VERSION 5.8 ;
BUSBITCHARS "[]" ;
DIVIDERCHAR "/" ;
UNITS
    DATABASE MICRONS 1000 ;
END UNITS

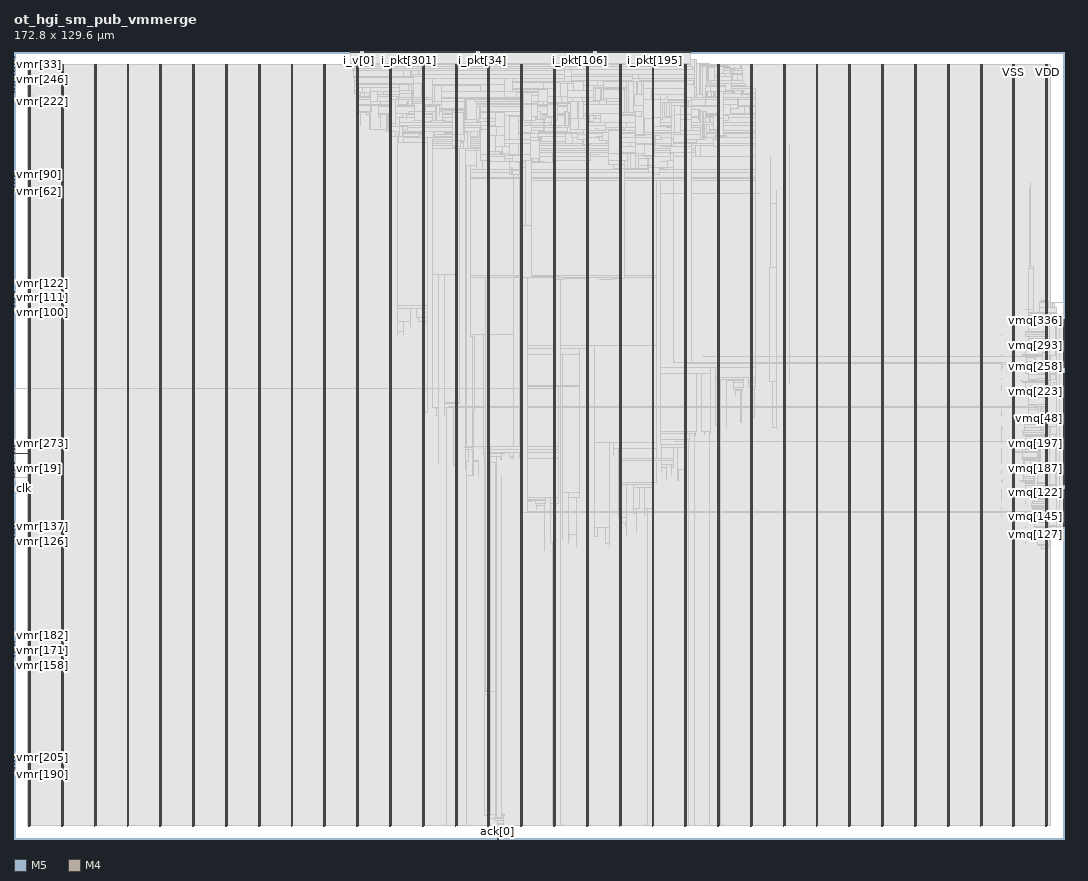
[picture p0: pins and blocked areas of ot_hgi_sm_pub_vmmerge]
MACRO ot_hgi_sm_pub_vmmerge
  FOREIGN ot_hgi_sm_pub_vmmerge 0 0 ;
  CLASS BLOCK ;
  SIZE 172.8 BY 129.6 ;
  PIN ack[0]
    DIRECTION OUTPUT ;
    USE SIGNAL ;
    PORT
      LAYER M5 ;
        RECT  79.632 0 79.656 0.084 ;
    END
  END ack[0]
  PIN ack[1]
    DIRECTION OUTPUT ;
    USE SIGNAL ;
    PORT
      LAYER M5 ;
        RECT  79.728 0 79.752 0.084 ;
    END
  END ack[1]
  PIN active
    DIRECTION OUTPUT ;
    USE SIGNAL ;
    PORT
      LAYER M4 ;
        RECT  172.716 70.608 172.8 70.632 ;
    END
  END active
  PIN clk
    DIRECTION INPUT ;
    USE SIGNAL ;
    PORT
      LAYER M4 ;
        RECT  0 58.992 0.084 59.016 ;
    END
  END clk
  PIN i_pkt[0]
    DIRECTION INPUT ;
    USE SIGNAL ;
    PORT
      LAYER M5 ;
        RECT  60.72 129.516 60.744 129.6 ;
    END
  END i_pkt[0]
  PIN i_pkt[100]
    DIRECTION INPUT ;
    USE SIGNAL ;
    PORT
      LAYER M5 ;
        RECT  92.592 129.516 92.616 129.6 ;
    END
  END i_pkt[100]
  PIN i_pkt[101]
    DIRECTION INPUT ;
    USE SIGNAL ;
    PORT
      LAYER M5 ;
        RECT  92.688 129.516 92.712 129.6 ;
    END
  END i_pkt[101]
  PIN i_pkt[102]
    DIRECTION INPUT ;
    USE SIGNAL ;
    PORT
      LAYER M5 ;
        RECT  92.784 129.516 92.808 129.6 ;
    END
  END i_pkt[102]
  PIN i_pkt[103]
    DIRECTION INPUT ;
    USE SIGNAL ;
    PORT
      LAYER M5 ;
        RECT  92.88 129.516 92.904 129.6 ;
    END
  END i_pkt[103]
  PIN i_pkt[104]
    DIRECTION INPUT ;
    USE SIGNAL ;
    PORT
      LAYER M5 ;
        RECT  92.976 129.516 93 129.6 ;
    END
  END i_pkt[104]
  PIN i_pkt[105]
    DIRECTION INPUT ;
    USE SIGNAL ;
    PORT
      LAYER M5 ;
        RECT  93.072 129.516 93.096 129.6 ;
    END
  END i_pkt[105]
  PIN i_pkt[106]
    DIRECTION INPUT ;
    USE SIGNAL ;
    PORT
      LAYER M5 ;
        RECT  93.168 129.516 93.192 129.6 ;
    END
  END i_pkt[106]
  PIN i_pkt[107]
    DIRECTION INPUT ;
    USE SIGNAL ;
    PORT
      LAYER M5 ;
        RECT  93.264 129.516 93.288 129.6 ;
    END
  END i_pkt[107]
  PIN i_pkt[108]
    DIRECTION INPUT ;
    USE SIGNAL ;
    PORT
      LAYER M5 ;
        RECT  93.36 129.516 93.384 129.6 ;
    END
  END i_pkt[108]
  PIN i_pkt[109]
    DIRECTION INPUT ;
    USE SIGNAL ;
    PORT
      LAYER M5 ;
        RECT  93.456 129.516 93.48 129.6 ;
    END
  END i_pkt[109]
  PIN i_pkt[10]
    DIRECTION INPUT ;
    USE SIGNAL ;
    PORT
      LAYER M5 ;
        RECT  61.68 129.516 61.704 129.6 ;
    END
  END i_pkt[10]
  PIN i_pkt[110]
    DIRECTION INPUT ;
    USE SIGNAL ;
    PORT
      LAYER M5 ;
        RECT  93.552 129.516 93.576 129.6 ;
    END
  END i_pkt[110]
  PIN i_pkt[111]
    DIRECTION INPUT ;
    USE SIGNAL ;
    PORT
      LAYER M5 ;
        RECT  93.648 129.516 93.672 129.6 ;
    END
  END i_pkt[111]
  PIN i_pkt[112]
    DIRECTION INPUT ;
    USE SIGNAL ;
    PORT
      LAYER M5 ;
        RECT  93.744 129.516 93.768 129.6 ;
    END
  END i_pkt[112]
  PIN i_pkt[113]
    DIRECTION INPUT ;
    USE SIGNAL ;
    PORT
      LAYER M5 ;
        RECT  93.84 129.516 93.864 129.6 ;
    END
  END i_pkt[113]
  PIN i_pkt[114]
    DIRECTION INPUT ;
    USE SIGNAL ;
    PORT
      LAYER M5 ;
        RECT  93.936 129.516 93.96 129.6 ;
    END
  END i_pkt[114]
  PIN i_pkt[115]
    DIRECTION INPUT ;
    USE SIGNAL ;
    PORT
      LAYER M5 ;
        RECT  94.032 129.516 94.056 129.6 ;
    END
  END i_pkt[115]
  PIN i_pkt[116]
    DIRECTION INPUT ;
    USE SIGNAL ;
    PORT
      LAYER M5 ;
        RECT  94.128 129.516 94.152 129.6 ;
    END
  END i_pkt[116]
  PIN i_pkt[117]
    DIRECTION INPUT ;
    USE SIGNAL ;
    PORT
      LAYER M5 ;
        RECT  94.224 129.516 94.248 129.6 ;
    END
  END i_pkt[117]
  PIN i_pkt[118]
    DIRECTION INPUT ;
    USE SIGNAL ;
    PORT
      LAYER M5 ;
        RECT  94.32 129.516 94.344 129.6 ;
    END
  END i_pkt[118]
  PIN i_pkt[119]
    DIRECTION INPUT ;
    USE SIGNAL ;
    PORT
      LAYER M5 ;
        RECT  94.416 129.516 94.44 129.6 ;
    END
  END i_pkt[119]
  PIN i_pkt[11]
    DIRECTION INPUT ;
    USE SIGNAL ;
    PORT
      LAYER M5 ;
        RECT  61.776 129.516 61.8 129.6 ;
    END
  END i_pkt[11]
  PIN i_pkt[120]
    DIRECTION INPUT ;
    USE SIGNAL ;
    PORT
      LAYER M5 ;
        RECT  94.512 129.516 94.536 129.6 ;
    END
  END i_pkt[120]
  PIN i_pkt[121]
    DIRECTION INPUT ;
    USE SIGNAL ;
    PORT
      LAYER M5 ;
        RECT  94.608 129.516 94.632 129.6 ;
    END
  END i_pkt[121]
  PIN i_pkt[122]
    DIRECTION INPUT ;
    USE SIGNAL ;
    PORT
      LAYER M5 ;
        RECT  94.704 129.516 94.728 129.6 ;
    END
  END i_pkt[122]
  PIN i_pkt[123]
    DIRECTION INPUT ;
    USE SIGNAL ;
    PORT
      LAYER M5 ;
        RECT  94.8 129.516 94.824 129.6 ;
    END
  END i_pkt[123]
  PIN i_pkt[124]
    DIRECTION INPUT ;
    USE SIGNAL ;
    PORT
      LAYER M5 ;
        RECT  94.896 129.516 94.92 129.6 ;
    END
  END i_pkt[124]
  PIN i_pkt[125]
    DIRECTION INPUT ;
    USE SIGNAL ;
    PORT
      LAYER M5 ;
        RECT  94.992 129.516 95.016 129.6 ;
    END
  END i_pkt[125]
  PIN i_pkt[126]
    DIRECTION INPUT ;
    USE SIGNAL ;
    PORT
      LAYER M5 ;
        RECT  95.088 129.516 95.112 129.6 ;
    END
  END i_pkt[126]
  PIN i_pkt[127]
    DIRECTION INPUT ;
    USE SIGNAL ;
    PORT
      LAYER M5 ;
        RECT  95.184 129.516 95.208 129.6 ;
    END
  END i_pkt[127]
  PIN i_pkt[128]
    DIRECTION INPUT ;
    USE SIGNAL ;
    PORT
      LAYER M5 ;
        RECT  86.064 129.516 86.088 129.6 ;
    END
  END i_pkt[128]
  PIN i_pkt[129]
    DIRECTION INPUT ;
    USE SIGNAL ;
    PORT
      LAYER M5 ;
        RECT  86.16 129.516 86.184 129.6 ;
    END
  END i_pkt[129]
  PIN i_pkt[12]
    DIRECTION INPUT ;
    USE SIGNAL ;
    PORT
      LAYER M5 ;
        RECT  61.872 129.516 61.896 129.6 ;
    END
  END i_pkt[12]
  PIN i_pkt[130]
    DIRECTION INPUT ;
    USE SIGNAL ;
    PORT
      LAYER M5 ;
        RECT  86.256 129.516 86.28 129.6 ;
    END
  END i_pkt[130]
  PIN i_pkt[131]
    DIRECTION INPUT ;
    USE SIGNAL ;
    PORT
      LAYER M5 ;
        RECT  86.352 129.516 86.376 129.6 ;
    END
  END i_pkt[131]
  PIN i_pkt[132]
    DIRECTION INPUT ;
    USE SIGNAL ;
    PORT
      LAYER M5 ;
        RECT  86.448 129.516 86.472 129.6 ;
    END
  END i_pkt[132]
  PIN i_pkt[133]
    DIRECTION INPUT ;
    USE SIGNAL ;
    PORT
      LAYER M5 ;
        RECT  86.544 129.516 86.568 129.6 ;
    END
  END i_pkt[133]
  PIN i_pkt[134]
    DIRECTION INPUT ;
    USE SIGNAL ;
    PORT
      LAYER M5 ;
        RECT  86.64 129.516 86.664 129.6 ;
    END
  END i_pkt[134]
  PIN i_pkt[135]
    DIRECTION INPUT ;
    USE SIGNAL ;
    PORT
      LAYER M5 ;
        RECT  86.736 129.516 86.76 129.6 ;
    END
  END i_pkt[135]
  PIN i_pkt[136]
    DIRECTION INPUT ;
    USE SIGNAL ;
    PORT
      LAYER M5 ;
        RECT  86.832 129.516 86.856 129.6 ;
    END
  END i_pkt[136]
  PIN i_pkt[137]
    DIRECTION INPUT ;
    USE SIGNAL ;
    PORT
      LAYER M5 ;
        RECT  86.928 129.516 86.952 129.6 ;
    END
  END i_pkt[137]
  PIN i_pkt[138]
    DIRECTION INPUT ;
    USE SIGNAL ;
    PORT
      LAYER M5 ;
        RECT  87.024 129.516 87.048 129.6 ;
    END
  END i_pkt[138]
  PIN i_pkt[139]
    DIRECTION INPUT ;
    USE SIGNAL ;
    PORT
      LAYER M5 ;
        RECT  87.12 129.516 87.144 129.6 ;
    END
  END i_pkt[139]
  PIN i_pkt[13]
    DIRECTION INPUT ;
    USE SIGNAL ;
    PORT
      LAYER M5 ;
        RECT  61.968 129.516 61.992 129.6 ;
    END
  END i_pkt[13]
  PIN i_pkt[140]
    DIRECTION INPUT ;
    USE SIGNAL ;
    PORT
      LAYER M5 ;
        RECT  87.216 129.516 87.24 129.6 ;
    END
  END i_pkt[140]
  PIN i_pkt[141]
    DIRECTION INPUT ;
    USE SIGNAL ;
    PORT
      LAYER M5 ;
        RECT  87.312 129.516 87.336 129.6 ;
    END
  END i_pkt[141]
  PIN i_pkt[142]
    DIRECTION INPUT ;
    USE SIGNAL ;
    PORT
      LAYER M5 ;
        RECT  87.408 129.516 87.432 129.6 ;
    END
  END i_pkt[142]
  PIN i_pkt[143]
    DIRECTION INPUT ;
    USE SIGNAL ;
    PORT
      LAYER M5 ;
        RECT  87.504 129.516 87.528 129.6 ;
    END
  END i_pkt[143]
  PIN i_pkt[144]
    DIRECTION INPUT ;
    USE SIGNAL ;
    PORT
      LAYER M5 ;
        RECT  87.6 129.516 87.624 129.6 ;
    END
  END i_pkt[144]
  PIN i_pkt[145]
    DIRECTION INPUT ;
    USE SIGNAL ;
    PORT
      LAYER M5 ;
        RECT  87.696 129.516 87.72 129.6 ;
    END
  END i_pkt[145]
  PIN i_pkt[146]
    DIRECTION INPUT ;
    USE SIGNAL ;
    PORT
      LAYER M5 ;
        RECT  87.792 129.516 87.816 129.6 ;
    END
  END i_pkt[146]
  PIN i_pkt[147]
    DIRECTION INPUT ;
    USE SIGNAL ;
    PORT
      LAYER M5 ;
        RECT  87.888 129.516 87.912 129.6 ;
    END
  END i_pkt[147]
  PIN i_pkt[148]
    DIRECTION INPUT ;
    USE SIGNAL ;
    PORT
      LAYER M5 ;
        RECT  87.984 129.516 88.008 129.6 ;
    END
  END i_pkt[148]
  PIN i_pkt[149]
    DIRECTION INPUT ;
    USE SIGNAL ;
    PORT
      LAYER M5 ;
        RECT  88.08 129.516 88.104 129.6 ;
    END
  END i_pkt[149]
  PIN i_pkt[14]
    DIRECTION INPUT ;
    USE SIGNAL ;
    PORT
      LAYER M5 ;
        RECT  62.064 129.516 62.088 129.6 ;
    END
  END i_pkt[14]
  PIN i_pkt[150]
    DIRECTION INPUT ;
    USE SIGNAL ;
    PORT
      LAYER M5 ;
        RECT  88.176 129.516 88.2 129.6 ;
    END
  END i_pkt[150]
  PIN i_pkt[151]
    DIRECTION INPUT ;
    USE SIGNAL ;
    PORT
      LAYER M5 ;
        RECT  88.272 129.516 88.296 129.6 ;
    END
  END i_pkt[151]
  PIN i_pkt[152]
    DIRECTION INPUT ;
    USE SIGNAL ;
    PORT
      LAYER M5 ;
        RECT  88.368 129.516 88.392 129.6 ;
    END
  END i_pkt[152]
  PIN i_pkt[153]
    DIRECTION INPUT ;
    USE SIGNAL ;
    PORT
      LAYER M5 ;
        RECT  88.464 129.516 88.488 129.6 ;
    END
  END i_pkt[153]
  PIN i_pkt[154]
    DIRECTION INPUT ;
    USE SIGNAL ;
    PORT
      LAYER M5 ;
        RECT  88.56 129.516 88.584 129.6 ;
    END
  END i_pkt[154]
  PIN i_pkt[155]
    DIRECTION INPUT ;
    USE SIGNAL ;
    PORT
      LAYER M5 ;
        RECT  88.656 129.516 88.68 129.6 ;
    END
  END i_pkt[155]
  PIN i_pkt[156]
    DIRECTION INPUT ;
    USE SIGNAL ;
    PORT
      LAYER M5 ;
        RECT  88.752 129.516 88.776 129.6 ;
    END
  END i_pkt[156]
  PIN i_pkt[157]
    DIRECTION INPUT ;
    USE SIGNAL ;
    PORT
      LAYER M5 ;
        RECT  88.848 129.516 88.872 129.6 ;
    END
  END i_pkt[157]
  PIN i_pkt[158]
    DIRECTION INPUT ;
    USE SIGNAL ;
    PORT
      LAYER M5 ;
        RECT  88.944 129.516 88.968 129.6 ;
    END
  END i_pkt[158]
  PIN i_pkt[159]
    DIRECTION INPUT ;
    USE SIGNAL ;
    PORT
      LAYER M5 ;
        RECT  89.04 129.516 89.064 129.6 ;
    END
  END i_pkt[159]
  PIN i_pkt[15]
    DIRECTION INPUT ;
    USE SIGNAL ;
    PORT
      LAYER M5 ;
        RECT  62.16 129.516 62.184 129.6 ;
    END
  END i_pkt[15]
  PIN i_pkt[160]
    DIRECTION INPUT ;
    USE SIGNAL ;
    PORT
      LAYER M5 ;
        RECT  89.136 129.516 89.16 129.6 ;
    END
  END i_pkt[160]
  PIN i_pkt[161]
    DIRECTION INPUT ;
    USE SIGNAL ;
    PORT
      LAYER M5 ;
        RECT  89.232 129.516 89.256 129.6 ;
    END
  END i_pkt[161]
  PIN i_pkt[162]
    DIRECTION INPUT ;
    USE SIGNAL ;
    PORT
      LAYER M5 ;
        RECT  89.328 129.516 89.352 129.6 ;
    END
  END i_pkt[162]
  PIN i_pkt[163]
    DIRECTION INPUT ;
    USE SIGNAL ;
    PORT
      LAYER M5 ;
        RECT  89.424 129.516 89.448 129.6 ;
    END
  END i_pkt[163]
  PIN i_pkt[164]
    DIRECTION INPUT ;
    USE SIGNAL ;
    PORT
      LAYER M5 ;
        RECT  89.52 129.516 89.544 129.6 ;
    END
  END i_pkt[164]
  PIN i_pkt[165]
    DIRECTION INPUT ;
    USE SIGNAL ;
    PORT
      LAYER M5 ;
        RECT  89.616 129.516 89.64 129.6 ;
    END
  END i_pkt[165]
  PIN i_pkt[166]
    DIRECTION INPUT ;
    USE SIGNAL ;
    PORT
      LAYER M5 ;
        RECT  89.712 129.516 89.736 129.6 ;
    END
  END i_pkt[166]
  PIN i_pkt[167]
    DIRECTION INPUT ;
    USE SIGNAL ;
    PORT
      LAYER M5 ;
        RECT  89.808 129.516 89.832 129.6 ;
    END
  END i_pkt[167]
  PIN i_pkt[168]
    DIRECTION INPUT ;
    USE SIGNAL ;
    PORT
      LAYER M5 ;
        RECT  89.904 129.516 89.928 129.6 ;
    END
  END i_pkt[168]
  PIN i_pkt[169]
    DIRECTION INPUT ;
    USE SIGNAL ;
    PORT
      LAYER M5 ;
        RECT  90 129.516 90.024 129.6 ;
    END
  END i_pkt[169]
  PIN i_pkt[16]
    DIRECTION INPUT ;
    USE SIGNAL ;
    PORT
      LAYER M5 ;
        RECT  62.256 129.516 62.28 129.6 ;
    END
  END i_pkt[16]
  PIN i_pkt[170]
    DIRECTION INPUT ;
    USE SIGNAL ;
    PORT
      LAYER M5 ;
        RECT  90.096 129.516 90.12 129.6 ;
    END
  END i_pkt[170]
  PIN i_pkt[171]
    DIRECTION INPUT ;
    USE SIGNAL ;
    PORT
      LAYER M5 ;
        RECT  90.192 129.516 90.216 129.6 ;
    END
  END i_pkt[171]
  PIN i_pkt[172]
    DIRECTION INPUT ;
    USE SIGNAL ;
    PORT
      LAYER M5 ;
        RECT  90.288 129.516 90.312 129.6 ;
    END
  END i_pkt[172]
  PIN i_pkt[173]
    DIRECTION INPUT ;
    USE SIGNAL ;
    PORT
      LAYER M5 ;
        RECT  90.384 129.516 90.408 129.6 ;
    END
  END i_pkt[173]
  PIN i_pkt[174]
    DIRECTION INPUT ;
    USE SIGNAL ;
    PORT
      LAYER M5 ;
        RECT  90.48 129.516 90.504 129.6 ;
    END
  END i_pkt[174]
  PIN i_pkt[175]
    DIRECTION INPUT ;
    USE SIGNAL ;
    PORT
      LAYER M5 ;
        RECT  90.576 129.516 90.6 129.6 ;
    END
  END i_pkt[175]
  PIN i_pkt[176]
    DIRECTION INPUT ;
    USE SIGNAL ;
    PORT
      LAYER M5 ;
        RECT  90.672 129.516 90.696 129.6 ;
    END
  END i_pkt[176]
  PIN i_pkt[177]
    DIRECTION INPUT ;
    USE SIGNAL ;
    PORT
      LAYER M5 ;
        RECT  90.768 129.516 90.792 129.6 ;
    END
  END i_pkt[177]
  PIN i_pkt[178]
    DIRECTION INPUT ;
    USE SIGNAL ;
    PORT
      LAYER M5 ;
        RECT  90.864 129.516 90.888 129.6 ;
    END
  END i_pkt[178]
  PIN i_pkt[179]
    DIRECTION INPUT ;
    USE SIGNAL ;
    PORT
      LAYER M5 ;
        RECT  90.96 129.516 90.984 129.6 ;
    END
  END i_pkt[179]
  PIN i_pkt[17]
    DIRECTION INPUT ;
    USE SIGNAL ;
    PORT
      LAYER M5 ;
        RECT  62.352 129.516 62.376 129.6 ;
    END
  END i_pkt[17]
  PIN i_pkt[180]
    DIRECTION INPUT ;
    USE SIGNAL ;
    PORT
      LAYER M5 ;
        RECT  91.056 129.516 91.08 129.6 ;
    END
  END i_pkt[180]
  PIN i_pkt[181]
    DIRECTION INPUT ;
    USE SIGNAL ;
    PORT
      LAYER M5 ;
        RECT  91.152 129.516 91.176 129.6 ;
    END
  END i_pkt[181]
  PIN i_pkt[182]
    DIRECTION INPUT ;
    USE SIGNAL ;
    PORT
      LAYER M5 ;
        RECT  91.248 129.516 91.272 129.6 ;
    END
  END i_pkt[182]
  PIN i_pkt[183]
    DIRECTION INPUT ;
    USE SIGNAL ;
    PORT
      LAYER M5 ;
        RECT  91.344 129.516 91.368 129.6 ;
    END
  END i_pkt[183]
  PIN i_pkt[184]
    DIRECTION INPUT ;
    USE SIGNAL ;
    PORT
      LAYER M5 ;
        RECT  91.44 129.516 91.464 129.6 ;
    END
  END i_pkt[184]
  PIN i_pkt[185]
    DIRECTION INPUT ;
    USE SIGNAL ;
    PORT
      LAYER M5 ;
        RECT  91.536 129.516 91.56 129.6 ;
    END
  END i_pkt[185]
  PIN i_pkt[186]
    DIRECTION INPUT ;
    USE SIGNAL ;
    PORT
      LAYER M5 ;
        RECT  91.632 129.516 91.656 129.6 ;
    END
  END i_pkt[186]
  PIN i_pkt[187]
    DIRECTION INPUT ;
    USE SIGNAL ;
    PORT
      LAYER M5 ;
        RECT  91.728 129.516 91.752 129.6 ;
    END
  END i_pkt[187]
  PIN i_pkt[188]
    DIRECTION INPUT ;
    USE SIGNAL ;
    PORT
      LAYER M5 ;
        RECT  91.824 129.516 91.848 129.6 ;
    END
  END i_pkt[188]
  PIN i_pkt[189]
    DIRECTION INPUT ;
    USE SIGNAL ;
    PORT
      LAYER M5 ;
        RECT  91.92 129.516 91.944 129.6 ;
    END
  END i_pkt[189]
  PIN i_pkt[18]
    DIRECTION INPUT ;
    USE SIGNAL ;
    PORT
      LAYER M5 ;
        RECT  62.448 129.516 62.472 129.6 ;
    END
  END i_pkt[18]
  PIN i_pkt[190]
    DIRECTION INPUT ;
    USE SIGNAL ;
    PORT
      LAYER M5 ;
        RECT  92.016 129.516 92.04 129.6 ;
    END
  END i_pkt[190]
  PIN i_pkt[191]
    DIRECTION INPUT ;
    USE SIGNAL ;
    PORT
      LAYER M5 ;
        RECT  92.112 129.516 92.136 129.6 ;
    END
  END i_pkt[191]
  PIN i_pkt[192]
    DIRECTION INPUT ;
    USE SIGNAL ;
    PORT
      LAYER M5 ;
        RECT  105.264 129.516 105.288 129.6 ;
    END
  END i_pkt[192]
  PIN i_pkt[193]
    DIRECTION INPUT ;
    USE SIGNAL ;
    PORT
      LAYER M5 ;
        RECT  105.36 129.516 105.384 129.6 ;
    END
  END i_pkt[193]
  PIN i_pkt[194]
    DIRECTION INPUT ;
    USE SIGNAL ;
    PORT
      LAYER M5 ;
        RECT  105.456 129.516 105.48 129.6 ;
    END
  END i_pkt[194]
  PIN i_pkt[195]
    DIRECTION INPUT ;
    USE SIGNAL ;
    PORT
      LAYER M5 ;
        RECT  105.552 129.516 105.576 129.6 ;
    END
  END i_pkt[195]
  PIN i_pkt[196]
    DIRECTION INPUT ;
    USE SIGNAL ;
    PORT
      LAYER M5 ;
        RECT  105.648 129.516 105.672 129.6 ;
    END
  END i_pkt[196]
  PIN i_pkt[197]
    DIRECTION INPUT ;
    USE SIGNAL ;
    PORT
      LAYER M5 ;
        RECT  105.744 129.516 105.768 129.6 ;
    END
  END i_pkt[197]
  PIN i_pkt[198]
    DIRECTION INPUT ;
    USE SIGNAL ;
    PORT
      LAYER M5 ;
        RECT  105.84 129.516 105.864 129.6 ;
    END
  END i_pkt[198]
  PIN i_pkt[199]
    DIRECTION INPUT ;
    USE SIGNAL ;
    PORT
      LAYER M5 ;
        RECT  105.936 129.516 105.96 129.6 ;
    END
  END i_pkt[199]
  PIN i_pkt[19]
    DIRECTION INPUT ;
    USE SIGNAL ;
    PORT
      LAYER M5 ;
        RECT  62.544 129.516 62.568 129.6 ;
    END
  END i_pkt[19]
  PIN i_pkt[1]
    DIRECTION INPUT ;
    USE SIGNAL ;
    PORT
      LAYER M5 ;
        RECT  60.816 129.516 60.84 129.6 ;
    END
  END i_pkt[1]
  PIN i_pkt[200]
    DIRECTION INPUT ;
    USE SIGNAL ;
    PORT
      LAYER M5 ;
        RECT  106.032 129.516 106.056 129.6 ;
    END
  END i_pkt[200]
  PIN i_pkt[201]
    DIRECTION INPUT ;
    USE SIGNAL ;
    PORT
      LAYER M5 ;
        RECT  106.128 129.516 106.152 129.6 ;
    END
  END i_pkt[201]
  PIN i_pkt[202]
    DIRECTION INPUT ;
    USE SIGNAL ;
    PORT
      LAYER M5 ;
        RECT  106.224 129.516 106.248 129.6 ;
    END
  END i_pkt[202]
  PIN i_pkt[203]
    DIRECTION INPUT ;
    USE SIGNAL ;
    PORT
      LAYER M5 ;
        RECT  106.32 129.516 106.344 129.6 ;
    END
  END i_pkt[203]
  PIN i_pkt[204]
    DIRECTION INPUT ;
    USE SIGNAL ;
    PORT
      LAYER M5 ;
        RECT  106.416 129.516 106.44 129.6 ;
    END
  END i_pkt[204]
  PIN i_pkt[205]
    DIRECTION INPUT ;
    USE SIGNAL ;
    PORT
      LAYER M5 ;
        RECT  106.512 129.516 106.536 129.6 ;
    END
  END i_pkt[205]
  PIN i_pkt[206]
    DIRECTION INPUT ;
    USE SIGNAL ;
    PORT
      LAYER M5 ;
        RECT  106.608 129.516 106.632 129.6 ;
    END
  END i_pkt[206]
  PIN i_pkt[207]
    DIRECTION INPUT ;
    USE SIGNAL ;
    PORT
      LAYER M5 ;
        RECT  106.704 129.516 106.728 129.6 ;
    END
  END i_pkt[207]
  PIN i_pkt[208]
    DIRECTION INPUT ;
    USE SIGNAL ;
    PORT
      LAYER M5 ;
        RECT  106.8 129.516 106.824 129.6 ;
    END
  END i_pkt[208]
  PIN i_pkt[209]
    DIRECTION INPUT ;
    USE SIGNAL ;
    PORT
      LAYER M5 ;
        RECT  106.896 129.516 106.92 129.6 ;
    END
  END i_pkt[209]
  PIN i_pkt[20]
    DIRECTION INPUT ;
    USE SIGNAL ;
    PORT
      LAYER M5 ;
        RECT  62.64 129.516 62.664 129.6 ;
    END
  END i_pkt[20]
  PIN i_pkt[210]
    DIRECTION INPUT ;
    USE SIGNAL ;
    PORT
      LAYER M5 ;
        RECT  106.992 129.516 107.016 129.6 ;
    END
  END i_pkt[210]
  PIN i_pkt[211]
    DIRECTION INPUT ;
    USE SIGNAL ;
    PORT
      LAYER M5 ;
        RECT  107.088 129.516 107.112 129.6 ;
    END
  END i_pkt[211]
  PIN i_pkt[212]
    DIRECTION INPUT ;
    USE SIGNAL ;
    PORT
      LAYER M5 ;
        RECT  107.184 129.516 107.208 129.6 ;
    END
  END i_pkt[212]
  PIN i_pkt[213]
    DIRECTION INPUT ;
    USE SIGNAL ;
    PORT
      LAYER M5 ;
        RECT  107.28 129.516 107.304 129.6 ;
    END
  END i_pkt[213]
  PIN i_pkt[214]
    DIRECTION INPUT ;
    USE SIGNAL ;
    PORT
      LAYER M5 ;
        RECT  107.376 129.516 107.4 129.6 ;
    END
  END i_pkt[214]
  PIN i_pkt[215]
    DIRECTION INPUT ;
    USE SIGNAL ;
    PORT
      LAYER M5 ;
        RECT  107.472 129.516 107.496 129.6 ;
    END
  END i_pkt[215]
  PIN i_pkt[216]
    DIRECTION INPUT ;
    USE SIGNAL ;
    PORT
      LAYER M5 ;
        RECT  107.568 129.516 107.592 129.6 ;
    END
  END i_pkt[216]
  PIN i_pkt[217]
    DIRECTION INPUT ;
    USE SIGNAL ;
    PORT
      LAYER M5 ;
        RECT  107.664 129.516 107.688 129.6 ;
    END
  END i_pkt[217]
  PIN i_pkt[218]
    DIRECTION INPUT ;
    USE SIGNAL ;
    PORT
      LAYER M5 ;
        RECT  107.76 129.516 107.784 129.6 ;
    END
  END i_pkt[218]
  PIN i_pkt[219]
    DIRECTION INPUT ;
    USE SIGNAL ;
    PORT
      LAYER M5 ;
        RECT  107.856 129.516 107.88 129.6 ;
    END
  END i_pkt[219]
  PIN i_pkt[21]
    DIRECTION INPUT ;
    USE SIGNAL ;
    PORT
      LAYER M5 ;
        RECT  62.736 129.516 62.76 129.6 ;
    END
  END i_pkt[21]
  PIN i_pkt[220]
    DIRECTION INPUT ;
    USE SIGNAL ;
    PORT
      LAYER M5 ;
        RECT  107.952 129.516 107.976 129.6 ;
    END
  END i_pkt[220]
  PIN i_pkt[221]
    DIRECTION INPUT ;
    USE SIGNAL ;
    PORT
      LAYER M5 ;
        RECT  108.048 129.516 108.072 129.6 ;
    END
  END i_pkt[221]
  PIN i_pkt[222]
    DIRECTION INPUT ;
    USE SIGNAL ;
    PORT
      LAYER M5 ;
        RECT  108.144 129.516 108.168 129.6 ;
    END
  END i_pkt[222]
  PIN i_pkt[223]
    DIRECTION INPUT ;
    USE SIGNAL ;
    PORT
      LAYER M5 ;
        RECT  108.24 129.516 108.264 129.6 ;
    END
  END i_pkt[223]
  PIN i_pkt[224]
    DIRECTION INPUT ;
    USE SIGNAL ;
    PORT
      LAYER M5 ;
        RECT  82.992 129.516 83.016 129.6 ;
    END
  END i_pkt[224]
  PIN i_pkt[225]
    DIRECTION INPUT ;
    USE SIGNAL ;
    PORT
      LAYER M5 ;
        RECT  83.088 129.516 83.112 129.6 ;
    END
  END i_pkt[225]
  PIN i_pkt[226]
    DIRECTION INPUT ;
    USE SIGNAL ;
    PORT
      LAYER M5 ;
        RECT  83.184 129.516 83.208 129.6 ;
    END
  END i_pkt[226]
  PIN i_pkt[227]
    DIRECTION INPUT ;
    USE SIGNAL ;
    PORT
      LAYER M5 ;
        RECT  83.28 129.516 83.304 129.6 ;
    END
  END i_pkt[227]
  PIN i_pkt[228]
    DIRECTION INPUT ;
    USE SIGNAL ;
    PORT
      LAYER M5 ;
        RECT  83.376 129.516 83.4 129.6 ;
    END
  END i_pkt[228]
  PIN i_pkt[229]
    DIRECTION INPUT ;
    USE SIGNAL ;
    PORT
      LAYER M5 ;
        RECT  83.472 129.516 83.496 129.6 ;
    END
  END i_pkt[229]
  PIN i_pkt[22]
    DIRECTION INPUT ;
    USE SIGNAL ;
    PORT
      LAYER M5 ;
        RECT  62.832 129.516 62.856 129.6 ;
    END
  END i_pkt[22]
  PIN i_pkt[230]
    DIRECTION INPUT ;
    USE SIGNAL ;
    PORT
      LAYER M5 ;
        RECT  83.568 129.516 83.592 129.6 ;
    END
  END i_pkt[230]
  PIN i_pkt[231]
    DIRECTION INPUT ;
    USE SIGNAL ;
    PORT
      LAYER M5 ;
        RECT  83.664 129.516 83.688 129.6 ;
    END
  END i_pkt[231]
  PIN i_pkt[232]
    DIRECTION INPUT ;
    USE SIGNAL ;
    PORT
      LAYER M5 ;
        RECT  83.76 129.516 83.784 129.6 ;
    END
  END i_pkt[232]
  PIN i_pkt[233]
    DIRECTION INPUT ;
    USE SIGNAL ;
    PORT
      LAYER M5 ;
        RECT  83.856 129.516 83.88 129.6 ;
    END
  END i_pkt[233]
  PIN i_pkt[234]
    DIRECTION INPUT ;
    USE SIGNAL ;
    PORT
      LAYER M5 ;
        RECT  83.952 129.516 83.976 129.6 ;
    END
  END i_pkt[234]
  PIN i_pkt[235]
    DIRECTION INPUT ;
    USE SIGNAL ;
    PORT
      LAYER M5 ;
        RECT  84.048 129.516 84.072 129.6 ;
    END
  END i_pkt[235]
  PIN i_pkt[236]
    DIRECTION INPUT ;
    USE SIGNAL ;
    PORT
      LAYER M5 ;
        RECT  84.144 129.516 84.168 129.6 ;
    END
  END i_pkt[236]
  PIN i_pkt[237]
    DIRECTION INPUT ;
    USE SIGNAL ;
    PORT
      LAYER M5 ;
        RECT  84.24 129.516 84.264 129.6 ;
    END
  END i_pkt[237]
  PIN i_pkt[238]
    DIRECTION INPUT ;
    USE SIGNAL ;
    PORT
      LAYER M5 ;
        RECT  84.336 129.516 84.36 129.6 ;
    END
  END i_pkt[238]
  PIN i_pkt[239]
    DIRECTION INPUT ;
    USE SIGNAL ;
    PORT
      LAYER M5 ;
        RECT  84.432 129.516 84.456 129.6 ;
    END
  END i_pkt[239]
  PIN i_pkt[23]
    DIRECTION INPUT ;
    USE SIGNAL ;
    PORT
      LAYER M5 ;
        RECT  62.928 129.516 62.952 129.6 ;
    END
  END i_pkt[23]
  PIN i_pkt[240]
    DIRECTION INPUT ;
    USE SIGNAL ;
    PORT
      LAYER M5 ;
        RECT  84.528 129.516 84.552 129.6 ;
    END
  END i_pkt[240]
  PIN i_pkt[241]
    DIRECTION INPUT ;
    USE SIGNAL ;
    PORT
      LAYER M5 ;
        RECT  84.624 129.516 84.648 129.6 ;
    END
  END i_pkt[241]
  PIN i_pkt[242]
    DIRECTION INPUT ;
    USE SIGNAL ;
    PORT
      LAYER M5 ;
        RECT  84.72 129.516 84.744 129.6 ;
    END
  END i_pkt[242]
  PIN i_pkt[243]
    DIRECTION INPUT ;
    USE SIGNAL ;
    PORT
      LAYER M5 ;
        RECT  84.816 129.516 84.84 129.6 ;
    END
  END i_pkt[243]
  PIN i_pkt[244]
    DIRECTION INPUT ;
    USE SIGNAL ;
    PORT
      LAYER M5 ;
        RECT  84.912 129.516 84.936 129.6 ;
    END
  END i_pkt[244]
  PIN i_pkt[245]
    DIRECTION INPUT ;
    USE SIGNAL ;
    PORT
      LAYER M5 ;
        RECT  85.008 129.516 85.032 129.6 ;
    END
  END i_pkt[245]
  PIN i_pkt[246]
    DIRECTION INPUT ;
    USE SIGNAL ;
    PORT
      LAYER M5 ;
        RECT  85.104 129.516 85.128 129.6 ;
    END
  END i_pkt[246]
  PIN i_pkt[247]
    DIRECTION INPUT ;
    USE SIGNAL ;
    PORT
      LAYER M5 ;
        RECT  85.2 129.516 85.224 129.6 ;
    END
  END i_pkt[247]
  PIN i_pkt[248]
    DIRECTION INPUT ;
    USE SIGNAL ;
    PORT
      LAYER M5 ;
        RECT  85.296 129.516 85.32 129.6 ;
    END
  END i_pkt[248]
  PIN i_pkt[249]
    DIRECTION INPUT ;
    USE SIGNAL ;
    PORT
      LAYER M5 ;
        RECT  85.392 129.516 85.416 129.6 ;
    END
  END i_pkt[249]
  PIN i_pkt[24]
    DIRECTION INPUT ;
    USE SIGNAL ;
    PORT
      LAYER M5 ;
        RECT  63.024 129.516 63.048 129.6 ;
    END
  END i_pkt[24]
  PIN i_pkt[250]
    DIRECTION INPUT ;
    USE SIGNAL ;
    PORT
      LAYER M5 ;
        RECT  85.488 129.516 85.512 129.6 ;
    END
  END i_pkt[250]
  PIN i_pkt[251]
    DIRECTION INPUT ;
    USE SIGNAL ;
    PORT
      LAYER M5 ;
        RECT  85.584 129.516 85.608 129.6 ;
    END
  END i_pkt[251]
  PIN i_pkt[252]
    DIRECTION INPUT ;
    USE SIGNAL ;
    PORT
      LAYER M5 ;
        RECT  85.68 129.516 85.704 129.6 ;
    END
  END i_pkt[252]
  PIN i_pkt[253]
    DIRECTION INPUT ;
    USE SIGNAL ;
    PORT
      LAYER M5 ;
        RECT  85.776 129.516 85.8 129.6 ;
    END
  END i_pkt[253]
  PIN i_pkt[254]
    DIRECTION INPUT ;
    USE SIGNAL ;
    PORT
      LAYER M5 ;
        RECT  85.872 129.516 85.896 129.6 ;
    END
  END i_pkt[254]
  PIN i_pkt[255]
    DIRECTION INPUT ;
    USE SIGNAL ;
    PORT
      LAYER M5 ;
        RECT  85.968 129.516 85.992 129.6 ;
    END
  END i_pkt[255]
  PIN i_pkt[256]
    DIRECTION INPUT ;
    USE SIGNAL ;
    PORT
      LAYER M5 ;
        RECT  57.648 129.516 57.672 129.6 ;
    END
  END i_pkt[256]
  PIN i_pkt[257]
    DIRECTION INPUT ;
    USE SIGNAL ;
    PORT
      LAYER M5 ;
        RECT  57.744 129.516 57.768 129.6 ;
    END
  END i_pkt[257]
  PIN i_pkt[258]
    DIRECTION INPUT ;
    USE SIGNAL ;
    PORT
      LAYER M5 ;
        RECT  57.84 129.516 57.864 129.6 ;
    END
  END i_pkt[258]
  PIN i_pkt[259]
    DIRECTION INPUT ;
    USE SIGNAL ;
    PORT
      LAYER M5 ;
        RECT  57.936 129.516 57.96 129.6 ;
    END
  END i_pkt[259]
  PIN i_pkt[25]
    DIRECTION INPUT ;
    USE SIGNAL ;
    PORT
      LAYER M5 ;
        RECT  63.12 129.516 63.144 129.6 ;
    END
  END i_pkt[25]
  PIN i_pkt[260]
    DIRECTION INPUT ;
    USE SIGNAL ;
    PORT
      LAYER M5 ;
        RECT  58.032 129.516 58.056 129.6 ;
    END
  END i_pkt[260]
  PIN i_pkt[261]
    DIRECTION INPUT ;
    USE SIGNAL ;
    PORT
      LAYER M5 ;
        RECT  58.128 129.516 58.152 129.6 ;
    END
  END i_pkt[261]
  PIN i_pkt[262]
    DIRECTION INPUT ;
    USE SIGNAL ;
    PORT
      LAYER M5 ;
        RECT  58.224 129.516 58.248 129.6 ;
    END
  END i_pkt[262]
  PIN i_pkt[263]
    DIRECTION INPUT ;
    USE SIGNAL ;
    PORT
      LAYER M5 ;
        RECT  58.32 129.516 58.344 129.6 ;
    END
  END i_pkt[263]
  PIN i_pkt[264]
    DIRECTION INPUT ;
    USE SIGNAL ;
    PORT
      LAYER M5 ;
        RECT  58.416 129.516 58.44 129.6 ;
    END
  END i_pkt[264]
  PIN i_pkt[265]
    DIRECTION INPUT ;
    USE SIGNAL ;
    PORT
      LAYER M5 ;
        RECT  58.512 129.516 58.536 129.6 ;
    END
  END i_pkt[265]
  PIN i_pkt[266]
    DIRECTION INPUT ;
    USE SIGNAL ;
    PORT
      LAYER M5 ;
        RECT  58.608 129.516 58.632 129.6 ;
    END
  END i_pkt[266]
  PIN i_pkt[267]
    DIRECTION INPUT ;
    USE SIGNAL ;
    PORT
      LAYER M5 ;
        RECT  58.704 129.516 58.728 129.6 ;
    END
  END i_pkt[267]
  PIN i_pkt[268]
    DIRECTION INPUT ;
    USE SIGNAL ;
    PORT
      LAYER M5 ;
        RECT  58.8 129.516 58.824 129.6 ;
    END
  END i_pkt[268]
  PIN i_pkt[269]
    DIRECTION INPUT ;
    USE SIGNAL ;
    PORT
      LAYER M5 ;
        RECT  58.896 129.516 58.92 129.6 ;
    END
  END i_pkt[269]
  PIN i_pkt[26]
    DIRECTION INPUT ;
    USE SIGNAL ;
    PORT
      LAYER M5 ;
        RECT  63.216 129.516 63.24 129.6 ;
    END
  END i_pkt[26]
  PIN i_pkt[270]
    DIRECTION INPUT ;
    USE SIGNAL ;
    PORT
      LAYER M5 ;
        RECT  58.992 129.516 59.016 129.6 ;
    END
  END i_pkt[270]
  PIN i_pkt[271]
    DIRECTION INPUT ;
    USE SIGNAL ;
    PORT
      LAYER M5 ;
        RECT  59.088 129.516 59.112 129.6 ;
    END
  END i_pkt[271]
  PIN i_pkt[272]
    DIRECTION INPUT ;
    USE SIGNAL ;
    PORT
      LAYER M5 ;
        RECT  59.184 129.516 59.208 129.6 ;
    END
  END i_pkt[272]
  PIN i_pkt[273]
    DIRECTION INPUT ;
    USE SIGNAL ;
    PORT
      LAYER M5 ;
        RECT  59.28 129.516 59.304 129.6 ;
    END
  END i_pkt[273]
  PIN i_pkt[274]
    DIRECTION INPUT ;
    USE SIGNAL ;
    PORT
      LAYER M5 ;
        RECT  59.376 129.516 59.4 129.6 ;
    END
  END i_pkt[274]
  PIN i_pkt[275]
    DIRECTION INPUT ;
    USE SIGNAL ;
    PORT
      LAYER M5 ;
        RECT  59.472 129.516 59.496 129.6 ;
    END
  END i_pkt[275]
  PIN i_pkt[276]
    DIRECTION INPUT ;
    USE SIGNAL ;
    PORT
      LAYER M5 ;
        RECT  59.568 129.516 59.592 129.6 ;
    END
  END i_pkt[276]
  PIN i_pkt[277]
    DIRECTION INPUT ;
    USE SIGNAL ;
    PORT
      LAYER M5 ;
        RECT  59.664 129.516 59.688 129.6 ;
    END
  END i_pkt[277]
  PIN i_pkt[278]
    DIRECTION INPUT ;
    USE SIGNAL ;
    PORT
      LAYER M5 ;
        RECT  59.76 129.516 59.784 129.6 ;
    END
  END i_pkt[278]
  PIN i_pkt[279]
    DIRECTION INPUT ;
    USE SIGNAL ;
    PORT
      LAYER M5 ;
        RECT  59.856 129.516 59.88 129.6 ;
    END
  END i_pkt[279]
  PIN i_pkt[27]
    DIRECTION INPUT ;
    USE SIGNAL ;
    PORT
      LAYER M5 ;
        RECT  63.312 129.516 63.336 129.6 ;
    END
  END i_pkt[27]
  PIN i_pkt[280]
    DIRECTION INPUT ;
    USE SIGNAL ;
    PORT
      LAYER M5 ;
        RECT  59.952 129.516 59.976 129.6 ;
    END
  END i_pkt[280]
  PIN i_pkt[281]
    DIRECTION INPUT ;
    USE SIGNAL ;
    PORT
      LAYER M5 ;
        RECT  60.048 129.516 60.072 129.6 ;
    END
  END i_pkt[281]
  PIN i_pkt[282]
    DIRECTION INPUT ;
    USE SIGNAL ;
    PORT
      LAYER M5 ;
        RECT  60.144 129.516 60.168 129.6 ;
    END
  END i_pkt[282]
  PIN i_pkt[283]
    DIRECTION INPUT ;
    USE SIGNAL ;
    PORT
      LAYER M5 ;
        RECT  60.24 129.516 60.264 129.6 ;
    END
  END i_pkt[283]
  PIN i_pkt[284]
    DIRECTION INPUT ;
    USE SIGNAL ;
    PORT
      LAYER M5 ;
        RECT  60.336 129.516 60.36 129.6 ;
    END
  END i_pkt[284]
  PIN i_pkt[285]
    DIRECTION INPUT ;
    USE SIGNAL ;
    PORT
      LAYER M5 ;
        RECT  60.432 129.516 60.456 129.6 ;
    END
  END i_pkt[285]
  PIN i_pkt[286]
    DIRECTION INPUT ;
    USE SIGNAL ;
    PORT
      LAYER M5 ;
        RECT  60.528 129.516 60.552 129.6 ;
    END
  END i_pkt[286]
  PIN i_pkt[287]
    DIRECTION INPUT ;
    USE SIGNAL ;
    PORT
      LAYER M5 ;
        RECT  60.624 129.516 60.648 129.6 ;
    END
  END i_pkt[287]
  PIN i_pkt[288]
    DIRECTION INPUT ;
    USE SIGNAL ;
    PORT
      LAYER M5 ;
        RECT  63.792 129.516 63.816 129.6 ;
    END
  END i_pkt[288]
  PIN i_pkt[289]
    DIRECTION INPUT ;
    USE SIGNAL ;
    PORT
      LAYER M5 ;
        RECT  63.888 129.516 63.912 129.6 ;
    END
  END i_pkt[289]
  PIN i_pkt[28]
    DIRECTION INPUT ;
    USE SIGNAL ;
    PORT
      LAYER M5 ;
        RECT  63.408 129.516 63.432 129.6 ;
    END
  END i_pkt[28]
  PIN i_pkt[290]
    DIRECTION INPUT ;
    USE SIGNAL ;
    PORT
      LAYER M5 ;
        RECT  63.984 129.516 64.008 129.6 ;
    END
  END i_pkt[290]
  PIN i_pkt[291]
    DIRECTION INPUT ;
    USE SIGNAL ;
    PORT
      LAYER M5 ;
        RECT  64.08 129.516 64.104 129.6 ;
    END
  END i_pkt[291]
  PIN i_pkt[292]
    DIRECTION INPUT ;
    USE SIGNAL ;
    PORT
      LAYER M5 ;
        RECT  64.176 129.516 64.2 129.6 ;
    END
  END i_pkt[292]
  PIN i_pkt[293]
    DIRECTION INPUT ;
    USE SIGNAL ;
    PORT
      LAYER M5 ;
        RECT  64.272 129.516 64.296 129.6 ;
    END
  END i_pkt[293]
  PIN i_pkt[294]
    DIRECTION INPUT ;
    USE SIGNAL ;
    PORT
      LAYER M5 ;
        RECT  64.368 129.516 64.392 129.6 ;
    END
  END i_pkt[294]
  PIN i_pkt[295]
    DIRECTION INPUT ;
    USE SIGNAL ;
    PORT
      LAYER M5 ;
        RECT  64.464 129.516 64.488 129.6 ;
    END
  END i_pkt[295]
  PIN i_pkt[296]
    DIRECTION INPUT ;
    USE SIGNAL ;
    PORT
      LAYER M5 ;
        RECT  64.56 129.516 64.584 129.6 ;
    END
  END i_pkt[296]
  PIN i_pkt[297]
    DIRECTION INPUT ;
    USE SIGNAL ;
    PORT
      LAYER M5 ;
        RECT  64.656 129.516 64.68 129.6 ;
    END
  END i_pkt[297]
  PIN i_pkt[298]
    DIRECTION INPUT ;
    USE SIGNAL ;
    PORT
      LAYER M5 ;
        RECT  64.752 129.516 64.776 129.6 ;
    END
  END i_pkt[298]
  PIN i_pkt[299]
    DIRECTION INPUT ;
    USE SIGNAL ;
    PORT
      LAYER M5 ;
        RECT  64.848 129.516 64.872 129.6 ;
    END
  END i_pkt[299]
  PIN i_pkt[29]
    DIRECTION INPUT ;
    USE SIGNAL ;
    PORT
      LAYER M5 ;
        RECT  63.504 129.516 63.528 129.6 ;
    END
  END i_pkt[29]
  PIN i_pkt[2]
    DIRECTION INPUT ;
    USE SIGNAL ;
    PORT
      LAYER M5 ;
        RECT  60.912 129.516 60.936 129.6 ;
    END
  END i_pkt[2]
  PIN i_pkt[300]
    DIRECTION INPUT ;
    USE SIGNAL ;
    PORT
      LAYER M5 ;
        RECT  64.944 129.516 64.968 129.6 ;
    END
  END i_pkt[300]
  PIN i_pkt[301]
    DIRECTION INPUT ;
    USE SIGNAL ;
    PORT
      LAYER M5 ;
        RECT  65.04 129.516 65.064 129.6 ;
    END
  END i_pkt[301]
  PIN i_pkt[302]
    DIRECTION INPUT ;
    USE SIGNAL ;
    PORT
      LAYER M5 ;
        RECT  65.136 129.516 65.16 129.6 ;
    END
  END i_pkt[302]
  PIN i_pkt[303]
    DIRECTION INPUT ;
    USE SIGNAL ;
    PORT
      LAYER M5 ;
        RECT  65.232 129.516 65.256 129.6 ;
    END
  END i_pkt[303]
  PIN i_pkt[304]
    DIRECTION INPUT ;
    USE SIGNAL ;
    PORT
      LAYER M5 ;
        RECT  65.328 129.516 65.352 129.6 ;
    END
  END i_pkt[304]
  PIN i_pkt[305]
    DIRECTION INPUT ;
    USE SIGNAL ;
    PORT
      LAYER M5 ;
        RECT  65.424 129.516 65.448 129.6 ;
    END
  END i_pkt[305]
  PIN i_pkt[306]
    DIRECTION INPUT ;
    USE SIGNAL ;
    PORT
      LAYER M5 ;
        RECT  65.52 129.516 65.544 129.6 ;
    END
  END i_pkt[306]
  PIN i_pkt[307]
    DIRECTION INPUT ;
    USE SIGNAL ;
    PORT
      LAYER M5 ;
        RECT  65.616 129.516 65.64 129.6 ;
    END
  END i_pkt[307]
  PIN i_pkt[308]
    DIRECTION INPUT ;
    USE SIGNAL ;
    PORT
      LAYER M5 ;
        RECT  65.712 129.516 65.736 129.6 ;
    END
  END i_pkt[308]
  PIN i_pkt[309]
    DIRECTION INPUT ;
    USE SIGNAL ;
    PORT
      LAYER M5 ;
        RECT  65.808 129.516 65.832 129.6 ;
    END
  END i_pkt[309]
  PIN i_pkt[30]
    DIRECTION INPUT ;
    USE SIGNAL ;
    PORT
      LAYER M5 ;
        RECT  63.6 129.516 63.624 129.6 ;
    END
  END i_pkt[30]
  PIN i_pkt[310]
    DIRECTION INPUT ;
    USE SIGNAL ;
    PORT
      LAYER M5 ;
        RECT  65.904 129.516 65.928 129.6 ;
    END
  END i_pkt[310]
  PIN i_pkt[311]
    DIRECTION INPUT ;
    USE SIGNAL ;
    PORT
      LAYER M5 ;
        RECT  66 129.516 66.024 129.6 ;
    END
  END i_pkt[311]
  PIN i_pkt[312]
    DIRECTION INPUT ;
    USE SIGNAL ;
    PORT
      LAYER M5 ;
        RECT  66.096 129.516 66.12 129.6 ;
    END
  END i_pkt[312]
  PIN i_pkt[313]
    DIRECTION INPUT ;
    USE SIGNAL ;
    PORT
      LAYER M5 ;
        RECT  66.192 129.516 66.216 129.6 ;
    END
  END i_pkt[313]
  PIN i_pkt[314]
    DIRECTION INPUT ;
    USE SIGNAL ;
    PORT
      LAYER M5 ;
        RECT  66.288 129.516 66.312 129.6 ;
    END
  END i_pkt[314]
  PIN i_pkt[315]
    DIRECTION INPUT ;
    USE SIGNAL ;
    PORT
      LAYER M5 ;
        RECT  66.384 129.516 66.408 129.6 ;
    END
  END i_pkt[315]
  PIN i_pkt[316]
    DIRECTION INPUT ;
    USE SIGNAL ;
    PORT
      LAYER M5 ;
        RECT  66.48 129.516 66.504 129.6 ;
    END
  END i_pkt[316]
  PIN i_pkt[317]
    DIRECTION INPUT ;
    USE SIGNAL ;
    PORT
      LAYER M5 ;
        RECT  66.576 129.516 66.6 129.6 ;
    END
  END i_pkt[317]
  PIN i_pkt[318]
    DIRECTION INPUT ;
    USE SIGNAL ;
    PORT
      LAYER M5 ;
        RECT  66.672 129.516 66.696 129.6 ;
    END
  END i_pkt[318]
  PIN i_pkt[319]
    DIRECTION INPUT ;
    USE SIGNAL ;
    PORT
      LAYER M5 ;
        RECT  66.768 129.516 66.792 129.6 ;
    END
  END i_pkt[319]
  PIN i_pkt[31]
    DIRECTION INPUT ;
    USE SIGNAL ;
    PORT
      LAYER M5 ;
        RECT  63.696 129.516 63.72 129.6 ;
    END
  END i_pkt[31]
  PIN i_pkt[320]
    DIRECTION INPUT ;
    USE SIGNAL ;
    PORT
      LAYER M5 ;
        RECT  66.864 129.516 66.888 129.6 ;
    END
  END i_pkt[320]
  PIN i_pkt[321]
    DIRECTION INPUT ;
    USE SIGNAL ;
    PORT
      LAYER M5 ;
        RECT  66.96 129.516 66.984 129.6 ;
    END
  END i_pkt[321]
  PIN i_pkt[322]
    DIRECTION INPUT ;
    USE SIGNAL ;
    PORT
      LAYER M5 ;
        RECT  67.056 129.516 67.08 129.6 ;
    END
  END i_pkt[322]
  PIN i_pkt[323]
    DIRECTION INPUT ;
    USE SIGNAL ;
    PORT
      LAYER M5 ;
        RECT  67.152 129.516 67.176 129.6 ;
    END
  END i_pkt[323]
  PIN i_pkt[324]
    DIRECTION INPUT ;
    USE SIGNAL ;
    PORT
      LAYER M5 ;
        RECT  67.248 129.516 67.272 129.6 ;
    END
  END i_pkt[324]
  PIN i_pkt[325]
    DIRECTION INPUT ;
    USE SIGNAL ;
    PORT
      LAYER M5 ;
        RECT  67.344 129.516 67.368 129.6 ;
    END
  END i_pkt[325]
  PIN i_pkt[326]
    DIRECTION INPUT ;
    USE SIGNAL ;
    PORT
      LAYER M5 ;
        RECT  67.44 129.516 67.464 129.6 ;
    END
  END i_pkt[326]
  PIN i_pkt[327]
    DIRECTION INPUT ;
    USE SIGNAL ;
    PORT
      LAYER M5 ;
        RECT  67.536 129.516 67.56 129.6 ;
    END
  END i_pkt[327]
  PIN i_pkt[328]
    DIRECTION INPUT ;
    USE SIGNAL ;
    PORT
      LAYER M5 ;
        RECT  67.632 129.516 67.656 129.6 ;
    END
  END i_pkt[328]
  PIN i_pkt[329]
    DIRECTION INPUT ;
    USE SIGNAL ;
    PORT
      LAYER M5 ;
        RECT  67.728 129.516 67.752 129.6 ;
    END
  END i_pkt[329]
  PIN i_pkt[32]
    DIRECTION INPUT ;
    USE SIGNAL ;
    PORT
      LAYER M5 ;
        RECT  76.848 129.516 76.872 129.6 ;
    END
  END i_pkt[32]
  PIN i_pkt[330]
    DIRECTION INPUT ;
    USE SIGNAL ;
    PORT
      LAYER M5 ;
        RECT  67.824 129.516 67.848 129.6 ;
    END
  END i_pkt[330]
  PIN i_pkt[331]
    DIRECTION INPUT ;
    USE SIGNAL ;
    PORT
      LAYER M5 ;
        RECT  67.92 129.516 67.944 129.6 ;
    END
  END i_pkt[331]
  PIN i_pkt[332]
    DIRECTION INPUT ;
    USE SIGNAL ;
    PORT
      LAYER M5 ;
        RECT  68.016 129.516 68.04 129.6 ;
    END
  END i_pkt[332]
  PIN i_pkt[333]
    DIRECTION INPUT ;
    USE SIGNAL ;
    PORT
      LAYER M5 ;
        RECT  68.112 129.516 68.136 129.6 ;
    END
  END i_pkt[333]
  PIN i_pkt[334]
    DIRECTION INPUT ;
    USE SIGNAL ;
    PORT
      LAYER M5 ;
        RECT  68.208 129.516 68.232 129.6 ;
    END
  END i_pkt[334]
  PIN i_pkt[335]
    DIRECTION INPUT ;
    USE SIGNAL ;
    PORT
      LAYER M5 ;
        RECT  68.304 129.516 68.328 129.6 ;
    END
  END i_pkt[335]
  PIN i_pkt[336]
    DIRECTION INPUT ;
    USE SIGNAL ;
    PORT
      LAYER M5 ;
        RECT  68.4 129.516 68.424 129.6 ;
    END
  END i_pkt[336]
  PIN i_pkt[337]
    DIRECTION INPUT ;
    USE SIGNAL ;
    PORT
      LAYER M5 ;
        RECT  68.496 129.516 68.52 129.6 ;
    END
  END i_pkt[337]
  PIN i_pkt[338]
    DIRECTION INPUT ;
    USE SIGNAL ;
    PORT
      LAYER M5 ;
        RECT  68.592 129.516 68.616 129.6 ;
    END
  END i_pkt[338]
  PIN i_pkt[339]
    DIRECTION INPUT ;
    USE SIGNAL ;
    PORT
      LAYER M5 ;
        RECT  68.688 129.516 68.712 129.6 ;
    END
  END i_pkt[339]
  PIN i_pkt[33]
    DIRECTION INPUT ;
    USE SIGNAL ;
    PORT
      LAYER M5 ;
        RECT  76.944 129.516 76.968 129.6 ;
    END
  END i_pkt[33]
  PIN i_pkt[340]
    DIRECTION INPUT ;
    USE SIGNAL ;
    PORT
      LAYER M5 ;
        RECT  68.784 129.516 68.808 129.6 ;
    END
  END i_pkt[340]
  PIN i_pkt[341]
    DIRECTION INPUT ;
    USE SIGNAL ;
    PORT
      LAYER M5 ;
        RECT  68.88 129.516 68.904 129.6 ;
    END
  END i_pkt[341]
  PIN i_pkt[342]
    DIRECTION INPUT ;
    USE SIGNAL ;
    PORT
      LAYER M5 ;
        RECT  68.976 129.516 69 129.6 ;
    END
  END i_pkt[342]
  PIN i_pkt[343]
    DIRECTION INPUT ;
    USE SIGNAL ;
    PORT
      LAYER M5 ;
        RECT  69.072 129.516 69.096 129.6 ;
    END
  END i_pkt[343]
  PIN i_pkt[344]
    DIRECTION INPUT ;
    USE SIGNAL ;
    PORT
      LAYER M5 ;
        RECT  69.168 129.516 69.192 129.6 ;
    END
  END i_pkt[344]
  PIN i_pkt[345]
    DIRECTION INPUT ;
    USE SIGNAL ;
    PORT
      LAYER M5 ;
        RECT  69.264 129.516 69.288 129.6 ;
    END
  END i_pkt[345]
  PIN i_pkt[346]
    DIRECTION INPUT ;
    USE SIGNAL ;
    PORT
      LAYER M5 ;
        RECT  69.36 129.516 69.384 129.6 ;
    END
  END i_pkt[346]
  PIN i_pkt[347]
    DIRECTION INPUT ;
    USE SIGNAL ;
    PORT
      LAYER M5 ;
        RECT  69.456 129.516 69.48 129.6 ;
    END
  END i_pkt[347]
  PIN i_pkt[348]
    DIRECTION INPUT ;
    USE SIGNAL ;
    PORT
      LAYER M5 ;
        RECT  69.552 129.516 69.576 129.6 ;
    END
  END i_pkt[348]
  PIN i_pkt[349]
    DIRECTION INPUT ;
    USE SIGNAL ;
    PORT
      LAYER M5 ;
        RECT  69.648 129.516 69.672 129.6 ;
    END
  END i_pkt[349]
  PIN i_pkt[34]
    DIRECTION INPUT ;
    USE SIGNAL ;
    PORT
      LAYER M5 ;
        RECT  77.04 129.516 77.064 129.6 ;
    END
  END i_pkt[34]
  PIN i_pkt[350]
    DIRECTION INPUT ;
    USE SIGNAL ;
    PORT
      LAYER M5 ;
        RECT  69.744 129.516 69.768 129.6 ;
    END
  END i_pkt[350]
  PIN i_pkt[351]
    DIRECTION INPUT ;
    USE SIGNAL ;
    PORT
      LAYER M5 ;
        RECT  69.84 129.516 69.864 129.6 ;
    END
  END i_pkt[351]
  PIN i_pkt[352]
    DIRECTION INPUT ;
    USE SIGNAL ;
    PORT
      LAYER M5 ;
        RECT  73.008 129.516 73.032 129.6 ;
    END
  END i_pkt[352]
  PIN i_pkt[353]
    DIRECTION INPUT ;
    USE SIGNAL ;
    PORT
      LAYER M5 ;
        RECT  73.104 129.516 73.128 129.6 ;
    END
  END i_pkt[353]
  PIN i_pkt[354]
    DIRECTION INPUT ;
    USE SIGNAL ;
    PORT
      LAYER M5 ;
        RECT  73.2 129.516 73.224 129.6 ;
    END
  END i_pkt[354]
  PIN i_pkt[355]
    DIRECTION INPUT ;
    USE SIGNAL ;
    PORT
      LAYER M5 ;
        RECT  73.296 129.516 73.32 129.6 ;
    END
  END i_pkt[355]
  PIN i_pkt[356]
    DIRECTION INPUT ;
    USE SIGNAL ;
    PORT
      LAYER M5 ;
        RECT  73.392 129.516 73.416 129.6 ;
    END
  END i_pkt[356]
  PIN i_pkt[357]
    DIRECTION INPUT ;
    USE SIGNAL ;
    PORT
      LAYER M5 ;
        RECT  73.488 129.516 73.512 129.6 ;
    END
  END i_pkt[357]
  PIN i_pkt[358]
    DIRECTION INPUT ;
    USE SIGNAL ;
    PORT
      LAYER M5 ;
        RECT  73.584 129.516 73.608 129.6 ;
    END
  END i_pkt[358]
  PIN i_pkt[359]
    DIRECTION INPUT ;
    USE SIGNAL ;
    PORT
      LAYER M5 ;
        RECT  73.68 129.516 73.704 129.6 ;
    END
  END i_pkt[359]
  PIN i_pkt[35]
    DIRECTION INPUT ;
    USE SIGNAL ;
    PORT
      LAYER M5 ;
        RECT  77.136 129.516 77.16 129.6 ;
    END
  END i_pkt[35]
  PIN i_pkt[360]
    DIRECTION INPUT ;
    USE SIGNAL ;
    PORT
      LAYER M5 ;
        RECT  73.776 129.516 73.8 129.6 ;
    END
  END i_pkt[360]
  PIN i_pkt[361]
    DIRECTION INPUT ;
    USE SIGNAL ;
    PORT
      LAYER M5 ;
        RECT  73.872 129.516 73.896 129.6 ;
    END
  END i_pkt[361]
  PIN i_pkt[362]
    DIRECTION INPUT ;
    USE SIGNAL ;
    PORT
      LAYER M5 ;
        RECT  73.968 129.516 73.992 129.6 ;
    END
  END i_pkt[362]
  PIN i_pkt[363]
    DIRECTION INPUT ;
    USE SIGNAL ;
    PORT
      LAYER M5 ;
        RECT  74.064 129.516 74.088 129.6 ;
    END
  END i_pkt[363]
  PIN i_pkt[364]
    DIRECTION INPUT ;
    USE SIGNAL ;
    PORT
      LAYER M5 ;
        RECT  74.16 129.516 74.184 129.6 ;
    END
  END i_pkt[364]
  PIN i_pkt[365]
    DIRECTION INPUT ;
    USE SIGNAL ;
    PORT
      LAYER M5 ;
        RECT  74.256 129.516 74.28 129.6 ;
    END
  END i_pkt[365]
  PIN i_pkt[366]
    DIRECTION INPUT ;
    USE SIGNAL ;
    PORT
      LAYER M5 ;
        RECT  74.352 129.516 74.376 129.6 ;
    END
  END i_pkt[366]
  PIN i_pkt[367]
    DIRECTION INPUT ;
    USE SIGNAL ;
    PORT
      LAYER M5 ;
        RECT  74.448 129.516 74.472 129.6 ;
    END
  END i_pkt[367]
  PIN i_pkt[368]
    DIRECTION INPUT ;
    USE SIGNAL ;
    PORT
      LAYER M5 ;
        RECT  74.544 129.516 74.568 129.6 ;
    END
  END i_pkt[368]
  PIN i_pkt[369]
    DIRECTION INPUT ;
    USE SIGNAL ;
    PORT
      LAYER M5 ;
        RECT  74.64 129.516 74.664 129.6 ;
    END
  END i_pkt[369]
  PIN i_pkt[36]
    DIRECTION INPUT ;
    USE SIGNAL ;
    PORT
      LAYER M5 ;
        RECT  77.232 129.516 77.256 129.6 ;
    END
  END i_pkt[36]
  PIN i_pkt[370]
    DIRECTION INPUT ;
    USE SIGNAL ;
    PORT
      LAYER M5 ;
        RECT  74.736 129.516 74.76 129.6 ;
    END
  END i_pkt[370]
  PIN i_pkt[371]
    DIRECTION INPUT ;
    USE SIGNAL ;
    PORT
      LAYER M5 ;
        RECT  74.832 129.516 74.856 129.6 ;
    END
  END i_pkt[371]
  PIN i_pkt[372]
    DIRECTION INPUT ;
    USE SIGNAL ;
    PORT
      LAYER M5 ;
        RECT  74.928 129.516 74.952 129.6 ;
    END
  END i_pkt[372]
  PIN i_pkt[373]
    DIRECTION INPUT ;
    USE SIGNAL ;
    PORT
      LAYER M5 ;
        RECT  75.024 129.516 75.048 129.6 ;
    END
  END i_pkt[373]
  PIN i_pkt[374]
    DIRECTION INPUT ;
    USE SIGNAL ;
    PORT
      LAYER M5 ;
        RECT  75.12 129.516 75.144 129.6 ;
    END
  END i_pkt[374]
  PIN i_pkt[375]
    DIRECTION INPUT ;
    USE SIGNAL ;
    PORT
      LAYER M5 ;
        RECT  75.216 129.516 75.24 129.6 ;
    END
  END i_pkt[375]
  PIN i_pkt[376]
    DIRECTION INPUT ;
    USE SIGNAL ;
    PORT
      LAYER M5 ;
        RECT  75.312 129.516 75.336 129.6 ;
    END
  END i_pkt[376]
  PIN i_pkt[377]
    DIRECTION INPUT ;
    USE SIGNAL ;
    PORT
      LAYER M5 ;
        RECT  75.408 129.516 75.432 129.6 ;
    END
  END i_pkt[377]
  PIN i_pkt[378]
    DIRECTION INPUT ;
    USE SIGNAL ;
    PORT
      LAYER M5 ;
        RECT  75.504 129.516 75.528 129.6 ;
    END
  END i_pkt[378]
  PIN i_pkt[379]
    DIRECTION INPUT ;
    USE SIGNAL ;
    PORT
      LAYER M5 ;
        RECT  75.6 129.516 75.624 129.6 ;
    END
  END i_pkt[379]
  PIN i_pkt[37]
    DIRECTION INPUT ;
    USE SIGNAL ;
    PORT
      LAYER M5 ;
        RECT  77.328 129.516 77.352 129.6 ;
    END
  END i_pkt[37]
  PIN i_pkt[380]
    DIRECTION INPUT ;
    USE SIGNAL ;
    PORT
      LAYER M5 ;
        RECT  75.696 129.516 75.72 129.6 ;
    END
  END i_pkt[380]
  PIN i_pkt[381]
    DIRECTION INPUT ;
    USE SIGNAL ;
    PORT
      LAYER M5 ;
        RECT  75.792 129.516 75.816 129.6 ;
    END
  END i_pkt[381]
  PIN i_pkt[382]
    DIRECTION INPUT ;
    USE SIGNAL ;
    PORT
      LAYER M5 ;
        RECT  75.888 129.516 75.912 129.6 ;
    END
  END i_pkt[382]
  PIN i_pkt[383]
    DIRECTION INPUT ;
    USE SIGNAL ;
    PORT
      LAYER M5 ;
        RECT  75.984 129.516 76.008 129.6 ;
    END
  END i_pkt[383]
  PIN i_pkt[384]
    DIRECTION INPUT ;
    USE SIGNAL ;
    PORT
      LAYER M5 ;
        RECT  96.048 129.516 96.072 129.6 ;
    END
  END i_pkt[384]
  PIN i_pkt[385]
    DIRECTION INPUT ;
    USE SIGNAL ;
    PORT
      LAYER M5 ;
        RECT  96.144 129.516 96.168 129.6 ;
    END
  END i_pkt[385]
  PIN i_pkt[386]
    DIRECTION INPUT ;
    USE SIGNAL ;
    PORT
      LAYER M5 ;
        RECT  96.24 129.516 96.264 129.6 ;
    END
  END i_pkt[386]
  PIN i_pkt[387]
    DIRECTION INPUT ;
    USE SIGNAL ;
    PORT
      LAYER M5 ;
        RECT  96.336 129.516 96.36 129.6 ;
    END
  END i_pkt[387]
  PIN i_pkt[388]
    DIRECTION INPUT ;
    USE SIGNAL ;
    PORT
      LAYER M5 ;
        RECT  96.432 129.516 96.456 129.6 ;
    END
  END i_pkt[388]
  PIN i_pkt[389]
    DIRECTION INPUT ;
    USE SIGNAL ;
    PORT
      LAYER M5 ;
        RECT  96.528 129.516 96.552 129.6 ;
    END
  END i_pkt[389]
  PIN i_pkt[38]
    DIRECTION INPUT ;
    USE SIGNAL ;
    PORT
      LAYER M5 ;
        RECT  77.424 129.516 77.448 129.6 ;
    END
  END i_pkt[38]
  PIN i_pkt[390]
    DIRECTION INPUT ;
    USE SIGNAL ;
    PORT
      LAYER M5 ;
        RECT  96.624 129.516 96.648 129.6 ;
    END
  END i_pkt[390]
  PIN i_pkt[391]
    DIRECTION INPUT ;
    USE SIGNAL ;
    PORT
      LAYER M5 ;
        RECT  96.72 129.516 96.744 129.6 ;
    END
  END i_pkt[391]
  PIN i_pkt[392]
    DIRECTION INPUT ;
    USE SIGNAL ;
    PORT
      LAYER M5 ;
        RECT  96.816 129.516 96.84 129.6 ;
    END
  END i_pkt[392]
  PIN i_pkt[393]
    DIRECTION INPUT ;
    USE SIGNAL ;
    PORT
      LAYER M5 ;
        RECT  96.912 129.516 96.936 129.6 ;
    END
  END i_pkt[393]
  PIN i_pkt[394]
    DIRECTION INPUT ;
    USE SIGNAL ;
    PORT
      LAYER M5 ;
        RECT  97.008 129.516 97.032 129.6 ;
    END
  END i_pkt[394]
  PIN i_pkt[395]
    DIRECTION INPUT ;
    USE SIGNAL ;
    PORT
      LAYER M5 ;
        RECT  97.104 129.516 97.128 129.6 ;
    END
  END i_pkt[395]
  PIN i_pkt[396]
    DIRECTION INPUT ;
    USE SIGNAL ;
    PORT
      LAYER M5 ;
        RECT  97.2 129.516 97.224 129.6 ;
    END
  END i_pkt[396]
  PIN i_pkt[397]
    DIRECTION INPUT ;
    USE SIGNAL ;
    PORT
      LAYER M5 ;
        RECT  97.296 129.516 97.32 129.6 ;
    END
  END i_pkt[397]
  PIN i_pkt[398]
    DIRECTION INPUT ;
    USE SIGNAL ;
    PORT
      LAYER M5 ;
        RECT  97.392 129.516 97.416 129.6 ;
    END
  END i_pkt[398]
  PIN i_pkt[399]
    DIRECTION INPUT ;
    USE SIGNAL ;
    PORT
      LAYER M5 ;
        RECT  97.488 129.516 97.512 129.6 ;
    END
  END i_pkt[399]
  PIN i_pkt[39]
    DIRECTION INPUT ;
    USE SIGNAL ;
    PORT
      LAYER M5 ;
        RECT  77.52 129.516 77.544 129.6 ;
    END
  END i_pkt[39]
  PIN i_pkt[3]
    DIRECTION INPUT ;
    USE SIGNAL ;
    PORT
      LAYER M5 ;
        RECT  61.008 129.516 61.032 129.6 ;
    END
  END i_pkt[3]
  PIN i_pkt[400]
    DIRECTION INPUT ;
    USE SIGNAL ;
    PORT
      LAYER M5 ;
        RECT  97.584 129.516 97.608 129.6 ;
    END
  END i_pkt[400]
  PIN i_pkt[401]
    DIRECTION INPUT ;
    USE SIGNAL ;
    PORT
      LAYER M5 ;
        RECT  97.68 129.516 97.704 129.6 ;
    END
  END i_pkt[401]
  PIN i_pkt[402]
    DIRECTION INPUT ;
    USE SIGNAL ;
    PORT
      LAYER M5 ;
        RECT  97.776 129.516 97.8 129.6 ;
    END
  END i_pkt[402]
  PIN i_pkt[403]
    DIRECTION INPUT ;
    USE SIGNAL ;
    PORT
      LAYER M5 ;
        RECT  97.872 129.516 97.896 129.6 ;
    END
  END i_pkt[403]
  PIN i_pkt[404]
    DIRECTION INPUT ;
    USE SIGNAL ;
    PORT
      LAYER M5 ;
        RECT  97.968 129.516 97.992 129.6 ;
    END
  END i_pkt[404]
  PIN i_pkt[405]
    DIRECTION INPUT ;
    USE SIGNAL ;
    PORT
      LAYER M5 ;
        RECT  98.064 129.516 98.088 129.6 ;
    END
  END i_pkt[405]
  PIN i_pkt[406]
    DIRECTION INPUT ;
    USE SIGNAL ;
    PORT
      LAYER M5 ;
        RECT  98.16 129.516 98.184 129.6 ;
    END
  END i_pkt[406]
  PIN i_pkt[407]
    DIRECTION INPUT ;
    USE SIGNAL ;
    PORT
      LAYER M5 ;
        RECT  98.256 129.516 98.28 129.6 ;
    END
  END i_pkt[407]
  PIN i_pkt[408]
    DIRECTION INPUT ;
    USE SIGNAL ;
    PORT
      LAYER M5 ;
        RECT  98.352 129.516 98.376 129.6 ;
    END
  END i_pkt[408]
  PIN i_pkt[409]
    DIRECTION INPUT ;
    USE SIGNAL ;
    PORT
      LAYER M5 ;
        RECT  98.448 129.516 98.472 129.6 ;
    END
  END i_pkt[409]
  PIN i_pkt[40]
    DIRECTION INPUT ;
    USE SIGNAL ;
    PORT
      LAYER M5 ;
        RECT  77.616 129.516 77.64 129.6 ;
    END
  END i_pkt[40]
  PIN i_pkt[410]
    DIRECTION INPUT ;
    USE SIGNAL ;
    PORT
      LAYER M5 ;
        RECT  98.544 129.516 98.568 129.6 ;
    END
  END i_pkt[410]
  PIN i_pkt[411]
    DIRECTION INPUT ;
    USE SIGNAL ;
    PORT
      LAYER M5 ;
        RECT  98.64 129.516 98.664 129.6 ;
    END
  END i_pkt[411]
  PIN i_pkt[412]
    DIRECTION INPUT ;
    USE SIGNAL ;
    PORT
      LAYER M5 ;
        RECT  98.736 129.516 98.76 129.6 ;
    END
  END i_pkt[412]
  PIN i_pkt[413]
    DIRECTION INPUT ;
    USE SIGNAL ;
    PORT
      LAYER M5 ;
        RECT  98.832 129.516 98.856 129.6 ;
    END
  END i_pkt[413]
  PIN i_pkt[414]
    DIRECTION INPUT ;
    USE SIGNAL ;
    PORT
      LAYER M5 ;
        RECT  98.928 129.516 98.952 129.6 ;
    END
  END i_pkt[414]
  PIN i_pkt[415]
    DIRECTION INPUT ;
    USE SIGNAL ;
    PORT
      LAYER M5 ;
        RECT  99.024 129.516 99.048 129.6 ;
    END
  END i_pkt[415]
  PIN i_pkt[416]
    DIRECTION INPUT ;
    USE SIGNAL ;
    PORT
      LAYER M5 ;
        RECT  99.12 129.516 99.144 129.6 ;
    END
  END i_pkt[416]
  PIN i_pkt[417]
    DIRECTION INPUT ;
    USE SIGNAL ;
    PORT
      LAYER M5 ;
        RECT  99.216 129.516 99.24 129.6 ;
    END
  END i_pkt[417]
  PIN i_pkt[418]
    DIRECTION INPUT ;
    USE SIGNAL ;
    PORT
      LAYER M5 ;
        RECT  99.312 129.516 99.336 129.6 ;
    END
  END i_pkt[418]
  PIN i_pkt[419]
    DIRECTION INPUT ;
    USE SIGNAL ;
    PORT
      LAYER M5 ;
        RECT  99.408 129.516 99.432 129.6 ;
    END
  END i_pkt[419]
  PIN i_pkt[41]
    DIRECTION INPUT ;
    USE SIGNAL ;
    PORT
      LAYER M5 ;
        RECT  77.712 129.516 77.736 129.6 ;
    END
  END i_pkt[41]
  PIN i_pkt[420]
    DIRECTION INPUT ;
    USE SIGNAL ;
    PORT
      LAYER M5 ;
        RECT  99.504 129.516 99.528 129.6 ;
    END
  END i_pkt[420]
  PIN i_pkt[421]
    DIRECTION INPUT ;
    USE SIGNAL ;
    PORT
      LAYER M5 ;
        RECT  99.6 129.516 99.624 129.6 ;
    END
  END i_pkt[421]
  PIN i_pkt[422]
    DIRECTION INPUT ;
    USE SIGNAL ;
    PORT
      LAYER M5 ;
        RECT  99.696 129.516 99.72 129.6 ;
    END
  END i_pkt[422]
  PIN i_pkt[423]
    DIRECTION INPUT ;
    USE SIGNAL ;
    PORT
      LAYER M5 ;
        RECT  99.792 129.516 99.816 129.6 ;
    END
  END i_pkt[423]
  PIN i_pkt[424]
    DIRECTION INPUT ;
    USE SIGNAL ;
    PORT
      LAYER M5 ;
        RECT  99.888 129.516 99.912 129.6 ;
    END
  END i_pkt[424]
  PIN i_pkt[425]
    DIRECTION INPUT ;
    USE SIGNAL ;
    PORT
      LAYER M5 ;
        RECT  99.984 129.516 100.008 129.6 ;
    END
  END i_pkt[425]
  PIN i_pkt[426]
    DIRECTION INPUT ;
    USE SIGNAL ;
    PORT
      LAYER M5 ;
        RECT  100.08 129.516 100.104 129.6 ;
    END
  END i_pkt[426]
  PIN i_pkt[427]
    DIRECTION INPUT ;
    USE SIGNAL ;
    PORT
      LAYER M5 ;
        RECT  100.176 129.516 100.2 129.6 ;
    END
  END i_pkt[427]
  PIN i_pkt[428]
    DIRECTION INPUT ;
    USE SIGNAL ;
    PORT
      LAYER M5 ;
        RECT  100.272 129.516 100.296 129.6 ;
    END
  END i_pkt[428]
  PIN i_pkt[429]
    DIRECTION INPUT ;
    USE SIGNAL ;
    PORT
      LAYER M5 ;
        RECT  100.368 129.516 100.392 129.6 ;
    END
  END i_pkt[429]
  PIN i_pkt[42]
    DIRECTION INPUT ;
    USE SIGNAL ;
    PORT
      LAYER M5 ;
        RECT  77.808 129.516 77.832 129.6 ;
    END
  END i_pkt[42]
  PIN i_pkt[430]
    DIRECTION INPUT ;
    USE SIGNAL ;
    PORT
      LAYER M5 ;
        RECT  100.464 129.516 100.488 129.6 ;
    END
  END i_pkt[430]
  PIN i_pkt[431]
    DIRECTION INPUT ;
    USE SIGNAL ;
    PORT
      LAYER M5 ;
        RECT  100.56 129.516 100.584 129.6 ;
    END
  END i_pkt[431]
  PIN i_pkt[432]
    DIRECTION INPUT ;
    USE SIGNAL ;
    PORT
      LAYER M5 ;
        RECT  100.656 129.516 100.68 129.6 ;
    END
  END i_pkt[432]
  PIN i_pkt[433]
    DIRECTION INPUT ;
    USE SIGNAL ;
    PORT
      LAYER M5 ;
        RECT  100.752 129.516 100.776 129.6 ;
    END
  END i_pkt[433]
  PIN i_pkt[434]
    DIRECTION INPUT ;
    USE SIGNAL ;
    PORT
      LAYER M5 ;
        RECT  100.848 129.516 100.872 129.6 ;
    END
  END i_pkt[434]
  PIN i_pkt[435]
    DIRECTION INPUT ;
    USE SIGNAL ;
    PORT
      LAYER M5 ;
        RECT  100.944 129.516 100.968 129.6 ;
    END
  END i_pkt[435]
  PIN i_pkt[436]
    DIRECTION INPUT ;
    USE SIGNAL ;
    PORT
      LAYER M5 ;
        RECT  101.04 129.516 101.064 129.6 ;
    END
  END i_pkt[436]
  PIN i_pkt[437]
    DIRECTION INPUT ;
    USE SIGNAL ;
    PORT
      LAYER M5 ;
        RECT  101.136 129.516 101.16 129.6 ;
    END
  END i_pkt[437]
  PIN i_pkt[438]
    DIRECTION INPUT ;
    USE SIGNAL ;
    PORT
      LAYER M5 ;
        RECT  101.232 129.516 101.256 129.6 ;
    END
  END i_pkt[438]
  PIN i_pkt[439]
    DIRECTION INPUT ;
    USE SIGNAL ;
    PORT
      LAYER M5 ;
        RECT  101.328 129.516 101.352 129.6 ;
    END
  END i_pkt[439]
  PIN i_pkt[43]
    DIRECTION INPUT ;
    USE SIGNAL ;
    PORT
      LAYER M5 ;
        RECT  77.904 129.516 77.928 129.6 ;
    END
  END i_pkt[43]
  PIN i_pkt[440]
    DIRECTION INPUT ;
    USE SIGNAL ;
    PORT
      LAYER M5 ;
        RECT  101.424 129.516 101.448 129.6 ;
    END
  END i_pkt[440]
  PIN i_pkt[441]
    DIRECTION INPUT ;
    USE SIGNAL ;
    PORT
      LAYER M5 ;
        RECT  101.52 129.516 101.544 129.6 ;
    END
  END i_pkt[441]
  PIN i_pkt[442]
    DIRECTION INPUT ;
    USE SIGNAL ;
    PORT
      LAYER M5 ;
        RECT  101.616 129.516 101.64 129.6 ;
    END
  END i_pkt[442]
  PIN i_pkt[443]
    DIRECTION INPUT ;
    USE SIGNAL ;
    PORT
      LAYER M5 ;
        RECT  101.712 129.516 101.736 129.6 ;
    END
  END i_pkt[443]
  PIN i_pkt[444]
    DIRECTION INPUT ;
    USE SIGNAL ;
    PORT
      LAYER M5 ;
        RECT  101.808 129.516 101.832 129.6 ;
    END
  END i_pkt[444]
  PIN i_pkt[445]
    DIRECTION INPUT ;
    USE SIGNAL ;
    PORT
      LAYER M5 ;
        RECT  101.904 129.516 101.928 129.6 ;
    END
  END i_pkt[445]
  PIN i_pkt[446]
    DIRECTION INPUT ;
    USE SIGNAL ;
    PORT
      LAYER M5 ;
        RECT  102 129.516 102.024 129.6 ;
    END
  END i_pkt[446]
  PIN i_pkt[447]
    DIRECTION INPUT ;
    USE SIGNAL ;
    PORT
      LAYER M5 ;
        RECT  102.096 129.516 102.12 129.6 ;
    END
  END i_pkt[447]
  PIN i_pkt[448]
    DIRECTION INPUT ;
    USE SIGNAL ;
    PORT
      LAYER M5 ;
        RECT  108.336 129.516 108.36 129.6 ;
    END
  END i_pkt[448]
  PIN i_pkt[449]
    DIRECTION INPUT ;
    USE SIGNAL ;
    PORT
      LAYER M5 ;
        RECT  108.432 129.516 108.456 129.6 ;
    END
  END i_pkt[449]
  PIN i_pkt[44]
    DIRECTION INPUT ;
    USE SIGNAL ;
    PORT
      LAYER M5 ;
        RECT  78 129.516 78.024 129.6 ;
    END
  END i_pkt[44]
  PIN i_pkt[450]
    DIRECTION INPUT ;
    USE SIGNAL ;
    PORT
      LAYER M5 ;
        RECT  108.528 129.516 108.552 129.6 ;
    END
  END i_pkt[450]
  PIN i_pkt[451]
    DIRECTION INPUT ;
    USE SIGNAL ;
    PORT
      LAYER M5 ;
        RECT  108.624 129.516 108.648 129.6 ;
    END
  END i_pkt[451]
  PIN i_pkt[452]
    DIRECTION INPUT ;
    USE SIGNAL ;
    PORT
      LAYER M5 ;
        RECT  108.72 129.516 108.744 129.6 ;
    END
  END i_pkt[452]
  PIN i_pkt[453]
    DIRECTION INPUT ;
    USE SIGNAL ;
    PORT
      LAYER M5 ;
        RECT  108.816 129.516 108.84 129.6 ;
    END
  END i_pkt[453]
  PIN i_pkt[454]
    DIRECTION INPUT ;
    USE SIGNAL ;
    PORT
      LAYER M5 ;
        RECT  108.912 129.516 108.936 129.6 ;
    END
  END i_pkt[454]
  PIN i_pkt[455]
    DIRECTION INPUT ;
    USE SIGNAL ;
    PORT
      LAYER M5 ;
        RECT  109.008 129.516 109.032 129.6 ;
    END
  END i_pkt[455]
  PIN i_pkt[456]
    DIRECTION INPUT ;
    USE SIGNAL ;
    PORT
      LAYER M5 ;
        RECT  109.104 129.516 109.128 129.6 ;
    END
  END i_pkt[456]
  PIN i_pkt[457]
    DIRECTION INPUT ;
    USE SIGNAL ;
    PORT
      LAYER M5 ;
        RECT  109.2 129.516 109.224 129.6 ;
    END
  END i_pkt[457]
  PIN i_pkt[458]
    DIRECTION INPUT ;
    USE SIGNAL ;
    PORT
      LAYER M5 ;
        RECT  109.296 129.516 109.32 129.6 ;
    END
  END i_pkt[458]
  PIN i_pkt[459]
    DIRECTION INPUT ;
    USE SIGNAL ;
    PORT
      LAYER M5 ;
        RECT  109.392 129.516 109.416 129.6 ;
    END
  END i_pkt[459]
  PIN i_pkt[45]
    DIRECTION INPUT ;
    USE SIGNAL ;
    PORT
      LAYER M5 ;
        RECT  78.096 129.516 78.12 129.6 ;
    END
  END i_pkt[45]
  PIN i_pkt[460]
    DIRECTION INPUT ;
    USE SIGNAL ;
    PORT
      LAYER M5 ;
        RECT  109.488 129.516 109.512 129.6 ;
    END
  END i_pkt[460]
  PIN i_pkt[461]
    DIRECTION INPUT ;
    USE SIGNAL ;
    PORT
      LAYER M5 ;
        RECT  109.584 129.516 109.608 129.6 ;
    END
  END i_pkt[461]
  PIN i_pkt[462]
    DIRECTION INPUT ;
    USE SIGNAL ;
    PORT
      LAYER M5 ;
        RECT  109.68 129.516 109.704 129.6 ;
    END
  END i_pkt[462]
  PIN i_pkt[463]
    DIRECTION INPUT ;
    USE SIGNAL ;
    PORT
      LAYER M5 ;
        RECT  109.776 129.516 109.8 129.6 ;
    END
  END i_pkt[463]
  PIN i_pkt[464]
    DIRECTION INPUT ;
    USE SIGNAL ;
    PORT
      LAYER M5 ;
        RECT  109.872 129.516 109.896 129.6 ;
    END
  END i_pkt[464]
  PIN i_pkt[465]
    DIRECTION INPUT ;
    USE SIGNAL ;
    PORT
      LAYER M5 ;
        RECT  109.968 129.516 109.992 129.6 ;
    END
  END i_pkt[465]
  PIN i_pkt[466]
    DIRECTION INPUT ;
    USE SIGNAL ;
    PORT
      LAYER M5 ;
        RECT  110.064 129.516 110.088 129.6 ;
    END
  END i_pkt[466]
  PIN i_pkt[467]
    DIRECTION INPUT ;
    USE SIGNAL ;
    PORT
      LAYER M5 ;
        RECT  110.16 129.516 110.184 129.6 ;
    END
  END i_pkt[467]
  PIN i_pkt[468]
    DIRECTION INPUT ;
    USE SIGNAL ;
    PORT
      LAYER M5 ;
        RECT  110.256 129.516 110.28 129.6 ;
    END
  END i_pkt[468]
  PIN i_pkt[469]
    DIRECTION INPUT ;
    USE SIGNAL ;
    PORT
      LAYER M5 ;
        RECT  110.352 129.516 110.376 129.6 ;
    END
  END i_pkt[469]
  PIN i_pkt[46]
    DIRECTION INPUT ;
    USE SIGNAL ;
    PORT
      LAYER M5 ;
        RECT  78.192 129.516 78.216 129.6 ;
    END
  END i_pkt[46]
  PIN i_pkt[470]
    DIRECTION INPUT ;
    USE SIGNAL ;
    PORT
      LAYER M5 ;
        RECT  110.448 129.516 110.472 129.6 ;
    END
  END i_pkt[470]
  PIN i_pkt[471]
    DIRECTION INPUT ;
    USE SIGNAL ;
    PORT
      LAYER M5 ;
        RECT  110.544 129.516 110.568 129.6 ;
    END
  END i_pkt[471]
  PIN i_pkt[472]
    DIRECTION INPUT ;
    USE SIGNAL ;
    PORT
      LAYER M5 ;
        RECT  110.64 129.516 110.664 129.6 ;
    END
  END i_pkt[472]
  PIN i_pkt[473]
    DIRECTION INPUT ;
    USE SIGNAL ;
    PORT
      LAYER M5 ;
        RECT  110.736 129.516 110.76 129.6 ;
    END
  END i_pkt[473]
  PIN i_pkt[474]
    DIRECTION INPUT ;
    USE SIGNAL ;
    PORT
      LAYER M5 ;
        RECT  110.832 129.516 110.856 129.6 ;
    END
  END i_pkt[474]
  PIN i_pkt[475]
    DIRECTION INPUT ;
    USE SIGNAL ;
    PORT
      LAYER M5 ;
        RECT  110.928 129.516 110.952 129.6 ;
    END
  END i_pkt[475]
  PIN i_pkt[476]
    DIRECTION INPUT ;
    USE SIGNAL ;
    PORT
      LAYER M5 ;
        RECT  111.024 129.516 111.048 129.6 ;
    END
  END i_pkt[476]
  PIN i_pkt[477]
    DIRECTION INPUT ;
    USE SIGNAL ;
    PORT
      LAYER M5 ;
        RECT  111.12 129.516 111.144 129.6 ;
    END
  END i_pkt[477]
  PIN i_pkt[478]
    DIRECTION INPUT ;
    USE SIGNAL ;
    PORT
      LAYER M5 ;
        RECT  111.216 129.516 111.24 129.6 ;
    END
  END i_pkt[478]
  PIN i_pkt[479]
    DIRECTION INPUT ;
    USE SIGNAL ;
    PORT
      LAYER M5 ;
        RECT  111.312 129.516 111.336 129.6 ;
    END
  END i_pkt[479]
  PIN i_pkt[47]
    DIRECTION INPUT ;
    USE SIGNAL ;
    PORT
      LAYER M5 ;
        RECT  78.288 129.516 78.312 129.6 ;
    END
  END i_pkt[47]
  PIN i_pkt[480]
    DIRECTION INPUT ;
    USE SIGNAL ;
    PORT
      LAYER M5 ;
        RECT  102.192 129.516 102.216 129.6 ;
    END
  END i_pkt[480]
  PIN i_pkt[481]
    DIRECTION INPUT ;
    USE SIGNAL ;
    PORT
      LAYER M5 ;
        RECT  102.288 129.516 102.312 129.6 ;
    END
  END i_pkt[481]
  PIN i_pkt[482]
    DIRECTION INPUT ;
    USE SIGNAL ;
    PORT
      LAYER M5 ;
        RECT  102.384 129.516 102.408 129.6 ;
    END
  END i_pkt[482]
  PIN i_pkt[483]
    DIRECTION INPUT ;
    USE SIGNAL ;
    PORT
      LAYER M5 ;
        RECT  102.48 129.516 102.504 129.6 ;
    END
  END i_pkt[483]
  PIN i_pkt[484]
    DIRECTION INPUT ;
    USE SIGNAL ;
    PORT
      LAYER M5 ;
        RECT  102.576 129.516 102.6 129.6 ;
    END
  END i_pkt[484]
  PIN i_pkt[485]
    DIRECTION INPUT ;
    USE SIGNAL ;
    PORT
      LAYER M5 ;
        RECT  102.672 129.516 102.696 129.6 ;
    END
  END i_pkt[485]
  PIN i_pkt[486]
    DIRECTION INPUT ;
    USE SIGNAL ;
    PORT
      LAYER M5 ;
        RECT  102.768 129.516 102.792 129.6 ;
    END
  END i_pkt[486]
  PIN i_pkt[487]
    DIRECTION INPUT ;
    USE SIGNAL ;
    PORT
      LAYER M5 ;
        RECT  102.864 129.516 102.888 129.6 ;
    END
  END i_pkt[487]
  PIN i_pkt[488]
    DIRECTION INPUT ;
    USE SIGNAL ;
    PORT
      LAYER M5 ;
        RECT  102.96 129.516 102.984 129.6 ;
    END
  END i_pkt[488]
  PIN i_pkt[489]
    DIRECTION INPUT ;
    USE SIGNAL ;
    PORT
      LAYER M5 ;
        RECT  103.056 129.516 103.08 129.6 ;
    END
  END i_pkt[489]
  PIN i_pkt[48]
    DIRECTION INPUT ;
    USE SIGNAL ;
    PORT
      LAYER M5 ;
        RECT  78.384 129.516 78.408 129.6 ;
    END
  END i_pkt[48]
  PIN i_pkt[490]
    DIRECTION INPUT ;
    USE SIGNAL ;
    PORT
      LAYER M5 ;
        RECT  103.152 129.516 103.176 129.6 ;
    END
  END i_pkt[490]
  PIN i_pkt[491]
    DIRECTION INPUT ;
    USE SIGNAL ;
    PORT
      LAYER M5 ;
        RECT  103.248 129.516 103.272 129.6 ;
    END
  END i_pkt[491]
  PIN i_pkt[492]
    DIRECTION INPUT ;
    USE SIGNAL ;
    PORT
      LAYER M5 ;
        RECT  103.344 129.516 103.368 129.6 ;
    END
  END i_pkt[492]
  PIN i_pkt[493]
    DIRECTION INPUT ;
    USE SIGNAL ;
    PORT
      LAYER M5 ;
        RECT  103.44 129.516 103.464 129.6 ;
    END
  END i_pkt[493]
  PIN i_pkt[494]
    DIRECTION INPUT ;
    USE SIGNAL ;
    PORT
      LAYER M5 ;
        RECT  103.536 129.516 103.56 129.6 ;
    END
  END i_pkt[494]
  PIN i_pkt[495]
    DIRECTION INPUT ;
    USE SIGNAL ;
    PORT
      LAYER M5 ;
        RECT  103.632 129.516 103.656 129.6 ;
    END
  END i_pkt[495]
  PIN i_pkt[496]
    DIRECTION INPUT ;
    USE SIGNAL ;
    PORT
      LAYER M5 ;
        RECT  103.728 129.516 103.752 129.6 ;
    END
  END i_pkt[496]
  PIN i_pkt[497]
    DIRECTION INPUT ;
    USE SIGNAL ;
    PORT
      LAYER M5 ;
        RECT  103.824 129.516 103.848 129.6 ;
    END
  END i_pkt[497]
  PIN i_pkt[498]
    DIRECTION INPUT ;
    USE SIGNAL ;
    PORT
      LAYER M5 ;
        RECT  103.92 129.516 103.944 129.6 ;
    END
  END i_pkt[498]
  PIN i_pkt[499]
    DIRECTION INPUT ;
    USE SIGNAL ;
    PORT
      LAYER M5 ;
        RECT  104.016 129.516 104.04 129.6 ;
    END
  END i_pkt[499]
  PIN i_pkt[49]
    DIRECTION INPUT ;
    USE SIGNAL ;
    PORT
      LAYER M5 ;
        RECT  78.48 129.516 78.504 129.6 ;
    END
  END i_pkt[49]
  PIN i_pkt[4]
    DIRECTION INPUT ;
    USE SIGNAL ;
    PORT
      LAYER M5 ;
        RECT  61.104 129.516 61.128 129.6 ;
    END
  END i_pkt[4]
  PIN i_pkt[500]
    DIRECTION INPUT ;
    USE SIGNAL ;
    PORT
      LAYER M5 ;
        RECT  104.112 129.516 104.136 129.6 ;
    END
  END i_pkt[500]
  PIN i_pkt[501]
    DIRECTION INPUT ;
    USE SIGNAL ;
    PORT
      LAYER M5 ;
        RECT  104.208 129.516 104.232 129.6 ;
    END
  END i_pkt[501]
  PIN i_pkt[502]
    DIRECTION INPUT ;
    USE SIGNAL ;
    PORT
      LAYER M5 ;
        RECT  104.304 129.516 104.328 129.6 ;
    END
  END i_pkt[502]
  PIN i_pkt[503]
    DIRECTION INPUT ;
    USE SIGNAL ;
    PORT
      LAYER M5 ;
        RECT  104.4 129.516 104.424 129.6 ;
    END
  END i_pkt[503]
  PIN i_pkt[504]
    DIRECTION INPUT ;
    USE SIGNAL ;
    PORT
      LAYER M5 ;
        RECT  104.496 129.516 104.52 129.6 ;
    END
  END i_pkt[504]
  PIN i_pkt[505]
    DIRECTION INPUT ;
    USE SIGNAL ;
    PORT
      LAYER M5 ;
        RECT  104.592 129.516 104.616 129.6 ;
    END
  END i_pkt[505]
  PIN i_pkt[506]
    DIRECTION INPUT ;
    USE SIGNAL ;
    PORT
      LAYER M5 ;
        RECT  104.688 129.516 104.712 129.6 ;
    END
  END i_pkt[506]
  PIN i_pkt[507]
    DIRECTION INPUT ;
    USE SIGNAL ;
    PORT
      LAYER M5 ;
        RECT  104.784 129.516 104.808 129.6 ;
    END
  END i_pkt[507]
  PIN i_pkt[508]
    DIRECTION INPUT ;
    USE SIGNAL ;
    PORT
      LAYER M5 ;
        RECT  104.88 129.516 104.904 129.6 ;
    END
  END i_pkt[508]
  PIN i_pkt[509]
    DIRECTION INPUT ;
    USE SIGNAL ;
    PORT
      LAYER M5 ;
        RECT  104.976 129.516 105 129.6 ;
    END
  END i_pkt[509]
  PIN i_pkt[50]
    DIRECTION INPUT ;
    USE SIGNAL ;
    PORT
      LAYER M5 ;
        RECT  78.576 129.516 78.6 129.6 ;
    END
  END i_pkt[50]
  PIN i_pkt[510]
    DIRECTION INPUT ;
    USE SIGNAL ;
    PORT
      LAYER M5 ;
        RECT  105.072 129.516 105.096 129.6 ;
    END
  END i_pkt[510]
  PIN i_pkt[511]
    DIRECTION INPUT ;
    USE SIGNAL ;
    PORT
      LAYER M5 ;
        RECT  105.168 129.516 105.192 129.6 ;
    END
  END i_pkt[511]
  PIN i_pkt[512]
    DIRECTION INPUT ;
    USE SIGNAL ;
    PORT
      LAYER M5 ;
        RECT  69.936 129.516 69.96 129.6 ;
    END
  END i_pkt[512]
  PIN i_pkt[513]
    DIRECTION INPUT ;
    USE SIGNAL ;
    PORT
      LAYER M5 ;
        RECT  70.032 129.516 70.056 129.6 ;
    END
  END i_pkt[513]
  PIN i_pkt[514]
    DIRECTION INPUT ;
    USE SIGNAL ;
    PORT
      LAYER M5 ;
        RECT  70.128 129.516 70.152 129.6 ;
    END
  END i_pkt[514]
  PIN i_pkt[515]
    DIRECTION INPUT ;
    USE SIGNAL ;
    PORT
      LAYER M5 ;
        RECT  70.224 129.516 70.248 129.6 ;
    END
  END i_pkt[515]
  PIN i_pkt[516]
    DIRECTION INPUT ;
    USE SIGNAL ;
    PORT
      LAYER M5 ;
        RECT  70.32 129.516 70.344 129.6 ;
    END
  END i_pkt[516]
  PIN i_pkt[517]
    DIRECTION INPUT ;
    USE SIGNAL ;
    PORT
      LAYER M5 ;
        RECT  70.416 129.516 70.44 129.6 ;
    END
  END i_pkt[517]
  PIN i_pkt[518]
    DIRECTION INPUT ;
    USE SIGNAL ;
    PORT
      LAYER M5 ;
        RECT  70.512 129.516 70.536 129.6 ;
    END
  END i_pkt[518]
  PIN i_pkt[519]
    DIRECTION INPUT ;
    USE SIGNAL ;
    PORT
      LAYER M5 ;
        RECT  70.608 129.516 70.632 129.6 ;
    END
  END i_pkt[519]
  PIN i_pkt[51]
    DIRECTION INPUT ;
    USE SIGNAL ;
    PORT
      LAYER M5 ;
        RECT  78.672 129.516 78.696 129.6 ;
    END
  END i_pkt[51]
  PIN i_pkt[520]
    DIRECTION INPUT ;
    USE SIGNAL ;
    PORT
      LAYER M5 ;
        RECT  70.704 129.516 70.728 129.6 ;
    END
  END i_pkt[520]
  PIN i_pkt[521]
    DIRECTION INPUT ;
    USE SIGNAL ;
    PORT
      LAYER M5 ;
        RECT  70.8 129.516 70.824 129.6 ;
    END
  END i_pkt[521]
  PIN i_pkt[522]
    DIRECTION INPUT ;
    USE SIGNAL ;
    PORT
      LAYER M5 ;
        RECT  70.896 129.516 70.92 129.6 ;
    END
  END i_pkt[522]
  PIN i_pkt[523]
    DIRECTION INPUT ;
    USE SIGNAL ;
    PORT
      LAYER M5 ;
        RECT  70.992 129.516 71.016 129.6 ;
    END
  END i_pkt[523]
  PIN i_pkt[524]
    DIRECTION INPUT ;
    USE SIGNAL ;
    PORT
      LAYER M5 ;
        RECT  71.088 129.516 71.112 129.6 ;
    END
  END i_pkt[524]
  PIN i_pkt[525]
    DIRECTION INPUT ;
    USE SIGNAL ;
    PORT
      LAYER M5 ;
        RECT  71.184 129.516 71.208 129.6 ;
    END
  END i_pkt[525]
  PIN i_pkt[526]
    DIRECTION INPUT ;
    USE SIGNAL ;
    PORT
      LAYER M5 ;
        RECT  71.28 129.516 71.304 129.6 ;
    END
  END i_pkt[526]
  PIN i_pkt[527]
    DIRECTION INPUT ;
    USE SIGNAL ;
    PORT
      LAYER M5 ;
        RECT  71.376 129.516 71.4 129.6 ;
    END
  END i_pkt[527]
  PIN i_pkt[528]
    DIRECTION INPUT ;
    USE SIGNAL ;
    PORT
      LAYER M5 ;
        RECT  71.472 129.516 71.496 129.6 ;
    END
  END i_pkt[528]
  PIN i_pkt[529]
    DIRECTION INPUT ;
    USE SIGNAL ;
    PORT
      LAYER M5 ;
        RECT  71.568 129.516 71.592 129.6 ;
    END
  END i_pkt[529]
  PIN i_pkt[52]
    DIRECTION INPUT ;
    USE SIGNAL ;
    PORT
      LAYER M5 ;
        RECT  78.768 129.516 78.792 129.6 ;
    END
  END i_pkt[52]
  PIN i_pkt[530]
    DIRECTION INPUT ;
    USE SIGNAL ;
    PORT
      LAYER M5 ;
        RECT  71.664 129.516 71.688 129.6 ;
    END
  END i_pkt[530]
  PIN i_pkt[531]
    DIRECTION INPUT ;
    USE SIGNAL ;
    PORT
      LAYER M5 ;
        RECT  71.76 129.516 71.784 129.6 ;
    END
  END i_pkt[531]
  PIN i_pkt[532]
    DIRECTION INPUT ;
    USE SIGNAL ;
    PORT
      LAYER M5 ;
        RECT  71.856 129.516 71.88 129.6 ;
    END
  END i_pkt[532]
  PIN i_pkt[533]
    DIRECTION INPUT ;
    USE SIGNAL ;
    PORT
      LAYER M5 ;
        RECT  71.952 129.516 71.976 129.6 ;
    END
  END i_pkt[533]
  PIN i_pkt[534]
    DIRECTION INPUT ;
    USE SIGNAL ;
    PORT
      LAYER M5 ;
        RECT  72.048 129.516 72.072 129.6 ;
    END
  END i_pkt[534]
  PIN i_pkt[535]
    DIRECTION INPUT ;
    USE SIGNAL ;
    PORT
      LAYER M5 ;
        RECT  72.144 129.516 72.168 129.6 ;
    END
  END i_pkt[535]
  PIN i_pkt[536]
    DIRECTION INPUT ;
    USE SIGNAL ;
    PORT
      LAYER M5 ;
        RECT  72.24 129.516 72.264 129.6 ;
    END
  END i_pkt[536]
  PIN i_pkt[537]
    DIRECTION INPUT ;
    USE SIGNAL ;
    PORT
      LAYER M5 ;
        RECT  72.336 129.516 72.36 129.6 ;
    END
  END i_pkt[537]
  PIN i_pkt[538]
    DIRECTION INPUT ;
    USE SIGNAL ;
    PORT
      LAYER M5 ;
        RECT  72.432 129.516 72.456 129.6 ;
    END
  END i_pkt[538]
  PIN i_pkt[539]
    DIRECTION INPUT ;
    USE SIGNAL ;
    PORT
      LAYER M5 ;
        RECT  72.528 129.516 72.552 129.6 ;
    END
  END i_pkt[539]
  PIN i_pkt[53]
    DIRECTION INPUT ;
    USE SIGNAL ;
    PORT
      LAYER M5 ;
        RECT  78.864 129.516 78.888 129.6 ;
    END
  END i_pkt[53]
  PIN i_pkt[540]
    DIRECTION INPUT ;
    USE SIGNAL ;
    PORT
      LAYER M5 ;
        RECT  72.624 129.516 72.648 129.6 ;
    END
  END i_pkt[540]
  PIN i_pkt[541]
    DIRECTION INPUT ;
    USE SIGNAL ;
    PORT
      LAYER M5 ;
        RECT  72.72 129.516 72.744 129.6 ;
    END
  END i_pkt[541]
  PIN i_pkt[542]
    DIRECTION INPUT ;
    USE SIGNAL ;
    PORT
      LAYER M5 ;
        RECT  72.816 129.516 72.84 129.6 ;
    END
  END i_pkt[542]
  PIN i_pkt[543]
    DIRECTION INPUT ;
    USE SIGNAL ;
    PORT
      LAYER M5 ;
        RECT  72.912 129.516 72.936 129.6 ;
    END
  END i_pkt[543]
  PIN i_pkt[544]
    DIRECTION INPUT ;
    USE SIGNAL ;
    PORT
      LAYER M5 ;
        RECT  55.344 129.516 55.368 129.6 ;
    END
  END i_pkt[544]
  PIN i_pkt[545]
    DIRECTION INPUT ;
    USE SIGNAL ;
    PORT
      LAYER M5 ;
        RECT  55.44 129.516 55.464 129.6 ;
    END
  END i_pkt[545]
  PIN i_pkt[546]
    DIRECTION INPUT ;
    USE SIGNAL ;
    PORT
      LAYER M5 ;
        RECT  55.536 129.516 55.56 129.6 ;
    END
  END i_pkt[546]
  PIN i_pkt[547]
    DIRECTION INPUT ;
    USE SIGNAL ;
    PORT
      LAYER M5 ;
        RECT  55.632 129.516 55.656 129.6 ;
    END
  END i_pkt[547]
  PIN i_pkt[548]
    DIRECTION INPUT ;
    USE SIGNAL ;
    PORT
      LAYER M5 ;
        RECT  55.728 129.516 55.752 129.6 ;
    END
  END i_pkt[548]
  PIN i_pkt[549]
    DIRECTION INPUT ;
    USE SIGNAL ;
    PORT
      LAYER M5 ;
        RECT  55.824 129.516 55.848 129.6 ;
    END
  END i_pkt[549]
  PIN i_pkt[54]
    DIRECTION INPUT ;
    USE SIGNAL ;
    PORT
      LAYER M5 ;
        RECT  78.96 129.516 78.984 129.6 ;
    END
  END i_pkt[54]
  PIN i_pkt[550]
    DIRECTION INPUT ;
    USE SIGNAL ;
    PORT
      LAYER M5 ;
        RECT  55.92 129.516 55.944 129.6 ;
    END
  END i_pkt[550]
  PIN i_pkt[551]
    DIRECTION INPUT ;
    USE SIGNAL ;
    PORT
      LAYER M5 ;
        RECT  56.016 129.516 56.04 129.6 ;
    END
  END i_pkt[551]
  PIN i_pkt[552]
    DIRECTION INPUT ;
    USE SIGNAL ;
    PORT
      LAYER M5 ;
        RECT  56.112 129.516 56.136 129.6 ;
    END
  END i_pkt[552]
  PIN i_pkt[553]
    DIRECTION INPUT ;
    USE SIGNAL ;
    PORT
      LAYER M5 ;
        RECT  56.208 129.516 56.232 129.6 ;
    END
  END i_pkt[553]
  PIN i_pkt[554]
    DIRECTION INPUT ;
    USE SIGNAL ;
    PORT
      LAYER M5 ;
        RECT  56.304 129.516 56.328 129.6 ;
    END
  END i_pkt[554]
  PIN i_pkt[555]
    DIRECTION INPUT ;
    USE SIGNAL ;
    PORT
      LAYER M5 ;
        RECT  56.4 129.516 56.424 129.6 ;
    END
  END i_pkt[555]
  PIN i_pkt[556]
    DIRECTION INPUT ;
    USE SIGNAL ;
    PORT
      LAYER M5 ;
        RECT  56.496 129.516 56.52 129.6 ;
    END
  END i_pkt[556]
  PIN i_pkt[557]
    DIRECTION INPUT ;
    USE SIGNAL ;
    PORT
      LAYER M5 ;
        RECT  56.592 129.516 56.616 129.6 ;
    END
  END i_pkt[557]
  PIN i_pkt[55]
    DIRECTION INPUT ;
    USE SIGNAL ;
    PORT
      LAYER M5 ;
        RECT  79.056 129.516 79.08 129.6 ;
    END
  END i_pkt[55]
  PIN i_pkt[56]
    DIRECTION INPUT ;
    USE SIGNAL ;
    PORT
      LAYER M5 ;
        RECT  79.152 129.516 79.176 129.6 ;
    END
  END i_pkt[56]
  PIN i_pkt[57]
    DIRECTION INPUT ;
    USE SIGNAL ;
    PORT
      LAYER M5 ;
        RECT  79.248 129.516 79.272 129.6 ;
    END
  END i_pkt[57]
  PIN i_pkt[58]
    DIRECTION INPUT ;
    USE SIGNAL ;
    PORT
      LAYER M5 ;
        RECT  79.344 129.516 79.368 129.6 ;
    END
  END i_pkt[58]
  PIN i_pkt[59]
    DIRECTION INPUT ;
    USE SIGNAL ;
    PORT
      LAYER M5 ;
        RECT  79.44 129.516 79.464 129.6 ;
    END
  END i_pkt[59]
  PIN i_pkt[5]
    DIRECTION INPUT ;
    USE SIGNAL ;
    PORT
      LAYER M5 ;
        RECT  61.2 129.516 61.224 129.6 ;
    END
  END i_pkt[5]
  PIN i_pkt[60]
    DIRECTION INPUT ;
    USE SIGNAL ;
    PORT
      LAYER M5 ;
        RECT  79.536 129.516 79.56 129.6 ;
    END
  END i_pkt[60]
  PIN i_pkt[61]
    DIRECTION INPUT ;
    USE SIGNAL ;
    PORT
      LAYER M5 ;
        RECT  79.632 129.516 79.656 129.6 ;
    END
  END i_pkt[61]
  PIN i_pkt[62]
    DIRECTION INPUT ;
    USE SIGNAL ;
    PORT
      LAYER M5 ;
        RECT  79.728 129.516 79.752 129.6 ;
    END
  END i_pkt[62]
  PIN i_pkt[63]
    DIRECTION INPUT ;
    USE SIGNAL ;
    PORT
      LAYER M5 ;
        RECT  79.824 129.516 79.848 129.6 ;
    END
  END i_pkt[63]
  PIN i_pkt[64]
    DIRECTION INPUT ;
    USE SIGNAL ;
    PORT
      LAYER M5 ;
        RECT  79.92 129.516 79.944 129.6 ;
    END
  END i_pkt[64]
  PIN i_pkt[65]
    DIRECTION INPUT ;
    USE SIGNAL ;
    PORT
      LAYER M5 ;
        RECT  80.016 129.516 80.04 129.6 ;
    END
  END i_pkt[65]
  PIN i_pkt[66]
    DIRECTION INPUT ;
    USE SIGNAL ;
    PORT
      LAYER M5 ;
        RECT  80.112 129.516 80.136 129.6 ;
    END
  END i_pkt[66]
  PIN i_pkt[67]
    DIRECTION INPUT ;
    USE SIGNAL ;
    PORT
      LAYER M5 ;
        RECT  80.208 129.516 80.232 129.6 ;
    END
  END i_pkt[67]
  PIN i_pkt[68]
    DIRECTION INPUT ;
    USE SIGNAL ;
    PORT
      LAYER M5 ;
        RECT  80.304 129.516 80.328 129.6 ;
    END
  END i_pkt[68]
  PIN i_pkt[69]
    DIRECTION INPUT ;
    USE SIGNAL ;
    PORT
      LAYER M5 ;
        RECT  80.4 129.516 80.424 129.6 ;
    END
  END i_pkt[69]
  PIN i_pkt[6]
    DIRECTION INPUT ;
    USE SIGNAL ;
    PORT
      LAYER M5 ;
        RECT  61.296 129.516 61.32 129.6 ;
    END
  END i_pkt[6]
  PIN i_pkt[70]
    DIRECTION INPUT ;
    USE SIGNAL ;
    PORT
      LAYER M5 ;
        RECT  80.496 129.516 80.52 129.6 ;
    END
  END i_pkt[70]
  PIN i_pkt[71]
    DIRECTION INPUT ;
    USE SIGNAL ;
    PORT
      LAYER M5 ;
        RECT  80.592 129.516 80.616 129.6 ;
    END
  END i_pkt[71]
  PIN i_pkt[72]
    DIRECTION INPUT ;
    USE SIGNAL ;
    PORT
      LAYER M5 ;
        RECT  80.688 129.516 80.712 129.6 ;
    END
  END i_pkt[72]
  PIN i_pkt[73]
    DIRECTION INPUT ;
    USE SIGNAL ;
    PORT
      LAYER M5 ;
        RECT  80.784 129.516 80.808 129.6 ;
    END
  END i_pkt[73]
  PIN i_pkt[74]
    DIRECTION INPUT ;
    USE SIGNAL ;
    PORT
      LAYER M5 ;
        RECT  80.88 129.516 80.904 129.6 ;
    END
  END i_pkt[74]
  PIN i_pkt[75]
    DIRECTION INPUT ;
    USE SIGNAL ;
    PORT
      LAYER M5 ;
        RECT  80.976 129.516 81 129.6 ;
    END
  END i_pkt[75]
  PIN i_pkt[76]
    DIRECTION INPUT ;
    USE SIGNAL ;
    PORT
      LAYER M5 ;
        RECT  81.072 129.516 81.096 129.6 ;
    END
  END i_pkt[76]
  PIN i_pkt[77]
    DIRECTION INPUT ;
    USE SIGNAL ;
    PORT
      LAYER M5 ;
        RECT  81.168 129.516 81.192 129.6 ;
    END
  END i_pkt[77]
  PIN i_pkt[78]
    DIRECTION INPUT ;
    USE SIGNAL ;
    PORT
      LAYER M5 ;
        RECT  81.264 129.516 81.288 129.6 ;
    END
  END i_pkt[78]
  PIN i_pkt[79]
    DIRECTION INPUT ;
    USE SIGNAL ;
    PORT
      LAYER M5 ;
        RECT  81.36 129.516 81.384 129.6 ;
    END
  END i_pkt[79]
  PIN i_pkt[7]
    DIRECTION INPUT ;
    USE SIGNAL ;
    PORT
      LAYER M5 ;
        RECT  61.392 129.516 61.416 129.6 ;
    END
  END i_pkt[7]
  PIN i_pkt[80]
    DIRECTION INPUT ;
    USE SIGNAL ;
    PORT
      LAYER M5 ;
        RECT  81.456 129.516 81.48 129.6 ;
    END
  END i_pkt[80]
  PIN i_pkt[81]
    DIRECTION INPUT ;
    USE SIGNAL ;
    PORT
      LAYER M5 ;
        RECT  81.552 129.516 81.576 129.6 ;
    END
  END i_pkt[81]
  PIN i_pkt[82]
    DIRECTION INPUT ;
    USE SIGNAL ;
    PORT
      LAYER M5 ;
        RECT  81.648 129.516 81.672 129.6 ;
    END
  END i_pkt[82]
  PIN i_pkt[83]
    DIRECTION INPUT ;
    USE SIGNAL ;
    PORT
      LAYER M5 ;
        RECT  81.744 129.516 81.768 129.6 ;
    END
  END i_pkt[83]
  PIN i_pkt[84]
    DIRECTION INPUT ;
    USE SIGNAL ;
    PORT
      LAYER M5 ;
        RECT  81.84 129.516 81.864 129.6 ;
    END
  END i_pkt[84]
  PIN i_pkt[85]
    DIRECTION INPUT ;
    USE SIGNAL ;
    PORT
      LAYER M5 ;
        RECT  81.936 129.516 81.96 129.6 ;
    END
  END i_pkt[85]
  PIN i_pkt[86]
    DIRECTION INPUT ;
    USE SIGNAL ;
    PORT
      LAYER M5 ;
        RECT  82.032 129.516 82.056 129.6 ;
    END
  END i_pkt[86]
  PIN i_pkt[87]
    DIRECTION INPUT ;
    USE SIGNAL ;
    PORT
      LAYER M5 ;
        RECT  82.128 129.516 82.152 129.6 ;
    END
  END i_pkt[87]
  PIN i_pkt[88]
    DIRECTION INPUT ;
    USE SIGNAL ;
    PORT
      LAYER M5 ;
        RECT  82.224 129.516 82.248 129.6 ;
    END
  END i_pkt[88]
  PIN i_pkt[89]
    DIRECTION INPUT ;
    USE SIGNAL ;
    PORT
      LAYER M5 ;
        RECT  82.32 129.516 82.344 129.6 ;
    END
  END i_pkt[89]
  PIN i_pkt[8]
    DIRECTION INPUT ;
    USE SIGNAL ;
    PORT
      LAYER M5 ;
        RECT  61.488 129.516 61.512 129.6 ;
    END
  END i_pkt[8]
  PIN i_pkt[90]
    DIRECTION INPUT ;
    USE SIGNAL ;
    PORT
      LAYER M5 ;
        RECT  82.416 129.516 82.44 129.6 ;
    END
  END i_pkt[90]
  PIN i_pkt[91]
    DIRECTION INPUT ;
    USE SIGNAL ;
    PORT
      LAYER M5 ;
        RECT  82.512 129.516 82.536 129.6 ;
    END
  END i_pkt[91]
  PIN i_pkt[92]
    DIRECTION INPUT ;
    USE SIGNAL ;
    PORT
      LAYER M5 ;
        RECT  82.608 129.516 82.632 129.6 ;
    END
  END i_pkt[92]
  PIN i_pkt[93]
    DIRECTION INPUT ;
    USE SIGNAL ;
    PORT
      LAYER M5 ;
        RECT  82.704 129.516 82.728 129.6 ;
    END
  END i_pkt[93]
  PIN i_pkt[94]
    DIRECTION INPUT ;
    USE SIGNAL ;
    PORT
      LAYER M5 ;
        RECT  82.8 129.516 82.824 129.6 ;
    END
  END i_pkt[94]
  PIN i_pkt[95]
    DIRECTION INPUT ;
    USE SIGNAL ;
    PORT
      LAYER M5 ;
        RECT  82.896 129.516 82.92 129.6 ;
    END
  END i_pkt[95]
  PIN i_pkt[96]
    DIRECTION INPUT ;
    USE SIGNAL ;
    PORT
      LAYER M5 ;
        RECT  92.208 129.516 92.232 129.6 ;
    END
  END i_pkt[96]
  PIN i_pkt[97]
    DIRECTION INPUT ;
    USE SIGNAL ;
    PORT
      LAYER M5 ;
        RECT  92.304 129.516 92.328 129.6 ;
    END
  END i_pkt[97]
  PIN i_pkt[98]
    DIRECTION INPUT ;
    USE SIGNAL ;
    PORT
      LAYER M5 ;
        RECT  92.4 129.516 92.424 129.6 ;
    END
  END i_pkt[98]
  PIN i_pkt[99]
    DIRECTION INPUT ;
    USE SIGNAL ;
    PORT
      LAYER M5 ;
        RECT  92.496 129.516 92.52 129.6 ;
    END
  END i_pkt[99]
  PIN i_pkt[9]
    DIRECTION INPUT ;
    USE SIGNAL ;
    PORT
      LAYER M5 ;
        RECT  61.584 129.516 61.608 129.6 ;
    END
  END i_pkt[9]
  PIN i_v[0]
    DIRECTION INPUT ;
    USE SIGNAL ;
    PORT
      LAYER M5 ;
        RECT  56.688 129.516 56.712 129.6 ;
    END
  END i_v[0]
  PIN i_v[1]
    DIRECTION INPUT ;
    USE SIGNAL ;
    PORT
      LAYER M5 ;
        RECT  56.784 129.516 56.808 129.6 ;
    END
  END i_v[1]
  PIN rn
    DIRECTION INPUT ;
    USE SIGNAL ;
    PORT
      LAYER M4 ;
        RECT  0 59.088 0.084 59.112 ;
    END
  END rn
  PIN vmq[0]
    DIRECTION OUTPUT ;
    USE SIGNAL ;
    PORT
      LAYER M4 ;
        RECT  172.716 70.704 172.8 70.728 ;
    END
  END vmq[0]
  PIN vmq[100]
    DIRECTION OUTPUT ;
    USE SIGNAL ;
    PORT
      LAYER M4 ;
        RECT  172.716 54.96 172.8 54.984 ;
    END
  END vmq[100]
  PIN vmq[101]
    DIRECTION OUTPUT ;
    USE SIGNAL ;
    PORT
      LAYER M4 ;
        RECT  172.716 55.056 172.8 55.08 ;
    END
  END vmq[101]
  PIN vmq[102]
    DIRECTION OUTPUT ;
    USE SIGNAL ;
    PORT
      LAYER M4 ;
        RECT  172.716 55.152 172.8 55.176 ;
    END
  END vmq[102]
  PIN vmq[103]
    DIRECTION OUTPUT ;
    USE SIGNAL ;
    PORT
      LAYER M4 ;
        RECT  172.716 55.248 172.8 55.272 ;
    END
  END vmq[103]
  PIN vmq[104]
    DIRECTION OUTPUT ;
    USE SIGNAL ;
    PORT
      LAYER M4 ;
        RECT  172.716 55.344 172.8 55.368 ;
    END
  END vmq[104]
  PIN vmq[105]
    DIRECTION OUTPUT ;
    USE SIGNAL ;
    PORT
      LAYER M4 ;
        RECT  172.716 55.44 172.8 55.464 ;
    END
  END vmq[105]
  PIN vmq[106]
    DIRECTION OUTPUT ;
    USE SIGNAL ;
    PORT
      LAYER M4 ;
        RECT  172.716 55.536 172.8 55.56 ;
    END
  END vmq[106]
  PIN vmq[107]
    DIRECTION OUTPUT ;
    USE SIGNAL ;
    PORT
      LAYER M4 ;
        RECT  172.716 55.632 172.8 55.656 ;
    END
  END vmq[107]
  PIN vmq[108]
    DIRECTION OUTPUT ;
    USE SIGNAL ;
    PORT
      LAYER M4 ;
        RECT  172.716 55.728 172.8 55.752 ;
    END
  END vmq[108]
  PIN vmq[109]
    DIRECTION OUTPUT ;
    USE SIGNAL ;
    PORT
      LAYER M4 ;
        RECT  172.716 55.824 172.8 55.848 ;
    END
  END vmq[109]
  PIN vmq[10]
    DIRECTION OUTPUT ;
    USE SIGNAL ;
    PORT
      LAYER M4 ;
        RECT  172.716 71.664 172.8 71.688 ;
    END
  END vmq[10]
  PIN vmq[110]
    DIRECTION OUTPUT ;
    USE SIGNAL ;
    PORT
      LAYER M4 ;
        RECT  172.716 55.92 172.8 55.944 ;
    END
  END vmq[110]
  PIN vmq[111]
    DIRECTION OUTPUT ;
    USE SIGNAL ;
    PORT
      LAYER M4 ;
        RECT  172.716 56.016 172.8 56.04 ;
    END
  END vmq[111]
  PIN vmq[112]
    DIRECTION OUTPUT ;
    USE SIGNAL ;
    PORT
      LAYER M4 ;
        RECT  172.716 56.112 172.8 56.136 ;
    END
  END vmq[112]
  PIN vmq[113]
    DIRECTION OUTPUT ;
    USE SIGNAL ;
    PORT
      LAYER M4 ;
        RECT  172.716 56.208 172.8 56.232 ;
    END
  END vmq[113]
  PIN vmq[114]
    DIRECTION OUTPUT ;
    USE SIGNAL ;
    PORT
      LAYER M4 ;
        RECT  172.716 56.304 172.8 56.328 ;
    END
  END vmq[114]
  PIN vmq[115]
    DIRECTION OUTPUT ;
    USE SIGNAL ;
    PORT
      LAYER M4 ;
        RECT  172.716 56.4 172.8 56.424 ;
    END
  END vmq[115]
  PIN vmq[116]
    DIRECTION OUTPUT ;
    USE SIGNAL ;
    PORT
      LAYER M4 ;
        RECT  172.716 56.496 172.8 56.52 ;
    END
  END vmq[116]
  PIN vmq[117]
    DIRECTION OUTPUT ;
    USE SIGNAL ;
    PORT
      LAYER M4 ;
        RECT  172.716 56.592 172.8 56.616 ;
    END
  END vmq[117]
  PIN vmq[118]
    DIRECTION OUTPUT ;
    USE SIGNAL ;
    PORT
      LAYER M4 ;
        RECT  172.716 56.688 172.8 56.712 ;
    END
  END vmq[118]
  PIN vmq[119]
    DIRECTION OUTPUT ;
    USE SIGNAL ;
    PORT
      LAYER M4 ;
        RECT  172.716 56.784 172.8 56.808 ;
    END
  END vmq[119]
  PIN vmq[11]
    DIRECTION OUTPUT ;
    USE SIGNAL ;
    PORT
      LAYER M4 ;
        RECT  172.716 71.76 172.8 71.784 ;
    END
  END vmq[11]
  PIN vmq[120]
    DIRECTION OUTPUT ;
    USE SIGNAL ;
    PORT
      LAYER M4 ;
        RECT  172.716 56.88 172.8 56.904 ;
    END
  END vmq[120]
  PIN vmq[121]
    DIRECTION OUTPUT ;
    USE SIGNAL ;
    PORT
      LAYER M4 ;
        RECT  172.716 56.976 172.8 57 ;
    END
  END vmq[121]
  PIN vmq[122]
    DIRECTION OUTPUT ;
    USE SIGNAL ;
    PORT
      LAYER M4 ;
        RECT  172.716 57.072 172.8 57.096 ;
    END
  END vmq[122]
  PIN vmq[123]
    DIRECTION OUTPUT ;
    USE SIGNAL ;
    PORT
      LAYER M4 ;
        RECT  172.716 57.168 172.8 57.192 ;
    END
  END vmq[123]
  PIN vmq[124]
    DIRECTION OUTPUT ;
    USE SIGNAL ;
    PORT
      LAYER M4 ;
        RECT  172.716 57.264 172.8 57.288 ;
    END
  END vmq[124]
  PIN vmq[125]
    DIRECTION OUTPUT ;
    USE SIGNAL ;
    PORT
      LAYER M4 ;
        RECT  172.716 57.36 172.8 57.384 ;
    END
  END vmq[125]
  PIN vmq[126]
    DIRECTION OUTPUT ;
    USE SIGNAL ;
    PORT
      LAYER M4 ;
        RECT  172.716 57.456 172.8 57.48 ;
    END
  END vmq[126]
  PIN vmq[127]
    DIRECTION OUTPUT ;
    USE SIGNAL ;
    PORT
      LAYER M4 ;
        RECT  172.716 51.408 172.8 51.432 ;
    END
  END vmq[127]
  PIN vmq[128]
    DIRECTION OUTPUT ;
    USE SIGNAL ;
    PORT
      LAYER M4 ;
        RECT  172.716 51.504 172.8 51.528 ;
    END
  END vmq[128]
  PIN vmq[129]
    DIRECTION OUTPUT ;
    USE SIGNAL ;
    PORT
      LAYER M4 ;
        RECT  172.716 51.6 172.8 51.624 ;
    END
  END vmq[129]
  PIN vmq[12]
    DIRECTION OUTPUT ;
    USE SIGNAL ;
    PORT
      LAYER M4 ;
        RECT  172.716 71.856 172.8 71.88 ;
    END
  END vmq[12]
  PIN vmq[130]
    DIRECTION OUTPUT ;
    USE SIGNAL ;
    PORT
      LAYER M4 ;
        RECT  172.716 51.696 172.8 51.72 ;
    END
  END vmq[130]
  PIN vmq[131]
    DIRECTION OUTPUT ;
    USE SIGNAL ;
    PORT
      LAYER M4 ;
        RECT  172.716 51.792 172.8 51.816 ;
    END
  END vmq[131]
  PIN vmq[132]
    DIRECTION OUTPUT ;
    USE SIGNAL ;
    PORT
      LAYER M4 ;
        RECT  172.716 51.888 172.8 51.912 ;
    END
  END vmq[132]
  PIN vmq[133]
    DIRECTION OUTPUT ;
    USE SIGNAL ;
    PORT
      LAYER M4 ;
        RECT  172.716 51.984 172.8 52.008 ;
    END
  END vmq[133]
  PIN vmq[134]
    DIRECTION OUTPUT ;
    USE SIGNAL ;
    PORT
      LAYER M4 ;
        RECT  172.716 52.08 172.8 52.104 ;
    END
  END vmq[134]
  PIN vmq[135]
    DIRECTION OUTPUT ;
    USE SIGNAL ;
    PORT
      LAYER M4 ;
        RECT  172.716 52.176 172.8 52.2 ;
    END
  END vmq[135]
  PIN vmq[136]
    DIRECTION OUTPUT ;
    USE SIGNAL ;
    PORT
      LAYER M4 ;
        RECT  172.716 52.272 172.8 52.296 ;
    END
  END vmq[136]
  PIN vmq[137]
    DIRECTION OUTPUT ;
    USE SIGNAL ;
    PORT
      LAYER M4 ;
        RECT  172.716 52.368 172.8 52.392 ;
    END
  END vmq[137]
  PIN vmq[138]
    DIRECTION OUTPUT ;
    USE SIGNAL ;
    PORT
      LAYER M4 ;
        RECT  172.716 52.464 172.8 52.488 ;
    END
  END vmq[138]
  PIN vmq[139]
    DIRECTION OUTPUT ;
    USE SIGNAL ;
    PORT
      LAYER M4 ;
        RECT  172.716 52.56 172.8 52.584 ;
    END
  END vmq[139]
  PIN vmq[13]
    DIRECTION OUTPUT ;
    USE SIGNAL ;
    PORT
      LAYER M4 ;
        RECT  172.716 71.952 172.8 71.976 ;
    END
  END vmq[13]
  PIN vmq[140]
    DIRECTION OUTPUT ;
    USE SIGNAL ;
    PORT
      LAYER M4 ;
        RECT  172.716 52.656 172.8 52.68 ;
    END
  END vmq[140]
  PIN vmq[141]
    DIRECTION OUTPUT ;
    USE SIGNAL ;
    PORT
      LAYER M4 ;
        RECT  172.716 52.752 172.8 52.776 ;
    END
  END vmq[141]
  PIN vmq[142]
    DIRECTION OUTPUT ;
    USE SIGNAL ;
    PORT
      LAYER M4 ;
        RECT  172.716 52.848 172.8 52.872 ;
    END
  END vmq[142]
  PIN vmq[143]
    DIRECTION OUTPUT ;
    USE SIGNAL ;
    PORT
      LAYER M4 ;
        RECT  172.716 52.944 172.8 52.968 ;
    END
  END vmq[143]
  PIN vmq[144]
    DIRECTION OUTPUT ;
    USE SIGNAL ;
    PORT
      LAYER M4 ;
        RECT  172.716 53.04 172.8 53.064 ;
    END
  END vmq[144]
  PIN vmq[145]
    DIRECTION OUTPUT ;
    USE SIGNAL ;
    PORT
      LAYER M4 ;
        RECT  172.716 53.136 172.8 53.16 ;
    END
  END vmq[145]
  PIN vmq[146]
    DIRECTION OUTPUT ;
    USE SIGNAL ;
    PORT
      LAYER M4 ;
        RECT  172.716 53.232 172.8 53.256 ;
    END
  END vmq[146]
  PIN vmq[147]
    DIRECTION OUTPUT ;
    USE SIGNAL ;
    PORT
      LAYER M4 ;
        RECT  172.716 53.328 172.8 53.352 ;
    END
  END vmq[147]
  PIN vmq[148]
    DIRECTION OUTPUT ;
    USE SIGNAL ;
    PORT
      LAYER M4 ;
        RECT  172.716 53.424 172.8 53.448 ;
    END
  END vmq[148]
  PIN vmq[149]
    DIRECTION OUTPUT ;
    USE SIGNAL ;
    PORT
      LAYER M4 ;
        RECT  172.716 53.52 172.8 53.544 ;
    END
  END vmq[149]
  PIN vmq[14]
    DIRECTION OUTPUT ;
    USE SIGNAL ;
    PORT
      LAYER M4 ;
        RECT  172.716 72.048 172.8 72.072 ;
    END
  END vmq[14]
  PIN vmq[150]
    DIRECTION OUTPUT ;
    USE SIGNAL ;
    PORT
      LAYER M4 ;
        RECT  172.716 53.616 172.8 53.64 ;
    END
  END vmq[150]
  PIN vmq[151]
    DIRECTION OUTPUT ;
    USE SIGNAL ;
    PORT
      LAYER M4 ;
        RECT  172.716 53.712 172.8 53.736 ;
    END
  END vmq[151]
  PIN vmq[152]
    DIRECTION OUTPUT ;
    USE SIGNAL ;
    PORT
      LAYER M4 ;
        RECT  172.716 53.808 172.8 53.832 ;
    END
  END vmq[152]
  PIN vmq[153]
    DIRECTION OUTPUT ;
    USE SIGNAL ;
    PORT
      LAYER M4 ;
        RECT  172.716 53.904 172.8 53.928 ;
    END
  END vmq[153]
  PIN vmq[154]
    DIRECTION OUTPUT ;
    USE SIGNAL ;
    PORT
      LAYER M4 ;
        RECT  172.716 54 172.8 54.024 ;
    END
  END vmq[154]
  PIN vmq[155]
    DIRECTION OUTPUT ;
    USE SIGNAL ;
    PORT
      LAYER M4 ;
        RECT  172.716 54.096 172.8 54.12 ;
    END
  END vmq[155]
  PIN vmq[156]
    DIRECTION OUTPUT ;
    USE SIGNAL ;
    PORT
      LAYER M4 ;
        RECT  172.716 54.192 172.8 54.216 ;
    END
  END vmq[156]
  PIN vmq[157]
    DIRECTION OUTPUT ;
    USE SIGNAL ;
    PORT
      LAYER M4 ;
        RECT  172.716 54.288 172.8 54.312 ;
    END
  END vmq[157]
  PIN vmq[158]
    DIRECTION OUTPUT ;
    USE SIGNAL ;
    PORT
      LAYER M4 ;
        RECT  172.716 54.384 172.8 54.408 ;
    END
  END vmq[158]
  PIN vmq[159]
    DIRECTION OUTPUT ;
    USE SIGNAL ;
    PORT
      LAYER M4 ;
        RECT  172.716 58.32 172.8 58.344 ;
    END
  END vmq[159]
  PIN vmq[15]
    DIRECTION OUTPUT ;
    USE SIGNAL ;
    PORT
      LAYER M4 ;
        RECT  172.716 72.144 172.8 72.168 ;
    END
  END vmq[15]
  PIN vmq[160]
    DIRECTION OUTPUT ;
    USE SIGNAL ;
    PORT
      LAYER M4 ;
        RECT  172.716 58.416 172.8 58.44 ;
    END
  END vmq[160]
  PIN vmq[161]
    DIRECTION OUTPUT ;
    USE SIGNAL ;
    PORT
      LAYER M4 ;
        RECT  172.716 58.512 172.8 58.536 ;
    END
  END vmq[161]
  PIN vmq[162]
    DIRECTION OUTPUT ;
    USE SIGNAL ;
    PORT
      LAYER M4 ;
        RECT  172.716 58.608 172.8 58.632 ;
    END
  END vmq[162]
  PIN vmq[163]
    DIRECTION OUTPUT ;
    USE SIGNAL ;
    PORT
      LAYER M4 ;
        RECT  172.716 58.704 172.8 58.728 ;
    END
  END vmq[163]
  PIN vmq[164]
    DIRECTION OUTPUT ;
    USE SIGNAL ;
    PORT
      LAYER M4 ;
        RECT  172.716 58.8 172.8 58.824 ;
    END
  END vmq[164]
  PIN vmq[165]
    DIRECTION OUTPUT ;
    USE SIGNAL ;
    PORT
      LAYER M4 ;
        RECT  172.716 58.896 172.8 58.92 ;
    END
  END vmq[165]
  PIN vmq[166]
    DIRECTION OUTPUT ;
    USE SIGNAL ;
    PORT
      LAYER M4 ;
        RECT  172.716 58.992 172.8 59.016 ;
    END
  END vmq[166]
  PIN vmq[167]
    DIRECTION OUTPUT ;
    USE SIGNAL ;
    PORT
      LAYER M4 ;
        RECT  172.716 59.088 172.8 59.112 ;
    END
  END vmq[167]
  PIN vmq[168]
    DIRECTION OUTPUT ;
    USE SIGNAL ;
    PORT
      LAYER M4 ;
        RECT  172.716 59.184 172.8 59.208 ;
    END
  END vmq[168]
  PIN vmq[169]
    DIRECTION OUTPUT ;
    USE SIGNAL ;
    PORT
      LAYER M4 ;
        RECT  172.716 59.28 172.8 59.304 ;
    END
  END vmq[169]
  PIN vmq[16]
    DIRECTION OUTPUT ;
    USE SIGNAL ;
    PORT
      LAYER M4 ;
        RECT  172.716 72.24 172.8 72.264 ;
    END
  END vmq[16]
  PIN vmq[170]
    DIRECTION OUTPUT ;
    USE SIGNAL ;
    PORT
      LAYER M4 ;
        RECT  172.716 59.376 172.8 59.4 ;
    END
  END vmq[170]
  PIN vmq[171]
    DIRECTION OUTPUT ;
    USE SIGNAL ;
    PORT
      LAYER M4 ;
        RECT  172.716 59.472 172.8 59.496 ;
    END
  END vmq[171]
  PIN vmq[172]
    DIRECTION OUTPUT ;
    USE SIGNAL ;
    PORT
      LAYER M4 ;
        RECT  172.716 59.568 172.8 59.592 ;
    END
  END vmq[172]
  PIN vmq[173]
    DIRECTION OUTPUT ;
    USE SIGNAL ;
    PORT
      LAYER M4 ;
        RECT  172.716 59.664 172.8 59.688 ;
    END
  END vmq[173]
  PIN vmq[174]
    DIRECTION OUTPUT ;
    USE SIGNAL ;
    PORT
      LAYER M4 ;
        RECT  172.716 59.76 172.8 59.784 ;
    END
  END vmq[174]
  PIN vmq[175]
    DIRECTION OUTPUT ;
    USE SIGNAL ;
    PORT
      LAYER M4 ;
        RECT  172.716 59.856 172.8 59.88 ;
    END
  END vmq[175]
  PIN vmq[176]
    DIRECTION OUTPUT ;
    USE SIGNAL ;
    PORT
      LAYER M4 ;
        RECT  172.716 59.952 172.8 59.976 ;
    END
  END vmq[176]
  PIN vmq[177]
    DIRECTION OUTPUT ;
    USE SIGNAL ;
    PORT
      LAYER M4 ;
        RECT  172.716 60.048 172.8 60.072 ;
    END
  END vmq[177]
  PIN vmq[178]
    DIRECTION OUTPUT ;
    USE SIGNAL ;
    PORT
      LAYER M4 ;
        RECT  172.716 60.144 172.8 60.168 ;
    END
  END vmq[178]
  PIN vmq[179]
    DIRECTION OUTPUT ;
    USE SIGNAL ;
    PORT
      LAYER M4 ;
        RECT  172.716 60.24 172.8 60.264 ;
    END
  END vmq[179]
  PIN vmq[17]
    DIRECTION OUTPUT ;
    USE SIGNAL ;
    PORT
      LAYER M4 ;
        RECT  172.716 72.336 172.8 72.36 ;
    END
  END vmq[17]
  PIN vmq[180]
    DIRECTION OUTPUT ;
    USE SIGNAL ;
    PORT
      LAYER M4 ;
        RECT  172.716 60.336 172.8 60.36 ;
    END
  END vmq[180]
  PIN vmq[181]
    DIRECTION OUTPUT ;
    USE SIGNAL ;
    PORT
      LAYER M4 ;
        RECT  172.716 60.432 172.8 60.456 ;
    END
  END vmq[181]
  PIN vmq[182]
    DIRECTION OUTPUT ;
    USE SIGNAL ;
    PORT
      LAYER M4 ;
        RECT  172.716 60.528 172.8 60.552 ;
    END
  END vmq[182]
  PIN vmq[183]
    DIRECTION OUTPUT ;
    USE SIGNAL ;
    PORT
      LAYER M4 ;
        RECT  172.716 60.624 172.8 60.648 ;
    END
  END vmq[183]
  PIN vmq[184]
    DIRECTION OUTPUT ;
    USE SIGNAL ;
    PORT
      LAYER M4 ;
        RECT  172.716 60.72 172.8 60.744 ;
    END
  END vmq[184]
  PIN vmq[185]
    DIRECTION OUTPUT ;
    USE SIGNAL ;
    PORT
      LAYER M4 ;
        RECT  172.716 60.816 172.8 60.84 ;
    END
  END vmq[185]
  PIN vmq[186]
    DIRECTION OUTPUT ;
    USE SIGNAL ;
    PORT
      LAYER M4 ;
        RECT  172.716 60.912 172.8 60.936 ;
    END
  END vmq[186]
  PIN vmq[187]
    DIRECTION OUTPUT ;
    USE SIGNAL ;
    PORT
      LAYER M4 ;
        RECT  172.716 61.008 172.8 61.032 ;
    END
  END vmq[187]
  PIN vmq[188]
    DIRECTION OUTPUT ;
    USE SIGNAL ;
    PORT
      LAYER M4 ;
        RECT  172.716 61.104 172.8 61.128 ;
    END
  END vmq[188]
  PIN vmq[189]
    DIRECTION OUTPUT ;
    USE SIGNAL ;
    PORT
      LAYER M4 ;
        RECT  172.716 61.2 172.8 61.224 ;
    END
  END vmq[189]
  PIN vmq[18]
    DIRECTION OUTPUT ;
    USE SIGNAL ;
    PORT
      LAYER M4 ;
        RECT  172.716 72.432 172.8 72.456 ;
    END
  END vmq[18]
  PIN vmq[190]
    DIRECTION OUTPUT ;
    USE SIGNAL ;
    PORT
      LAYER M4 ;
        RECT  172.716 61.296 172.8 61.32 ;
    END
  END vmq[190]
  PIN vmq[191]
    DIRECTION OUTPUT ;
    USE SIGNAL ;
    PORT
      LAYER M4 ;
        RECT  172.716 64.464 172.8 64.488 ;
    END
  END vmq[191]
  PIN vmq[192]
    DIRECTION OUTPUT ;
    USE SIGNAL ;
    PORT
      LAYER M4 ;
        RECT  172.716 64.56 172.8 64.584 ;
    END
  END vmq[192]
  PIN vmq[193]
    DIRECTION OUTPUT ;
    USE SIGNAL ;
    PORT
      LAYER M4 ;
        RECT  172.716 64.656 172.8 64.68 ;
    END
  END vmq[193]
  PIN vmq[194]
    DIRECTION OUTPUT ;
    USE SIGNAL ;
    PORT
      LAYER M4 ;
        RECT  172.716 64.752 172.8 64.776 ;
    END
  END vmq[194]
  PIN vmq[195]
    DIRECTION OUTPUT ;
    USE SIGNAL ;
    PORT
      LAYER M4 ;
        RECT  172.716 64.848 172.8 64.872 ;
    END
  END vmq[195]
  PIN vmq[196]
    DIRECTION OUTPUT ;
    USE SIGNAL ;
    PORT
      LAYER M4 ;
        RECT  172.716 64.944 172.8 64.968 ;
    END
  END vmq[196]
  PIN vmq[197]
    DIRECTION OUTPUT ;
    USE SIGNAL ;
    PORT
      LAYER M4 ;
        RECT  172.716 65.04 172.8 65.064 ;
    END
  END vmq[197]
  PIN vmq[198]
    DIRECTION OUTPUT ;
    USE SIGNAL ;
    PORT
      LAYER M4 ;
        RECT  172.716 65.136 172.8 65.16 ;
    END
  END vmq[198]
  PIN vmq[199]
    DIRECTION OUTPUT ;
    USE SIGNAL ;
    PORT
      LAYER M4 ;
        RECT  172.716 65.232 172.8 65.256 ;
    END
  END vmq[199]
  PIN vmq[19]
    DIRECTION OUTPUT ;
    USE SIGNAL ;
    PORT
      LAYER M4 ;
        RECT  172.716 72.528 172.8 72.552 ;
    END
  END vmq[19]
  PIN vmq[1]
    DIRECTION OUTPUT ;
    USE SIGNAL ;
    PORT
      LAYER M4 ;
        RECT  172.716 70.8 172.8 70.824 ;
    END
  END vmq[1]
  PIN vmq[200]
    DIRECTION OUTPUT ;
    USE SIGNAL ;
    PORT
      LAYER M4 ;
        RECT  172.716 65.328 172.8 65.352 ;
    END
  END vmq[200]
  PIN vmq[201]
    DIRECTION OUTPUT ;
    USE SIGNAL ;
    PORT
      LAYER M4 ;
        RECT  172.716 65.424 172.8 65.448 ;
    END
  END vmq[201]
  PIN vmq[202]
    DIRECTION OUTPUT ;
    USE SIGNAL ;
    PORT
      LAYER M4 ;
        RECT  172.716 65.52 172.8 65.544 ;
    END
  END vmq[202]
  PIN vmq[203]
    DIRECTION OUTPUT ;
    USE SIGNAL ;
    PORT
      LAYER M4 ;
        RECT  172.716 65.616 172.8 65.64 ;
    END
  END vmq[203]
  PIN vmq[204]
    DIRECTION OUTPUT ;
    USE SIGNAL ;
    PORT
      LAYER M4 ;
        RECT  172.716 65.712 172.8 65.736 ;
    END
  END vmq[204]
  PIN vmq[205]
    DIRECTION OUTPUT ;
    USE SIGNAL ;
    PORT
      LAYER M4 ;
        RECT  172.716 65.808 172.8 65.832 ;
    END
  END vmq[205]
  PIN vmq[206]
    DIRECTION OUTPUT ;
    USE SIGNAL ;
    PORT
      LAYER M4 ;
        RECT  172.716 65.904 172.8 65.928 ;
    END
  END vmq[206]
  PIN vmq[207]
    DIRECTION OUTPUT ;
    USE SIGNAL ;
    PORT
      LAYER M4 ;
        RECT  172.716 66 172.8 66.024 ;
    END
  END vmq[207]
  PIN vmq[208]
    DIRECTION OUTPUT ;
    USE SIGNAL ;
    PORT
      LAYER M4 ;
        RECT  172.716 66.096 172.8 66.12 ;
    END
  END vmq[208]
  PIN vmq[209]
    DIRECTION OUTPUT ;
    USE SIGNAL ;
    PORT
      LAYER M4 ;
        RECT  172.716 66.192 172.8 66.216 ;
    END
  END vmq[209]
  PIN vmq[20]
    DIRECTION OUTPUT ;
    USE SIGNAL ;
    PORT
      LAYER M4 ;
        RECT  172.716 72.624 172.8 72.648 ;
    END
  END vmq[20]
  PIN vmq[210]
    DIRECTION OUTPUT ;
    USE SIGNAL ;
    PORT
      LAYER M4 ;
        RECT  172.716 66.288 172.8 66.312 ;
    END
  END vmq[210]
  PIN vmq[211]
    DIRECTION OUTPUT ;
    USE SIGNAL ;
    PORT
      LAYER M4 ;
        RECT  172.716 66.384 172.8 66.408 ;
    END
  END vmq[211]
  PIN vmq[212]
    DIRECTION OUTPUT ;
    USE SIGNAL ;
    PORT
      LAYER M4 ;
        RECT  172.716 66.48 172.8 66.504 ;
    END
  END vmq[212]
  PIN vmq[213]
    DIRECTION OUTPUT ;
    USE SIGNAL ;
    PORT
      LAYER M4 ;
        RECT  172.716 66.576 172.8 66.6 ;
    END
  END vmq[213]
  PIN vmq[214]
    DIRECTION OUTPUT ;
    USE SIGNAL ;
    PORT
      LAYER M4 ;
        RECT  172.716 66.672 172.8 66.696 ;
    END
  END vmq[214]
  PIN vmq[215]
    DIRECTION OUTPUT ;
    USE SIGNAL ;
    PORT
      LAYER M4 ;
        RECT  172.716 66.768 172.8 66.792 ;
    END
  END vmq[215]
  PIN vmq[216]
    DIRECTION OUTPUT ;
    USE SIGNAL ;
    PORT
      LAYER M4 ;
        RECT  172.716 66.864 172.8 66.888 ;
    END
  END vmq[216]
  PIN vmq[217]
    DIRECTION OUTPUT ;
    USE SIGNAL ;
    PORT
      LAYER M4 ;
        RECT  172.716 66.96 172.8 66.984 ;
    END
  END vmq[217]
  PIN vmq[218]
    DIRECTION OUTPUT ;
    USE SIGNAL ;
    PORT
      LAYER M4 ;
        RECT  172.716 67.056 172.8 67.08 ;
    END
  END vmq[218]
  PIN vmq[219]
    DIRECTION OUTPUT ;
    USE SIGNAL ;
    PORT
      LAYER M4 ;
        RECT  172.716 67.152 172.8 67.176 ;
    END
  END vmq[219]
  PIN vmq[21]
    DIRECTION OUTPUT ;
    USE SIGNAL ;
    PORT
      LAYER M4 ;
        RECT  172.716 72.72 172.8 72.744 ;
    END
  END vmq[21]
  PIN vmq[220]
    DIRECTION OUTPUT ;
    USE SIGNAL ;
    PORT
      LAYER M4 ;
        RECT  172.716 67.248 172.8 67.272 ;
    END
  END vmq[220]
  PIN vmq[221]
    DIRECTION OUTPUT ;
    USE SIGNAL ;
    PORT
      LAYER M4 ;
        RECT  172.716 67.344 172.8 67.368 ;
    END
  END vmq[221]
  PIN vmq[222]
    DIRECTION OUTPUT ;
    USE SIGNAL ;
    PORT
      LAYER M4 ;
        RECT  172.716 67.44 172.8 67.464 ;
    END
  END vmq[222]
  PIN vmq[223]
    DIRECTION OUTPUT ;
    USE SIGNAL ;
    PORT
      LAYER M4 ;
        RECT  172.716 73.68 172.8 73.704 ;
    END
  END vmq[223]
  PIN vmq[224]
    DIRECTION OUTPUT ;
    USE SIGNAL ;
    PORT
      LAYER M4 ;
        RECT  172.716 73.776 172.8 73.8 ;
    END
  END vmq[224]
  PIN vmq[225]
    DIRECTION OUTPUT ;
    USE SIGNAL ;
    PORT
      LAYER M4 ;
        RECT  172.716 73.872 172.8 73.896 ;
    END
  END vmq[225]
  PIN vmq[226]
    DIRECTION OUTPUT ;
    USE SIGNAL ;
    PORT
      LAYER M4 ;
        RECT  172.716 73.968 172.8 73.992 ;
    END
  END vmq[226]
  PIN vmq[227]
    DIRECTION OUTPUT ;
    USE SIGNAL ;
    PORT
      LAYER M4 ;
        RECT  172.716 74.064 172.8 74.088 ;
    END
  END vmq[227]
  PIN vmq[228]
    DIRECTION OUTPUT ;
    USE SIGNAL ;
    PORT
      LAYER M4 ;
        RECT  172.716 74.16 172.8 74.184 ;
    END
  END vmq[228]
  PIN vmq[229]
    DIRECTION OUTPUT ;
    USE SIGNAL ;
    PORT
      LAYER M4 ;
        RECT  172.716 74.256 172.8 74.28 ;
    END
  END vmq[229]
  PIN vmq[22]
    DIRECTION OUTPUT ;
    USE SIGNAL ;
    PORT
      LAYER M4 ;
        RECT  172.716 72.816 172.8 72.84 ;
    END
  END vmq[22]
  PIN vmq[230]
    DIRECTION OUTPUT ;
    USE SIGNAL ;
    PORT
      LAYER M4 ;
        RECT  172.716 74.352 172.8 74.376 ;
    END
  END vmq[230]
  PIN vmq[231]
    DIRECTION OUTPUT ;
    USE SIGNAL ;
    PORT
      LAYER M4 ;
        RECT  172.716 74.448 172.8 74.472 ;
    END
  END vmq[231]
  PIN vmq[232]
    DIRECTION OUTPUT ;
    USE SIGNAL ;
    PORT
      LAYER M4 ;
        RECT  172.716 74.544 172.8 74.568 ;
    END
  END vmq[232]
  PIN vmq[233]
    DIRECTION OUTPUT ;
    USE SIGNAL ;
    PORT
      LAYER M4 ;
        RECT  172.716 74.64 172.8 74.664 ;
    END
  END vmq[233]
  PIN vmq[234]
    DIRECTION OUTPUT ;
    USE SIGNAL ;
    PORT
      LAYER M4 ;
        RECT  172.716 74.736 172.8 74.76 ;
    END
  END vmq[234]
  PIN vmq[235]
    DIRECTION OUTPUT ;
    USE SIGNAL ;
    PORT
      LAYER M4 ;
        RECT  172.716 74.832 172.8 74.856 ;
    END
  END vmq[235]
  PIN vmq[236]
    DIRECTION OUTPUT ;
    USE SIGNAL ;
    PORT
      LAYER M4 ;
        RECT  172.716 74.928 172.8 74.952 ;
    END
  END vmq[236]
  PIN vmq[237]
    DIRECTION OUTPUT ;
    USE SIGNAL ;
    PORT
      LAYER M4 ;
        RECT  172.716 75.024 172.8 75.048 ;
    END
  END vmq[237]
  PIN vmq[238]
    DIRECTION OUTPUT ;
    USE SIGNAL ;
    PORT
      LAYER M4 ;
        RECT  172.716 75.12 172.8 75.144 ;
    END
  END vmq[238]
  PIN vmq[239]
    DIRECTION OUTPUT ;
    USE SIGNAL ;
    PORT
      LAYER M4 ;
        RECT  172.716 75.216 172.8 75.24 ;
    END
  END vmq[239]
  PIN vmq[23]
    DIRECTION OUTPUT ;
    USE SIGNAL ;
    PORT
      LAYER M4 ;
        RECT  172.716 72.912 172.8 72.936 ;
    END
  END vmq[23]
  PIN vmq[240]
    DIRECTION OUTPUT ;
    USE SIGNAL ;
    PORT
      LAYER M4 ;
        RECT  172.716 75.312 172.8 75.336 ;
    END
  END vmq[240]
  PIN vmq[241]
    DIRECTION OUTPUT ;
    USE SIGNAL ;
    PORT
      LAYER M4 ;
        RECT  172.716 75.408 172.8 75.432 ;
    END
  END vmq[241]
  PIN vmq[242]
    DIRECTION OUTPUT ;
    USE SIGNAL ;
    PORT
      LAYER M4 ;
        RECT  172.716 75.504 172.8 75.528 ;
    END
  END vmq[242]
  PIN vmq[243]
    DIRECTION OUTPUT ;
    USE SIGNAL ;
    PORT
      LAYER M4 ;
        RECT  172.716 75.6 172.8 75.624 ;
    END
  END vmq[243]
  PIN vmq[244]
    DIRECTION OUTPUT ;
    USE SIGNAL ;
    PORT
      LAYER M4 ;
        RECT  172.716 75.696 172.8 75.72 ;
    END
  END vmq[244]
  PIN vmq[245]
    DIRECTION OUTPUT ;
    USE SIGNAL ;
    PORT
      LAYER M4 ;
        RECT  172.716 75.792 172.8 75.816 ;
    END
  END vmq[245]
  PIN vmq[246]
    DIRECTION OUTPUT ;
    USE SIGNAL ;
    PORT
      LAYER M4 ;
        RECT  172.716 75.888 172.8 75.912 ;
    END
  END vmq[246]
  PIN vmq[247]
    DIRECTION OUTPUT ;
    USE SIGNAL ;
    PORT
      LAYER M4 ;
        RECT  172.716 75.984 172.8 76.008 ;
    END
  END vmq[247]
  PIN vmq[248]
    DIRECTION OUTPUT ;
    USE SIGNAL ;
    PORT
      LAYER M4 ;
        RECT  172.716 76.08 172.8 76.104 ;
    END
  END vmq[248]
  PIN vmq[249]
    DIRECTION OUTPUT ;
    USE SIGNAL ;
    PORT
      LAYER M4 ;
        RECT  172.716 76.176 172.8 76.2 ;
    END
  END vmq[249]
  PIN vmq[24]
    DIRECTION OUTPUT ;
    USE SIGNAL ;
    PORT
      LAYER M4 ;
        RECT  172.716 73.008 172.8 73.032 ;
    END
  END vmq[24]
  PIN vmq[250]
    DIRECTION OUTPUT ;
    USE SIGNAL ;
    PORT
      LAYER M4 ;
        RECT  172.716 76.272 172.8 76.296 ;
    END
  END vmq[250]
  PIN vmq[251]
    DIRECTION OUTPUT ;
    USE SIGNAL ;
    PORT
      LAYER M4 ;
        RECT  172.716 76.368 172.8 76.392 ;
    END
  END vmq[251]
  PIN vmq[252]
    DIRECTION OUTPUT ;
    USE SIGNAL ;
    PORT
      LAYER M4 ;
        RECT  172.716 76.464 172.8 76.488 ;
    END
  END vmq[252]
  PIN vmq[253]
    DIRECTION OUTPUT ;
    USE SIGNAL ;
    PORT
      LAYER M4 ;
        RECT  172.716 76.56 172.8 76.584 ;
    END
  END vmq[253]
  PIN vmq[254]
    DIRECTION OUTPUT ;
    USE SIGNAL ;
    PORT
      LAYER M4 ;
        RECT  172.716 76.656 172.8 76.68 ;
    END
  END vmq[254]
  PIN vmq[255]
    DIRECTION OUTPUT ;
    USE SIGNAL ;
    PORT
      LAYER M4 ;
        RECT  172.716 77.52 172.8 77.544 ;
    END
  END vmq[255]
  PIN vmq[256]
    DIRECTION OUTPUT ;
    USE SIGNAL ;
    PORT
      LAYER M4 ;
        RECT  172.716 77.616 172.8 77.64 ;
    END
  END vmq[256]
  PIN vmq[257]
    DIRECTION OUTPUT ;
    USE SIGNAL ;
    PORT
      LAYER M4 ;
        RECT  172.716 77.712 172.8 77.736 ;
    END
  END vmq[257]
  PIN vmq[258]
    DIRECTION OUTPUT ;
    USE SIGNAL ;
    PORT
      LAYER M4 ;
        RECT  172.716 77.808 172.8 77.832 ;
    END
  END vmq[258]
  PIN vmq[259]
    DIRECTION OUTPUT ;
    USE SIGNAL ;
    PORT
      LAYER M4 ;
        RECT  172.716 77.904 172.8 77.928 ;
    END
  END vmq[259]
  PIN vmq[25]
    DIRECTION OUTPUT ;
    USE SIGNAL ;
    PORT
      LAYER M4 ;
        RECT  172.716 73.104 172.8 73.128 ;
    END
  END vmq[25]
  PIN vmq[260]
    DIRECTION OUTPUT ;
    USE SIGNAL ;
    PORT
      LAYER M4 ;
        RECT  172.716 78 172.8 78.024 ;
    END
  END vmq[260]
  PIN vmq[261]
    DIRECTION OUTPUT ;
    USE SIGNAL ;
    PORT
      LAYER M4 ;
        RECT  172.716 78.096 172.8 78.12 ;
    END
  END vmq[261]
  PIN vmq[262]
    DIRECTION OUTPUT ;
    USE SIGNAL ;
    PORT
      LAYER M4 ;
        RECT  172.716 78.192 172.8 78.216 ;
    END
  END vmq[262]
  PIN vmq[263]
    DIRECTION OUTPUT ;
    USE SIGNAL ;
    PORT
      LAYER M4 ;
        RECT  172.716 78.288 172.8 78.312 ;
    END
  END vmq[263]
  PIN vmq[264]
    DIRECTION OUTPUT ;
    USE SIGNAL ;
    PORT
      LAYER M4 ;
        RECT  172.716 78.384 172.8 78.408 ;
    END
  END vmq[264]
  PIN vmq[265]
    DIRECTION OUTPUT ;
    USE SIGNAL ;
    PORT
      LAYER M4 ;
        RECT  172.716 78.48 172.8 78.504 ;
    END
  END vmq[265]
  PIN vmq[266]
    DIRECTION OUTPUT ;
    USE SIGNAL ;
    PORT
      LAYER M4 ;
        RECT  172.716 78.576 172.8 78.6 ;
    END
  END vmq[266]
  PIN vmq[267]
    DIRECTION OUTPUT ;
    USE SIGNAL ;
    PORT
      LAYER M4 ;
        RECT  172.716 78.672 172.8 78.696 ;
    END
  END vmq[267]
  PIN vmq[268]
    DIRECTION OUTPUT ;
    USE SIGNAL ;
    PORT
      LAYER M4 ;
        RECT  172.716 78.768 172.8 78.792 ;
    END
  END vmq[268]
  PIN vmq[269]
    DIRECTION OUTPUT ;
    USE SIGNAL ;
    PORT
      LAYER M4 ;
        RECT  172.716 78.864 172.8 78.888 ;
    END
  END vmq[269]
  PIN vmq[26]
    DIRECTION OUTPUT ;
    USE SIGNAL ;
    PORT
      LAYER M4 ;
        RECT  172.716 73.2 172.8 73.224 ;
    END
  END vmq[26]
  PIN vmq[270]
    DIRECTION OUTPUT ;
    USE SIGNAL ;
    PORT
      LAYER M4 ;
        RECT  172.716 78.96 172.8 78.984 ;
    END
  END vmq[270]
  PIN vmq[271]
    DIRECTION OUTPUT ;
    USE SIGNAL ;
    PORT
      LAYER M4 ;
        RECT  172.716 79.056 172.8 79.08 ;
    END
  END vmq[271]
  PIN vmq[272]
    DIRECTION OUTPUT ;
    USE SIGNAL ;
    PORT
      LAYER M4 ;
        RECT  172.716 79.152 172.8 79.176 ;
    END
  END vmq[272]
  PIN vmq[273]
    DIRECTION OUTPUT ;
    USE SIGNAL ;
    PORT
      LAYER M4 ;
        RECT  172.716 79.248 172.8 79.272 ;
    END
  END vmq[273]
  PIN vmq[274]
    DIRECTION OUTPUT ;
    USE SIGNAL ;
    PORT
      LAYER M4 ;
        RECT  172.716 79.344 172.8 79.368 ;
    END
  END vmq[274]
  PIN vmq[275]
    DIRECTION OUTPUT ;
    USE SIGNAL ;
    PORT
      LAYER M4 ;
        RECT  172.716 79.44 172.8 79.464 ;
    END
  END vmq[275]
  PIN vmq[276]
    DIRECTION OUTPUT ;
    USE SIGNAL ;
    PORT
      LAYER M4 ;
        RECT  172.716 79.536 172.8 79.56 ;
    END
  END vmq[276]
  PIN vmq[277]
    DIRECTION OUTPUT ;
    USE SIGNAL ;
    PORT
      LAYER M4 ;
        RECT  172.716 79.632 172.8 79.656 ;
    END
  END vmq[277]
  PIN vmq[278]
    DIRECTION OUTPUT ;
    USE SIGNAL ;
    PORT
      LAYER M4 ;
        RECT  172.716 79.728 172.8 79.752 ;
    END
  END vmq[278]
  PIN vmq[279]
    DIRECTION OUTPUT ;
    USE SIGNAL ;
    PORT
      LAYER M4 ;
        RECT  172.716 79.824 172.8 79.848 ;
    END
  END vmq[279]
  PIN vmq[27]
    DIRECTION OUTPUT ;
    USE SIGNAL ;
    PORT
      LAYER M4 ;
        RECT  172.716 73.296 172.8 73.32 ;
    END
  END vmq[27]
  PIN vmq[280]
    DIRECTION OUTPUT ;
    USE SIGNAL ;
    PORT
      LAYER M4 ;
        RECT  172.716 79.92 172.8 79.944 ;
    END
  END vmq[280]
  PIN vmq[281]
    DIRECTION OUTPUT ;
    USE SIGNAL ;
    PORT
      LAYER M4 ;
        RECT  172.716 80.016 172.8 80.04 ;
    END
  END vmq[281]
  PIN vmq[282]
    DIRECTION OUTPUT ;
    USE SIGNAL ;
    PORT
      LAYER M4 ;
        RECT  172.716 80.112 172.8 80.136 ;
    END
  END vmq[282]
  PIN vmq[283]
    DIRECTION OUTPUT ;
    USE SIGNAL ;
    PORT
      LAYER M4 ;
        RECT  172.716 80.208 172.8 80.232 ;
    END
  END vmq[283]
  PIN vmq[284]
    DIRECTION OUTPUT ;
    USE SIGNAL ;
    PORT
      LAYER M4 ;
        RECT  172.716 80.304 172.8 80.328 ;
    END
  END vmq[284]
  PIN vmq[285]
    DIRECTION OUTPUT ;
    USE SIGNAL ;
    PORT
      LAYER M4 ;
        RECT  172.716 80.4 172.8 80.424 ;
    END
  END vmq[285]
  PIN vmq[286]
    DIRECTION OUTPUT ;
    USE SIGNAL ;
    PORT
      LAYER M4 ;
        RECT  172.716 80.496 172.8 80.52 ;
    END
  END vmq[286]
  PIN vmq[287]
    DIRECTION OUTPUT ;
    USE SIGNAL ;
    PORT
      LAYER M4 ;
        RECT  172.716 80.592 172.8 80.616 ;
    END
  END vmq[287]
  PIN vmq[288]
    DIRECTION OUTPUT ;
    USE SIGNAL ;
    PORT
      LAYER M4 ;
        RECT  172.716 80.688 172.8 80.712 ;
    END
  END vmq[288]
  PIN vmq[289]
    DIRECTION OUTPUT ;
    USE SIGNAL ;
    PORT
      LAYER M4 ;
        RECT  172.716 80.784 172.8 80.808 ;
    END
  END vmq[289]
  PIN vmq[28]
    DIRECTION OUTPUT ;
    USE SIGNAL ;
    PORT
      LAYER M4 ;
        RECT  172.716 73.392 172.8 73.416 ;
    END
  END vmq[28]
  PIN vmq[290]
    DIRECTION OUTPUT ;
    USE SIGNAL ;
    PORT
      LAYER M4 ;
        RECT  172.716 80.88 172.8 80.904 ;
    END
  END vmq[290]
  PIN vmq[291]
    DIRECTION OUTPUT ;
    USE SIGNAL ;
    PORT
      LAYER M4 ;
        RECT  172.716 80.976 172.8 81 ;
    END
  END vmq[291]
  PIN vmq[292]
    DIRECTION OUTPUT ;
    USE SIGNAL ;
    PORT
      LAYER M4 ;
        RECT  172.716 81.072 172.8 81.096 ;
    END
  END vmq[292]
  PIN vmq[293]
    DIRECTION OUTPUT ;
    USE SIGNAL ;
    PORT
      LAYER M4 ;
        RECT  172.716 81.168 172.8 81.192 ;
    END
  END vmq[293]
  PIN vmq[294]
    DIRECTION OUTPUT ;
    USE SIGNAL ;
    PORT
      LAYER M4 ;
        RECT  172.716 81.264 172.8 81.288 ;
    END
  END vmq[294]
  PIN vmq[295]
    DIRECTION OUTPUT ;
    USE SIGNAL ;
    PORT
      LAYER M4 ;
        RECT  172.716 81.36 172.8 81.384 ;
    END
  END vmq[295]
  PIN vmq[296]
    DIRECTION OUTPUT ;
    USE SIGNAL ;
    PORT
      LAYER M4 ;
        RECT  172.716 81.456 172.8 81.48 ;
    END
  END vmq[296]
  PIN vmq[297]
    DIRECTION OUTPUT ;
    USE SIGNAL ;
    PORT
      LAYER M4 ;
        RECT  172.716 81.552 172.8 81.576 ;
    END
  END vmq[297]
  PIN vmq[298]
    DIRECTION OUTPUT ;
    USE SIGNAL ;
    PORT
      LAYER M4 ;
        RECT  172.716 81.648 172.8 81.672 ;
    END
  END vmq[298]
  PIN vmq[299]
    DIRECTION OUTPUT ;
    USE SIGNAL ;
    PORT
      LAYER M4 ;
        RECT  172.716 81.744 172.8 81.768 ;
    END
  END vmq[299]
  PIN vmq[29]
    DIRECTION OUTPUT ;
    USE SIGNAL ;
    PORT
      LAYER M4 ;
        RECT  172.716 73.488 172.8 73.512 ;
    END
  END vmq[29]
  PIN vmq[2]
    DIRECTION OUTPUT ;
    USE SIGNAL ;
    PORT
      LAYER M4 ;
        RECT  172.716 70.896 172.8 70.92 ;
    END
  END vmq[2]
  PIN vmq[300]
    DIRECTION OUTPUT ;
    USE SIGNAL ;
    PORT
      LAYER M4 ;
        RECT  172.716 81.84 172.8 81.864 ;
    END
  END vmq[300]
  PIN vmq[301]
    DIRECTION OUTPUT ;
    USE SIGNAL ;
    PORT
      LAYER M4 ;
        RECT  172.716 81.936 172.8 81.96 ;
    END
  END vmq[301]
  PIN vmq[302]
    DIRECTION OUTPUT ;
    USE SIGNAL ;
    PORT
      LAYER M4 ;
        RECT  172.716 82.032 172.8 82.056 ;
    END
  END vmq[302]
  PIN vmq[303]
    DIRECTION OUTPUT ;
    USE SIGNAL ;
    PORT
      LAYER M4 ;
        RECT  172.716 82.128 172.8 82.152 ;
    END
  END vmq[303]
  PIN vmq[304]
    DIRECTION OUTPUT ;
    USE SIGNAL ;
    PORT
      LAYER M4 ;
        RECT  172.716 82.224 172.8 82.248 ;
    END
  END vmq[304]
  PIN vmq[305]
    DIRECTION OUTPUT ;
    USE SIGNAL ;
    PORT
      LAYER M4 ;
        RECT  172.716 82.32 172.8 82.344 ;
    END
  END vmq[305]
  PIN vmq[306]
    DIRECTION OUTPUT ;
    USE SIGNAL ;
    PORT
      LAYER M4 ;
        RECT  172.716 82.416 172.8 82.44 ;
    END
  END vmq[306]
  PIN vmq[307]
    DIRECTION OUTPUT ;
    USE SIGNAL ;
    PORT
      LAYER M4 ;
        RECT  172.716 82.512 172.8 82.536 ;
    END
  END vmq[307]
  PIN vmq[308]
    DIRECTION OUTPUT ;
    USE SIGNAL ;
    PORT
      LAYER M4 ;
        RECT  172.716 82.608 172.8 82.632 ;
    END
  END vmq[308]
  PIN vmq[309]
    DIRECTION OUTPUT ;
    USE SIGNAL ;
    PORT
      LAYER M4 ;
        RECT  172.716 82.704 172.8 82.728 ;
    END
  END vmq[309]
  PIN vmq[30]
    DIRECTION OUTPUT ;
    USE SIGNAL ;
    PORT
      LAYER M4 ;
        RECT  172.716 73.584 172.8 73.608 ;
    END
  END vmq[30]
  PIN vmq[310]
    DIRECTION OUTPUT ;
    USE SIGNAL ;
    PORT
      LAYER M4 ;
        RECT  172.716 82.8 172.8 82.824 ;
    END
  END vmq[310]
  PIN vmq[311]
    DIRECTION OUTPUT ;
    USE SIGNAL ;
    PORT
      LAYER M4 ;
        RECT  172.716 82.896 172.8 82.92 ;
    END
  END vmq[311]
  PIN vmq[312]
    DIRECTION OUTPUT ;
    USE SIGNAL ;
    PORT
      LAYER M4 ;
        RECT  172.716 82.992 172.8 83.016 ;
    END
  END vmq[312]
  PIN vmq[313]
    DIRECTION OUTPUT ;
    USE SIGNAL ;
    PORT
      LAYER M4 ;
        RECT  172.716 83.088 172.8 83.112 ;
    END
  END vmq[313]
  PIN vmq[314]
    DIRECTION OUTPUT ;
    USE SIGNAL ;
    PORT
      LAYER M4 ;
        RECT  172.716 83.184 172.8 83.208 ;
    END
  END vmq[314]
  PIN vmq[315]
    DIRECTION OUTPUT ;
    USE SIGNAL ;
    PORT
      LAYER M4 ;
        RECT  172.716 83.28 172.8 83.304 ;
    END
  END vmq[315]
  PIN vmq[316]
    DIRECTION OUTPUT ;
    USE SIGNAL ;
    PORT
      LAYER M4 ;
        RECT  172.716 83.376 172.8 83.4 ;
    END
  END vmq[316]
  PIN vmq[317]
    DIRECTION OUTPUT ;
    USE SIGNAL ;
    PORT
      LAYER M4 ;
        RECT  172.716 83.472 172.8 83.496 ;
    END
  END vmq[317]
  PIN vmq[318]
    DIRECTION OUTPUT ;
    USE SIGNAL ;
    PORT
      LAYER M4 ;
        RECT  172.716 83.568 172.8 83.592 ;
    END
  END vmq[318]
  PIN vmq[319]
    DIRECTION OUTPUT ;
    USE SIGNAL ;
    PORT
      LAYER M4 ;
        RECT  172.716 83.664 172.8 83.688 ;
    END
  END vmq[319]
  PIN vmq[31]
    DIRECTION OUTPUT ;
    USE SIGNAL ;
    PORT
      LAYER M4 ;
        RECT  172.716 67.536 172.8 67.56 ;
    END
  END vmq[31]
  PIN vmq[320]
    DIRECTION OUTPUT ;
    USE SIGNAL ;
    PORT
      LAYER M4 ;
        RECT  172.716 83.76 172.8 83.784 ;
    END
  END vmq[320]
  PIN vmq[321]
    DIRECTION OUTPUT ;
    USE SIGNAL ;
    PORT
      LAYER M4 ;
        RECT  172.716 83.856 172.8 83.88 ;
    END
  END vmq[321]
  PIN vmq[322]
    DIRECTION OUTPUT ;
    USE SIGNAL ;
    PORT
      LAYER M4 ;
        RECT  172.716 83.952 172.8 83.976 ;
    END
  END vmq[322]
  PIN vmq[323]
    DIRECTION OUTPUT ;
    USE SIGNAL ;
    PORT
      LAYER M4 ;
        RECT  172.716 84.048 172.8 84.072 ;
    END
  END vmq[323]
  PIN vmq[324]
    DIRECTION OUTPUT ;
    USE SIGNAL ;
    PORT
      LAYER M4 ;
        RECT  172.716 84.144 172.8 84.168 ;
    END
  END vmq[324]
  PIN vmq[325]
    DIRECTION OUTPUT ;
    USE SIGNAL ;
    PORT
      LAYER M4 ;
        RECT  172.716 84.24 172.8 84.264 ;
    END
  END vmq[325]
  PIN vmq[326]
    DIRECTION OUTPUT ;
    USE SIGNAL ;
    PORT
      LAYER M4 ;
        RECT  172.716 84.336 172.8 84.36 ;
    END
  END vmq[326]
  PIN vmq[327]
    DIRECTION OUTPUT ;
    USE SIGNAL ;
    PORT
      LAYER M4 ;
        RECT  172.716 84.432 172.8 84.456 ;
    END
  END vmq[327]
  PIN vmq[328]
    DIRECTION OUTPUT ;
    USE SIGNAL ;
    PORT
      LAYER M4 ;
        RECT  172.716 84.528 172.8 84.552 ;
    END
  END vmq[328]
  PIN vmq[329]
    DIRECTION OUTPUT ;
    USE SIGNAL ;
    PORT
      LAYER M4 ;
        RECT  172.716 84.624 172.8 84.648 ;
    END
  END vmq[329]
  PIN vmq[32]
    DIRECTION OUTPUT ;
    USE SIGNAL ;
    PORT
      LAYER M4 ;
        RECT  172.716 67.632 172.8 67.656 ;
    END
  END vmq[32]
  PIN vmq[330]
    DIRECTION OUTPUT ;
    USE SIGNAL ;
    PORT
      LAYER M4 ;
        RECT  172.716 84.72 172.8 84.744 ;
    END
  END vmq[330]
  PIN vmq[331]
    DIRECTION OUTPUT ;
    USE SIGNAL ;
    PORT
      LAYER M4 ;
        RECT  172.716 84.816 172.8 84.84 ;
    END
  END vmq[331]
  PIN vmq[332]
    DIRECTION OUTPUT ;
    USE SIGNAL ;
    PORT
      LAYER M4 ;
        RECT  172.716 84.912 172.8 84.936 ;
    END
  END vmq[332]
  PIN vmq[333]
    DIRECTION OUTPUT ;
    USE SIGNAL ;
    PORT
      LAYER M4 ;
        RECT  172.716 85.008 172.8 85.032 ;
    END
  END vmq[333]
  PIN vmq[334]
    DIRECTION OUTPUT ;
    USE SIGNAL ;
    PORT
      LAYER M4 ;
        RECT  172.716 85.104 172.8 85.128 ;
    END
  END vmq[334]
  PIN vmq[335]
    DIRECTION OUTPUT ;
    USE SIGNAL ;
    PORT
      LAYER M4 ;
        RECT  172.716 85.2 172.8 85.224 ;
    END
  END vmq[335]
  PIN vmq[336]
    DIRECTION OUTPUT ;
    USE SIGNAL ;
    PORT
      LAYER M4 ;
        RECT  172.716 85.296 172.8 85.32 ;
    END
  END vmq[336]
  PIN vmq[337]
    DIRECTION OUTPUT ;
    USE SIGNAL ;
    PORT
      LAYER M4 ;
        RECT  172.716 85.392 172.8 85.416 ;
    END
  END vmq[337]
  PIN vmq[33]
    DIRECTION OUTPUT ;
    USE SIGNAL ;
    PORT
      LAYER M4 ;
        RECT  172.716 67.728 172.8 67.752 ;
    END
  END vmq[33]
  PIN vmq[34]
    DIRECTION OUTPUT ;
    USE SIGNAL ;
    PORT
      LAYER M4 ;
        RECT  172.716 67.824 172.8 67.848 ;
    END
  END vmq[34]
  PIN vmq[35]
    DIRECTION OUTPUT ;
    USE SIGNAL ;
    PORT
      LAYER M4 ;
        RECT  172.716 67.92 172.8 67.944 ;
    END
  END vmq[35]
  PIN vmq[36]
    DIRECTION OUTPUT ;
    USE SIGNAL ;
    PORT
      LAYER M4 ;
        RECT  172.716 68.016 172.8 68.04 ;
    END
  END vmq[36]
  PIN vmq[37]
    DIRECTION OUTPUT ;
    USE SIGNAL ;
    PORT
      LAYER M4 ;
        RECT  172.716 68.112 172.8 68.136 ;
    END
  END vmq[37]
  PIN vmq[38]
    DIRECTION OUTPUT ;
    USE SIGNAL ;
    PORT
      LAYER M4 ;
        RECT  172.716 68.208 172.8 68.232 ;
    END
  END vmq[38]
  PIN vmq[39]
    DIRECTION OUTPUT ;
    USE SIGNAL ;
    PORT
      LAYER M4 ;
        RECT  172.716 68.304 172.8 68.328 ;
    END
  END vmq[39]
  PIN vmq[3]
    DIRECTION OUTPUT ;
    USE SIGNAL ;
    PORT
      LAYER M4 ;
        RECT  172.716 70.992 172.8 71.016 ;
    END
  END vmq[3]
  PIN vmq[40]
    DIRECTION OUTPUT ;
    USE SIGNAL ;
    PORT
      LAYER M4 ;
        RECT  172.716 68.4 172.8 68.424 ;
    END
  END vmq[40]
  PIN vmq[41]
    DIRECTION OUTPUT ;
    USE SIGNAL ;
    PORT
      LAYER M4 ;
        RECT  172.716 68.496 172.8 68.52 ;
    END
  END vmq[41]
  PIN vmq[42]
    DIRECTION OUTPUT ;
    USE SIGNAL ;
    PORT
      LAYER M4 ;
        RECT  172.716 68.592 172.8 68.616 ;
    END
  END vmq[42]
  PIN vmq[43]
    DIRECTION OUTPUT ;
    USE SIGNAL ;
    PORT
      LAYER M4 ;
        RECT  172.716 68.688 172.8 68.712 ;
    END
  END vmq[43]
  PIN vmq[44]
    DIRECTION OUTPUT ;
    USE SIGNAL ;
    PORT
      LAYER M4 ;
        RECT  172.716 68.784 172.8 68.808 ;
    END
  END vmq[44]
  PIN vmq[45]
    DIRECTION OUTPUT ;
    USE SIGNAL ;
    PORT
      LAYER M4 ;
        RECT  172.716 68.88 172.8 68.904 ;
    END
  END vmq[45]
  PIN vmq[46]
    DIRECTION OUTPUT ;
    USE SIGNAL ;
    PORT
      LAYER M4 ;
        RECT  172.716 68.976 172.8 69 ;
    END
  END vmq[46]
  PIN vmq[47]
    DIRECTION OUTPUT ;
    USE SIGNAL ;
    PORT
      LAYER M4 ;
        RECT  172.716 69.072 172.8 69.096 ;
    END
  END vmq[47]
  PIN vmq[48]
    DIRECTION OUTPUT ;
    USE SIGNAL ;
    PORT
      LAYER M4 ;
        RECT  172.716 69.168 172.8 69.192 ;
    END
  END vmq[48]
  PIN vmq[49]
    DIRECTION OUTPUT ;
    USE SIGNAL ;
    PORT
      LAYER M4 ;
        RECT  172.716 69.264 172.8 69.288 ;
    END
  END vmq[49]
  PIN vmq[4]
    DIRECTION OUTPUT ;
    USE SIGNAL ;
    PORT
      LAYER M4 ;
        RECT  172.716 71.088 172.8 71.112 ;
    END
  END vmq[4]
  PIN vmq[50]
    DIRECTION OUTPUT ;
    USE SIGNAL ;
    PORT
      LAYER M4 ;
        RECT  172.716 69.36 172.8 69.384 ;
    END
  END vmq[50]
  PIN vmq[51]
    DIRECTION OUTPUT ;
    USE SIGNAL ;
    PORT
      LAYER M4 ;
        RECT  172.716 69.456 172.8 69.48 ;
    END
  END vmq[51]
  PIN vmq[52]
    DIRECTION OUTPUT ;
    USE SIGNAL ;
    PORT
      LAYER M4 ;
        RECT  172.716 69.552 172.8 69.576 ;
    END
  END vmq[52]
  PIN vmq[53]
    DIRECTION OUTPUT ;
    USE SIGNAL ;
    PORT
      LAYER M4 ;
        RECT  172.716 69.648 172.8 69.672 ;
    END
  END vmq[53]
  PIN vmq[54]
    DIRECTION OUTPUT ;
    USE SIGNAL ;
    PORT
      LAYER M4 ;
        RECT  172.716 69.744 172.8 69.768 ;
    END
  END vmq[54]
  PIN vmq[55]
    DIRECTION OUTPUT ;
    USE SIGNAL ;
    PORT
      LAYER M4 ;
        RECT  172.716 69.84 172.8 69.864 ;
    END
  END vmq[55]
  PIN vmq[56]
    DIRECTION OUTPUT ;
    USE SIGNAL ;
    PORT
      LAYER M4 ;
        RECT  172.716 69.936 172.8 69.96 ;
    END
  END vmq[56]
  PIN vmq[57]
    DIRECTION OUTPUT ;
    USE SIGNAL ;
    PORT
      LAYER M4 ;
        RECT  172.716 70.032 172.8 70.056 ;
    END
  END vmq[57]
  PIN vmq[58]
    DIRECTION OUTPUT ;
    USE SIGNAL ;
    PORT
      LAYER M4 ;
        RECT  172.716 70.128 172.8 70.152 ;
    END
  END vmq[58]
  PIN vmq[59]
    DIRECTION OUTPUT ;
    USE SIGNAL ;
    PORT
      LAYER M4 ;
        RECT  172.716 70.224 172.8 70.248 ;
    END
  END vmq[59]
  PIN vmq[5]
    DIRECTION OUTPUT ;
    USE SIGNAL ;
    PORT
      LAYER M4 ;
        RECT  172.716 71.184 172.8 71.208 ;
    END
  END vmq[5]
  PIN vmq[60]
    DIRECTION OUTPUT ;
    USE SIGNAL ;
    PORT
      LAYER M4 ;
        RECT  172.716 70.32 172.8 70.344 ;
    END
  END vmq[60]
  PIN vmq[61]
    DIRECTION OUTPUT ;
    USE SIGNAL ;
    PORT
      LAYER M4 ;
        RECT  172.716 70.416 172.8 70.44 ;
    END
  END vmq[61]
  PIN vmq[62]
    DIRECTION OUTPUT ;
    USE SIGNAL ;
    PORT
      LAYER M4 ;
        RECT  172.716 70.512 172.8 70.536 ;
    END
  END vmq[62]
  PIN vmq[63]
    DIRECTION OUTPUT ;
    USE SIGNAL ;
    PORT
      LAYER M4 ;
        RECT  172.716 61.392 172.8 61.416 ;
    END
  END vmq[63]
  PIN vmq[64]
    DIRECTION OUTPUT ;
    USE SIGNAL ;
    PORT
      LAYER M4 ;
        RECT  172.716 61.488 172.8 61.512 ;
    END
  END vmq[64]
  PIN vmq[65]
    DIRECTION OUTPUT ;
    USE SIGNAL ;
    PORT
      LAYER M4 ;
        RECT  172.716 61.584 172.8 61.608 ;
    END
  END vmq[65]
  PIN vmq[66]
    DIRECTION OUTPUT ;
    USE SIGNAL ;
    PORT
      LAYER M4 ;
        RECT  172.716 61.68 172.8 61.704 ;
    END
  END vmq[66]
  PIN vmq[67]
    DIRECTION OUTPUT ;
    USE SIGNAL ;
    PORT
      LAYER M4 ;
        RECT  172.716 61.776 172.8 61.8 ;
    END
  END vmq[67]
  PIN vmq[68]
    DIRECTION OUTPUT ;
    USE SIGNAL ;
    PORT
      LAYER M4 ;
        RECT  172.716 61.872 172.8 61.896 ;
    END
  END vmq[68]
  PIN vmq[69]
    DIRECTION OUTPUT ;
    USE SIGNAL ;
    PORT
      LAYER M4 ;
        RECT  172.716 61.968 172.8 61.992 ;
    END
  END vmq[69]
  PIN vmq[6]
    DIRECTION OUTPUT ;
    USE SIGNAL ;
    PORT
      LAYER M4 ;
        RECT  172.716 71.28 172.8 71.304 ;
    END
  END vmq[6]
  PIN vmq[70]
    DIRECTION OUTPUT ;
    USE SIGNAL ;
    PORT
      LAYER M4 ;
        RECT  172.716 62.064 172.8 62.088 ;
    END
  END vmq[70]
  PIN vmq[71]
    DIRECTION OUTPUT ;
    USE SIGNAL ;
    PORT
      LAYER M4 ;
        RECT  172.716 62.16 172.8 62.184 ;
    END
  END vmq[71]
  PIN vmq[72]
    DIRECTION OUTPUT ;
    USE SIGNAL ;
    PORT
      LAYER M4 ;
        RECT  172.716 62.256 172.8 62.28 ;
    END
  END vmq[72]
  PIN vmq[73]
    DIRECTION OUTPUT ;
    USE SIGNAL ;
    PORT
      LAYER M4 ;
        RECT  172.716 62.352 172.8 62.376 ;
    END
  END vmq[73]
  PIN vmq[74]
    DIRECTION OUTPUT ;
    USE SIGNAL ;
    PORT
      LAYER M4 ;
        RECT  172.716 62.448 172.8 62.472 ;
    END
  END vmq[74]
  PIN vmq[75]
    DIRECTION OUTPUT ;
    USE SIGNAL ;
    PORT
      LAYER M4 ;
        RECT  172.716 62.544 172.8 62.568 ;
    END
  END vmq[75]
  PIN vmq[76]
    DIRECTION OUTPUT ;
    USE SIGNAL ;
    PORT
      LAYER M4 ;
        RECT  172.716 62.64 172.8 62.664 ;
    END
  END vmq[76]
  PIN vmq[77]
    DIRECTION OUTPUT ;
    USE SIGNAL ;
    PORT
      LAYER M4 ;
        RECT  172.716 62.736 172.8 62.76 ;
    END
  END vmq[77]
  PIN vmq[78]
    DIRECTION OUTPUT ;
    USE SIGNAL ;
    PORT
      LAYER M4 ;
        RECT  172.716 62.832 172.8 62.856 ;
    END
  END vmq[78]
  PIN vmq[79]
    DIRECTION OUTPUT ;
    USE SIGNAL ;
    PORT
      LAYER M4 ;
        RECT  172.716 62.928 172.8 62.952 ;
    END
  END vmq[79]
  PIN vmq[7]
    DIRECTION OUTPUT ;
    USE SIGNAL ;
    PORT
      LAYER M4 ;
        RECT  172.716 71.376 172.8 71.4 ;
    END
  END vmq[7]
  PIN vmq[80]
    DIRECTION OUTPUT ;
    USE SIGNAL ;
    PORT
      LAYER M4 ;
        RECT  172.716 63.024 172.8 63.048 ;
    END
  END vmq[80]
  PIN vmq[81]
    DIRECTION OUTPUT ;
    USE SIGNAL ;
    PORT
      LAYER M4 ;
        RECT  172.716 63.12 172.8 63.144 ;
    END
  END vmq[81]
  PIN vmq[82]
    DIRECTION OUTPUT ;
    USE SIGNAL ;
    PORT
      LAYER M4 ;
        RECT  172.716 63.216 172.8 63.24 ;
    END
  END vmq[82]
  PIN vmq[83]
    DIRECTION OUTPUT ;
    USE SIGNAL ;
    PORT
      LAYER M4 ;
        RECT  172.716 63.312 172.8 63.336 ;
    END
  END vmq[83]
  PIN vmq[84]
    DIRECTION OUTPUT ;
    USE SIGNAL ;
    PORT
      LAYER M4 ;
        RECT  172.716 63.408 172.8 63.432 ;
    END
  END vmq[84]
  PIN vmq[85]
    DIRECTION OUTPUT ;
    USE SIGNAL ;
    PORT
      LAYER M4 ;
        RECT  172.716 63.504 172.8 63.528 ;
    END
  END vmq[85]
  PIN vmq[86]
    DIRECTION OUTPUT ;
    USE SIGNAL ;
    PORT
      LAYER M4 ;
        RECT  172.716 63.6 172.8 63.624 ;
    END
  END vmq[86]
  PIN vmq[87]
    DIRECTION OUTPUT ;
    USE SIGNAL ;
    PORT
      LAYER M4 ;
        RECT  172.716 63.696 172.8 63.72 ;
    END
  END vmq[87]
  PIN vmq[88]
    DIRECTION OUTPUT ;
    USE SIGNAL ;
    PORT
      LAYER M4 ;
        RECT  172.716 63.792 172.8 63.816 ;
    END
  END vmq[88]
  PIN vmq[89]
    DIRECTION OUTPUT ;
    USE SIGNAL ;
    PORT
      LAYER M4 ;
        RECT  172.716 63.888 172.8 63.912 ;
    END
  END vmq[89]
  PIN vmq[8]
    DIRECTION OUTPUT ;
    USE SIGNAL ;
    PORT
      LAYER M4 ;
        RECT  172.716 71.472 172.8 71.496 ;
    END
  END vmq[8]
  PIN vmq[90]
    DIRECTION OUTPUT ;
    USE SIGNAL ;
    PORT
      LAYER M4 ;
        RECT  172.716 63.984 172.8 64.008 ;
    END
  END vmq[90]
  PIN vmq[91]
    DIRECTION OUTPUT ;
    USE SIGNAL ;
    PORT
      LAYER M4 ;
        RECT  172.716 64.08 172.8 64.104 ;
    END
  END vmq[91]
  PIN vmq[92]
    DIRECTION OUTPUT ;
    USE SIGNAL ;
    PORT
      LAYER M4 ;
        RECT  172.716 64.176 172.8 64.2 ;
    END
  END vmq[92]
  PIN vmq[93]
    DIRECTION OUTPUT ;
    USE SIGNAL ;
    PORT
      LAYER M4 ;
        RECT  172.716 64.272 172.8 64.296 ;
    END
  END vmq[93]
  PIN vmq[94]
    DIRECTION OUTPUT ;
    USE SIGNAL ;
    PORT
      LAYER M4 ;
        RECT  172.716 64.368 172.8 64.392 ;
    END
  END vmq[94]
  PIN vmq[95]
    DIRECTION OUTPUT ;
    USE SIGNAL ;
    PORT
      LAYER M4 ;
        RECT  172.716 54.48 172.8 54.504 ;
    END
  END vmq[95]
  PIN vmq[96]
    DIRECTION OUTPUT ;
    USE SIGNAL ;
    PORT
      LAYER M4 ;
        RECT  172.716 54.576 172.8 54.6 ;
    END
  END vmq[96]
  PIN vmq[97]
    DIRECTION OUTPUT ;
    USE SIGNAL ;
    PORT
      LAYER M4 ;
        RECT  172.716 54.672 172.8 54.696 ;
    END
  END vmq[97]
  PIN vmq[98]
    DIRECTION OUTPUT ;
    USE SIGNAL ;
    PORT
      LAYER M4 ;
        RECT  172.716 54.768 172.8 54.792 ;
    END
  END vmq[98]
  PIN vmq[99]
    DIRECTION OUTPUT ;
    USE SIGNAL ;
    PORT
      LAYER M4 ;
        RECT  172.716 54.864 172.8 54.888 ;
    END
  END vmq[99]
  PIN vmq[9]
    DIRECTION OUTPUT ;
    USE SIGNAL ;
    PORT
      LAYER M4 ;
        RECT  172.716 71.568 172.8 71.592 ;
    END
  END vmq[9]
  PIN vmr[0]
    DIRECTION INPUT ;
    USE SIGNAL ;
    PORT
      LAYER M4 ;
        RECT  0 59.184 0.084 59.208 ;
    END
  END vmr[0]
  PIN vmr[100]
    DIRECTION INPUT ;
    USE SIGNAL ;
    PORT
      LAYER M4 ;
        RECT  0 87.984 0.084 88.008 ;
    END
  END vmr[100]
  PIN vmr[101]
    DIRECTION INPUT ;
    USE SIGNAL ;
    PORT
      LAYER M4 ;
        RECT  0 88.08 0.084 88.104 ;
    END
  END vmr[101]
  PIN vmr[102]
    DIRECTION INPUT ;
    USE SIGNAL ;
    PORT
      LAYER M4 ;
        RECT  0 88.176 0.084 88.2 ;
    END
  END vmr[102]
  PIN vmr[103]
    DIRECTION INPUT ;
    USE SIGNAL ;
    PORT
      LAYER M4 ;
        RECT  0 88.272 0.084 88.296 ;
    END
  END vmr[103]
  PIN vmr[104]
    DIRECTION INPUT ;
    USE SIGNAL ;
    PORT
      LAYER M4 ;
        RECT  0 88.368 0.084 88.392 ;
    END
  END vmr[104]
  PIN vmr[105]
    DIRECTION INPUT ;
    USE SIGNAL ;
    PORT
      LAYER M4 ;
        RECT  0 88.464 0.084 88.488 ;
    END
  END vmr[105]
  PIN vmr[106]
    DIRECTION INPUT ;
    USE SIGNAL ;
    PORT
      LAYER M4 ;
        RECT  0 88.56 0.084 88.584 ;
    END
  END vmr[106]
  PIN vmr[107]
    DIRECTION INPUT ;
    USE SIGNAL ;
    PORT
      LAYER M4 ;
        RECT  0 88.656 0.084 88.68 ;
    END
  END vmr[107]
  PIN vmr[108]
    DIRECTION INPUT ;
    USE SIGNAL ;
    PORT
      LAYER M4 ;
        RECT  0 88.752 0.084 88.776 ;
    END
  END vmr[108]
  PIN vmr[109]
    DIRECTION INPUT ;
    USE SIGNAL ;
    PORT
      LAYER M4 ;
        RECT  0 88.848 0.084 88.872 ;
    END
  END vmr[109]
  PIN vmr[10]
    DIRECTION INPUT ;
    USE SIGNAL ;
    PORT
      LAYER M4 ;
        RECT  0 60.144 0.084 60.168 ;
    END
  END vmr[10]
  PIN vmr[110]
    DIRECTION INPUT ;
    USE SIGNAL ;
    PORT
      LAYER M4 ;
        RECT  0 88.944 0.084 88.968 ;
    END
  END vmr[110]
  PIN vmr[111]
    DIRECTION INPUT ;
    USE SIGNAL ;
    PORT
      LAYER M4 ;
        RECT  0 89.04 0.084 89.064 ;
    END
  END vmr[111]
  PIN vmr[112]
    DIRECTION INPUT ;
    USE SIGNAL ;
    PORT
      LAYER M4 ;
        RECT  0 89.136 0.084 89.16 ;
    END
  END vmr[112]
  PIN vmr[113]
    DIRECTION INPUT ;
    USE SIGNAL ;
    PORT
      LAYER M4 ;
        RECT  0 89.232 0.084 89.256 ;
    END
  END vmr[113]
  PIN vmr[114]
    DIRECTION INPUT ;
    USE SIGNAL ;
    PORT
      LAYER M4 ;
        RECT  0 89.328 0.084 89.352 ;
    END
  END vmr[114]
  PIN vmr[115]
    DIRECTION INPUT ;
    USE SIGNAL ;
    PORT
      LAYER M4 ;
        RECT  0 89.424 0.084 89.448 ;
    END
  END vmr[115]
  PIN vmr[116]
    DIRECTION INPUT ;
    USE SIGNAL ;
    PORT
      LAYER M4 ;
        RECT  0 89.52 0.084 89.544 ;
    END
  END vmr[116]
  PIN vmr[117]
    DIRECTION INPUT ;
    USE SIGNAL ;
    PORT
      LAYER M4 ;
        RECT  0 89.616 0.084 89.64 ;
    END
  END vmr[117]
  PIN vmr[118]
    DIRECTION INPUT ;
    USE SIGNAL ;
    PORT
      LAYER M4 ;
        RECT  0 89.712 0.084 89.736 ;
    END
  END vmr[118]
  PIN vmr[119]
    DIRECTION INPUT ;
    USE SIGNAL ;
    PORT
      LAYER M4 ;
        RECT  0 89.808 0.084 89.832 ;
    END
  END vmr[119]
  PIN vmr[11]
    DIRECTION INPUT ;
    USE SIGNAL ;
    PORT
      LAYER M4 ;
        RECT  0 60.24 0.084 60.264 ;
    END
  END vmr[11]
  PIN vmr[120]
    DIRECTION INPUT ;
    USE SIGNAL ;
    PORT
      LAYER M4 ;
        RECT  0 89.904 0.084 89.928 ;
    END
  END vmr[120]
  PIN vmr[121]
    DIRECTION INPUT ;
    USE SIGNAL ;
    PORT
      LAYER M4 ;
        RECT  0 90 0.084 90.024 ;
    END
  END vmr[121]
  PIN vmr[122]
    DIRECTION INPUT ;
    USE SIGNAL ;
    PORT
      LAYER M4 ;
        RECT  0 90.096 0.084 90.12 ;
    END
  END vmr[122]
  PIN vmr[123]
    DIRECTION INPUT ;
    USE SIGNAL ;
    PORT
      LAYER M4 ;
        RECT  0 90.192 0.084 90.216 ;
    END
  END vmr[123]
  PIN vmr[124]
    DIRECTION INPUT ;
    USE SIGNAL ;
    PORT
      LAYER M4 ;
        RECT  0 90.288 0.084 90.312 ;
    END
  END vmr[124]
  PIN vmr[125]
    DIRECTION INPUT ;
    USE SIGNAL ;
    PORT
      LAYER M4 ;
        RECT  0 90.384 0.084 90.408 ;
    END
  END vmr[125]
  PIN vmr[126]
    DIRECTION INPUT ;
    USE SIGNAL ;
    PORT
      LAYER M4 ;
        RECT  0 49.008 0.084 49.032 ;
    END
  END vmr[126]
  PIN vmr[127]
    DIRECTION INPUT ;
    USE SIGNAL ;
    PORT
      LAYER M4 ;
        RECT  0 49.104 0.084 49.128 ;
    END
  END vmr[127]
  PIN vmr[128]
    DIRECTION INPUT ;
    USE SIGNAL ;
    PORT
      LAYER M4 ;
        RECT  0 49.2 0.084 49.224 ;
    END
  END vmr[128]
  PIN vmr[129]
    DIRECTION INPUT ;
    USE SIGNAL ;
    PORT
      LAYER M4 ;
        RECT  0 49.296 0.084 49.32 ;
    END
  END vmr[129]
  PIN vmr[12]
    DIRECTION INPUT ;
    USE SIGNAL ;
    PORT
      LAYER M4 ;
        RECT  0 60.336 0.084 60.36 ;
    END
  END vmr[12]
  PIN vmr[130]
    DIRECTION INPUT ;
    USE SIGNAL ;
    PORT
      LAYER M4 ;
        RECT  0 49.392 0.084 49.416 ;
    END
  END vmr[130]
  PIN vmr[131]
    DIRECTION INPUT ;
    USE SIGNAL ;
    PORT
      LAYER M4 ;
        RECT  0 49.488 0.084 49.512 ;
    END
  END vmr[131]
  PIN vmr[132]
    DIRECTION INPUT ;
    USE SIGNAL ;
    PORT
      LAYER M4 ;
        RECT  0 49.584 0.084 49.608 ;
    END
  END vmr[132]
  PIN vmr[133]
    DIRECTION INPUT ;
    USE SIGNAL ;
    PORT
      LAYER M4 ;
        RECT  0 49.68 0.084 49.704 ;
    END
  END vmr[133]
  PIN vmr[134]
    DIRECTION INPUT ;
    USE SIGNAL ;
    PORT
      LAYER M4 ;
        RECT  0 49.776 0.084 49.8 ;
    END
  END vmr[134]
  PIN vmr[135]
    DIRECTION INPUT ;
    USE SIGNAL ;
    PORT
      LAYER M4 ;
        RECT  0 49.872 0.084 49.896 ;
    END
  END vmr[135]
  PIN vmr[136]
    DIRECTION INPUT ;
    USE SIGNAL ;
    PORT
      LAYER M4 ;
        RECT  0 49.968 0.084 49.992 ;
    END
  END vmr[136]
  PIN vmr[137]
    DIRECTION INPUT ;
    USE SIGNAL ;
    PORT
      LAYER M4 ;
        RECT  0 50.064 0.084 50.088 ;
    END
  END vmr[137]
  PIN vmr[138]
    DIRECTION INPUT ;
    USE SIGNAL ;
    PORT
      LAYER M4 ;
        RECT  0 50.16 0.084 50.184 ;
    END
  END vmr[138]
  PIN vmr[139]
    DIRECTION INPUT ;
    USE SIGNAL ;
    PORT
      LAYER M4 ;
        RECT  0 50.256 0.084 50.28 ;
    END
  END vmr[139]
  PIN vmr[13]
    DIRECTION INPUT ;
    USE SIGNAL ;
    PORT
      LAYER M4 ;
        RECT  0 60.432 0.084 60.456 ;
    END
  END vmr[13]
  PIN vmr[140]
    DIRECTION INPUT ;
    USE SIGNAL ;
    PORT
      LAYER M4 ;
        RECT  0 50.352 0.084 50.376 ;
    END
  END vmr[140]
  PIN vmr[141]
    DIRECTION INPUT ;
    USE SIGNAL ;
    PORT
      LAYER M4 ;
        RECT  0 50.448 0.084 50.472 ;
    END
  END vmr[141]
  PIN vmr[142]
    DIRECTION INPUT ;
    USE SIGNAL ;
    PORT
      LAYER M4 ;
        RECT  0 50.544 0.084 50.568 ;
    END
  END vmr[142]
  PIN vmr[143]
    DIRECTION INPUT ;
    USE SIGNAL ;
    PORT
      LAYER M4 ;
        RECT  0 50.64 0.084 50.664 ;
    END
  END vmr[143]
  PIN vmr[144]
    DIRECTION INPUT ;
    USE SIGNAL ;
    PORT
      LAYER M4 ;
        RECT  0 50.736 0.084 50.76 ;
    END
  END vmr[144]
  PIN vmr[145]
    DIRECTION INPUT ;
    USE SIGNAL ;
    PORT
      LAYER M4 ;
        RECT  0 50.832 0.084 50.856 ;
    END
  END vmr[145]
  PIN vmr[146]
    DIRECTION INPUT ;
    USE SIGNAL ;
    PORT
      LAYER M4 ;
        RECT  0 50.928 0.084 50.952 ;
    END
  END vmr[146]
  PIN vmr[147]
    DIRECTION INPUT ;
    USE SIGNAL ;
    PORT
      LAYER M4 ;
        RECT  0 51.024 0.084 51.048 ;
    END
  END vmr[147]
  PIN vmr[148]
    DIRECTION INPUT ;
    USE SIGNAL ;
    PORT
      LAYER M4 ;
        RECT  0 51.12 0.084 51.144 ;
    END
  END vmr[148]
  PIN vmr[149]
    DIRECTION INPUT ;
    USE SIGNAL ;
    PORT
      LAYER M4 ;
        RECT  0 51.216 0.084 51.24 ;
    END
  END vmr[149]
  PIN vmr[14]
    DIRECTION INPUT ;
    USE SIGNAL ;
    PORT
      LAYER M4 ;
        RECT  0 60.528 0.084 60.552 ;
    END
  END vmr[14]
  PIN vmr[150]
    DIRECTION INPUT ;
    USE SIGNAL ;
    PORT
      LAYER M4 ;
        RECT  0 51.312 0.084 51.336 ;
    END
  END vmr[150]
  PIN vmr[151]
    DIRECTION INPUT ;
    USE SIGNAL ;
    PORT
      LAYER M4 ;
        RECT  0 51.408 0.084 51.432 ;
    END
  END vmr[151]
  PIN vmr[152]
    DIRECTION INPUT ;
    USE SIGNAL ;
    PORT
      LAYER M4 ;
        RECT  0 51.504 0.084 51.528 ;
    END
  END vmr[152]
  PIN vmr[153]
    DIRECTION INPUT ;
    USE SIGNAL ;
    PORT
      LAYER M4 ;
        RECT  0 51.6 0.084 51.624 ;
    END
  END vmr[153]
  PIN vmr[154]
    DIRECTION INPUT ;
    USE SIGNAL ;
    PORT
      LAYER M4 ;
        RECT  0 51.696 0.084 51.72 ;
    END
  END vmr[154]
  PIN vmr[155]
    DIRECTION INPUT ;
    USE SIGNAL ;
    PORT
      LAYER M4 ;
        RECT  0 51.792 0.084 51.816 ;
    END
  END vmr[155]
  PIN vmr[156]
    DIRECTION INPUT ;
    USE SIGNAL ;
    PORT
      LAYER M4 ;
        RECT  0 51.888 0.084 51.912 ;
    END
  END vmr[156]
  PIN vmr[157]
    DIRECTION INPUT ;
    USE SIGNAL ;
    PORT
      LAYER M4 ;
        RECT  0 51.984 0.084 52.008 ;
    END
  END vmr[157]
  PIN vmr[158]
    DIRECTION INPUT ;
    USE SIGNAL ;
    PORT
      LAYER M4 ;
        RECT  0 29.808 0.084 29.832 ;
    END
  END vmr[158]
  PIN vmr[159]
    DIRECTION INPUT ;
    USE SIGNAL ;
    PORT
      LAYER M4 ;
        RECT  0 29.904 0.084 29.928 ;
    END
  END vmr[159]
  PIN vmr[15]
    DIRECTION INPUT ;
    USE SIGNAL ;
    PORT
      LAYER M4 ;
        RECT  0 60.624 0.084 60.648 ;
    END
  END vmr[15]
  PIN vmr[160]
    DIRECTION INPUT ;
    USE SIGNAL ;
    PORT
      LAYER M4 ;
        RECT  0 30 0.084 30.024 ;
    END
  END vmr[160]
  PIN vmr[161]
    DIRECTION INPUT ;
    USE SIGNAL ;
    PORT
      LAYER M4 ;
        RECT  0 30.096 0.084 30.12 ;
    END
  END vmr[161]
  PIN vmr[162]
    DIRECTION INPUT ;
    USE SIGNAL ;
    PORT
      LAYER M4 ;
        RECT  0 30.192 0.084 30.216 ;
    END
  END vmr[162]
  PIN vmr[163]
    DIRECTION INPUT ;
    USE SIGNAL ;
    PORT
      LAYER M4 ;
        RECT  0 30.288 0.084 30.312 ;
    END
  END vmr[163]
  PIN vmr[164]
    DIRECTION INPUT ;
    USE SIGNAL ;
    PORT
      LAYER M4 ;
        RECT  0 30.384 0.084 30.408 ;
    END
  END vmr[164]
  PIN vmr[165]
    DIRECTION INPUT ;
    USE SIGNAL ;
    PORT
      LAYER M4 ;
        RECT  0 30.48 0.084 30.504 ;
    END
  END vmr[165]
  PIN vmr[166]
    DIRECTION INPUT ;
    USE SIGNAL ;
    PORT
      LAYER M4 ;
        RECT  0 30.576 0.084 30.6 ;
    END
  END vmr[166]
  PIN vmr[167]
    DIRECTION INPUT ;
    USE SIGNAL ;
    PORT
      LAYER M4 ;
        RECT  0 30.672 0.084 30.696 ;
    END
  END vmr[167]
  PIN vmr[168]
    DIRECTION INPUT ;
    USE SIGNAL ;
    PORT
      LAYER M4 ;
        RECT  0 30.768 0.084 30.792 ;
    END
  END vmr[168]
  PIN vmr[169]
    DIRECTION INPUT ;
    USE SIGNAL ;
    PORT
      LAYER M4 ;
        RECT  0 30.864 0.084 30.888 ;
    END
  END vmr[169]
  PIN vmr[16]
    DIRECTION INPUT ;
    USE SIGNAL ;
    PORT
      LAYER M4 ;
        RECT  0 60.72 0.084 60.744 ;
    END
  END vmr[16]
  PIN vmr[170]
    DIRECTION INPUT ;
    USE SIGNAL ;
    PORT
      LAYER M4 ;
        RECT  0 30.96 0.084 30.984 ;
    END
  END vmr[170]
  PIN vmr[171]
    DIRECTION INPUT ;
    USE SIGNAL ;
    PORT
      LAYER M4 ;
        RECT  0 31.056 0.084 31.08 ;
    END
  END vmr[171]
  PIN vmr[172]
    DIRECTION INPUT ;
    USE SIGNAL ;
    PORT
      LAYER M4 ;
        RECT  0 31.152 0.084 31.176 ;
    END
  END vmr[172]
  PIN vmr[173]
    DIRECTION INPUT ;
    USE SIGNAL ;
    PORT
      LAYER M4 ;
        RECT  0 31.248 0.084 31.272 ;
    END
  END vmr[173]
  PIN vmr[174]
    DIRECTION INPUT ;
    USE SIGNAL ;
    PORT
      LAYER M4 ;
        RECT  0 31.344 0.084 31.368 ;
    END
  END vmr[174]
  PIN vmr[175]
    DIRECTION INPUT ;
    USE SIGNAL ;
    PORT
      LAYER M4 ;
        RECT  0 31.44 0.084 31.464 ;
    END
  END vmr[175]
  PIN vmr[176]
    DIRECTION INPUT ;
    USE SIGNAL ;
    PORT
      LAYER M4 ;
        RECT  0 31.536 0.084 31.56 ;
    END
  END vmr[176]
  PIN vmr[177]
    DIRECTION INPUT ;
    USE SIGNAL ;
    PORT
      LAYER M4 ;
        RECT  0 31.632 0.084 31.656 ;
    END
  END vmr[177]
  PIN vmr[178]
    DIRECTION INPUT ;
    USE SIGNAL ;
    PORT
      LAYER M4 ;
        RECT  0 31.728 0.084 31.752 ;
    END
  END vmr[178]
  PIN vmr[179]
    DIRECTION INPUT ;
    USE SIGNAL ;
    PORT
      LAYER M4 ;
        RECT  0 31.824 0.084 31.848 ;
    END
  END vmr[179]
  PIN vmr[17]
    DIRECTION INPUT ;
    USE SIGNAL ;
    PORT
      LAYER M4 ;
        RECT  0 60.816 0.084 60.84 ;
    END
  END vmr[17]
  PIN vmr[180]
    DIRECTION INPUT ;
    USE SIGNAL ;
    PORT
      LAYER M4 ;
        RECT  0 31.92 0.084 31.944 ;
    END
  END vmr[180]
  PIN vmr[181]
    DIRECTION INPUT ;
    USE SIGNAL ;
    PORT
      LAYER M4 ;
        RECT  0 32.016 0.084 32.04 ;
    END
  END vmr[181]
  PIN vmr[182]
    DIRECTION INPUT ;
    USE SIGNAL ;
    PORT
      LAYER M4 ;
        RECT  0 32.112 0.084 32.136 ;
    END
  END vmr[182]
  PIN vmr[183]
    DIRECTION INPUT ;
    USE SIGNAL ;
    PORT
      LAYER M4 ;
        RECT  0 32.208 0.084 32.232 ;
    END
  END vmr[183]
  PIN vmr[184]
    DIRECTION INPUT ;
    USE SIGNAL ;
    PORT
      LAYER M4 ;
        RECT  0 32.304 0.084 32.328 ;
    END
  END vmr[184]
  PIN vmr[185]
    DIRECTION INPUT ;
    USE SIGNAL ;
    PORT
      LAYER M4 ;
        RECT  0 32.4 0.084 32.424 ;
    END
  END vmr[185]
  PIN vmr[186]
    DIRECTION INPUT ;
    USE SIGNAL ;
    PORT
      LAYER M4 ;
        RECT  0 32.496 0.084 32.52 ;
    END
  END vmr[186]
  PIN vmr[187]
    DIRECTION INPUT ;
    USE SIGNAL ;
    PORT
      LAYER M4 ;
        RECT  0 32.592 0.084 32.616 ;
    END
  END vmr[187]
  PIN vmr[188]
    DIRECTION INPUT ;
    USE SIGNAL ;
    PORT
      LAYER M4 ;
        RECT  0 32.688 0.084 32.712 ;
    END
  END vmr[188]
  PIN vmr[189]
    DIRECTION INPUT ;
    USE SIGNAL ;
    PORT
      LAYER M4 ;
        RECT  0 32.784 0.084 32.808 ;
    END
  END vmr[189]
  PIN vmr[18]
    DIRECTION INPUT ;
    USE SIGNAL ;
    PORT
      LAYER M4 ;
        RECT  0 60.912 0.084 60.936 ;
    END
  END vmr[18]
  PIN vmr[190]
    DIRECTION INPUT ;
    USE SIGNAL ;
    PORT
      LAYER M4 ;
        RECT  0 10.608 0.084 10.632 ;
    END
  END vmr[190]
  PIN vmr[191]
    DIRECTION INPUT ;
    USE SIGNAL ;
    PORT
      LAYER M4 ;
        RECT  0 10.704 0.084 10.728 ;
    END
  END vmr[191]
  PIN vmr[192]
    DIRECTION INPUT ;
    USE SIGNAL ;
    PORT
      LAYER M4 ;
        RECT  0 10.8 0.084 10.824 ;
    END
  END vmr[192]
  PIN vmr[193]
    DIRECTION INPUT ;
    USE SIGNAL ;
    PORT
      LAYER M4 ;
        RECT  0 10.896 0.084 10.92 ;
    END
  END vmr[193]
  PIN vmr[194]
    DIRECTION INPUT ;
    USE SIGNAL ;
    PORT
      LAYER M4 ;
        RECT  0 10.992 0.084 11.016 ;
    END
  END vmr[194]
  PIN vmr[195]
    DIRECTION INPUT ;
    USE SIGNAL ;
    PORT
      LAYER M4 ;
        RECT  0 11.088 0.084 11.112 ;
    END
  END vmr[195]
  PIN vmr[196]
    DIRECTION INPUT ;
    USE SIGNAL ;
    PORT
      LAYER M4 ;
        RECT  0 11.184 0.084 11.208 ;
    END
  END vmr[196]
  PIN vmr[197]
    DIRECTION INPUT ;
    USE SIGNAL ;
    PORT
      LAYER M4 ;
        RECT  0 11.28 0.084 11.304 ;
    END
  END vmr[197]
  PIN vmr[198]
    DIRECTION INPUT ;
    USE SIGNAL ;
    PORT
      LAYER M4 ;
        RECT  0 11.376 0.084 11.4 ;
    END
  END vmr[198]
  PIN vmr[199]
    DIRECTION INPUT ;
    USE SIGNAL ;
    PORT
      LAYER M4 ;
        RECT  0 11.472 0.084 11.496 ;
    END
  END vmr[199]
  PIN vmr[19]
    DIRECTION INPUT ;
    USE SIGNAL ;
    PORT
      LAYER M4 ;
        RECT  0 61.008 0.084 61.032 ;
    END
  END vmr[19]
  PIN vmr[1]
    DIRECTION INPUT ;
    USE SIGNAL ;
    PORT
      LAYER M4 ;
        RECT  0 59.28 0.084 59.304 ;
    END
  END vmr[1]
  PIN vmr[200]
    DIRECTION INPUT ;
    USE SIGNAL ;
    PORT
      LAYER M4 ;
        RECT  0 11.568 0.084 11.592 ;
    END
  END vmr[200]
  PIN vmr[201]
    DIRECTION INPUT ;
    USE SIGNAL ;
    PORT
      LAYER M4 ;
        RECT  0 11.664 0.084 11.688 ;
    END
  END vmr[201]
  PIN vmr[202]
    DIRECTION INPUT ;
    USE SIGNAL ;
    PORT
      LAYER M4 ;
        RECT  0 11.76 0.084 11.784 ;
    END
  END vmr[202]
  PIN vmr[203]
    DIRECTION INPUT ;
    USE SIGNAL ;
    PORT
      LAYER M4 ;
        RECT  0 11.856 0.084 11.88 ;
    END
  END vmr[203]
  PIN vmr[204]
    DIRECTION INPUT ;
    USE SIGNAL ;
    PORT
      LAYER M4 ;
        RECT  0 11.952 0.084 11.976 ;
    END
  END vmr[204]
  PIN vmr[205]
    DIRECTION INPUT ;
    USE SIGNAL ;
    PORT
      LAYER M4 ;
        RECT  0 12.048 0.084 12.072 ;
    END
  END vmr[205]
  PIN vmr[206]
    DIRECTION INPUT ;
    USE SIGNAL ;
    PORT
      LAYER M4 ;
        RECT  0 12.144 0.084 12.168 ;
    END
  END vmr[206]
  PIN vmr[207]
    DIRECTION INPUT ;
    USE SIGNAL ;
    PORT
      LAYER M4 ;
        RECT  0 12.24 0.084 12.264 ;
    END
  END vmr[207]
  PIN vmr[208]
    DIRECTION INPUT ;
    USE SIGNAL ;
    PORT
      LAYER M4 ;
        RECT  0 12.336 0.084 12.36 ;
    END
  END vmr[208]
  PIN vmr[209]
    DIRECTION INPUT ;
    USE SIGNAL ;
    PORT
      LAYER M4 ;
        RECT  0 12.432 0.084 12.456 ;
    END
  END vmr[209]
  PIN vmr[20]
    DIRECTION INPUT ;
    USE SIGNAL ;
    PORT
      LAYER M4 ;
        RECT  0 61.104 0.084 61.128 ;
    END
  END vmr[20]
  PIN vmr[210]
    DIRECTION INPUT ;
    USE SIGNAL ;
    PORT
      LAYER M4 ;
        RECT  0 12.528 0.084 12.552 ;
    END
  END vmr[210]
  PIN vmr[211]
    DIRECTION INPUT ;
    USE SIGNAL ;
    PORT
      LAYER M4 ;
        RECT  0 12.624 0.084 12.648 ;
    END
  END vmr[211]
  PIN vmr[212]
    DIRECTION INPUT ;
    USE SIGNAL ;
    PORT
      LAYER M4 ;
        RECT  0 12.72 0.084 12.744 ;
    END
  END vmr[212]
  PIN vmr[213]
    DIRECTION INPUT ;
    USE SIGNAL ;
    PORT
      LAYER M4 ;
        RECT  0 12.816 0.084 12.84 ;
    END
  END vmr[213]
  PIN vmr[214]
    DIRECTION INPUT ;
    USE SIGNAL ;
    PORT
      LAYER M4 ;
        RECT  0 12.912 0.084 12.936 ;
    END
  END vmr[214]
  PIN vmr[215]
    DIRECTION INPUT ;
    USE SIGNAL ;
    PORT
      LAYER M4 ;
        RECT  0 13.008 0.084 13.032 ;
    END
  END vmr[215]
  PIN vmr[216]
    DIRECTION INPUT ;
    USE SIGNAL ;
    PORT
      LAYER M4 ;
        RECT  0 13.104 0.084 13.128 ;
    END
  END vmr[216]
  PIN vmr[217]
    DIRECTION INPUT ;
    USE SIGNAL ;
    PORT
      LAYER M4 ;
        RECT  0 13.2 0.084 13.224 ;
    END
  END vmr[217]
  PIN vmr[218]
    DIRECTION INPUT ;
    USE SIGNAL ;
    PORT
      LAYER M4 ;
        RECT  0 13.296 0.084 13.32 ;
    END
  END vmr[218]
  PIN vmr[219]
    DIRECTION INPUT ;
    USE SIGNAL ;
    PORT
      LAYER M4 ;
        RECT  0 13.392 0.084 13.416 ;
    END
  END vmr[219]
  PIN vmr[21]
    DIRECTION INPUT ;
    USE SIGNAL ;
    PORT
      LAYER M4 ;
        RECT  0 61.2 0.084 61.224 ;
    END
  END vmr[21]
  PIN vmr[220]
    DIRECTION INPUT ;
    USE SIGNAL ;
    PORT
      LAYER M4 ;
        RECT  0 13.488 0.084 13.512 ;
    END
  END vmr[220]
  PIN vmr[221]
    DIRECTION INPUT ;
    USE SIGNAL ;
    PORT
      LAYER M4 ;
        RECT  0 13.584 0.084 13.608 ;
    END
  END vmr[221]
  PIN vmr[222]
    DIRECTION INPUT ;
    USE SIGNAL ;
    PORT
      LAYER M4 ;
        RECT  0 122.736 0.084 122.76 ;
    END
  END vmr[222]
  PIN vmr[223]
    DIRECTION INPUT ;
    USE SIGNAL ;
    PORT
      LAYER M4 ;
        RECT  0 122.832 0.084 122.856 ;
    END
  END vmr[223]
  PIN vmr[224]
    DIRECTION INPUT ;
    USE SIGNAL ;
    PORT
      LAYER M4 ;
        RECT  0 122.928 0.084 122.952 ;
    END
  END vmr[224]
  PIN vmr[225]
    DIRECTION INPUT ;
    USE SIGNAL ;
    PORT
      LAYER M4 ;
        RECT  0 123.024 0.084 123.048 ;
    END
  END vmr[225]
  PIN vmr[226]
    DIRECTION INPUT ;
    USE SIGNAL ;
    PORT
      LAYER M4 ;
        RECT  0 123.12 0.084 123.144 ;
    END
  END vmr[226]
  PIN vmr[227]
    DIRECTION INPUT ;
    USE SIGNAL ;
    PORT
      LAYER M4 ;
        RECT  0 123.216 0.084 123.24 ;
    END
  END vmr[227]
  PIN vmr[228]
    DIRECTION INPUT ;
    USE SIGNAL ;
    PORT
      LAYER M4 ;
        RECT  0 123.312 0.084 123.336 ;
    END
  END vmr[228]
  PIN vmr[229]
    DIRECTION INPUT ;
    USE SIGNAL ;
    PORT
      LAYER M4 ;
        RECT  0 123.408 0.084 123.432 ;
    END
  END vmr[229]
  PIN vmr[22]
    DIRECTION INPUT ;
    USE SIGNAL ;
    PORT
      LAYER M4 ;
        RECT  0 61.296 0.084 61.32 ;
    END
  END vmr[22]
  PIN vmr[230]
    DIRECTION INPUT ;
    USE SIGNAL ;
    PORT
      LAYER M4 ;
        RECT  0 123.504 0.084 123.528 ;
    END
  END vmr[230]
  PIN vmr[231]
    DIRECTION INPUT ;
    USE SIGNAL ;
    PORT
      LAYER M4 ;
        RECT  0 123.6 0.084 123.624 ;
    END
  END vmr[231]
  PIN vmr[232]
    DIRECTION INPUT ;
    USE SIGNAL ;
    PORT
      LAYER M4 ;
        RECT  0 123.696 0.084 123.72 ;
    END
  END vmr[232]
  PIN vmr[233]
    DIRECTION INPUT ;
    USE SIGNAL ;
    PORT
      LAYER M4 ;
        RECT  0 123.792 0.084 123.816 ;
    END
  END vmr[233]
  PIN vmr[234]
    DIRECTION INPUT ;
    USE SIGNAL ;
    PORT
      LAYER M4 ;
        RECT  0 123.888 0.084 123.912 ;
    END
  END vmr[234]
  PIN vmr[235]
    DIRECTION INPUT ;
    USE SIGNAL ;
    PORT
      LAYER M4 ;
        RECT  0 123.984 0.084 124.008 ;
    END
  END vmr[235]
  PIN vmr[236]
    DIRECTION INPUT ;
    USE SIGNAL ;
    PORT
      LAYER M4 ;
        RECT  0 124.08 0.084 124.104 ;
    END
  END vmr[236]
  PIN vmr[237]
    DIRECTION INPUT ;
    USE SIGNAL ;
    PORT
      LAYER M4 ;
        RECT  0 124.176 0.084 124.2 ;
    END
  END vmr[237]
  PIN vmr[238]
    DIRECTION INPUT ;
    USE SIGNAL ;
    PORT
      LAYER M4 ;
        RECT  0 124.272 0.084 124.296 ;
    END
  END vmr[238]
  PIN vmr[239]
    DIRECTION INPUT ;
    USE SIGNAL ;
    PORT
      LAYER M4 ;
        RECT  0 124.368 0.084 124.392 ;
    END
  END vmr[239]
  PIN vmr[23]
    DIRECTION INPUT ;
    USE SIGNAL ;
    PORT
      LAYER M4 ;
        RECT  0 61.392 0.084 61.416 ;
    END
  END vmr[23]
  PIN vmr[240]
    DIRECTION INPUT ;
    USE SIGNAL ;
    PORT
      LAYER M4 ;
        RECT  0 124.464 0.084 124.488 ;
    END
  END vmr[240]
  PIN vmr[241]
    DIRECTION INPUT ;
    USE SIGNAL ;
    PORT
      LAYER M4 ;
        RECT  0 124.56 0.084 124.584 ;
    END
  END vmr[241]
  PIN vmr[242]
    DIRECTION INPUT ;
    USE SIGNAL ;
    PORT
      LAYER M4 ;
        RECT  0 124.656 0.084 124.68 ;
    END
  END vmr[242]
  PIN vmr[243]
    DIRECTION INPUT ;
    USE SIGNAL ;
    PORT
      LAYER M4 ;
        RECT  0 124.752 0.084 124.776 ;
    END
  END vmr[243]
  PIN vmr[244]
    DIRECTION INPUT ;
    USE SIGNAL ;
    PORT
      LAYER M4 ;
        RECT  0 124.848 0.084 124.872 ;
    END
  END vmr[244]
  PIN vmr[245]
    DIRECTION INPUT ;
    USE SIGNAL ;
    PORT
      LAYER M4 ;
        RECT  0 124.944 0.084 124.968 ;
    END
  END vmr[245]
  PIN vmr[246]
    DIRECTION INPUT ;
    USE SIGNAL ;
    PORT
      LAYER M4 ;
        RECT  0 125.04 0.084 125.064 ;
    END
  END vmr[246]
  PIN vmr[247]
    DIRECTION INPUT ;
    USE SIGNAL ;
    PORT
      LAYER M4 ;
        RECT  0 125.136 0.084 125.16 ;
    END
  END vmr[247]
  PIN vmr[248]
    DIRECTION INPUT ;
    USE SIGNAL ;
    PORT
      LAYER M4 ;
        RECT  0 125.232 0.084 125.256 ;
    END
  END vmr[248]
  PIN vmr[249]
    DIRECTION INPUT ;
    USE SIGNAL ;
    PORT
      LAYER M4 ;
        RECT  0 125.328 0.084 125.352 ;
    END
  END vmr[249]
  PIN vmr[24]
    DIRECTION INPUT ;
    USE SIGNAL ;
    PORT
      LAYER M4 ;
        RECT  0 61.488 0.084 61.512 ;
    END
  END vmr[24]
  PIN vmr[250]
    DIRECTION INPUT ;
    USE SIGNAL ;
    PORT
      LAYER M4 ;
        RECT  0 125.424 0.084 125.448 ;
    END
  END vmr[250]
  PIN vmr[251]
    DIRECTION INPUT ;
    USE SIGNAL ;
    PORT
      LAYER M4 ;
        RECT  0 125.52 0.084 125.544 ;
    END
  END vmr[251]
  PIN vmr[252]
    DIRECTION INPUT ;
    USE SIGNAL ;
    PORT
      LAYER M4 ;
        RECT  0 125.616 0.084 125.64 ;
    END
  END vmr[252]
  PIN vmr[253]
    DIRECTION INPUT ;
    USE SIGNAL ;
    PORT
      LAYER M4 ;
        RECT  0 125.712 0.084 125.736 ;
    END
  END vmr[253]
  PIN vmr[254]
    DIRECTION INPUT ;
    USE SIGNAL ;
    PORT
      LAYER M4 ;
        RECT  0 63.216 0.084 63.24 ;
    END
  END vmr[254]
  PIN vmr[255]
    DIRECTION INPUT ;
    USE SIGNAL ;
    PORT
      LAYER M4 ;
        RECT  0 63.312 0.084 63.336 ;
    END
  END vmr[255]
  PIN vmr[256]
    DIRECTION INPUT ;
    USE SIGNAL ;
    PORT
      LAYER M4 ;
        RECT  0 63.408 0.084 63.432 ;
    END
    PORT
      LAYER M4 ;
        RECT  0.06 63.408 2.408 63.432 ;
    END
  END vmr[256]
  PIN vmr[257]
    DIRECTION INPUT ;
    USE SIGNAL ;
    PORT
      LAYER M4 ;
        RECT  0 63.504 0.084 63.528 ;
    END
  END vmr[257]
  PIN vmr[258]
    DIRECTION INPUT ;
    USE SIGNAL ;
    PORT
      LAYER M4 ;
        RECT  0 63.6 0.084 63.624 ;
    END
  END vmr[258]
  PIN vmr[259]
    DIRECTION INPUT ;
    USE SIGNAL ;
    PORT
      LAYER M4 ;
        RECT  0 63.696 0.084 63.72 ;
    END
  END vmr[259]
  PIN vmr[25]
    DIRECTION INPUT ;
    USE SIGNAL ;
    PORT
      LAYER M4 ;
        RECT  0 61.584 0.084 61.608 ;
    END
  END vmr[25]
  PIN vmr[260]
    DIRECTION INPUT ;
    USE SIGNAL ;
    PORT
      LAYER M4 ;
        RECT  0 63.792 0.084 63.816 ;
    END
  END vmr[260]
  PIN vmr[261]
    DIRECTION INPUT ;
    USE SIGNAL ;
    PORT
      LAYER M4 ;
        RECT  0 63.888 0.084 63.912 ;
    END
  END vmr[261]
  PIN vmr[262]
    DIRECTION INPUT ;
    USE SIGNAL ;
    PORT
      LAYER M4 ;
        RECT  0 63.984 0.084 64.008 ;
    END
  END vmr[262]
  PIN vmr[263]
    DIRECTION INPUT ;
    USE SIGNAL ;
    PORT
      LAYER M4 ;
        RECT  0 64.08 0.084 64.104 ;
    END
  END vmr[263]
  PIN vmr[264]
    DIRECTION INPUT ;
    USE SIGNAL ;
    PORT
      LAYER M4 ;
        RECT  0 64.176 0.084 64.2 ;
    END
  END vmr[264]
  PIN vmr[265]
    DIRECTION INPUT ;
    USE SIGNAL ;
    PORT
      LAYER M4 ;
        RECT  0 64.272 0.084 64.296 ;
    END
  END vmr[265]
  PIN vmr[266]
    DIRECTION INPUT ;
    USE SIGNAL ;
    PORT
      LAYER M4 ;
        RECT  0 64.368 0.084 64.392 ;
    END
  END vmr[266]
  PIN vmr[267]
    DIRECTION INPUT ;
    USE SIGNAL ;
    PORT
      LAYER M4 ;
        RECT  0 64.464 0.084 64.488 ;
    END
  END vmr[267]
  PIN vmr[268]
    DIRECTION INPUT ;
    USE SIGNAL ;
    PORT
      LAYER M4 ;
        RECT  0 64.56 0.084 64.584 ;
    END
  END vmr[268]
  PIN vmr[269]
    DIRECTION INPUT ;
    USE SIGNAL ;
    PORT
      LAYER M4 ;
        RECT  0 64.656 0.084 64.68 ;
    END
  END vmr[269]
  PIN vmr[26]
    DIRECTION INPUT ;
    USE SIGNAL ;
    PORT
      LAYER M4 ;
        RECT  0 61.68 0.084 61.704 ;
    END
  END vmr[26]
  PIN vmr[270]
    DIRECTION INPUT ;
    USE SIGNAL ;
    PORT
      LAYER M4 ;
        RECT  0 64.752 0.084 64.776 ;
    END
  END vmr[270]
  PIN vmr[271]
    DIRECTION INPUT ;
    USE SIGNAL ;
    PORT
      LAYER M4 ;
        RECT  0 64.848 0.084 64.872 ;
    END
  END vmr[271]
  PIN vmr[272]
    DIRECTION INPUT ;
    USE SIGNAL ;
    PORT
      LAYER M4 ;
        RECT  0 64.944 0.084 64.968 ;
    END
  END vmr[272]
  PIN vmr[273]
    DIRECTION INPUT ;
    USE SIGNAL ;
    PORT
      LAYER M4 ;
        RECT  0 65.04 0.084 65.064 ;
    END
    PORT
      LAYER M4 ;
        RECT  0.06 65.04 0.137 65.064 ;
    END
  END vmr[273]
  PIN vmr[27]
    DIRECTION INPUT ;
    USE SIGNAL ;
    PORT
      LAYER M4 ;
        RECT  0 61.776 0.084 61.8 ;
    END
  END vmr[27]
  PIN vmr[28]
    DIRECTION INPUT ;
    USE SIGNAL ;
    PORT
      LAYER M4 ;
        RECT  0 61.872 0.084 61.896 ;
    END
  END vmr[28]
  PIN vmr[29]
    DIRECTION INPUT ;
    USE SIGNAL ;
    PORT
      LAYER M4 ;
        RECT  0 61.968 0.084 61.992 ;
    END
  END vmr[29]
  PIN vmr[2]
    DIRECTION INPUT ;
    USE SIGNAL ;
    PORT
      LAYER M4 ;
        RECT  0 59.376 0.084 59.4 ;
    END
  END vmr[2]
  PIN vmr[30]
    DIRECTION INPUT ;
    USE SIGNAL ;
    PORT
      LAYER M4 ;
        RECT  0 125.808 0.084 125.832 ;
    END
  END vmr[30]
  PIN vmr[31]
    DIRECTION INPUT ;
    USE SIGNAL ;
    PORT
      LAYER M4 ;
        RECT  0 125.904 0.084 125.928 ;
    END
  END vmr[31]
  PIN vmr[32]
    DIRECTION INPUT ;
    USE SIGNAL ;
    PORT
      LAYER M4 ;
        RECT  0 126 0.084 126.024 ;
    END
  END vmr[32]
  PIN vmr[33]
    DIRECTION INPUT ;
    USE SIGNAL ;
    PORT
      LAYER M4 ;
        RECT  0 126.096 0.084 126.12 ;
    END
  END vmr[33]
  PIN vmr[34]
    DIRECTION INPUT ;
    USE SIGNAL ;
    PORT
      LAYER M4 ;
        RECT  0 126.192 0.084 126.216 ;
    END
  END vmr[34]
  PIN vmr[35]
    DIRECTION INPUT ;
    USE SIGNAL ;
    PORT
      LAYER M4 ;
        RECT  0 126.288 0.084 126.312 ;
    END
  END vmr[35]
  PIN vmr[36]
    DIRECTION INPUT ;
    USE SIGNAL ;
    PORT
      LAYER M4 ;
        RECT  0 126.384 0.084 126.408 ;
    END
  END vmr[36]
  PIN vmr[37]
    DIRECTION INPUT ;
    USE SIGNAL ;
    PORT
      LAYER M4 ;
        RECT  0 126.48 0.084 126.504 ;
    END
  END vmr[37]
  PIN vmr[38]
    DIRECTION INPUT ;
    USE SIGNAL ;
    PORT
      LAYER M4 ;
        RECT  0 126.576 0.084 126.6 ;
    END
  END vmr[38]
  PIN vmr[39]
    DIRECTION INPUT ;
    USE SIGNAL ;
    PORT
      LAYER M4 ;
        RECT  0 126.672 0.084 126.696 ;
    END
  END vmr[39]
  PIN vmr[3]
    DIRECTION INPUT ;
    USE SIGNAL ;
    PORT
      LAYER M4 ;
        RECT  0 59.472 0.084 59.496 ;
    END
  END vmr[3]
  PIN vmr[40]
    DIRECTION INPUT ;
    USE SIGNAL ;
    PORT
      LAYER M4 ;
        RECT  0 126.768 0.084 126.792 ;
    END
  END vmr[40]
  PIN vmr[41]
    DIRECTION INPUT ;
    USE SIGNAL ;
    PORT
      LAYER M4 ;
        RECT  0 126.864 0.084 126.888 ;
    END
  END vmr[41]
  PIN vmr[42]
    DIRECTION INPUT ;
    USE SIGNAL ;
    PORT
      LAYER M4 ;
        RECT  0 126.96 0.084 126.984 ;
    END
  END vmr[42]
  PIN vmr[43]
    DIRECTION INPUT ;
    USE SIGNAL ;
    PORT
      LAYER M4 ;
        RECT  0 127.056 0.084 127.08 ;
    END
  END vmr[43]
  PIN vmr[44]
    DIRECTION INPUT ;
    USE SIGNAL ;
    PORT
      LAYER M4 ;
        RECT  0 127.152 0.084 127.176 ;
    END
  END vmr[44]
  PIN vmr[45]
    DIRECTION INPUT ;
    USE SIGNAL ;
    PORT
      LAYER M4 ;
        RECT  0 127.248 0.084 127.272 ;
    END
  END vmr[45]
  PIN vmr[46]
    DIRECTION INPUT ;
    USE SIGNAL ;
    PORT
      LAYER M4 ;
        RECT  0 127.344 0.084 127.368 ;
    END
  END vmr[46]
  PIN vmr[47]
    DIRECTION INPUT ;
    USE SIGNAL ;
    PORT
      LAYER M4 ;
        RECT  0 127.44 0.084 127.464 ;
    END
  END vmr[47]
  PIN vmr[48]
    DIRECTION INPUT ;
    USE SIGNAL ;
    PORT
      LAYER M4 ;
        RECT  0 127.536 0.084 127.56 ;
    END
  END vmr[48]
  PIN vmr[49]
    DIRECTION INPUT ;
    USE SIGNAL ;
    PORT
      LAYER M4 ;
        RECT  0 127.632 0.084 127.656 ;
    END
  END vmr[49]
  PIN vmr[4]
    DIRECTION INPUT ;
    USE SIGNAL ;
    PORT
      LAYER M4 ;
        RECT  0 59.568 0.084 59.592 ;
    END
  END vmr[4]
  PIN vmr[50]
    DIRECTION INPUT ;
    USE SIGNAL ;
    PORT
      LAYER M4 ;
        RECT  0 127.728 0.084 127.752 ;
    END
  END vmr[50]
  PIN vmr[51]
    DIRECTION INPUT ;
    USE SIGNAL ;
    PORT
      LAYER M4 ;
        RECT  0 127.824 0.084 127.848 ;
    END
  END vmr[51]
  PIN vmr[52]
    DIRECTION INPUT ;
    USE SIGNAL ;
    PORT
      LAYER M4 ;
        RECT  0 127.92 0.084 127.944 ;
    END
  END vmr[52]
  PIN vmr[53]
    DIRECTION INPUT ;
    USE SIGNAL ;
    PORT
      LAYER M4 ;
        RECT  0 128.016 0.084 128.04 ;
    END
  END vmr[53]
  PIN vmr[54]
    DIRECTION INPUT ;
    USE SIGNAL ;
    PORT
      LAYER M4 ;
        RECT  0 128.112 0.084 128.136 ;
    END
  END vmr[54]
  PIN vmr[55]
    DIRECTION INPUT ;
    USE SIGNAL ;
    PORT
      LAYER M4 ;
        RECT  0 128.208 0.084 128.232 ;
    END
  END vmr[55]
  PIN vmr[56]
    DIRECTION INPUT ;
    USE SIGNAL ;
    PORT
      LAYER M4 ;
        RECT  0 128.304 0.084 128.328 ;
    END
  END vmr[56]
  PIN vmr[57]
    DIRECTION INPUT ;
    USE SIGNAL ;
    PORT
      LAYER M4 ;
        RECT  0 128.4 0.084 128.424 ;
    END
  END vmr[57]
  PIN vmr[58]
    DIRECTION INPUT ;
    USE SIGNAL ;
    PORT
      LAYER M4 ;
        RECT  0 128.496 0.084 128.52 ;
    END
  END vmr[58]
  PIN vmr[59]
    DIRECTION INPUT ;
    USE SIGNAL ;
    PORT
      LAYER M4 ;
        RECT  0 128.592 0.084 128.616 ;
    END
  END vmr[59]
  PIN vmr[5]
    DIRECTION INPUT ;
    USE SIGNAL ;
    PORT
      LAYER M4 ;
        RECT  0 59.664 0.084 59.688 ;
    END
  END vmr[5]
  PIN vmr[60]
    DIRECTION INPUT ;
    USE SIGNAL ;
    PORT
      LAYER M4 ;
        RECT  0 128.688 0.084 128.712 ;
    END
  END vmr[60]
  PIN vmr[61]
    DIRECTION INPUT ;
    USE SIGNAL ;
    PORT
      LAYER M4 ;
        RECT  0 128.784 0.084 128.808 ;
    END
  END vmr[61]
  PIN vmr[62]
    DIRECTION INPUT ;
    USE SIGNAL ;
    PORT
      LAYER M4 ;
        RECT  0 106.608 0.084 106.632 ;
    END
  END vmr[62]
  PIN vmr[63]
    DIRECTION INPUT ;
    USE SIGNAL ;
    PORT
      LAYER M4 ;
        RECT  0 106.704 0.084 106.728 ;
    END
  END vmr[63]
  PIN vmr[64]
    DIRECTION INPUT ;
    USE SIGNAL ;
    PORT
      LAYER M4 ;
        RECT  0 106.8 0.084 106.824 ;
    END
  END vmr[64]
  PIN vmr[65]
    DIRECTION INPUT ;
    USE SIGNAL ;
    PORT
      LAYER M4 ;
        RECT  0 106.896 0.084 106.92 ;
    END
  END vmr[65]
  PIN vmr[66]
    DIRECTION INPUT ;
    USE SIGNAL ;
    PORT
      LAYER M4 ;
        RECT  0 106.992 0.084 107.016 ;
    END
  END vmr[66]
  PIN vmr[67]
    DIRECTION INPUT ;
    USE SIGNAL ;
    PORT
      LAYER M4 ;
        RECT  0 107.088 0.084 107.112 ;
    END
  END vmr[67]
  PIN vmr[68]
    DIRECTION INPUT ;
    USE SIGNAL ;
    PORT
      LAYER M4 ;
        RECT  0 107.184 0.084 107.208 ;
    END
  END vmr[68]
  PIN vmr[69]
    DIRECTION INPUT ;
    USE SIGNAL ;
    PORT
      LAYER M4 ;
        RECT  0 107.28 0.084 107.304 ;
    END
  END vmr[69]
  PIN vmr[6]
    DIRECTION INPUT ;
    USE SIGNAL ;
    PORT
      LAYER M4 ;
        RECT  0 59.76 0.084 59.784 ;
    END
  END vmr[6]
  PIN vmr[70]
    DIRECTION INPUT ;
    USE SIGNAL ;
    PORT
      LAYER M4 ;
        RECT  0 107.376 0.084 107.4 ;
    END
  END vmr[70]
  PIN vmr[71]
    DIRECTION INPUT ;
    USE SIGNAL ;
    PORT
      LAYER M4 ;
        RECT  0 107.472 0.084 107.496 ;
    END
  END vmr[71]
  PIN vmr[72]
    DIRECTION INPUT ;
    USE SIGNAL ;
    PORT
      LAYER M4 ;
        RECT  0 107.568 0.084 107.592 ;
    END
  END vmr[72]
  PIN vmr[73]
    DIRECTION INPUT ;
    USE SIGNAL ;
    PORT
      LAYER M4 ;
        RECT  0 107.664 0.084 107.688 ;
    END
  END vmr[73]
  PIN vmr[74]
    DIRECTION INPUT ;
    USE SIGNAL ;
    PORT
      LAYER M4 ;
        RECT  0 107.76 0.084 107.784 ;
    END
  END vmr[74]
  PIN vmr[75]
    DIRECTION INPUT ;
    USE SIGNAL ;
    PORT
      LAYER M4 ;
        RECT  0 107.856 0.084 107.88 ;
    END
  END vmr[75]
  PIN vmr[76]
    DIRECTION INPUT ;
    USE SIGNAL ;
    PORT
      LAYER M4 ;
        RECT  0 107.952 0.084 107.976 ;
    END
  END vmr[76]
  PIN vmr[77]
    DIRECTION INPUT ;
    USE SIGNAL ;
    PORT
      LAYER M4 ;
        RECT  0 108.048 0.084 108.072 ;
    END
  END vmr[77]
  PIN vmr[78]
    DIRECTION INPUT ;
    USE SIGNAL ;
    PORT
      LAYER M4 ;
        RECT  0 108.144 0.084 108.168 ;
    END
  END vmr[78]
  PIN vmr[79]
    DIRECTION INPUT ;
    USE SIGNAL ;
    PORT
      LAYER M4 ;
        RECT  0 108.24 0.084 108.264 ;
    END
  END vmr[79]
  PIN vmr[7]
    DIRECTION INPUT ;
    USE SIGNAL ;
    PORT
      LAYER M4 ;
        RECT  0 59.856 0.084 59.88 ;
    END
  END vmr[7]
  PIN vmr[80]
    DIRECTION INPUT ;
    USE SIGNAL ;
    PORT
      LAYER M4 ;
        RECT  0 108.336 0.084 108.36 ;
    END
  END vmr[80]
  PIN vmr[81]
    DIRECTION INPUT ;
    USE SIGNAL ;
    PORT
      LAYER M4 ;
        RECT  0 108.432 0.084 108.456 ;
    END
  END vmr[81]
  PIN vmr[82]
    DIRECTION INPUT ;
    USE SIGNAL ;
    PORT
      LAYER M4 ;
        RECT  0 108.528 0.084 108.552 ;
    END
  END vmr[82]
  PIN vmr[83]
    DIRECTION INPUT ;
    USE SIGNAL ;
    PORT
      LAYER M4 ;
        RECT  0 108.624 0.084 108.648 ;
    END
  END vmr[83]
  PIN vmr[84]
    DIRECTION INPUT ;
    USE SIGNAL ;
    PORT
      LAYER M4 ;
        RECT  0 108.72 0.084 108.744 ;
    END
  END vmr[84]
  PIN vmr[85]
    DIRECTION INPUT ;
    USE SIGNAL ;
    PORT
      LAYER M4 ;
        RECT  0 108.816 0.084 108.84 ;
    END
  END vmr[85]
  PIN vmr[86]
    DIRECTION INPUT ;
    USE SIGNAL ;
    PORT
      LAYER M4 ;
        RECT  0 108.912 0.084 108.936 ;
    END
  END vmr[86]
  PIN vmr[87]
    DIRECTION INPUT ;
    USE SIGNAL ;
    PORT
      LAYER M4 ;
        RECT  0 109.008 0.084 109.032 ;
    END
  END vmr[87]
  PIN vmr[88]
    DIRECTION INPUT ;
    USE SIGNAL ;
    PORT
      LAYER M4 ;
        RECT  0 109.104 0.084 109.128 ;
    END
  END vmr[88]
  PIN vmr[89]
    DIRECTION INPUT ;
    USE SIGNAL ;
    PORT
      LAYER M4 ;
        RECT  0 109.2 0.084 109.224 ;
    END
  END vmr[89]
  PIN vmr[8]
    DIRECTION INPUT ;
    USE SIGNAL ;
    PORT
      LAYER M4 ;
        RECT  0 59.952 0.084 59.976 ;
    END
  END vmr[8]
  PIN vmr[90]
    DIRECTION INPUT ;
    USE SIGNAL ;
    PORT
      LAYER M4 ;
        RECT  0 109.296 0.084 109.32 ;
    END
  END vmr[90]
  PIN vmr[91]
    DIRECTION INPUT ;
    USE SIGNAL ;
    PORT
      LAYER M4 ;
        RECT  0 109.392 0.084 109.416 ;
    END
  END vmr[91]
  PIN vmr[92]
    DIRECTION INPUT ;
    USE SIGNAL ;
    PORT
      LAYER M4 ;
        RECT  0 109.488 0.084 109.512 ;
    END
  END vmr[92]
  PIN vmr[93]
    DIRECTION INPUT ;
    USE SIGNAL ;
    PORT
      LAYER M4 ;
        RECT  0 109.584 0.084 109.608 ;
    END
  END vmr[93]
  PIN vmr[94]
    DIRECTION INPUT ;
    USE SIGNAL ;
    PORT
      LAYER M4 ;
        RECT  0 87.408 0.084 87.432 ;
    END
  END vmr[94]
  PIN vmr[95]
    DIRECTION INPUT ;
    USE SIGNAL ;
    PORT
      LAYER M4 ;
        RECT  0 87.504 0.084 87.528 ;
    END
  END vmr[95]
  PIN vmr[96]
    DIRECTION INPUT ;
    USE SIGNAL ;
    PORT
      LAYER M4 ;
        RECT  0 87.6 0.084 87.624 ;
    END
  END vmr[96]
  PIN vmr[97]
    DIRECTION INPUT ;
    USE SIGNAL ;
    PORT
      LAYER M4 ;
        RECT  0 87.696 0.084 87.72 ;
    END
  END vmr[97]
  PIN vmr[98]
    DIRECTION INPUT ;
    USE SIGNAL ;
    PORT
      LAYER M4 ;
        RECT  0 87.792 0.084 87.816 ;
    END
  END vmr[98]
  PIN vmr[99]
    DIRECTION INPUT ;
    USE SIGNAL ;
    PORT
      LAYER M4 ;
        RECT  0 87.888 0.084 87.912 ;
    END
  END vmr[99]
  PIN vmr[9]
    DIRECTION INPUT ;
    USE SIGNAL ;
    PORT
      LAYER M4 ;
        RECT  0 60.048 0.084 60.072 ;
    END
  END vmr[9]
  PIN VDD
    DIRECTION INOUT ;
    USE POWER ;
    PORT
      LAYER M5 ;
        RECT  169.992 2.151 170.112 127.449 ;
        RECT  164.592 2.151 164.712 127.449 ;
        RECT  159.192 2.151 159.312 127.449 ;
        RECT  153.792 2.151 153.912 127.449 ;
        RECT  148.392 2.151 148.512 127.449 ;
        RECT  142.992 2.151 143.112 127.449 ;
        RECT  137.592 2.151 137.712 127.449 ;
        RECT  132.192 2.151 132.312 127.449 ;
        RECT  126.792 2.151 126.912 127.449 ;
        RECT  121.392 2.151 121.512 127.449 ;
        RECT  115.992 2.151 116.112 127.449 ;
        RECT  110.592 2.151 110.712 127.449 ;
        RECT  105.192 2.151 105.312 127.449 ;
        RECT  99.792 2.151 99.912 127.449 ;
        RECT  94.392 2.151 94.512 127.449 ;
        RECT  88.992 2.151 89.112 127.449 ;
        RECT  83.592 2.151 83.712 127.449 ;
        RECT  78.192 2.151 78.312 127.449 ;
        RECT  72.792 2.151 72.912 127.449 ;
        RECT  67.392 2.151 67.512 127.449 ;
        RECT  61.992 2.151 62.112 127.449 ;
        RECT  56.592 2.151 56.712 127.449 ;
        RECT  51.192 2.151 51.312 127.449 ;
        RECT  45.792 2.151 45.912 127.449 ;
        RECT  40.392 2.151 40.512 127.449 ;
        RECT  34.992 2.151 35.112 127.449 ;
        RECT  29.592 2.151 29.712 127.449 ;
        RECT  24.192 2.151 24.312 127.449 ;
        RECT  18.792 2.151 18.912 127.449 ;
        RECT  13.392 2.151 13.512 127.449 ;
        RECT  7.992 2.151 8.112 127.449 ;
        RECT  2.592 2.151 2.712 127.449 ;
    END
  END VDD
  PIN VSS
    DIRECTION INOUT ;
    USE GROUND ;
    PORT
      LAYER M5 ;
        RECT  169.8 2.137 169.92 127.463 ;
        RECT  164.4 2.137 164.52 127.463 ;
        RECT  159 2.137 159.12 127.463 ;
        RECT  153.6 2.137 153.72 127.463 ;
        RECT  148.2 2.137 148.32 127.463 ;
        RECT  142.8 2.137 142.92 127.463 ;
        RECT  137.4 2.137 137.52 127.463 ;
        RECT  132 2.137 132.12 127.463 ;
        RECT  126.6 2.137 126.72 127.463 ;
        RECT  121.2 2.137 121.32 127.463 ;
        RECT  115.8 2.137 115.92 127.463 ;
        RECT  110.4 2.137 110.52 127.463 ;
        RECT  105 2.137 105.12 127.463 ;
        RECT  99.6 2.137 99.72 127.463 ;
        RECT  94.2 2.137 94.32 127.463 ;
        RECT  88.8 2.137 88.92 127.463 ;
        RECT  83.4 2.137 83.52 127.463 ;
        RECT  78 2.137 78.12 127.463 ;
        RECT  72.6 2.137 72.72 127.463 ;
        RECT  67.2 2.137 67.32 127.463 ;
        RECT  61.8 2.137 61.92 127.463 ;
        RECT  56.4 2.137 56.52 127.463 ;
        RECT  51 2.137 51.12 127.463 ;
        RECT  45.6 2.137 45.72 127.463 ;
        RECT  40.2 2.137 40.32 127.463 ;
        RECT  34.8 2.137 34.92 127.463 ;
        RECT  29.4 2.137 29.52 127.463 ;
        RECT  24 2.137 24.12 127.463 ;
        RECT  18.6 2.137 18.72 127.463 ;
        RECT  13.2 2.137 13.32 127.463 ;
        RECT  7.8 2.137 7.92 127.463 ;
        RECT  2.4 2.137 2.52 127.463 ;
    END
  END VSS
  # OT_OBS_CLOSED layer=M5 d_um=1.536 added=126
  OBS
    LAYER RVTN ;
     RECT  2.16 2.16 170.64 2.295 ;
     RECT  2.16 2.565 170.64 2.835 ;
     RECT  2.16 3.105 170.64 3.375 ;
     RECT  2.16 3.645 170.64 3.915 ;
     RECT  2.16 4.185 170.64 4.455 ;
     RECT  2.16 4.725 170.64 4.995 ;
     RECT  2.16 5.265 170.64 5.535 ;
     RECT  2.16 5.805 170.64 6.075 ;
     RECT  2.16 6.345 170.64 6.615 ;
     RECT  2.16 6.885 170.64 7.155 ;
     RECT  2.16 7.425 170.64 7.695 ;
     RECT  2.16 7.965 170.64 8.235 ;
     RECT  2.16 8.505 170.64 8.775 ;
     RECT  2.16 9.045 170.64 9.315 ;
     RECT  2.16 9.585 170.64 9.855 ;
     RECT  2.16 10.125 170.64 10.395 ;
     RECT  2.16 10.665 170.64 10.935 ;
     RECT  2.16 11.205 170.64 11.475 ;
     RECT  2.16 11.745 170.64 12.015 ;
     RECT  2.16 12.285 170.64 12.555 ;
     RECT  2.16 12.825 170.64 13.095 ;
     RECT  2.16 13.365 170.64 13.635 ;
     RECT  2.16 13.905 170.64 14.175 ;
     RECT  2.16 14.445 170.64 14.715 ;
     RECT  2.16 14.985 170.64 15.255 ;
     RECT  2.16 15.525 170.64 15.795 ;
     RECT  2.16 16.065 170.64 16.335 ;
     RECT  2.16 16.605 170.64 16.875 ;
     RECT  2.16 17.145 170.64 17.415 ;
     RECT  2.16 17.685 170.64 17.955 ;
     RECT  2.16 18.225 170.64 18.495 ;
     RECT  2.16 18.765 170.64 19.035 ;
     RECT  2.16 19.305 170.64 19.575 ;
     RECT  2.16 19.845 170.64 20.115 ;
     RECT  2.16 20.385 170.64 20.655 ;
     RECT  2.16 20.925 170.64 21.195 ;
     RECT  2.16 21.465 170.64 21.735 ;
     RECT  2.16 22.005 170.64 22.275 ;
     RECT  2.16 22.545 170.64 22.815 ;
     RECT  2.16 23.085 170.64 23.355 ;
     RECT  2.16 23.625 170.64 23.895 ;
     RECT  2.16 24.165 170.64 24.435 ;
     RECT  2.16 24.705 170.64 24.975 ;
     RECT  2.16 25.245 170.64 25.515 ;
     RECT  2.16 25.785 170.64 26.055 ;
     RECT  2.16 26.325 170.64 26.595 ;
     RECT  2.16 26.865 170.64 27.135 ;
     RECT  2.16 27.405 170.64 27.675 ;
     RECT  2.16 27.945 170.64 28.215 ;
     RECT  2.16 28.485 170.64 28.755 ;
     RECT  2.16 29.025 170.64 29.295 ;
     RECT  2.16 29.565 170.64 29.835 ;
     RECT  2.16 30.105 170.64 30.375 ;
     RECT  2.16 30.645 170.64 30.915 ;
     RECT  2.16 31.185 170.64 31.455 ;
     RECT  2.16 31.725 170.64 31.995 ;
     RECT  2.16 32.265 170.64 32.535 ;
     RECT  2.16 32.805 170.64 33.075 ;
     RECT  2.16 33.345 170.64 33.615 ;
     RECT  2.16 33.885 170.64 34.155 ;
     RECT  2.16 34.425 170.64 34.695 ;
     RECT  2.16 34.965 170.64 35.235 ;
     RECT  2.16 35.505 170.64 35.775 ;
     RECT  2.16 36.045 170.64 36.315 ;
     RECT  2.16 36.585 170.64 36.855 ;
     RECT  2.16 37.125 170.64 37.395 ;
     RECT  2.16 37.665 170.64 37.935 ;
     RECT  2.16 38.205 170.64 38.475 ;
     RECT  2.16 38.745 170.64 39.015 ;
     RECT  2.16 39.285 170.64 39.555 ;
     RECT  2.16 39.825 170.64 40.095 ;
     RECT  2.16 40.365 170.64 40.635 ;
     RECT  2.16 40.905 170.64 41.175 ;
     RECT  2.16 41.445 170.64 41.715 ;
     RECT  2.16 41.985 170.64 42.255 ;
     RECT  2.16 42.525 170.64 42.795 ;
     RECT  2.16 43.065 170.64 43.335 ;
     RECT  2.16 43.605 170.64 43.875 ;
     RECT  2.16 44.145 170.64 44.415 ;
     RECT  2.16 44.685 170.64 44.955 ;
     RECT  2.16 45.225 170.64 45.495 ;
     RECT  2.16 45.765 170.64 46.035 ;
     RECT  2.16 46.305 170.64 46.575 ;
     RECT  2.16 46.845 170.64 47.115 ;
     RECT  2.16 47.385 170.64 47.655 ;
     RECT  2.16 47.925 170.64 48.195 ;
     RECT  2.16 48.465 170.64 48.735 ;
     RECT  2.16 49.005 170.64 49.275 ;
     RECT  2.16 49.545 170.64 49.815 ;
     RECT  2.16 50.085 170.64 50.355 ;
     RECT  2.16 50.625 170.64 50.895 ;
     RECT  2.16 51.165 170.64 51.435 ;
     RECT  2.16 51.705 170.64 51.975 ;
     RECT  2.16 52.245 170.64 52.515 ;
     RECT  2.16 52.785 170.64 53.055 ;
     RECT  2.16 53.325 170.64 53.595 ;
     RECT  2.16 53.865 170.64 54.135 ;
     RECT  2.16 54.405 170.64 54.675 ;
     RECT  2.16 54.945 170.64 55.215 ;
     RECT  2.16 55.485 170.64 55.755 ;
     RECT  2.16 56.025 170.64 56.295 ;
     RECT  2.16 56.565 170.64 56.835 ;
     RECT  2.16 57.105 170.64 57.375 ;
     RECT  2.16 57.645 170.64 57.915 ;
     RECT  2.16 58.185 170.64 58.455 ;
     RECT  2.16 58.725 170.64 58.995 ;
     RECT  2.16 59.265 170.64 59.535 ;
     RECT  2.16 59.805 170.64 60.075 ;
     RECT  2.16 60.345 170.64 60.615 ;
     RECT  2.16 60.885 170.64 61.155 ;
     RECT  2.16 61.425 170.64 61.695 ;
     RECT  2.16 61.965 170.64 62.235 ;
     RECT  2.16 62.505 170.64 62.775 ;
     RECT  2.16 63.045 170.64 63.315 ;
     RECT  2.16 63.585 170.64 63.855 ;
     RECT  2.16 64.125 170.64 64.395 ;
     RECT  2.16 64.665 170.64 64.935 ;
     RECT  2.16 65.205 170.64 65.475 ;
     RECT  2.16 65.745 170.64 66.015 ;
     RECT  2.16 66.285 170.64 66.555 ;
     RECT  2.16 66.825 170.64 67.095 ;
     RECT  2.16 67.365 170.64 67.635 ;
     RECT  2.16 67.905 170.64 68.175 ;
     RECT  2.16 68.445 170.64 68.715 ;
     RECT  2.16 68.985 170.64 69.255 ;
     RECT  2.16 69.525 170.64 69.795 ;
     RECT  2.16 70.065 170.64 70.335 ;
     RECT  2.16 70.605 170.64 70.875 ;
     RECT  2.16 71.145 170.64 71.415 ;
     RECT  2.16 71.685 170.64 71.955 ;
     RECT  2.16 72.225 170.64 72.495 ;
     RECT  2.16 72.765 170.64 73.035 ;
     RECT  2.16 73.305 170.64 73.575 ;
     RECT  2.16 73.845 170.64 74.115 ;
     RECT  2.16 74.385 170.64 74.655 ;
     RECT  2.16 74.925 170.64 75.195 ;
     RECT  2.16 75.465 170.64 75.735 ;
     RECT  2.16 76.005 170.64 76.275 ;
     RECT  2.16 76.545 170.64 76.815 ;
     RECT  2.16 77.085 170.64 77.355 ;
     RECT  2.16 77.625 170.64 77.895 ;
     RECT  2.16 78.165 170.64 78.435 ;
     RECT  2.16 78.705 170.64 78.975 ;
     RECT  2.16 79.245 170.64 79.515 ;
     RECT  2.16 79.785 170.64 80.055 ;
     RECT  2.16 80.325 170.64 80.595 ;
     RECT  2.16 80.865 170.64 81.135 ;
     RECT  2.16 81.405 170.64 81.675 ;
     RECT  2.16 81.945 170.64 82.215 ;
     RECT  2.16 82.485 170.64 82.755 ;
     RECT  2.16 83.025 170.64 83.295 ;
     RECT  2.16 83.565 170.64 83.835 ;
     RECT  2.16 84.105 170.64 84.375 ;
     RECT  2.16 84.645 170.64 84.915 ;
     RECT  2.16 85.185 170.64 85.455 ;
     RECT  2.16 85.725 170.64 85.995 ;
     RECT  2.16 86.265 170.64 86.535 ;
     RECT  2.16 86.805 170.64 87.075 ;
     RECT  2.16 87.345 170.64 87.615 ;
     RECT  2.16 87.885 170.64 88.155 ;
     RECT  2.16 88.425 170.64 88.695 ;
     RECT  2.16 88.965 170.64 89.235 ;
     RECT  2.16 89.505 170.64 89.775 ;
     RECT  2.16 90.045 170.64 90.315 ;
     RECT  2.16 90.585 170.64 90.855 ;
     RECT  2.16 91.125 170.64 91.395 ;
     RECT  2.16 91.665 170.64 91.935 ;
     RECT  2.16 92.205 170.64 92.475 ;
     RECT  2.16 92.745 170.64 93.015 ;
     RECT  2.16 93.285 170.64 93.555 ;
     RECT  2.16 93.825 170.64 94.095 ;
     RECT  2.16 94.365 170.64 94.635 ;
     RECT  2.16 94.905 170.64 95.175 ;
     RECT  2.16 95.445 170.64 95.715 ;
     RECT  2.16 95.985 170.64 96.255 ;
     RECT  2.16 96.525 170.64 96.795 ;
     RECT  2.16 97.065 170.64 97.335 ;
     RECT  2.16 97.605 170.64 97.875 ;
     RECT  2.16 98.145 170.64 98.415 ;
     RECT  2.16 98.685 170.64 98.955 ;
     RECT  2.16 99.225 170.64 99.495 ;
     RECT  2.16 99.765 170.64 100.035 ;
     RECT  2.16 100.305 170.64 100.575 ;
     RECT  2.16 100.845 170.64 101.115 ;
     RECT  2.16 101.385 170.64 101.655 ;
     RECT  2.16 101.925 170.64 102.195 ;
     RECT  2.16 102.465 170.64 102.735 ;
     RECT  2.16 103.005 170.64 103.275 ;
     RECT  2.16 103.545 170.64 103.815 ;
     RECT  2.16 104.085 170.64 104.355 ;
     RECT  2.16 104.625 170.64 104.895 ;
     RECT  2.16 105.165 170.64 105.435 ;
     RECT  2.16 105.705 170.64 105.975 ;
     RECT  2.16 106.245 170.64 106.515 ;
     RECT  2.16 106.785 170.64 107.055 ;
     RECT  2.16 107.325 170.64 107.595 ;
     RECT  2.16 107.865 170.64 108.135 ;
     RECT  2.16 108.405 170.64 108.675 ;
     RECT  2.16 108.945 170.64 109.215 ;
     RECT  2.16 109.485 170.64 109.755 ;
     RECT  2.16 110.025 170.64 110.295 ;
     RECT  2.16 110.565 170.64 110.835 ;
     RECT  2.16 111.105 170.64 111.375 ;
     RECT  2.16 111.645 170.64 111.915 ;
     RECT  2.16 112.185 170.64 112.455 ;
     RECT  2.16 112.725 170.64 112.995 ;
     RECT  2.16 113.265 170.64 113.535 ;
     RECT  2.16 113.805 170.64 114.075 ;
     RECT  2.16 114.345 170.64 114.615 ;
     RECT  2.16 114.885 170.64 115.155 ;
     RECT  2.16 115.425 170.64 115.695 ;
     RECT  2.16 115.965 170.64 116.235 ;
     RECT  2.16 116.505 170.64 116.775 ;
     RECT  2.16 117.045 170.64 117.315 ;
     RECT  2.16 117.585 170.64 117.855 ;
     RECT  2.16 118.125 170.64 118.395 ;
     RECT  2.16 118.665 170.64 118.935 ;
     RECT  2.16 119.205 170.64 119.475 ;
     RECT  2.16 119.745 170.64 120.015 ;
     RECT  2.16 120.285 170.64 120.555 ;
     RECT  2.16 120.825 170.64 121.095 ;
     RECT  2.16 121.365 170.64 121.635 ;
     RECT  2.16 121.905 170.64 122.175 ;
     RECT  2.16 122.445 170.64 122.715 ;
     RECT  2.16 122.985 170.64 123.255 ;
     RECT  2.16 123.525 170.64 123.795 ;
     RECT  2.16 124.065 170.64 124.335 ;
     RECT  2.16 124.605 170.64 124.875 ;
     RECT  2.16 125.145 170.64 125.415 ;
     RECT  2.16 125.685 170.64 125.955 ;
     RECT  2.16 126.225 170.64 126.495 ;
     RECT  2.16 126.765 170.64 127.035 ;
     RECT  2.16 127.305 170.64 127.44 ;
    LAYER RVTP ;
     RECT  2.16 2.295 170.64 2.565 ;
     RECT  2.16 2.835 170.64 3.105 ;
     RECT  2.16 3.375 170.64 3.645 ;
     RECT  2.16 3.915 170.64 4.185 ;
     RECT  2.16 4.455 170.64 4.725 ;
     RECT  2.16 4.995 170.64 5.265 ;
     RECT  2.16 5.535 170.64 5.805 ;
     RECT  2.16 6.075 170.64 6.345 ;
     RECT  2.16 6.615 170.64 6.885 ;
     RECT  2.16 7.155 170.64 7.425 ;
     RECT  2.16 7.695 170.64 7.965 ;
     RECT  2.16 8.235 170.64 8.505 ;
     RECT  2.16 8.775 170.64 9.045 ;
     RECT  2.16 9.315 170.64 9.585 ;
     RECT  2.16 9.855 170.64 10.125 ;
     RECT  2.16 10.395 170.64 10.665 ;
     RECT  2.16 10.935 170.64 11.205 ;
     RECT  2.16 11.475 170.64 11.745 ;
     RECT  2.16 12.015 170.64 12.285 ;
     RECT  2.16 12.555 170.64 12.825 ;
     RECT  2.16 13.095 170.64 13.365 ;
     RECT  2.16 13.635 170.64 13.905 ;
     RECT  2.16 14.175 170.64 14.445 ;
     RECT  2.16 14.715 170.64 14.985 ;
     RECT  2.16 15.255 170.64 15.525 ;
     RECT  2.16 15.795 170.64 16.065 ;
     RECT  2.16 16.335 170.64 16.605 ;
     RECT  2.16 16.875 170.64 17.145 ;
     RECT  2.16 17.415 170.64 17.685 ;
     RECT  2.16 17.955 170.64 18.225 ;
     RECT  2.16 18.495 170.64 18.765 ;
     RECT  2.16 19.035 170.64 19.305 ;
     RECT  2.16 19.575 170.64 19.845 ;
     RECT  2.16 20.115 170.64 20.385 ;
     RECT  2.16 20.655 170.64 20.925 ;
     RECT  2.16 21.195 170.64 21.465 ;
     RECT  2.16 21.735 170.64 22.005 ;
     RECT  2.16 22.275 170.64 22.545 ;
     RECT  2.16 22.815 170.64 23.085 ;
     RECT  2.16 23.355 170.64 23.625 ;
     RECT  2.16 23.895 170.64 24.165 ;
     RECT  2.16 24.435 170.64 24.705 ;
     RECT  2.16 24.975 170.64 25.245 ;
     RECT  2.16 25.515 170.64 25.785 ;
     RECT  2.16 26.055 170.64 26.325 ;
     RECT  2.16 26.595 170.64 26.865 ;
     RECT  2.16 27.135 170.64 27.405 ;
     RECT  2.16 27.675 170.64 27.945 ;
     RECT  2.16 28.215 170.64 28.485 ;
     RECT  2.16 28.755 170.64 29.025 ;
     RECT  2.16 29.295 170.64 29.565 ;
     RECT  2.16 29.835 170.64 30.105 ;
     RECT  2.16 30.375 170.64 30.645 ;
     RECT  2.16 30.915 170.64 31.185 ;
     RECT  2.16 31.455 170.64 31.725 ;
     RECT  2.16 31.995 170.64 32.265 ;
     RECT  2.16 32.535 170.64 32.805 ;
     RECT  2.16 33.075 170.64 33.345 ;
     RECT  2.16 33.615 170.64 33.885 ;
     RECT  2.16 34.155 170.64 34.425 ;
     RECT  2.16 34.695 170.64 34.965 ;
     RECT  2.16 35.235 170.64 35.505 ;
     RECT  2.16 35.775 170.64 36.045 ;
     RECT  2.16 36.315 170.64 36.585 ;
     RECT  2.16 36.855 170.64 37.125 ;
     RECT  2.16 37.395 170.64 37.665 ;
     RECT  2.16 37.935 170.64 38.205 ;
     RECT  2.16 38.475 170.64 38.745 ;
     RECT  2.16 39.015 170.64 39.285 ;
     RECT  2.16 39.555 170.64 39.825 ;
     RECT  2.16 40.095 170.64 40.365 ;
     RECT  2.16 40.635 170.64 40.905 ;
     RECT  2.16 41.175 170.64 41.445 ;
     RECT  2.16 41.715 170.64 41.985 ;
     RECT  2.16 42.255 170.64 42.525 ;
     RECT  2.16 42.795 170.64 43.065 ;
     RECT  2.16 43.335 170.64 43.605 ;
     RECT  2.16 43.875 170.64 44.145 ;
     RECT  2.16 44.415 170.64 44.685 ;
     RECT  2.16 44.955 170.64 45.225 ;
     RECT  2.16 45.495 170.64 45.765 ;
     RECT  2.16 46.035 170.64 46.305 ;
     RECT  2.16 46.575 170.64 46.845 ;
     RECT  2.16 47.115 170.64 47.385 ;
     RECT  2.16 47.655 170.64 47.925 ;
     RECT  2.16 48.195 170.64 48.465 ;
     RECT  2.16 48.735 170.64 49.005 ;
     RECT  2.16 49.275 170.64 49.545 ;
     RECT  2.16 49.815 170.64 50.085 ;
     RECT  2.16 50.355 170.64 50.625 ;
     RECT  2.16 50.895 170.64 51.165 ;
     RECT  2.16 51.435 170.64 51.705 ;
     RECT  2.16 51.975 170.64 52.245 ;
     RECT  2.16 52.515 170.64 52.785 ;
     RECT  2.16 53.055 170.64 53.325 ;
     RECT  2.16 53.595 170.64 53.865 ;
     RECT  2.16 54.135 170.64 54.405 ;
     RECT  2.16 54.675 170.64 54.945 ;
     RECT  2.16 55.215 170.64 55.485 ;
     RECT  2.16 55.755 170.64 56.025 ;
     RECT  2.16 56.295 170.64 56.565 ;
     RECT  2.16 56.835 170.64 57.105 ;
     RECT  2.16 57.375 170.64 57.645 ;
     RECT  2.16 57.915 170.64 58.185 ;
     RECT  2.16 58.455 170.64 58.725 ;
     RECT  2.16 58.995 170.64 59.265 ;
     RECT  2.16 59.535 170.64 59.805 ;
     RECT  2.16 60.075 170.64 60.345 ;
     RECT  2.16 60.615 170.64 60.885 ;
     RECT  2.16 61.155 170.64 61.425 ;
     RECT  2.16 61.695 170.64 61.965 ;
     RECT  2.16 62.235 170.64 62.505 ;
     RECT  2.16 62.775 170.64 63.045 ;
     RECT  2.16 63.315 170.64 63.585 ;
     RECT  2.16 63.855 170.64 64.125 ;
     RECT  2.16 64.395 170.64 64.665 ;
     RECT  2.16 64.935 170.64 65.205 ;
     RECT  2.16 65.475 170.64 65.745 ;
     RECT  2.16 66.015 170.64 66.285 ;
     RECT  2.16 66.555 170.64 66.825 ;
     RECT  2.16 67.095 170.64 67.365 ;
     RECT  2.16 67.635 170.64 67.905 ;
     RECT  2.16 68.175 170.64 68.445 ;
     RECT  2.16 68.715 170.64 68.985 ;
     RECT  2.16 69.255 170.64 69.525 ;
     RECT  2.16 69.795 170.64 70.065 ;
     RECT  2.16 70.335 170.64 70.605 ;
     RECT  2.16 70.875 170.64 71.145 ;
     RECT  2.16 71.415 170.64 71.685 ;
     RECT  2.16 71.955 170.64 72.225 ;
     RECT  2.16 72.495 170.64 72.765 ;
     RECT  2.16 73.035 170.64 73.305 ;
     RECT  2.16 73.575 170.64 73.845 ;
     RECT  2.16 74.115 170.64 74.385 ;
     RECT  2.16 74.655 170.64 74.925 ;
     RECT  2.16 75.195 170.64 75.465 ;
     RECT  2.16 75.735 170.64 76.005 ;
     RECT  2.16 76.275 170.64 76.545 ;
     RECT  2.16 76.815 170.64 77.085 ;
     RECT  2.16 77.355 170.64 77.625 ;
     RECT  2.16 77.895 170.64 78.165 ;
     RECT  2.16 78.435 170.64 78.705 ;
     RECT  2.16 78.975 170.64 79.245 ;
     RECT  2.16 79.515 170.64 79.785 ;
     RECT  2.16 80.055 170.64 80.325 ;
     RECT  2.16 80.595 170.64 80.865 ;
     RECT  2.16 81.135 170.64 81.405 ;
     RECT  2.16 81.675 170.64 81.945 ;
     RECT  2.16 82.215 170.64 82.485 ;
     RECT  2.16 82.755 170.64 83.025 ;
     RECT  2.16 83.295 170.64 83.565 ;
     RECT  2.16 83.835 170.64 84.105 ;
     RECT  2.16 84.375 170.64 84.645 ;
     RECT  2.16 84.915 170.64 85.185 ;
     RECT  2.16 85.455 170.64 85.725 ;
     RECT  2.16 85.995 170.64 86.265 ;
     RECT  2.16 86.535 170.64 86.805 ;
     RECT  2.16 87.075 170.64 87.345 ;
     RECT  2.16 87.615 170.64 87.885 ;
     RECT  2.16 88.155 170.64 88.425 ;
     RECT  2.16 88.695 170.64 88.965 ;
     RECT  2.16 89.235 170.64 89.505 ;
     RECT  2.16 89.775 170.64 90.045 ;
     RECT  2.16 90.315 170.64 90.585 ;
     RECT  2.16 90.855 170.64 91.125 ;
     RECT  2.16 91.395 170.64 91.665 ;
     RECT  2.16 91.935 170.64 92.205 ;
     RECT  2.16 92.475 170.64 92.745 ;
     RECT  2.16 93.015 170.64 93.285 ;
     RECT  2.16 93.555 170.64 93.825 ;
     RECT  2.16 94.095 170.64 94.365 ;
     RECT  2.16 94.635 170.64 94.905 ;
     RECT  2.16 95.175 170.64 95.445 ;
     RECT  2.16 95.715 170.64 95.985 ;
     RECT  2.16 96.255 170.64 96.525 ;
     RECT  2.16 96.795 170.64 97.065 ;
     RECT  2.16 97.335 170.64 97.605 ;
     RECT  2.16 97.875 170.64 98.145 ;
     RECT  2.16 98.415 170.64 98.685 ;
     RECT  2.16 98.955 170.64 99.225 ;
     RECT  2.16 99.495 170.64 99.765 ;
     RECT  2.16 100.035 170.64 100.305 ;
     RECT  2.16 100.575 170.64 100.845 ;
     RECT  2.16 101.115 170.64 101.385 ;
     RECT  2.16 101.655 170.64 101.925 ;
     RECT  2.16 102.195 170.64 102.465 ;
     RECT  2.16 102.735 170.64 103.005 ;
     RECT  2.16 103.275 170.64 103.545 ;
     RECT  2.16 103.815 170.64 104.085 ;
     RECT  2.16 104.355 170.64 104.625 ;
     RECT  2.16 104.895 170.64 105.165 ;
     RECT  2.16 105.435 170.64 105.705 ;
     RECT  2.16 105.975 170.64 106.245 ;
     RECT  2.16 106.515 170.64 106.785 ;
     RECT  2.16 107.055 170.64 107.325 ;
     RECT  2.16 107.595 170.64 107.865 ;
     RECT  2.16 108.135 170.64 108.405 ;
     RECT  2.16 108.675 170.64 108.945 ;
     RECT  2.16 109.215 170.64 109.485 ;
     RECT  2.16 109.755 170.64 110.025 ;
     RECT  2.16 110.295 170.64 110.565 ;
     RECT  2.16 110.835 170.64 111.105 ;
     RECT  2.16 111.375 170.64 111.645 ;
     RECT  2.16 111.915 170.64 112.185 ;
     RECT  2.16 112.455 170.64 112.725 ;
     RECT  2.16 112.995 170.64 113.265 ;
     RECT  2.16 113.535 170.64 113.805 ;
     RECT  2.16 114.075 170.64 114.345 ;
     RECT  2.16 114.615 170.64 114.885 ;
     RECT  2.16 115.155 170.64 115.425 ;
     RECT  2.16 115.695 170.64 115.965 ;
     RECT  2.16 116.235 170.64 116.505 ;
     RECT  2.16 116.775 170.64 117.045 ;
     RECT  2.16 117.315 170.64 117.585 ;
     RECT  2.16 117.855 170.64 118.125 ;
     RECT  2.16 118.395 170.64 118.665 ;
     RECT  2.16 118.935 170.64 119.205 ;
     RECT  2.16 119.475 170.64 119.745 ;
     RECT  2.16 120.015 170.64 120.285 ;
     RECT  2.16 120.555 170.64 120.825 ;
     RECT  2.16 121.095 170.64 121.365 ;
     RECT  2.16 121.635 170.64 121.905 ;
     RECT  2.16 122.175 170.64 122.445 ;
     RECT  2.16 122.715 170.64 122.985 ;
     RECT  2.16 123.255 170.64 123.525 ;
     RECT  2.16 123.795 170.64 124.065 ;
     RECT  2.16 124.335 170.64 124.605 ;
     RECT  2.16 124.875 170.64 125.145 ;
     RECT  2.16 125.415 170.64 125.685 ;
     RECT  2.16 125.955 170.64 126.225 ;
     RECT  2.16 126.495 170.64 126.765 ;
     RECT  2.16 127.035 170.64 127.305 ;
    LAYER M1 ;
     RECT  2.16 2.151 170.64 127.449 ;
    LAYER M2 ;
     RECT  0.103 59.436 2.16 59.454 ;
     RECT  0.103 64.71 2.16 64.728 ;
     RECT  2.16 2.151 56.407 127.449 ;
     RECT  56.407 2.151 56.651 127.53 ;
     RECT  56.651 2.151 71.239 127.449 ;
     RECT  71.239 2.151 74.543 127.494 ;
     RECT  74.543 2.151 88.627 127.449 ;
     RECT  88.627 2.151 89.951 127.494 ;
     RECT  89.951 2.151 104.323 127.449 ;
     RECT  104.323 2.151 111.047 127.494 ;
     RECT  111.047 2.151 111.991 127.449 ;
     RECT  111.991 2.151 114.539 127.566 ;
     RECT  114.539 2.151 116.267 127.494 ;
     RECT  116.267 2.151 170.64 127.449 ;
     RECT  170.64 87.426 170.843 88.344 ;
     RECT  170.843 87.516 171.275 88.344 ;
     RECT  170.64 50.058 171.491 86.562 ;
     RECT  171.275 87.516 171.527 87.534 ;
     RECT  171.491 50.058 171.563 86.454 ;
     RECT  171.563 50.058 171.599 77.184 ;
     RECT  171.599 50.058 171.635 57.474 ;
     RECT  171.635 51.246 171.671 53.424 ;
     RECT  171.671 51.336 171.707 53.424 ;
     RECT  171.635 54.306 172.103 57.474 ;
     RECT  171.599 58.428 172.103 74.574 ;
     RECT  171.563 77.976 172.103 86.184 ;
     RECT  171.707 51.606 172.139 53.424 ;
     RECT  172.103 54.306 172.139 57.294 ;
     RECT  172.103 58.428 172.139 58.644 ;
     RECT  172.103 59.508 172.139 65.394 ;
     RECT  172.103 66.456 172.139 74.574 ;
     RECT  172.103 77.976 172.139 80.514 ;
     RECT  172.103 81.486 172.139 82.314 ;
     RECT  172.103 83.196 172.139 85.68 ;
     RECT  171.635 50.058 172.175 50.076 ;
     RECT  172.139 52.218 172.175 52.236 ;
     RECT  172.139 52.992 172.175 53.424 ;
     RECT  172.139 58.428 172.175 58.446 ;
     RECT  172.139 59.508 172.175 60.138 ;
     RECT  172.139 61.596 172.175 62.064 ;
     RECT  172.139 63.936 172.175 65.124 ;
     RECT  172.139 68.49 172.175 71.604 ;
     RECT  172.139 72.468 172.175 74.574 ;
     RECT  172.139 79.056 172.175 80.118 ;
     RECT  172.139 54.486 172.211 54.63 ;
     RECT  172.139 83.376 172.211 84.564 ;
     RECT  172.211 54.486 172.247 54.504 ;
     RECT  172.175 79.29 172.247 80.118 ;
     RECT  172.139 66.906 172.679 67.464 ;
     RECT  172.175 68.652 172.679 71.604 ;
     RECT  172.175 73.746 172.679 74.214 ;
     RECT  171.599 75.438 172.679 77.184 ;
     RECT  172.139 78.066 172.679 78.264 ;
     RECT  172.247 79.866 172.679 80.118 ;
     RECT  172.211 84.546 172.679 84.564 ;
     RECT  172.175 52.992 172.715 53.01 ;
     RECT  172.139 56.646 172.715 57.168 ;
     RECT  172.175 61.596 172.715 61.614 ;
     RECT  172.139 62.82 172.715 62.838 ;
     RECT  172.175 64.404 172.715 64.962 ;
     RECT  172.679 66.906 172.715 67.284 ;
     RECT  172.679 68.652 172.715 69.282 ;
     RECT  172.679 70.038 172.715 71.604 ;
     RECT  172.175 72.468 172.715 72.639 ;
     RECT  172.679 74.196 172.715 74.214 ;
     RECT  172.679 75.438 172.715 75.456 ;
     RECT  172.679 76.626 172.715 76.644 ;
     RECT  172.679 78.246 172.715 78.264 ;
     RECT  172.679 79.866 172.715 80.046 ;
     RECT  172.139 81.486 172.715 81.504 ;
     RECT  172.139 82.296 172.715 82.314 ;
     RECT  172.211 83.376 172.715 83.394 ;
     RECT  172.139 85.662 172.715 85.68 ;
     RECT  172.715 70.344 172.787 70.362 ;
     RECT  172.715 72.621 172.787 72.639 ;
     RECT  171.275 88.326 172.787 88.344 ;
    LAYER M3 ;
     RECT  80.568 1.723 80.586 2.191 ;
     RECT  80.424 2.191 80.586 2.219 ;
     RECT  79.632 0.091 79.65 2.227 ;
     RECT  2.415 2.143 2.505 2.413 ;
     RECT  7.815 2.143 7.905 2.413 ;
     RECT  13.215 2.143 13.305 2.413 ;
     RECT  18.615 2.143 18.705 2.413 ;
     RECT  24.015 2.143 24.105 2.413 ;
     RECT  29.415 2.143 29.505 2.413 ;
     RECT  34.815 2.143 34.905 2.413 ;
     RECT  40.215 2.143 40.305 2.413 ;
     RECT  45.615 2.143 45.705 2.413 ;
     RECT  51.015 2.143 51.105 2.413 ;
     RECT  56.415 2.143 56.505 2.413 ;
     RECT  61.815 2.143 61.905 2.413 ;
     RECT  67.215 2.143 67.305 2.413 ;
     RECT  72.615 2.143 72.705 2.413 ;
     RECT  78.015 2.143 78.105 2.413 ;
     RECT  83.415 2.143 83.505 2.413 ;
     RECT  88.815 2.143 88.905 2.413 ;
     RECT  94.215 2.143 94.305 2.413 ;
     RECT  99.615 2.143 99.705 2.413 ;
     RECT  105.015 2.143 105.105 2.413 ;
     RECT  110.415 2.143 110.505 2.413 ;
     RECT  115.815 2.143 115.905 2.413 ;
     RECT  121.215 2.143 121.305 2.413 ;
     RECT  126.615 2.143 126.705 2.413 ;
     RECT  132.015 2.143 132.105 2.413 ;
     RECT  137.415 2.143 137.505 2.413 ;
     RECT  142.815 2.143 142.905 2.413 ;
     RECT  148.215 2.143 148.305 2.413 ;
     RECT  153.615 2.143 153.705 2.413 ;
     RECT  159.015 2.143 159.105 2.413 ;
     RECT  164.415 2.143 164.505 2.413 ;
     RECT  169.815 2.143 169.905 2.413 ;
     RECT  79.632 2.227 79.686 2.461 ;
     RECT  80.424 2.219 80.55 2.461 ;
     RECT  79.632 2.461 80.55 2.605 ;
     RECT  79.524 2.605 80.55 3.109 ;
     RECT  79.128 3.109 80.55 3.437 ;
     RECT  79.236 3.437 80.55 3.569 ;
     RECT  78.015 2.413 78.297 3.811 ;
     RECT  80.208 3.569 80.55 3.847 ;
     RECT  79.236 3.569 79.326 3.965 ;
     RECT  80.208 3.847 80.658 3.983 ;
     RECT  77.472 3.811 78.297 23.791 ;
     RECT  77.472 23.791 78.39 24.232 ;
     RECT  79.308 3.965 79.326 24.232 ;
     RECT  77.472 24.232 79.326 24.269 ;
     RECT  169.02 47.659 169.038 47.731 ;
     RECT  169.815 2.413 170.097 47.731 ;
     RECT  169.02 47.731 170.298 48.271 ;
     RECT  168.48 48.271 170.298 48.541 ;
     RECT  97.956 48.127 97.974 48.703 ;
     RECT  88.815 2.413 89.097 48.739 ;
     RECT  166.464 48.667 166.482 48.803 ;
     RECT  99.615 2.413 99.897 48.901 ;
     RECT  166.5 49.207 166.518 49.307 ;
     RECT  168.48 48.541 170.334 49.351 ;
     RECT  167.94 49.351 170.478 49.505 ;
     RECT  91.26 48.667 91.278 49.513 ;
     RECT  96.084 49.747 96.102 49.783 ;
     RECT  168.444 49.505 170.478 49.891 ;
     RECT  91.26 49.513 91.458 50.053 ;
     RECT  92.628 48.163 92.646 50.053 ;
     RECT  168.444 49.891 170.514 50.395 ;
     RECT  166.464 49.783 166.482 50.459 ;
     RECT  172.152 50.053 172.17 50.791 ;
     RECT  171.612 50.791 172.17 50.863 ;
     RECT  168.192 50.395 170.514 51.205 ;
     RECT  95.472 49.783 96.102 51.331 ;
     RECT  97.38 48.703 97.974 51.331 ;
     RECT  168.12 51.205 170.514 51.367 ;
     RECT  168.084 51.367 170.514 51.439 ;
     RECT  171.576 50.863 172.17 51.439 ;
     RECT  166.464 51.331 166.482 51.467 ;
     RECT  168.084 51.439 172.17 51.475 ;
     RECT  100.8 50.017 100.818 51.637 ;
     RECT  167.94 51.475 172.17 52.015 ;
     RECT  99.576 48.901 99.897 52.141 ;
     RECT  100.62 51.637 100.818 52.141 ;
     RECT  166.5 52.717 166.518 52.889 ;
     RECT  99.576 52.141 100.818 52.987 ;
     RECT  167.688 52.015 172.17 52.987 ;
     RECT  167.688 52.987 172.71 53.069 ;
     RECT  167.688 53.069 172.17 53.249 ;
     RECT  162.504 53.257 162.522 53.357 ;
     RECT  102.384 50.359 102.402 53.527 ;
     RECT  83.415 2.413 83.697 53.761 ;
     RECT  167.796 53.249 172.17 54.301 ;
     RECT  101.88 53.527 102.402 54.337 ;
     RECT  162.468 54.211 162.486 54.337 ;
     RECT  162.468 54.337 162.522 54.338 ;
     RECT  103.752 53.257 103.77 54.409 ;
     RECT  105.015 2.413 105.297 54.409 ;
     RECT  167.724 54.301 172.17 54.445 ;
     RECT  167.58 54.445 172.17 54.481 ;
     RECT  162.504 54.338 162.522 54.509 ;
     RECT  83.415 53.761 84.33 54.643 ;
     RECT  167.58 54.481 172.242 54.679 ;
     RECT  86.004 54.301 86.022 54.841 ;
     RECT  87.228 47.551 87.246 54.841 ;
     RECT  167.472 54.679 172.242 54.893 ;
     RECT  167.472 54.893 172.17 55.139 ;
     RECT  86.004 54.841 87.246 55.147 ;
     RECT  167.652 55.139 172.17 55.181 ;
     RECT  88.236 48.739 89.097 55.183 ;
     RECT  86.004 55.147 87.462 55.219 ;
     RECT  166.5 55.255 166.518 55.453 ;
     RECT  166.464 55.453 166.518 55.553 ;
     RECT  83.415 54.643 84.474 55.561 ;
     RECT  167.652 55.181 172.134 55.589 ;
     RECT  166.5 55.553 166.518 55.679 ;
     RECT  83.415 55.561 85.122 55.723 ;
     RECT  85.86 55.219 87.462 55.723 ;
     RECT  83.415 55.723 87.462 55.921 ;
     RECT  167.652 55.589 170.19 55.921 ;
     RECT  167.292 55.921 170.19 56.057 ;
     RECT  162.504 55.687 162.522 56.101 ;
     RECT  83.34 55.921 87.462 56.227 ;
     RECT  88.236 55.183 89.55 56.227 ;
     RECT  162.468 56.101 162.522 56.227 ;
     RECT  91.26 50.053 92.646 56.263 ;
     RECT  167.364 56.057 170.19 56.335 ;
     RECT  171 55.589 172.134 56.395 ;
     RECT  167.364 56.335 170.262 56.461 ;
     RECT  171 56.395 172.71 56.461 ;
     RECT  167.364 56.461 172.71 56.621 ;
     RECT  167.364 56.621 170.406 57.001 ;
     RECT  162.468 56.227 162.558 57.037 ;
     RECT  90.288 49.243 90.306 57.073 ;
     RECT  91.26 56.263 93.078 57.073 ;
     RECT  162.468 57.037 162.594 57.173 ;
     RECT  171.576 56.621 172.71 57.173 ;
     RECT  171.576 57.173 172.134 57.299 ;
     RECT  171.576 57.299 172.098 57.355 ;
     RECT  166.752 57.001 170.406 57.415 ;
     RECT  171.54 57.355 172.098 57.479 ;
     RECT  166.284 57.415 170.406 57.541 ;
     RECT  162.468 57.173 162.486 57.569 ;
     RECT  166.284 57.541 170.478 57.569 ;
     RECT  101.88 54.337 102.906 57.919 ;
     RECT  103.752 54.409 105.297 57.919 ;
     RECT  166.464 57.569 170.478 58.225 ;
     RECT  171.54 57.479 172.062 58.225 ;
     RECT  99.504 52.987 100.818 58.351 ;
     RECT  101.88 57.919 105.297 58.351 ;
     RECT  166.464 58.225 172.062 58.423 ;
     RECT  166.464 58.423 172.17 58.445 ;
     RECT  171.54 58.445 172.17 58.559 ;
     RECT  99.504 58.351 105.297 58.657 ;
     RECT  166.464 58.445 170.514 58.657 ;
     RECT  99.504 58.657 105.714 58.693 ;
     RECT  162.54 58.729 162.558 58.765 ;
     RECT  166.176 58.657 170.514 58.765 ;
     RECT  165.888 58.765 170.514 58.801 ;
     RECT  165.636 58.801 170.514 58.919 ;
     RECT  165.816 58.919 170.514 58.928 ;
     RECT  162.468 58.765 162.558 58.963 ;
     RECT  162.468 58.963 162.63 58.991 ;
     RECT  110.415 2.413 110.697 59.071 ;
     RECT  162.612 58.991 162.63 59.189 ;
     RECT  166.104 58.928 170.514 59.371 ;
     RECT  171.576 58.559 172.17 59.371 ;
     RECT  0.108 59.083 0.126 59.459 ;
     RECT  166.104 59.371 172.17 59.603 ;
     RECT  80.208 3.983 80.226 59.729 ;
     RECT  74.808 59.611 74.826 59.809 ;
     RECT  74.808 59.809 75.546 59.837 ;
     RECT  166.212 59.603 172.17 60.269 ;
     RECT  107.316 58.999 107.334 60.277 ;
     RECT  162.468 60.151 162.486 60.277 ;
     RECT  162.468 60.277 162.558 60.377 ;
     RECT  166.464 60.269 172.17 60.461 ;
     RECT  109.26 59.035 109.278 60.583 ;
     RECT  162.468 60.377 162.486 60.719 ;
     RECT  109.26 60.583 109.314 60.817 ;
     RECT  110.376 59.071 110.697 60.817 ;
     RECT  106.488 60.313 106.506 61.087 ;
     RECT  107.316 60.277 107.442 61.087 ;
     RECT  108.216 59.971 108.234 61.159 ;
     RECT  72.615 2.413 72.897 61.429 ;
     RECT  165.672 61.321 165.69 61.493 ;
     RECT  166.464 60.461 172.134 61.529 ;
     RECT  167.256 61.529 172.134 61.579 ;
     RECT  167.256 61.579 172.71 61.619 ;
     RECT  167.256 61.619 172.638 61.661 ;
     RECT  106.488 61.087 107.442 61.699 ;
     RECT  108.216 61.159 108.522 61.699 ;
     RECT  77.472 24.269 78.297 61.897 ;
     RECT  79.308 24.269 79.326 61.897 ;
     RECT  74.268 60.853 74.286 62.131 ;
     RECT  75.528 59.837 75.546 62.203 ;
     RECT  76.428 59.701 76.446 62.203 ;
     RECT  75.528 62.203 76.446 62.267 ;
     RECT  167.256 61.661 172.17 62.275 ;
     RECT  75.528 62.267 75.762 62.303 ;
     RECT  99.504 58.693 105.75 62.311 ;
     RECT  106.488 61.699 108.522 62.311 ;
     RECT  166.212 61.591 166.23 62.311 ;
     RECT  167.184 62.275 172.17 62.311 ;
     RECT  166.212 62.311 172.17 62.401 ;
     RECT  166.032 62.401 172.17 62.539 ;
     RECT  83.34 56.227 89.55 62.545 ;
     RECT  162.468 61.861 162.486 62.581 ;
     RECT  82.152 62.581 82.17 62.671 ;
     RECT  99.504 62.311 108.522 62.699 ;
     RECT  166.032 62.539 172.71 62.843 ;
     RECT  77.472 61.897 79.326 62.941 ;
     RECT  77.256 62.941 79.326 62.977 ;
     RECT  80.136 62.509 80.154 62.977 ;
     RECT  81.756 62.671 82.17 63.013 ;
     RECT  162.468 62.581 162.558 63.113 ;
     RECT  2.415 2.413 2.697 63.403 ;
     RECT  77.256 62.977 80.154 63.481 ;
     RECT  81.504 63.013 82.17 63.553 ;
     RECT  83.196 62.545 89.55 63.553 ;
     RECT  77.256 63.481 80.658 63.625 ;
     RECT  81.504 63.553 89.55 63.625 ;
     RECT  164.415 2.413 164.697 63.625 ;
     RECT  166.032 62.843 172.134 63.625 ;
     RECT  164.415 63.625 172.134 63.629 ;
     RECT  164.415 63.629 170.514 63.779 ;
     RECT  171.504 63.629 172.134 63.787 ;
     RECT  2.34 63.403 2.697 63.815 ;
     RECT  166.032 63.779 170.514 64.049 ;
     RECT  77.256 63.625 89.55 64.093 ;
     RECT  162.504 63.113 162.522 64.129 ;
     RECT  74.268 62.131 74.79 64.165 ;
     RECT  75.528 62.303 75.546 64.165 ;
     RECT  162.504 64.129 162.558 64.193 ;
     RECT  98.712 63.121 98.73 64.201 ;
     RECT  99.504 62.699 105.714 64.201 ;
     RECT  2.376 63.815 2.697 64.319 ;
     RECT  162.54 64.193 162.558 64.319 ;
     RECT  106.488 62.699 108.522 64.363 ;
     RECT  109.26 60.817 110.697 64.363 ;
     RECT  166.464 64.049 170.514 64.391 ;
     RECT  74.268 64.165 75.546 64.435 ;
     RECT  74.232 64.435 75.546 64.463 ;
     RECT  74.232 64.463 74.682 64.493 ;
     RECT  77.22 64.093 89.55 64.589 ;
     RECT  166.5 64.391 170.514 64.589 ;
     RECT  74.268 64.493 74.682 64.637 ;
     RECT  166.536 64.589 170.514 64.741 ;
     RECT  171.504 63.787 172.71 64.741 ;
     RECT  106.488 64.363 110.697 64.867 ;
     RECT  166.536 64.741 172.71 64.967 ;
     RECT  0.108 64.705 0.126 65.069 ;
     RECT  95.472 51.331 97.974 65.281 ;
     RECT  98.712 64.201 105.714 65.281 ;
     RECT  121.215 2.413 121.497 65.371 ;
     RECT  132.015 2.413 132.297 65.371 ;
     RECT  142.815 2.413 143.097 65.371 ;
     RECT  153.615 2.413 153.897 65.371 ;
     RECT  164.415 63.779 164.697 65.371 ;
     RECT  121.104 65.371 121.497 65.408 ;
     RECT  131.904 65.371 132.297 65.408 ;
     RECT  142.704 65.371 143.097 65.408 ;
     RECT  153.504 65.371 153.897 65.408 ;
     RECT  164.304 65.371 164.697 65.408 ;
     RECT  166.536 64.967 172.17 65.443 ;
     RECT  106.452 64.867 110.697 65.749 ;
     RECT  166.428 65.443 172.17 66.181 ;
     RECT  162.468 65.137 162.486 66.217 ;
     RECT  166.392 66.181 172.17 66.283 ;
     RECT  166.392 66.283 172.71 66.451 ;
     RECT  112.104 66.451 112.122 66.487 ;
     RECT  166.14 66.451 172.71 66.551 ;
     RECT  162.468 66.217 162.522 66.623 ;
     RECT  106.452 65.749 111.222 66.721 ;
     RECT  112.104 66.487 112.23 66.721 ;
     RECT  166.14 66.551 170.406 66.901 ;
     RECT  106.452 66.721 112.23 67.027 ;
     RECT  113.616 66.523 113.634 67.063 ;
     RECT  114.66 66.793 114.678 67.063 ;
     RECT  113.616 67.063 114.678 67.099 ;
     RECT  165.996 66.901 170.406 67.289 ;
     RECT  171.504 66.551 172.71 67.397 ;
     RECT  162.504 66.623 162.522 67.567 ;
     RECT  162.504 67.567 162.63 67.639 ;
     RECT  166.284 67.289 170.406 67.639 ;
     RECT  125.496 67.567 125.514 67.711 ;
     RECT  162.468 67.639 162.63 67.739 ;
     RECT  171.576 67.397 172.71 67.757 ;
     RECT  125.424 67.711 125.514 67.801 ;
     RECT  162.468 67.739 162.558 67.829 ;
     RECT  115.815 2.413 116.097 68.071 ;
     RECT  166.284 67.639 170.442 68.251 ;
     RECT  166.284 68.251 171.018 68.611 ;
     RECT  166.176 68.611 171.018 68.711 ;
     RECT  166.284 68.711 171.018 69.067 ;
     RECT  171.828 67.757 172.71 69.067 ;
     RECT  166.284 69.067 172.71 69.215 ;
     RECT  121.215 65.408 121.497 69.421 ;
     RECT  166.32 69.215 172.71 69.629 ;
     RECT  166.32 69.629 171.018 69.677 ;
     RECT  69.84 61.861 69.858 69.691 ;
     RECT  166.32 69.677 170.982 69.719 ;
     RECT  71.136 59.503 71.154 69.727 ;
     RECT  162.468 69.691 162.486 69.727 ;
     RECT  162.468 69.727 162.522 69.899 ;
     RECT  172.116 69.629 172.71 69.989 ;
     RECT  67.215 2.413 67.497 70.231 ;
     RECT  172.152 69.989 172.71 70.339 ;
     RECT  75.42 64.463 75.546 70.501 ;
     RECT  166.896 69.719 170.982 70.609 ;
     RECT  162.504 69.899 162.522 70.637 ;
     RECT  69.516 69.691 69.858 70.771 ;
     RECT  69.3 70.771 69.858 71.041 ;
     RECT  70.812 69.727 71.154 71.083 ;
     RECT  72.252 61.429 72.897 71.083 ;
     RECT  74.268 64.637 74.286 71.131 ;
     RECT  172.152 70.339 172.782 71.176 ;
     RECT  166.896 70.609 171.018 71.563 ;
     RECT  172.116 71.176 172.782 71.563 ;
     RECT  70.812 71.083 72.897 71.617 ;
     RECT  70.812 71.617 73.35 71.789 ;
     RECT  166.896 71.563 172.782 72.644 ;
     RECT  166.896 72.644 172.71 72.653 ;
     RECT  166.896 72.653 172.17 72.769 ;
     RECT  166.428 72.769 172.17 72.959 ;
     RECT  166.5 72.959 172.17 73.387 ;
     RECT  119.628 68.611 119.646 73.741 ;
     RECT  166.5 73.387 172.674 73.771 ;
     RECT  118.764 72.931 118.782 73.777 ;
     RECT  119.628 73.741 119.898 73.777 ;
     RECT  118.764 73.777 119.898 74.011 ;
     RECT  162.468 73.741 162.486 74.011 ;
     RECT  121.215 69.421 121.806 74.047 ;
     RECT  166.5 73.771 172.71 74.309 ;
     RECT  162.468 74.011 162.522 74.317 ;
     RECT  118.44 74.011 119.898 74.353 ;
     RECT  121.14 74.047 121.806 74.389 ;
     RECT  120.816 74.389 121.806 74.425 ;
     RECT  83.196 64.589 89.55 74.461 ;
     RECT  90.288 57.073 93.078 74.461 ;
     RECT  162.468 74.317 162.558 74.489 ;
     RECT  162.468 74.489 162.486 74.651 ;
     RECT  83.196 74.461 93.078 74.669 ;
     RECT  120.816 74.425 121.95 75.091 ;
     RECT  118.44 74.353 120.006 75.127 ;
     RECT  171 74.309 172.71 75.191 ;
     RECT  166.5 74.309 170.226 75.199 ;
     RECT  165.996 75.199 170.226 75.227 ;
     RECT  124.884 67.801 125.514 75.271 ;
     RECT  165.996 75.227 166.014 75.389 ;
     RECT  117.18 67.603 117.198 75.397 ;
     RECT  118.44 75.127 120.078 75.397 ;
     RECT  166.896 75.227 170.226 75.433 ;
     RECT  120.816 75.091 121.986 75.469 ;
     RECT  165.708 75.397 165.726 75.497 ;
     RECT  166.896 75.433 170.442 75.569 ;
     RECT  115.452 68.071 116.097 75.631 ;
     RECT  117.18 75.397 120.078 75.631 ;
     RECT  162.504 75.667 162.522 75.767 ;
     RECT  115.452 75.631 120.078 75.937 ;
     RECT  120.816 75.469 122.022 75.937 ;
     RECT  171.576 75.191 172.71 75.979 ;
     RECT  171.54 75.979 172.71 76.171 ;
     RECT  166.896 75.569 170.406 76.477 ;
     RECT  171.504 76.171 172.71 76.477 ;
     RECT  106.452 67.027 112.302 76.549 ;
     RECT  113.184 67.099 114.678 76.549 ;
     RECT  166.896 76.477 172.71 76.549 ;
     RECT  166.464 76.549 172.71 76.649 ;
     RECT  162.468 77.053 162.486 77.521 ;
     RECT  162.468 77.521 162.558 77.557 ;
     RECT  162.468 77.557 162.63 77.593 ;
     RECT  106.452 76.549 114.678 77.665 ;
     RECT  115.452 75.937 122.022 77.665 ;
     RECT  162.468 77.593 162.702 77.693 ;
     RECT  162.468 77.693 162.63 77.729 ;
     RECT  166.464 76.649 172.674 77.899 ;
     RECT  132.015 65.408 132.297 78.232 ;
     RECT  142.815 65.408 143.097 78.232 ;
     RECT  153.615 65.408 153.897 78.232 ;
     RECT  166.464 77.899 172.71 78.241 ;
     RECT  130.536 78.169 130.554 78.269 ;
     RECT  138.528 78.169 138.546 78.269 ;
     RECT  150.48 78.169 150.498 78.269 ;
     RECT  162.468 77.729 162.522 78.269 ;
     RECT  166.104 78.241 172.71 78.269 ;
     RECT  166.104 78.269 172.134 78.359 ;
     RECT  131.904 78.232 132.297 78.368 ;
     RECT  142.704 78.232 143.097 78.368 ;
     RECT  153.504 78.232 153.897 78.368 ;
     RECT  162.468 78.269 162.486 78.461 ;
     RECT  166.572 78.359 172.134 78.539 ;
     RECT  171.504 78.539 172.134 79.051 ;
     RECT  166.572 78.539 170.442 79.285 ;
     RECT  171.504 79.051 172.17 79.285 ;
     RECT  166.5 79.285 170.442 79.321 ;
     RECT  166.464 79.321 170.442 79.519 ;
     RECT  171.504 79.285 172.242 79.547 ;
     RECT  162.468 79.591 162.486 79.681 ;
     RECT  165.996 79.519 170.442 79.709 ;
     RECT  83.196 74.669 89.55 79.717 ;
     RECT  90.288 74.669 93.078 79.717 ;
     RECT  171.54 79.547 172.242 79.723 ;
     RECT  162.468 79.681 162.558 79.781 ;
     RECT  166.5 79.709 170.442 80.321 ;
     RECT  171.54 79.723 172.71 80.429 ;
     RECT  171.54 80.429 172.134 80.519 ;
     RECT  166.896 80.321 170.442 80.683 ;
     RECT  171.54 80.519 172.098 80.683 ;
     RECT  83.196 79.717 93.078 80.761 ;
     RECT  94.215 2.413 94.497 80.761 ;
     RECT  166.896 80.683 172.098 81.104 ;
     RECT  83.196 80.761 94.497 81.139 ;
     RECT  95.472 65.281 105.714 81.139 ;
     RECT  162.504 81.301 162.522 81.401 ;
     RECT  166.896 81.104 171.666 81.841 ;
     RECT  172.692 81.481 172.71 81.841 ;
     RECT  166.896 81.841 172.71 82.319 ;
     RECT  75.42 70.501 75.798 82.687 ;
     RECT  166.896 82.319 172.134 82.687 ;
     RECT  77.22 64.589 82.278 82.957 ;
     RECT  162.468 82.921 162.486 82.957 ;
     RECT  162.468 82.957 162.558 83.057 ;
     RECT  166.464 82.687 172.134 83.083 ;
     RECT  75.168 82.687 75.798 83.101 ;
     RECT  76.752 82.957 82.278 83.101 ;
     RECT  166.464 83.083 172.71 83.399 ;
     RECT  63.144 82.831 63.162 83.461 ;
     RECT  64.044 83.065 64.062 83.461 ;
     RECT  166.464 83.399 172.674 83.597 ;
     RECT  166.896 83.597 172.674 85.099 ;
     RECT  67.215 70.231 68.022 85.117 ;
     RECT  63.144 83.461 64.062 85.189 ;
     RECT  65.304 84.001 65.322 85.189 ;
     RECT  166.896 85.099 172.71 85.261 ;
     RECT  166.464 85.261 172.71 85.451 ;
     RECT  166.896 85.451 172.71 85.483 ;
     RECT  66.6 85.117 68.022 85.891 ;
     RECT  166.896 85.483 172.782 86.189 ;
     RECT  166.896 86.189 171.558 86.459 ;
     RECT  166.896 86.459 171.522 86.729 ;
     RECT  166.896 86.729 167.706 87.079 ;
     RECT  166.464 87.079 167.706 87.179 ;
     RECT  63.144 85.189 65.322 87.313 ;
     RECT  66.24 85.891 68.022 87.313 ;
     RECT  168.804 86.729 171.522 87.449 ;
     RECT  171.252 87.449 171.522 87.539 ;
     RECT  63.144 87.313 68.022 87.781 ;
     RECT  171.252 87.539 171.27 87.845 ;
     RECT  168.804 87.449 170.19 88.321 ;
     RECT  168.804 88.321 170.298 88.349 ;
     RECT  172.764 86.189 172.782 88.349 ;
     RECT  168.84 88.349 170.298 88.421 ;
     RECT  169.02 88.421 170.097 88.619 ;
     RECT  169.02 88.619 169.038 88.799 ;
     RECT  75.168 83.101 82.278 92.371 ;
     RECT  75.168 92.371 82.35 92.395 ;
     RECT  83.196 81.139 105.714 92.395 ;
     RECT  75.168 92.395 105.714 92.669 ;
     RECT  68.868 71.041 69.858 92.911 ;
     RECT  70.812 71.789 73.314 92.911 ;
     RECT  166.896 87.179 167.706 93.929 ;
     RECT  124.38 75.271 125.514 94.019 ;
     RECT  167.148 93.929 167.706 94.289 ;
     RECT  124.488 94.019 125.514 104.549 ;
     RECT  125.424 104.549 125.514 106.169 ;
     RECT  106.452 77.665 122.022 106.177 ;
     RECT  106.452 106.177 122.634 106.277 ;
     RECT  125.424 106.169 125.442 106.709 ;
     RECT  167.148 94.289 167.274 106.979 ;
     RECT  167.256 106.979 167.274 108.059 ;
     RECT  83.196 92.669 105.714 108.445 ;
     RECT  106.452 106.277 122.022 108.445 ;
     RECT  75.168 92.669 82.278 108.715 ;
     RECT  83.196 108.445 122.022 108.715 ;
     RECT  75.168 108.715 122.022 108.869 ;
     RECT  75.168 108.869 82.278 109.687 ;
     RECT  83.016 108.869 122.022 109.687 ;
     RECT  75.168 109.687 122.022 110.219 ;
     RECT  74.268 71.131 74.358 110.911 ;
     RECT  75.168 110.219 76.05 110.911 ;
     RECT  77.148 110.219 122.022 112.379 ;
     RECT  124.488 104.549 124.506 112.379 ;
     RECT  77.148 112.379 112.194 112.927 ;
     RECT  74.268 110.911 76.05 113.341 ;
     RECT  76.932 112.927 112.194 113.341 ;
     RECT  68.868 92.911 73.314 113.611 ;
     RECT  74.268 113.341 112.194 113.611 ;
     RECT  68.868 113.611 112.194 114.079 ;
     RECT  112.968 112.379 122.022 114.079 ;
     RECT  127.62 74.893 127.638 114.269 ;
     RECT  68.868 114.079 122.022 114.539 ;
     RECT  63.144 87.781 68.058 114.611 ;
     RECT  68.868 114.539 90.81 114.809 ;
     RECT  68.868 114.809 85.086 115.123 ;
     RECT  91.908 114.539 122.022 115.465 ;
     RECT  64.044 114.611 68.058 115.501 ;
     RECT  68.796 115.123 85.086 115.501 ;
     RECT  64.044 115.501 85.086 115.627 ;
     RECT  85.86 114.809 90.81 115.627 ;
     RECT  61.815 2.413 62.097 116.041 ;
     RECT  63.144 114.611 63.306 116.041 ;
     RECT  64.044 115.627 90.81 116.041 ;
     RECT  91.728 115.465 122.022 116.041 ;
     RECT  61.815 116.041 63.306 116.239 ;
     RECT  64.044 116.041 122.022 116.239 ;
     RECT  61.815 116.239 122.022 116.285 ;
     RECT  61.815 116.285 91.062 116.509 ;
     RECT  91.836 116.285 122.022 116.609 ;
     RECT  61.236 116.509 91.062 117.121 ;
     RECT  61.236 117.121 91.242 117.391 ;
     RECT  91.98 116.609 122.022 117.391 ;
     RECT  56.415 2.413 56.697 117.481 ;
     RECT  61.236 117.391 122.022 117.959 ;
     RECT  60.372 117.085 60.39 118.705 ;
     RECT  61.236 117.959 113.814 118.741 ;
     RECT  114.588 117.959 122.022 118.741 ;
     RECT  58.428 116.707 58.446 119.209 ;
     RECT  59.94 118.705 60.39 119.245 ;
     RECT  61.236 118.741 122.022 119.245 ;
     RECT  59.94 119.245 122.022 119.399 ;
     RECT  56.415 117.481 57.042 119.551 ;
     RECT  57.852 119.209 58.734 119.551 ;
     RECT  56.415 119.551 58.734 119.677 ;
     RECT  59.94 119.399 120.15 120.523 ;
     RECT  59.94 120.523 120.294 120.595 ;
     RECT  121.068 119.399 122.022 120.595 ;
     RECT  56.415 119.677 58.878 120.715 ;
     RECT  59.94 120.595 122.022 120.785 ;
     RECT  56.415 120.715 59.13 120.901 ;
     RECT  59.94 120.785 70.326 120.901 ;
     RECT  56.415 120.901 70.326 121.675 ;
     RECT  71.064 120.785 122.022 121.675 ;
     RECT  56.415 121.675 122.022 122.099 ;
     RECT  56.415 122.099 121.986 122.669 ;
     RECT  56.415 122.669 117.126 122.719 ;
     RECT  56.196 122.719 117.126 122.755 ;
     RECT  56.052 122.755 117.126 123.179 ;
     RECT  118.08 122.669 121.986 123.449 ;
     RECT  118.08 123.449 121.497 123.565 ;
     RECT  117.972 123.565 121.497 123.863 ;
     RECT  117.972 123.863 120.438 123.871 ;
     RECT  56.052 123.179 116.946 123.997 ;
     RECT  117.72 123.871 120.438 123.997 ;
     RECT  56.052 123.997 120.438 124.259 ;
     RECT  56.052 124.259 120.294 124.295 ;
     RECT  56.052 124.295 119.862 124.807 ;
     RECT  55.98 124.807 119.862 124.835 ;
     RECT  55.98 124.835 118.206 125.419 ;
     RECT  55.944 125.419 118.206 125.887 ;
     RECT  119.088 124.835 119.862 125.887 ;
     RECT  55.944 125.887 119.862 125.923 ;
     RECT  55.8 125.923 119.862 126.463 ;
     RECT  55.728 126.463 119.862 126.725 ;
     RECT  55.728 126.725 117.846 126.805 ;
     RECT  55.584 126.805 117.846 126.845 ;
     RECT  119.52 126.725 119.862 126.869 ;
     RECT  118.584 126.725 118.602 126.959 ;
     RECT  55.692 126.845 117.846 127.031 ;
     RECT  55.692 127.031 117.774 127.103 ;
     RECT  2.415 64.319 2.697 127.187 ;
     RECT  7.815 2.413 8.097 127.187 ;
     RECT  13.215 2.413 13.497 127.187 ;
     RECT  18.615 2.413 18.897 127.187 ;
     RECT  24.015 2.413 24.297 127.187 ;
     RECT  29.415 2.413 29.697 127.187 ;
     RECT  34.815 2.413 35.097 127.187 ;
     RECT  40.215 2.413 40.497 127.187 ;
     RECT  45.615 2.413 45.897 127.187 ;
     RECT  51.015 2.413 51.297 127.187 ;
     RECT  121.215 123.863 121.497 127.187 ;
     RECT  126.615 2.413 126.897 127.187 ;
     RECT  132.015 78.368 132.297 127.187 ;
     RECT  137.415 2.413 137.697 127.187 ;
     RECT  142.815 78.368 143.097 127.187 ;
     RECT  148.215 2.413 148.497 127.187 ;
     RECT  153.615 78.368 153.897 127.187 ;
     RECT  159.015 2.413 159.297 127.187 ;
     RECT  164.415 65.408 164.697 127.187 ;
     RECT  169.815 88.619 170.097 127.187 ;
     RECT  55.692 127.103 117.342 127.229 ;
     RECT  119.52 126.869 119.718 127.229 ;
     RECT  55.692 127.229 107.01 127.265 ;
     RECT  107.748 127.229 117.27 127.265 ;
     RECT  119.52 127.229 119.538 127.265 ;
     RECT  57.672 127.265 72.99 127.337 ;
     RECT  115.815 127.265 116.658 127.337 ;
     RECT  73.728 127.265 107.01 127.373 ;
     RECT  75.852 127.373 82.494 127.409 ;
     RECT  83.34 127.373 107.01 127.409 ;
     RECT  115.815 127.337 116.622 127.409 ;
     RECT  57.744 127.337 72.99 127.421 ;
     RECT  73.728 127.373 74.538 127.421 ;
     RECT  76.104 127.409 82.494 127.421 ;
     RECT  83.34 127.409 86.058 127.421 ;
     RECT  90.972 127.409 107.01 127.421 ;
     RECT  107.748 127.265 114.534 127.421 ;
     RECT  2.415 127.187 2.505 127.457 ;
     RECT  7.815 127.187 7.905 127.457 ;
     RECT  13.215 127.187 13.305 127.457 ;
     RECT  18.615 127.187 18.705 127.457 ;
     RECT  24.015 127.187 24.105 127.457 ;
     RECT  29.415 127.187 29.505 127.457 ;
     RECT  34.815 127.187 34.905 127.457 ;
     RECT  40.215 127.187 40.305 127.457 ;
     RECT  45.615 127.187 45.705 127.457 ;
     RECT  51.015 127.187 51.105 127.457 ;
     RECT  115.815 127.409 116.262 127.457 ;
     RECT  121.215 127.187 121.305 127.457 ;
     RECT  126.615 127.187 126.705 127.457 ;
     RECT  132.015 127.187 132.105 127.457 ;
     RECT  137.415 127.187 137.505 127.457 ;
     RECT  142.815 127.187 142.905 127.457 ;
     RECT  148.215 127.187 148.305 127.457 ;
     RECT  153.615 127.187 153.705 127.457 ;
     RECT  159.015 127.187 159.105 127.457 ;
     RECT  164.415 127.187 164.505 127.457 ;
     RECT  169.815 127.187 169.905 127.457 ;
     RECT  57.744 127.421 59.454 127.469 ;
     RECT  63.324 127.421 63.522 127.469 ;
     RECT  64.944 127.421 69.714 127.469 ;
     RECT  74.016 127.421 74.538 127.469 ;
     RECT  76.752 127.421 79.218 127.469 ;
     RECT  87.12 127.409 89.946 127.469 ;
     RECT  93.672 127.421 94.662 127.469 ;
     RECT  102.744 127.421 102.762 127.469 ;
     RECT  103.5 127.421 107.01 127.469 ;
     RECT  71.244 127.421 72.99 127.499 ;
     RECT  74.484 127.469 74.538 127.499 ;
     RECT  87.48 127.469 89.946 127.499 ;
     RECT  104.328 127.469 105.858 127.499 ;
     RECT  110.34 127.421 114.534 127.499 ;
     RECT  116.244 127.457 116.262 127.499 ;
     RECT  107.748 127.421 107.874 127.517 ;
     RECT  98.748 127.421 99.99 127.565 ;
     RECT  110.34 127.499 113.742 127.565 ;
     RECT  113.256 127.565 113.742 127.571 ;
     RECT  114.516 127.499 114.534 127.571 ;
     RECT  55.692 127.265 56.898 127.613 ;
     RECT  60.732 127.421 62.298 127.613 ;
     RECT  64.944 127.469 69.426 127.613 ;
     RECT  71.64 127.499 72.99 127.613 ;
     RECT  85.032 127.421 86.058 127.613 ;
     RECT  87.48 127.499 89.478 127.613 ;
     RECT  90.972 127.421 92.898 127.613 ;
     RECT  98.748 127.565 99.558 127.613 ;
     RECT  104.976 127.499 105.678 127.613 ;
     RECT  107.856 127.517 107.874 127.613 ;
     RECT  111.276 127.565 112.302 127.613 ;
     RECT  55.764 127.613 56.898 127.661 ;
     RECT  58.644 127.469 59.454 127.661 ;
     RECT  60.732 127.613 61.506 127.661 ;
     RECT  64.944 127.613 65.754 127.661 ;
     RECT  66.492 127.613 68.562 127.661 ;
     RECT  69.408 127.613 69.426 127.661 ;
     RECT  71.64 127.613 72.774 127.661 ;
     RECT  74.484 127.499 74.502 127.661 ;
     RECT  77.148 127.469 79.218 127.661 ;
     RECT  80.352 127.421 80.622 127.661 ;
     RECT  81.576 127.421 81.918 127.661 ;
     RECT  83.34 127.421 84.114 127.661 ;
     RECT  85.032 127.613 85.842 127.661 ;
     RECT  87.84 127.613 89.334 127.661 ;
     RECT  91.188 127.613 92.898 127.661 ;
     RECT  94.068 127.469 94.662 127.661 ;
     RECT  98.748 127.613 98.766 127.661 ;
     RECT  99.504 127.613 99.558 127.661 ;
     RECT  100.908 127.421 100.926 127.661 ;
     RECT  101.88 127.421 101.898 127.661 ;
     RECT  105.336 127.613 105.354 127.661 ;
     RECT  108.684 127.421 109.494 127.661 ;
     RECT  110.34 127.565 110.358 127.661 ;
     RECT  111.816 127.613 112.302 127.661 ;
     RECT  57.744 127.469 57.762 127.709 ;
     RECT  58.644 127.661 59.274 127.709 ;
     RECT  83.664 127.661 84.114 127.709 ;
     RECT  89.244 127.661 89.262 127.709 ;
     RECT  94.068 127.661 94.59 127.709 ;
     RECT  95.76 127.421 96.75 127.709 ;
     RECT  94.068 127.709 94.086 128.285 ;
     RECT  111.816 127.661 112.266 128.285 ;
     RECT  112.248 128.285 112.266 128.333 ;
     RECT  79.2 127.661 79.218 128.525 ;
     RECT  96.048 127.709 96.75 128.813 ;
     RECT  108.684 127.661 108.702 128.813 ;
     RECT  58.644 127.709 58.662 128.861 ;
     RECT  71.64 127.661 72.234 128.861 ;
     RECT  80.352 127.661 80.37 128.861 ;
     RECT  96.3 128.813 96.75 128.861 ;
     RECT  99.504 127.661 99.522 128.861 ;
     RECT  96.3 128.861 96.318 128.909 ;
     RECT  73.476 129.211 73.494 129.259 ;
     RECT  97.956 127.421 97.974 129.259 ;
     RECT  99.216 129.211 99.414 129.259 ;
     RECT  111.096 129.163 111.114 129.259 ;
     RECT  97.956 129.259 99.414 129.293 ;
     RECT  73.404 129.259 73.494 129.307 ;
     RECT  70.704 129.307 70.722 129.355 ;
     RECT  71.64 128.861 71.91 129.355 ;
     RECT  73.26 129.307 73.494 129.389 ;
     RECT  98.424 129.293 99.414 129.389 ;
     RECT  73.26 129.389 73.422 129.437 ;
     RECT  98.424 129.389 98.514 129.437 ;
     RECT  62.28 129.355 62.298 129.485 ;
     RECT  63.504 127.469 63.522 129.485 ;
     RECT  68.724 129.355 68.742 129.485 ;
     RECT  70.704 129.355 71.91 129.485 ;
     RECT  73.26 129.437 73.278 129.485 ;
     RECT  79.668 129.355 79.686 129.485 ;
     RECT  84.096 127.709 84.114 129.485 ;
     RECT  94.608 129.307 94.626 129.485 ;
     RECT  98.424 129.437 98.442 129.485 ;
     RECT  99.396 129.389 99.414 129.485 ;
     RECT  110.844 129.259 111.114 129.485 ;
    LAYER M4 ;
     RECT  0.06 58.992 0.137 59.112 ;
     RECT  0.137 58.992 0.227 59.016 ;
     RECT  0.181 74.112 2.408 74.136 ;
     RECT  2.408 2.148 2.512 127.452 ;
     RECT  2.512 2.418 2.704 127.182 ;
     RECT  2.704 74.112 7.808 74.136 ;
     RECT  7.808 2.148 7.912 127.452 ;
     RECT  7.912 2.418 8.104 127.182 ;
     RECT  8.104 74.112 13.208 74.136 ;
     RECT  13.208 2.148 13.312 127.452 ;
     RECT  13.312 2.418 13.504 127.182 ;
     RECT  13.504 74.112 18.608 74.136 ;
     RECT  18.608 2.148 18.712 127.452 ;
     RECT  18.712 2.418 18.904 127.182 ;
     RECT  18.904 74.112 24.008 74.136 ;
     RECT  24.008 2.148 24.112 127.452 ;
     RECT  24.112 2.418 24.304 127.182 ;
     RECT  24.304 74.112 29.408 74.136 ;
     RECT  29.408 2.148 29.512 127.452 ;
     RECT  29.512 2.418 29.704 127.182 ;
     RECT  29.704 74.112 34.808 74.136 ;
     RECT  34.808 2.148 34.912 127.452 ;
     RECT  34.912 2.418 35.104 127.182 ;
     RECT  35.104 74.112 40.208 74.136 ;
     RECT  40.208 2.148 40.312 127.452 ;
     RECT  40.312 2.418 40.504 127.182 ;
     RECT  40.504 74.112 45.608 74.136 ;
     RECT  45.608 2.148 45.712 127.452 ;
     RECT  45.712 2.418 45.904 127.182 ;
     RECT  45.904 74.112 51.008 74.136 ;
     RECT  51.008 2.148 51.112 127.452 ;
     RECT  51.112 2.418 51.304 127.182 ;
     RECT  55.333 127.632 55.429 127.656 ;
     RECT  55.429 127.584 55.525 127.656 ;
     RECT  55.525 127.536 55.573 127.656 ;
     RECT  55.573 126.816 55.753 127.656 ;
     RECT  55.813 125.376 55.933 125.4 ;
     RECT  51.304 74.112 56.408 74.136 ;
     RECT  55.933 125.376 56.408 125.448 ;
     RECT  55.753 126.576 56.408 127.656 ;
     RECT  56.408 2.148 56.512 127.656 ;
     RECT  56.485 129.456 56.581 129.48 ;
     RECT  56.512 2.418 56.704 127.656 ;
     RECT  56.581 129.36 56.963 129.48 ;
     RECT  56.963 129.36 57.011 129.384 ;
     RECT  56.704 122.16 57.733 127.656 ;
     RECT  57.733 122.16 58.453 127.704 ;
     RECT  58.633 128.832 58.835 128.856 ;
     RECT  58.453 122.112 58.921 127.704 ;
     RECT  58.921 121.152 59.101 127.704 ;
     RECT  59.101 120.72 59.411 127.704 ;
     RECT  59.411 120.72 59.603 127.656 ;
     RECT  59.603 120.72 60.473 127.416 ;
     RECT  60.473 120.768 60.721 127.416 ;
     RECT  58.645 116.736 61.369 116.76 ;
     RECT  61.369 116.736 61.532 117 ;
     RECT  61.369 118.56 61.532 119.064 ;
     RECT  60.721 120.768 61.561 127.656 ;
     RECT  61.532 116.736 61.573 119.064 ;
     RECT  61.573 116.448 61.765 119.064 ;
     RECT  56.704 74.112 61.808 74.136 ;
     RECT  61.765 116.448 61.808 119.16 ;
     RECT  61.561 120.768 61.808 127.608 ;
     RECT  61.621 128.784 61.811 128.808 ;
     RECT  61.808 2.148 61.912 127.608 ;
     RECT  61.912 2.418 62.104 127.608 ;
     RECT  61.957 129.264 62.225 129.336 ;
     RECT  62.104 120.72 62.309 127.608 ;
     RECT  62.225 129.264 62.309 129.48 ;
     RECT  62.104 115.632 62.381 116.76 ;
     RECT  62.309 129.264 62.627 129.432 ;
     RECT  62.104 119.136 62.957 119.64 ;
     RECT  62.627 129.312 63.251 129.432 ;
     RECT  62.309 120.72 63.281 127.464 ;
     RECT  63.251 129.408 63.301 129.432 ;
     RECT  62.381 115.632 63.349 116.472 ;
     RECT  63.281 122.256 63.353 127.464 ;
     RECT  63.353 122.256 63.395 127.416 ;
     RECT  63.349 115.632 63.397 116.856 ;
     RECT  63.301 129.408 63.533 129.48 ;
     RECT  63.397 115.632 63.857 117.24 ;
     RECT  62.957 119.376 63.932 119.4 ;
     RECT  63.533 129.408 64.163 129.432 ;
     RECT  63.932 118.752 64.537 119.4 ;
     RECT  63.281 120.72 64.609 120.744 ;
     RECT  64.537 118.56 64.649 119.4 ;
     RECT  63.857 116.832 64.721 117.24 ;
     RECT  64.721 117.216 64.793 117.24 ;
     RECT  64.609 120.72 64.825 121.176 ;
     RECT  63.395 123.12 64.892 127.416 ;
     RECT  64.825 120.72 64.897 121.416 ;
     RECT  64.649 119.376 64.933 119.4 ;
     RECT  64.897 120.72 65.468 121.656 ;
     RECT  64.892 123.12 65.468 127.656 ;
     RECT  65.468 120.72 65.555 127.656 ;
     RECT  65.555 123.12 65.765 127.656 ;
     RECT  64.933 119.376 65.893 119.688 ;
     RECT  65.555 120.72 65.893 121.992 ;
     RECT  65.761 118.224 65.939 118.248 ;
     RECT  65.893 119.376 65.945 121.992 ;
     RECT  65.945 119.52 65.98 121.992 ;
     RECT  65.765 123.168 65.981 127.656 ;
     RECT  63.857 115.632 66.193 115.656 ;
     RECT  66.193 115.536 66.709 115.656 ;
     RECT  65.98 119.52 66.949 119.688 ;
     RECT  65.98 120.72 66.949 121.992 ;
     RECT  66.949 119.52 67.093 121.992 ;
     RECT  65.981 123.216 67.093 127.656 ;
     RECT  62.104 74.112 67.208 74.136 ;
     RECT  66.709 115.536 67.208 115.944 ;
     RECT  67.093 119.52 67.208 127.656 ;
     RECT  67.208 2.148 67.312 127.656 ;
     RECT  67.312 2.418 67.504 127.656 ;
     RECT  67.504 119.52 67.565 127.656 ;
     RECT  67.565 119.664 67.637 127.656 ;
     RECT  67.637 119.664 67.673 122.568 ;
     RECT  67.673 120.672 67.781 122.568 ;
     RECT  67.781 120.72 67.925 122.568 ;
     RECT  68.389 129.408 68.674 129.432 ;
     RECT  67.504 117.984 68.677 118.008 ;
     RECT  68.677 117.984 68.717 118.2 ;
     RECT  68.717 118.176 68.821 118.2 ;
     RECT  67.673 119.664 68.821 119.688 ;
     RECT  68.674 129.36 68.915 129.48 ;
     RECT  68.915 129.36 68.963 129.384 ;
     RECT  67.504 115.632 68.965 116.232 ;
     RECT  68.965 115.536 69.257 116.472 ;
     RECT  68.821 118.176 69.289 119.688 ;
     RECT  67.925 120.72 69.289 121.992 ;
     RECT  67.637 123.648 69.289 127.656 ;
     RECT  69.289 123.072 69.437 127.656 ;
     RECT  69.437 123.072 69.505 127.464 ;
     RECT  69.289 118.176 69.545 121.992 ;
     RECT  69.545 121.68 69.617 121.992 ;
     RECT  69.505 122.976 69.685 127.464 ;
     RECT  69.685 122.736 69.725 127.464 ;
     RECT  70.117 129.216 70.501 129.24 ;
     RECT  69.545 118.176 70.517 120.648 ;
     RECT  70.501 129.216 70.547 129.48 ;
     RECT  70.517 118.176 70.729 118.296 ;
     RECT  69.617 121.68 70.801 121.704 ;
     RECT  69.725 122.736 70.801 127.416 ;
     RECT  70.547 129.264 70.883 129.48 ;
     RECT  69.257 115.92 70.913 116.472 ;
     RECT  70.729 118.032 70.949 118.296 ;
     RECT  70.517 119.376 71.221 120.648 ;
     RECT  70.801 121.68 71.221 127.416 ;
     RECT  70.883 129.312 71.921 129.48 ;
     RECT  71.221 119.376 71.953 127.416 ;
     RECT  71.921 129.312 72.035 129.432 ;
     RECT  72.035 129.312 72.179 129.336 ;
     RECT  71.953 119.376 72.469 127.656 ;
     RECT  70.949 118.032 72.493 118.056 ;
     RECT  72.205 128.832 72.563 129.288 ;
     RECT  72.493 117.888 72.601 118.056 ;
     RECT  72.469 119.376 72.601 127.752 ;
     RECT  71.557 71.088 72.608 71.112 ;
     RECT  67.504 74.112 72.608 74.136 ;
     RECT  72.133 113.808 72.608 113.832 ;
     RECT  70.913 115.92 72.608 115.944 ;
     RECT  72.601 117.888 72.608 127.752 ;
     RECT  72.608 2.148 72.659 127.752 ;
     RECT  72.659 2.148 72.712 127.656 ;
     RECT  72.712 2.418 72.904 127.656 ;
     RECT  72.904 118.992 72.947 127.656 ;
     RECT  72.947 118.992 73.001 127.608 ;
     RECT  73.001 118.992 73.073 127.464 ;
     RECT  72.563 129.216 73.189 129.288 ;
     RECT  73.189 129.216 73.234 129.384 ;
     RECT  73.234 129.216 73.333 129.48 ;
     RECT  73.333 129.216 73.466 129.432 ;
     RECT  72.904 117.888 73.505 117.912 ;
     RECT  73.466 129.216 73.505 129.384 ;
     RECT  73.505 129.264 73.523 129.384 ;
     RECT  73.523 129.36 73.549 129.384 ;
     RECT  72.904 115.92 73.957 115.944 ;
     RECT  73.073 119.232 74.041 127.464 ;
     RECT  72.904 113.712 74.053 114.552 ;
     RECT  73.957 115.92 74.053 116.328 ;
     RECT  72.904 71.088 74.329 71.112 ;
     RECT  74.041 118.416 74.341 127.464 ;
     RECT  74.341 118.416 74.513 127.656 ;
     RECT  74.221 64.464 74.653 64.488 ;
     RECT  74.053 113.712 74.677 116.328 ;
     RECT  74.653 64.464 74.693 64.632 ;
     RECT  74.677 113.712 75.053 116.472 ;
     RECT  75.053 113.712 75.161 114.552 ;
     RECT  74.917 128.496 75.397 128.52 ;
     RECT  75.397 128.496 75.587 129.432 ;
     RECT  74.513 118.416 76.057 127.368 ;
     RECT  76.057 118.032 76.093 127.368 ;
     RECT  75.053 115.68 76.237 116.472 ;
     RECT  75.161 113.712 76.241 113.736 ;
     RECT  76.093 118.032 76.547 127.416 ;
     RECT  76.237 115.488 76.561 116.472 ;
     RECT  75.587 128.496 76.597 128.52 ;
     RECT  76.547 119.232 76.741 127.416 ;
     RECT  76.597 128.496 76.883 129.48 ;
     RECT  76.561 115.488 76.885 116.856 ;
     RECT  76.547 118.032 76.885 118.056 ;
     RECT  76.885 115.488 76.931 118.056 ;
     RECT  76.931 115.488 77.033 117.48 ;
     RECT  76.741 119.232 77.137 127.464 ;
     RECT  76.883 128.496 77.137 128.52 ;
     RECT  77.137 119.232 77.857 128.52 ;
     RECT  77.569 24.48 78.008 24.504 ;
     RECT  74.693 64.608 78.008 64.632 ;
     RECT  74.329 71.088 78.008 71.16 ;
     RECT  72.904 74.112 78.008 74.136 ;
     RECT  77.605 92.4 78.008 92.424 ;
     RECT  76.693 111.648 78.008 111.672 ;
     RECT  77.893 112.656 78.008 112.68 ;
     RECT  76.453 113.808 78.008 113.832 ;
     RECT  77.033 115.488 78.008 117.384 ;
     RECT  77.857 118.992 78.008 128.52 ;
     RECT  78.008 2.148 78.085 128.52 ;
     RECT  78.085 2.148 78.112 129.432 ;
     RECT  78.112 2.418 78.304 129.432 ;
     RECT  78.304 111.552 78.401 111.672 ;
     RECT  78.304 23.808 78.419 24.264 ;
     RECT  78.304 64.608 78.419 64.632 ;
     RECT  78.304 115.728 78.467 129.432 ;
     RECT  78.467 118.464 78.563 129.384 ;
     RECT  78.563 118.464 78.625 129.336 ;
     RECT  78.419 24.24 78.689 24.264 ;
     RECT  78.304 112.656 79.013 113.448 ;
     RECT  78.625 118.464 79.049 127.416 ;
     RECT  78.625 128.496 79.229 129.336 ;
     RECT  78.304 3.408 79.265 3.96 ;
     RECT  79.229 129.216 79.613 129.336 ;
     RECT  79.613 129.216 79.697 129.48 ;
     RECT  79.621 0.096 79.705 0.12 ;
     RECT  79.049 118.896 79.805 127.416 ;
     RECT  79.013 112.656 79.949 113.112 ;
     RECT  79.369 114.528 80.341 114.552 ;
     RECT  79.697 129.216 80.341 129.432 ;
     RECT  79.949 112.656 80.387 112.872 ;
     RECT  78.467 115.728 80.453 117.384 ;
     RECT  79.805 119.376 80.525 127.416 ;
     RECT  80.341 128.832 80.531 129.432 ;
     RECT  80.525 124.752 80.549 127.416 ;
     RECT  79.717 1.728 80.597 1.752 ;
     RECT  78.401 111.552 80.677 111.576 ;
     RECT  80.387 112.656 80.677 112.68 ;
     RECT  80.531 129.408 80.771 129.432 ;
     RECT  80.453 115.728 80.777 117 ;
     RECT  80.341 114 81.209 114.552 ;
     RECT  80.341 118.368 81.605 118.392 ;
     RECT  80.525 119.376 81.673 123.768 ;
     RECT  81.541 109.392 81.853 109.416 ;
     RECT  81.673 118.656 81.853 123.768 ;
     RECT  80.549 124.752 81.853 127.656 ;
     RECT  81.853 109.392 81.965 110.568 ;
     RECT  81.209 114.528 82.117 114.552 ;
     RECT  81.853 118.656 82.145 127.656 ;
     RECT  80.777 116.784 82.177 117 ;
     RECT  78.304 92.4 82.321 92.424 ;
     RECT  82.177 116.784 82.357 117.624 ;
     RECT  82.117 114.528 82.609 115.176 ;
     RECT  82.357 116.352 82.609 117.624 ;
     RECT  80.677 111.552 82.681 112.68 ;
     RECT  82.609 114.528 82.753 117.624 ;
     RECT  81.965 109.392 83.213 110.04 ;
     RECT  82.681 111.312 83.213 112.68 ;
     RECT  78.304 71.088 83.408 71.16 ;
     RECT  78.304 74.112 83.408 74.136 ;
     RECT  82.321 92.4 83.408 92.52 ;
     RECT  83.213 109.392 83.408 112.68 ;
     RECT  82.753 114.384 83.408 117.624 ;
     RECT  82.145 118.896 83.408 127.656 ;
     RECT  83.408 2.148 83.512 127.656 ;
     RECT  83.512 2.418 83.612 127.656 ;
     RECT  83.612 2.418 83.699 127.704 ;
     RECT  83.699 2.418 83.704 127.656 ;
     RECT  83.704 119.472 83.765 127.656 ;
     RECT  83.765 119.472 83.873 127.608 ;
     RECT  83.461 129.456 84.037 129.48 ;
     RECT  84.037 129.408 84.125 129.48 ;
     RECT  83.704 100.896 84.131 101.256 ;
     RECT  84.125 129.408 84.323 129.432 ;
     RECT  84.131 100.896 84.493 100.92 ;
     RECT  83.704 114.384 84.521 114.936 ;
     RECT  83.704 116.208 84.901 116.808 ;
     RECT  83.704 117.936 84.901 118.2 ;
     RECT  84.901 116.208 84.911 118.2 ;
     RECT  84.911 116.064 84.913 118.2 ;
     RECT  83.873 119.472 84.913 127.416 ;
     RECT  83.704 111.312 84.949 111.336 ;
     RECT  83.704 112.32 84.949 112.68 ;
     RECT  84.913 116.064 84.977 127.416 ;
     RECT  84.977 116.064 84.989 127.656 ;
     RECT  83.704 92.4 85.235 92.52 ;
     RECT  84.989 116.064 85.235 116.808 ;
     RECT  84.949 111.312 85.241 112.68 ;
     RECT  85.235 116.208 85.313 116.664 ;
     RECT  85.241 111.312 85.349 112.344 ;
     RECT  84.989 118.176 85.853 127.656 ;
     RECT  85.853 118.464 86.069 127.608 ;
     RECT  86.069 118.464 86.14 127.464 ;
     RECT  84.521 114.912 86.293 114.936 ;
     RECT  85.349 111.312 86.396 111.48 ;
     RECT  85.309 113.328 86.396 113.352 ;
     RECT  86.396 113.328 86.437 113.88 ;
     RECT  86.293 114.912 86.437 115.416 ;
     RECT  86.396 111.312 86.483 112.008 ;
     RECT  86.437 113.328 86.483 115.416 ;
     RECT  86.483 114.816 86.605 115.416 ;
     RECT  86.14 118.464 86.681 119.736 ;
     RECT  86.681 118.464 86.714 119.496 ;
     RECT  86.605 114.816 86.861 115.512 ;
     RECT  86.714 118.464 86.897 119.448 ;
     RECT  85.313 116.64 87.205 116.664 ;
     RECT  86.14 120.864 87.205 127.464 ;
     RECT  86.483 113.328 87.257 113.352 ;
     RECT  87.205 116.64 87.257 117.384 ;
     RECT  87.257 117.36 87.292 117.384 ;
     RECT  86.483 111.312 87.329 111.48 ;
     RECT  86.897 118.464 87.401 119.016 ;
     RECT  86.861 114.816 87.797 114.84 ;
     RECT  88.153 117.504 88.441 117.528 ;
     RECT  87.401 118.992 88.441 119.016 ;
     RECT  87.205 120.864 88.477 127.656 ;
     RECT  87.329 111.312 88.693 111.336 ;
     RECT  88.685 112.944 88.693 112.968 ;
     RECT  88.597 129.408 88.693 129.432 ;
     RECT  83.704 53.808 88.808 53.832 ;
     RECT  83.704 71.088 88.808 71.16 ;
     RECT  83.704 74.112 88.808 74.136 ;
     RECT  85.235 92.496 88.808 92.52 ;
     RECT  88.693 111.312 88.808 112.968 ;
     RECT  88.441 117.504 88.808 119.016 ;
     RECT  88.477 120.816 88.808 127.656 ;
     RECT  88.693 129.312 88.883 129.432 ;
     RECT  88.808 2.148 88.912 127.656 ;
     RECT  88.912 2.418 89.104 127.656 ;
     RECT  89.104 121.104 89.125 127.656 ;
     RECT  89.104 116.16 89.165 119.112 ;
     RECT  89.125 121.104 89.273 127.704 ;
     RECT  89.273 121.104 89.345 127.656 ;
     RECT  89.345 121.104 89.489 127.608 ;
     RECT  89.104 92.112 89.555 92.52 ;
     RECT  89.104 74.64 90.001 74.664 ;
     RECT  89.489 121.104 90.277 127.128 ;
     RECT  89.165 116.16 90.317 116.184 ;
     RECT  88.883 129.408 90.371 129.432 ;
     RECT  89.165 117.408 90.529 119.112 ;
     RECT  89.555 92.112 90.637 92.136 ;
     RECT  90.277 121.056 90.661 127.128 ;
     RECT  90.637 92.112 90.677 92.232 ;
     RECT  90.529 117.408 90.709 119.688 ;
     RECT  90.709 117.408 91.213 119.736 ;
     RECT  90.661 121.056 91.213 127.656 ;
     RECT  91.213 117.408 91.397 127.656 ;
     RECT  91.177 116.256 91.571 116.28 ;
     RECT  92.684 115.824 92.725 115.848 ;
     RECT  91.397 117.744 92.725 127.656 ;
     RECT  92.725 115.104 92.771 115.848 ;
     RECT  92.725 116.832 92.909 127.656 ;
     RECT  92.909 116.832 92.915 127.464 ;
     RECT  93.157 129.264 93.253 129.288 ;
     RECT  93.253 129.264 93.299 129.384 ;
     RECT  93.299 129.36 93.443 129.384 ;
     RECT  92.771 115.104 93.637 115.128 ;
     RECT  92.915 117.36 94.021 127.464 ;
     RECT  94.021 117.36 94.057 127.56 ;
     RECT  89.104 53.808 94.208 53.832 ;
     RECT  89.104 71.088 94.208 71.16 ;
     RECT  90.677 92.208 94.208 92.232 ;
     RECT  89.104 111.696 94.208 111.72 ;
     RECT  93.373 112.992 94.208 113.016 ;
     RECT  93.637 114.288 94.208 115.128 ;
     RECT  94.057 117.36 94.208 128.28 ;
     RECT  94.208 2.148 94.312 128.28 ;
     RECT  94.312 2.418 94.504 128.28 ;
     RECT  94.504 118.08 94.547 128.28 ;
     RECT  94.504 115.392 94.565 115.512 ;
     RECT  94.556 129.456 94.584 129.48 ;
     RECT  94.547 118.08 94.634 127.704 ;
     RECT  94.504 92.208 94.637 92.232 ;
     RECT  94.584 129.312 94.643 129.48 ;
     RECT  94.643 129.312 94.691 129.336 ;
     RECT  94.634 118.08 94.739 127.656 ;
     RECT  94.504 114.288 94.853 114.312 ;
     RECT  94.504 111.696 94.889 112.68 ;
     RECT  94.739 118.08 95.393 127.416 ;
     RECT  95.393 118.512 95.749 127.416 ;
     RECT  94.565 115.488 95.857 115.512 ;
     RECT  95.845 129.456 96.037 129.48 ;
     RECT  94.889 112.656 96.113 112.68 ;
     RECT  95.713 116.88 96.257 116.904 ;
     RECT  96.037 128.784 96.275 129.48 ;
     RECT  95.857 115.488 96.433 115.56 ;
     RECT  95.749 118.512 96.517 127.704 ;
     RECT  96.517 117.936 96.563 127.704 ;
     RECT  96.563 117.936 96.604 127.656 ;
     RECT  96.604 117.984 96.755 127.656 ;
     RECT  96.433 115.008 96.821 115.56 ;
     RECT  96.275 128.784 96.851 128.904 ;
     RECT  96.821 115.008 96.905 116.328 ;
     RECT  96.851 128.832 96.947 128.904 ;
     RECT  96.947 128.88 97.427 128.904 ;
     RECT  96.905 115.008 97.517 115.512 ;
     RECT  97.549 114.576 97.661 114.6 ;
     RECT  97.333 116.736 97.837 116.76 ;
     RECT  96.755 117.984 97.837 127.416 ;
     RECT  97.861 111.072 98.233 111.096 ;
     RECT  97.945 129.216 98.341 129.288 ;
     RECT  98.341 129.216 98.386 129.384 ;
     RECT  97.837 116.736 98.533 127.416 ;
     RECT  98.533 116.208 98.579 127.416 ;
     RECT  96.325 92.112 98.593 92.136 ;
     RECT  98.593 92.112 98.633 92.232 ;
     RECT  98.233 111.072 98.725 111.144 ;
     RECT  98.629 114.384 98.737 114.408 ;
     RECT  98.579 117.792 98.737 127.416 ;
     RECT  98.053 112.848 99.349 112.872 ;
     RECT  98.737 117.792 99.445 127.656 ;
     RECT  98.386 129.216 99.469 129.48 ;
     RECT  98.737 114.384 99.493 115.176 ;
     RECT  99.469 129.216 99.493 129.432 ;
     RECT  94.504 53.808 99.608 53.832 ;
     RECT  94.504 71.088 99.608 71.16 ;
     RECT  98.633 92.208 99.608 92.232 ;
     RECT  98.725 110.304 99.608 111.144 ;
     RECT  99.349 112.512 99.608 112.872 ;
     RECT  99.493 114 99.608 115.176 ;
     RECT  98.579 116.208 99.608 116.76 ;
     RECT  99.445 117.792 99.608 127.704 ;
     RECT  99.608 2.148 99.712 127.704 ;
     RECT  99.712 2.418 99.731 127.704 ;
     RECT  99.493 128.832 99.827 129.432 ;
     RECT  99.731 2.418 99.904 127.56 ;
     RECT  99.827 129.216 100.019 129.432 ;
     RECT  99.904 114 100.037 114.024 ;
     RECT  99.904 92.208 100.403 92.232 ;
     RECT  99.904 116.592 100.547 127.56 ;
     RECT  100.547 117.12 100.741 127.56 ;
     RECT  100.741 117.12 100.835 127.656 ;
     RECT  100.019 129.408 100.835 129.432 ;
     RECT  99.904 110.304 100.981 112.872 ;
     RECT  100.835 118.848 101.081 127.656 ;
     RECT  100.835 117.12 101.405 117.816 ;
     RECT  101.221 114.576 101.461 114.6 ;
     RECT  100.981 110.304 101.477 112.92 ;
     RECT  101.081 119.04 101.909 127.656 ;
     RECT  101.461 114 102.161 114.6 ;
     RECT  102.161 114.288 102.257 114.6 ;
     RECT  102.157 115.728 102.257 115.752 ;
     RECT  101.477 110.304 102.323 112.872 ;
     RECT  102.257 114.288 102.341 115.752 ;
     RECT  102.341 115.632 102.371 115.752 ;
     RECT  101.909 119.04 102.445 127.464 ;
     RECT  101.405 117.12 102.449 117.144 ;
     RECT  102.445 118.512 102.589 127.464 ;
     RECT  102.589 118.32 102.611 127.464 ;
     RECT  102.323 110.304 102.851 112.536 ;
     RECT  102.611 121.392 103.237 127.464 ;
     RECT  102.371 115.728 103.525 115.752 ;
     RECT  102.611 118.32 103.673 120.264 ;
     RECT  103.673 118.32 103.717 120.216 ;
     RECT  103.525 115.728 103.763 116.232 ;
     RECT  103.717 117.936 103.804 120.216 ;
     RECT  102.341 114.288 103.824 114.312 ;
     RECT  103.763 115.728 103.961 116.04 ;
     RECT  102.851 111.936 103.997 112.536 ;
     RECT  103.333 129.408 104.195 129.432 ;
     RECT  103.237 121.392 104.245 127.656 ;
     RECT  102.851 110.304 104.281 110.76 ;
     RECT  103.997 111.936 104.281 111.96 ;
     RECT  104.245 121.296 104.281 127.656 ;
     RECT  104.281 110.304 104.389 111.96 ;
     RECT  103.804 118.512 104.821 120.216 ;
     RECT  104.281 121.2 104.821 127.656 ;
     RECT  99.904 53.808 105.008 53.832 ;
     RECT  99.904 71.088 105.008 71.16 ;
     RECT  104.389 109.728 105.008 111.96 ;
     RECT  103.961 116.016 105.008 116.04 ;
     RECT  104.749 117.264 105.008 117.288 ;
     RECT  104.821 118.512 105.008 127.656 ;
     RECT  105.008 2.148 105.112 127.656 ;
     RECT  105.061 129.36 105.253 129.384 ;
     RECT  105.112 2.418 105.304 127.656 ;
     RECT  105.304 118.368 105.365 127.656 ;
     RECT  105.304 112.512 105.443 112.536 ;
     RECT  105.304 113.904 105.443 115.704 ;
     RECT  105.253 129.36 105.443 129.432 ;
     RECT  105.443 129.36 105.539 129.384 ;
     RECT  105.443 114.096 105.581 115.704 ;
     RECT  105.365 118.368 105.689 127.608 ;
     RECT  105.581 114.096 106.193 114.12 ;
     RECT  105.304 109.392 106.211 110.568 ;
     RECT  105.581 115.152 106.445 115.704 ;
     RECT  105.689 118.368 106.697 127.464 ;
     RECT  106.445 115.152 106.769 115.176 ;
     RECT  106.697 118.704 106.981 127.464 ;
     RECT  105.304 117.264 107.125 117.288 ;
     RECT  106.211 110.304 107.129 110.568 ;
     RECT  107.125 117.264 107.341 117.432 ;
     RECT  106.981 118.704 107.345 127.512 ;
     RECT  107.345 118.944 107.365 127.512 ;
     RECT  107.341 117.072 107.381 117.432 ;
     RECT  107.129 110.544 107.651 110.568 ;
     RECT  106.585 111.552 107.885 111.576 ;
     RECT  107.365 118.944 107.885 127.608 ;
     RECT  107.845 112.848 108.035 112.872 ;
     RECT  108.229 115.104 108.317 115.128 ;
     RECT  107.381 117.072 108.469 117.288 ;
     RECT  108.469 116.208 108.557 117.288 ;
     RECT  108.557 115.728 108.641 117.288 ;
     RECT  108.565 78.48 108.652 78.504 ;
     RECT  106.585 114 108.673 114.024 ;
     RECT  108.037 129.408 108.673 129.432 ;
     RECT  108.641 116.208 108.857 117.288 ;
     RECT  108.673 128.784 108.947 129.432 ;
     RECT  107.885 118.944 108.997 127.512 ;
     RECT  108.673 114 109.213 114.456 ;
     RECT  108.997 118.944 109.357 127.656 ;
     RECT  108.947 129.312 109.379 129.432 ;
     RECT  109.379 129.312 109.427 129.336 ;
     RECT  109.213 113.952 109.429 114.456 ;
     RECT  108.857 116.208 109.717 116.856 ;
     RECT  109.357 118.416 110.245 127.656 ;
     RECT  110.245 118.416 110.341 128.28 ;
     RECT  109.717 115.968 110.365 116.856 ;
     RECT  105.304 53.808 110.408 53.832 ;
     RECT  108.637 65.472 110.408 65.496 ;
     RECT  105.304 71.088 110.408 71.16 ;
     RECT  108.817 78.432 110.408 78.456 ;
     RECT  109.429 113.04 110.408 114.6 ;
     RECT  110.365 115.968 110.408 117.384 ;
     RECT  110.341 118.416 110.408 128.328 ;
     RECT  110.408 2.148 110.512 128.328 ;
     RECT  110.512 2.418 110.629 128.328 ;
     RECT  110.629 2.418 110.677 129.24 ;
     RECT  110.677 2.418 110.704 129.432 ;
     RECT  110.704 118.368 110.818 129.432 ;
     RECT  110.704 113.856 110.981 114.552 ;
     RECT  110.818 118.368 111.004 129.48 ;
     RECT  111.004 118.368 111.089 120.792 ;
     RECT  111.004 121.824 111.125 129.48 ;
     RECT  111.125 129.36 111.155 129.48 ;
     RECT  111.155 129.456 111.169 129.48 ;
     RECT  111.125 121.824 111.197 128.328 ;
     RECT  110.981 113.904 111.233 114.552 ;
     RECT  111.089 118.368 111.484 120.456 ;
     RECT  110.704 78.24 111.491 78.504 ;
     RECT  111.484 118.368 111.491 119.976 ;
     RECT  110.704 115.968 111.532 117.384 ;
     RECT  111.532 115.968 111.701 116.904 ;
     RECT  111.197 121.968 111.971 128.328 ;
     RECT  111.701 115.968 112.172 116.76 ;
     RECT  111.971 122.256 112.277 128.328 ;
     RECT  111.233 114.528 112.313 114.552 ;
     RECT  112.277 122.448 112.313 127.656 ;
     RECT  112.172 115.584 112.417 116.76 ;
     RECT  111.491 118.944 112.597 119.976 ;
     RECT  112.597 118.368 112.777 119.976 ;
     RECT  112.313 122.448 112.817 127.56 ;
     RECT  112.777 117.984 112.961 119.976 ;
     RECT  112.417 115.056 112.981 116.76 ;
     RECT  112.817 122.448 113.033 127.464 ;
     RECT  112.981 115.056 113.317 117 ;
     RECT  112.961 117.984 113.317 119.688 ;
     RECT  113.033 122.448 113.389 127.08 ;
     RECT  113.317 115.056 113.501 119.688 ;
     RECT  113.501 115.056 113.681 117.528 ;
     RECT  113.501 118.56 113.753 119.688 ;
     RECT  113.389 121.968 113.891 127.08 ;
     RECT  113.681 115.68 113.933 117.528 ;
     RECT  113.753 118.944 113.987 119.688 ;
     RECT  113.891 121.968 114.113 123.288 ;
     RECT  113.891 124.608 114.113 127.08 ;
     RECT  114.113 124.656 114.257 127.08 ;
     RECT  113.933 116.208 114.473 117.528 ;
     RECT  113.987 118.944 114.617 119.112 ;
     RECT  114.113 122.256 114.865 123.288 ;
     RECT  114.865 122.256 115.045 123.432 ;
     RECT  114.473 116.736 115.117 117.528 ;
     RECT  114.617 118.944 115.117 119.064 ;
     RECT  114.257 124.656 115.253 126.936 ;
     RECT  115.045 122.256 115.297 123.48 ;
     RECT  114.901 115.104 115.381 115.128 ;
     RECT  115.297 122.256 115.525 123.576 ;
     RECT  115.253 124.656 115.525 127.128 ;
     RECT  110.704 53.808 115.808 53.832 ;
     RECT  110.704 65.376 115.808 65.4 ;
     RECT  110.704 71.088 115.808 71.16 ;
     RECT  111.491 78.24 115.808 78.408 ;
     RECT  113.281 79.44 115.808 79.464 ;
     RECT  115.093 113.904 115.808 113.928 ;
     RECT  115.381 115.104 115.808 115.752 ;
     RECT  115.117 116.736 115.808 119.064 ;
     RECT  113.713 120.768 115.808 120.792 ;
     RECT  115.525 122.256 115.808 127.128 ;
     RECT  115.808 2.148 115.912 127.452 ;
     RECT  115.912 2.418 116.104 127.182 ;
     RECT  116.104 115.68 116.597 116.76 ;
     RECT  116.104 121.392 116.668 121.416 ;
     RECT  116.104 117.888 116.771 119.016 ;
     RECT  116.597 115.68 116.813 116.616 ;
     RECT  116.104 122.64 116.813 127.08 ;
     RECT  116.813 122.64 117.107 125.976 ;
     RECT  116.813 115.68 117.281 115.704 ;
     RECT  116.813 126.96 117.389 127.08 ;
     RECT  117.107 124.128 117.461 125.976 ;
     RECT  117.461 124.272 117.497 125.976 ;
     RECT  116.771 118.176 117.569 119.016 ;
     RECT  117.569 118.512 117.605 119.016 ;
     RECT  117.389 126.96 117.785 127.032 ;
     RECT  117.745 119.28 117.925 119.304 ;
     RECT  117.637 120.864 117.925 120.888 ;
     RECT  117.497 125.904 117.932 125.976 ;
     RECT  117.925 119.28 117.971 120.888 ;
     RECT  117.497 124.272 118.019 124.872 ;
     RECT  117.971 120.096 118.037 120.264 ;
     RECT  117.107 122.64 118.069 122.664 ;
     RECT  117.932 125.904 118.433 126.648 ;
     RECT  118.433 126.528 118.499 126.648 ;
     RECT  118.069 122.64 118.549 122.808 ;
     RECT  118.549 122.64 118.595 123.144 ;
     RECT  118.499 126.528 118.613 126.552 ;
     RECT  118.019 124.272 119.009 124.296 ;
     RECT  118.037 120.24 119.125 120.264 ;
     RECT  119.125 120.24 119.212 120.792 ;
     RECT  118.789 121.968 119.653 121.992 ;
     RECT  118.595 123.12 119.653 123.144 ;
     RECT  119.653 121.968 119.945 123.144 ;
     RECT  119.945 122.544 120.089 123.144 ;
     RECT  120.089 123.12 120.161 123.144 ;
     RECT  116.104 53.808 121.208 53.832 ;
     RECT  116.104 65.376 121.208 65.4 ;
     RECT  116.104 71.088 121.208 71.16 ;
     RECT  116.104 78.24 121.208 78.408 ;
     RECT  116.104 79.44 121.208 79.464 ;
     RECT  119.212 120.768 121.208 120.792 ;
     RECT  121.208 2.148 121.312 127.452 ;
     RECT  121.312 2.418 121.504 127.182 ;
     RECT  121.504 53.808 126.608 53.832 ;
     RECT  121.504 65.376 126.608 65.4 ;
     RECT  121.504 71.088 126.608 71.16 ;
     RECT  121.504 78.24 126.608 78.408 ;
     RECT  121.504 79.44 126.608 79.464 ;
     RECT  126.608 2.148 126.712 127.452 ;
     RECT  126.712 2.418 126.904 127.182 ;
     RECT  126.904 53.808 132.008 53.832 ;
     RECT  126.904 65.376 132.008 65.4 ;
     RECT  126.904 71.088 132.008 71.16 ;
     RECT  126.904 78.24 132.008 78.408 ;
     RECT  126.904 79.44 132.008 79.464 ;
     RECT  132.008 2.148 132.112 127.452 ;
     RECT  132.112 2.418 132.304 127.182 ;
     RECT  132.304 53.808 137.408 53.832 ;
     RECT  132.304 65.376 137.408 65.4 ;
     RECT  132.304 71.088 137.408 71.16 ;
     RECT  132.304 78.24 137.408 78.408 ;
     RECT  132.304 79.44 137.408 79.464 ;
     RECT  137.408 2.148 137.512 127.452 ;
     RECT  137.512 2.418 137.704 127.182 ;
     RECT  137.704 53.808 142.808 53.832 ;
     RECT  137.704 65.376 142.808 65.4 ;
     RECT  137.704 71.088 142.808 71.16 ;
     RECT  137.704 78.24 142.808 78.408 ;
     RECT  137.704 79.44 142.808 79.464 ;
     RECT  142.808 2.148 142.912 127.452 ;
     RECT  142.912 2.418 143.104 127.182 ;
     RECT  143.104 53.808 148.208 53.832 ;
     RECT  143.104 65.376 148.208 65.4 ;
     RECT  143.104 71.088 148.208 71.16 ;
     RECT  143.104 78.24 148.208 78.408 ;
     RECT  143.104 79.44 148.208 79.464 ;
     RECT  148.208 2.148 148.312 127.452 ;
     RECT  148.312 2.418 148.504 127.182 ;
     RECT  148.504 53.808 153.608 53.832 ;
     RECT  148.504 65.376 153.608 65.4 ;
     RECT  148.504 71.088 153.608 71.16 ;
     RECT  148.504 78.24 153.608 78.408 ;
     RECT  148.504 79.44 153.608 79.464 ;
     RECT  153.608 2.148 153.712 127.452 ;
     RECT  153.712 2.418 153.904 127.182 ;
     RECT  153.904 53.808 159.008 53.832 ;
     RECT  153.904 65.376 159.008 65.4 ;
     RECT  153.904 71.088 159.008 71.16 ;
     RECT  153.904 78.24 159.008 78.408 ;
     RECT  153.904 79.44 159.008 79.464 ;
     RECT  159.008 2.148 159.112 127.452 ;
     RECT  159.112 2.418 159.304 127.182 ;
     RECT  159.304 78.24 162.457 78.408 ;
     RECT  159.304 53.808 164.408 53.832 ;
     RECT  159.304 65.376 164.408 65.4 ;
     RECT  159.304 71.088 164.408 71.16 ;
     RECT  162.457 78.144 164.408 78.456 ;
     RECT  159.304 79.44 164.408 79.464 ;
     RECT  164.408 2.148 164.512 127.452 ;
     RECT  164.512 2.418 164.704 127.182 ;
     RECT  166.453 64.32 166.565 64.344 ;
     RECT  164.704 78.144 166.601 78.456 ;
     RECT  164.704 71.088 166.921 71.16 ;
     RECT  166.601 78.144 167.033 78.408 ;
     RECT  167.065 74.592 167.573 74.616 ;
     RECT  165.805 58.896 167.785 58.92 ;
     RECT  167.641 60.288 167.785 60.312 ;
     RECT  167.785 58.896 167.929 60.312 ;
     RECT  167.033 78.384 167.929 78.408 ;
     RECT  164.704 79.44 167.929 79.464 ;
     RECT  166.921 71.088 168.005 71.352 ;
     RECT  167.929 78.384 168.041 79.464 ;
     RECT  164.704 65.376 168.073 65.4 ;
     RECT  168.037 61.536 168.109 61.56 ;
     RECT  166.957 62.64 168.109 62.664 ;
     RECT  168.073 65.184 168.181 65.4 ;
     RECT  168.005 71.088 168.181 71.16 ;
     RECT  164.704 53.808 168.185 53.832 ;
     RECT  167.713 69.456 168.325 69.48 ;
     RECT  168.217 75.744 168.325 75.768 ;
     RECT  168.181 65.136 168.361 65.4 ;
     RECT  168.181 71.04 168.361 71.16 ;
     RECT  168.325 69.456 168.433 69.528 ;
     RECT  167.929 58.08 168.437 60.312 ;
     RECT  168.109 61.536 168.469 62.664 ;
     RECT  168.361 64.368 168.469 65.4 ;
     RECT  168.433 68.736 168.541 69.528 ;
     RECT  168.469 61.536 168.577 65.4 ;
     RECT  168.541 68.016 168.649 69.528 ;
     RECT  168.361 70.8 168.649 71.16 ;
     RECT  168.613 73.104 168.685 73.128 ;
     RECT  168.577 61.344 168.761 65.4 ;
     RECT  168.649 68.016 168.901 71.16 ;
     RECT  168.685 73.104 168.973 73.368 ;
     RECT  168.761 61.632 169.009 65.4 ;
     RECT  168.901 67.392 169.153 71.16 ;
     RECT  168.041 78.624 169.189 79.464 ;
     RECT  169.117 52.752 169.225 52.776 ;
     RECT  168.973 73.104 169.225 73.56 ;
     RECT  169.225 54.096 169.297 54.12 ;
     RECT  169.225 73.104 169.333 73.656 ;
     RECT  169.153 67.392 169.405 71.208 ;
     RECT  169.333 72.96 169.657 73.656 ;
     RECT  169.405 66.768 169.729 71.208 ;
     RECT  169.189 78.624 169.765 80.04 ;
     RECT  168.437 58.704 169.801 60.312 ;
     RECT  169.225 52.752 169.808 53.016 ;
     RECT  169.297 54.096 169.808 54.408 ;
     RECT  169.081 57.312 169.808 57.336 ;
     RECT  169.801 58.704 169.808 60.36 ;
     RECT  169.009 61.632 169.808 65.496 ;
     RECT  169.729 66.576 169.808 71.208 ;
     RECT  169.657 72.96 169.808 74.088 ;
     RECT  168.325 75.456 169.808 75.768 ;
     RECT  169.765 78.096 169.808 80.04 ;
     RECT  169.585 81.36 169.808 81.384 ;
     RECT  169.808 2.148 169.912 127.452 ;
     RECT  169.912 2.418 170.104 127.182 ;
     RECT  170.104 51.6 170.273 57.336 ;
     RECT  170.104 75.648 170.417 84.744 ;
     RECT  170.104 58.416 170.453 66.6 ;
     RECT  170.453 58.416 171.457 65.064 ;
     RECT  170.453 66.096 171.457 66.6 ;
     RECT  170.417 75.648 171.457 75.672 ;
     RECT  170.417 76.656 171.457 78.312 ;
     RECT  170.417 79.536 171.457 84.744 ;
     RECT  171.457 58.416 171.493 66.6 ;
     RECT  170.104 67.824 171.493 74.664 ;
     RECT  171.457 75.648 171.493 78.312 ;
     RECT  171.457 79.536 171.493 85.224 ;
     RECT  170.273 51.6 171.529 56.616 ;
     RECT  171.493 58.416 171.529 74.664 ;
     RECT  171.529 51.6 171.565 74.664 ;
     RECT  171.493 75.648 171.565 85.224 ;
     RECT  171.565 51.408 172.069 85.224 ;
     RECT  172.069 51.408 172.645 85.32 ;
     RECT  172.645 51.408 172.764 85.512 ;
     RECT  172.764 85.488 172.793 85.512 ;
    LAYER M5 ;
     RECT  79.632 0.016 79.752 0.131 ;
     RECT  79.728 0.131 79.752 1.763 ;
     RECT  2.4 2.137 2.52 2.151 ;
     RECT  7.8 2.137 7.92 2.151 ;
     RECT  13.2 2.137 13.32 2.151 ;
     RECT  18.6 2.137 18.72 2.151 ;
     RECT  24 2.137 24.12 2.151 ;
     RECT  29.4 2.137 29.52 2.151 ;
     RECT  34.8 2.137 34.92 2.151 ;
     RECT  40.2 2.137 40.32 2.151 ;
     RECT  45.6 2.137 45.72 2.151 ;
     RECT  51 2.137 51.12 2.151 ;
     RECT  56.4 2.137 56.52 2.151 ;
     RECT  61.8 2.137 61.92 2.151 ;
     RECT  67.2 2.137 67.32 2.151 ;
     RECT  72.6 2.137 72.72 2.151 ;
     RECT  78 2.137 78.12 2.151 ;
     RECT  83.4 2.137 83.52 2.151 ;
     RECT  88.8 2.137 88.92 2.151 ;
     RECT  94.2 2.137 94.32 2.151 ;
     RECT  99.6 2.137 99.72 2.151 ;
     RECT  105 2.137 105.12 2.151 ;
     RECT  110.4 2.137 110.52 2.151 ;
     RECT  115.8 2.137 115.92 2.151 ;
     RECT  121.2 2.137 121.32 2.151 ;
     RECT  126.6 2.137 126.72 2.151 ;
     RECT  132 2.137 132.12 2.151 ;
     RECT  137.4 2.137 137.52 2.151 ;
     RECT  142.8 2.137 142.92 2.151 ;
     RECT  148.2 2.137 148.32 2.151 ;
     RECT  153.6 2.137 153.72 2.151 ;
     RECT  159 2.137 159.12 2.151 ;
     RECT  164.4 2.137 164.52 2.151 ;
     RECT  169.8 2.137 169.92 2.151 ;
     RECT  78 2.151 78.312 3.925 ;
     RECT  78 3.925 78.408 24.469 ;
     RECT  83.4 2.151 83.712 53.797 ;
     RECT  77.616 24.469 78.408 64.643 ;
     RECT  169.8 2.151 170.112 73.525 ;
     RECT  169.8 73.525 170.424 73.667 ;
     RECT  0.192 58.981 0.216 74.147 ;
     RECT  88.8 2.151 89.112 74.629 ;
     RECT  110.4 2.151 110.712 78.469 ;
     RECT  88.8 74.629 89.976 92.147 ;
     RECT  99.6 2.151 99.912 92.197 ;
     RECT  83.4 53.797 84.456 92.389 ;
     RECT  77.616 64.643 78.312 92.435 ;
     RECT  88.8 92.147 89.544 92.531 ;
     RECT  83.4 92.389 85.224 100.931 ;
     RECT  105 2.151 105.312 109.381 ;
     RECT  105 109.381 106.2 109.717 ;
     RECT  99.6 92.197 100.392 110.293 ;
     RECT  83.4 100.931 84.12 110.533 ;
     RECT  108.576 78.469 108.6 110.533 ;
     RECT  104.448 109.717 106.2 110.579 ;
     RECT  104.448 110.579 105.312 110.771 ;
     RECT  98.736 110.293 100.392 111.061 ;
     RECT  102.816 110.341 102.84 111.155 ;
     RECT  83.232 110.533 84.12 111.347 ;
     RECT  81.552 109.381 81.576 111.541 ;
     RECT  107.616 110.533 108.6 111.587 ;
     RECT  83.4 111.347 84.12 111.685 ;
     RECT  85.2 100.931 85.224 111.685 ;
     RECT  97.872 111.061 100.392 111.685 ;
     RECT  83.4 111.685 85.224 111.731 ;
     RECT  81.552 111.541 82.104 112.021 ;
     RECT  88.8 92.531 89.112 112.213 ;
     RECT  80.688 112.021 82.104 112.403 ;
     RECT  105 110.771 105.312 112.501 ;
     RECT  78 92.435 78.312 112.645 ;
     RECT  83.4 111.731 84.984 112.645 ;
     RECT  80.688 112.403 81.576 112.837 ;
     RECT  108.576 111.587 108.6 112.837 ;
     RECT  97.872 111.685 101.016 112.883 ;
     RECT  100.992 112.883 101.016 112.931 ;
     RECT  88.704 112.213 89.112 112.979 ;
     RECT  108 112.837 108.6 113.029 ;
     RECT  110.4 78.469 111.48 113.029 ;
     RECT  77.904 112.645 78.312 113.077 ;
     RECT  72.6 2.151 72.912 113.797 ;
     RECT  115.8 2.151 116.112 113.893 ;
     RECT  72.144 113.797 72.912 113.989 ;
     RECT  102.288 112.837 102.312 113.989 ;
     RECT  80.352 112.837 81.576 114.035 ;
     RECT  108 113.029 111.48 114.035 ;
     RECT  94.2 2.151 94.512 114.277 ;
     RECT  103.728 112.501 103.752 114.323 ;
     RECT  80.688 114.035 81.576 114.517 ;
     RECT  82.992 112.645 84.984 114.517 ;
     RECT  108.576 114.035 111.48 114.517 ;
     RECT  101.472 113.989 102.312 114.611 ;
     RECT  108.576 114.517 112.248 114.611 ;
     RECT  86.448 111.973 86.472 114.947 ;
     RECT  72.144 113.989 73.464 114.949 ;
     RECT  110.4 114.611 112.248 115.045 ;
     RECT  93.648 114.277 94.512 115.093 ;
     RECT  108.576 114.611 108.6 115.093 ;
     RECT  115.104 113.893 116.112 115.139 ;
     RECT  80.688 114.517 84.984 115.187 ;
     RECT  102.288 114.611 102.312 115.187 ;
     RECT  105 112.501 105.432 115.187 ;
     RECT  67.2 2.151 67.512 115.525 ;
     RECT  61.8 2.151 62.112 115.621 ;
     RECT  115.392 115.139 116.112 115.669 ;
     RECT  77.904 113.077 79.272 115.717 ;
     RECT  115.392 115.669 116.76 115.763 ;
     RECT  92.736 115.093 94.512 115.859 ;
     RECT  66.72 115.525 67.512 115.955 ;
     RECT  72.144 114.949 74.088 115.955 ;
     RECT  110.4 115.045 113.016 115.957 ;
     RECT  82.992 115.187 84.984 116.053 ;
     RECT  82.992 116.053 85.224 116.099 ;
     RECT  103.536 116.005 103.56 116.197 ;
     RECT  108.24 115.093 108.6 116.197 ;
     RECT  73.968 115.955 74.088 116.293 ;
     RECT  82.992 116.099 84.12 116.339 ;
     RECT  96.864 114.997 96.888 116.339 ;
     RECT  61.8 115.621 62.856 116.437 ;
     RECT  68.976 115.525 69 116.483 ;
     RECT  73.968 116.293 74.712 116.483 ;
     RECT  97.872 112.883 100.008 116.581 ;
     RECT  86.304 115.381 86.328 116.675 ;
     RECT  109.728 115.957 113.016 116.675 ;
     RECT  97.872 116.581 100.536 116.725 ;
     RECT  76.704 111.637 76.728 116.821 ;
     RECT  93.648 115.859 94.512 116.821 ;
     RECT  112.992 116.675 113.016 117.011 ;
     RECT  97.344 116.725 100.536 117.109 ;
     RECT  61.584 116.437 63.432 117.251 ;
     RECT  77.904 115.717 79.464 117.251 ;
     RECT  76.704 116.821 76.92 117.349 ;
     RECT  77.904 117.251 79.272 117.349 ;
     RECT  85.2 116.099 85.224 117.397 ;
     RECT  61.584 117.251 62.856 117.779 ;
     RECT  97.344 117.109 100.824 117.925 ;
     RECT  84.912 117.397 85.224 117.971 ;
     RECT  96.528 117.925 100.824 117.971 ;
     RECT  76.704 117.349 79.272 118.021 ;
     RECT  88.8 112.979 89.112 118.021 ;
     RECT  82.992 116.339 83.712 118.165 ;
     RECT  88.8 118.021 89.304 118.357 ;
     RECT  109.728 116.675 111.48 118.403 ;
     RECT  115.8 115.763 116.76 118.501 ;
     RECT  103.536 116.197 103.752 118.547 ;
     RECT  76.512 118.021 79.272 118.595 ;
     RECT  87.216 117.349 87.24 118.595 ;
     RECT  92.88 116.821 94.512 118.595 ;
     RECT  113.424 117.973 113.448 118.595 ;
     RECT  105 115.187 105.312 118.693 ;
     RECT  106.32 117.253 106.344 118.693 ;
     RECT  85.2 117.971 85.224 118.837 ;
     RECT  82.992 118.165 83.928 118.885 ;
     RECT  103.536 118.547 103.56 118.933 ;
     RECT  80.688 115.187 81.576 119.029 ;
     RECT  82.704 118.885 83.928 119.029 ;
     RECT  93.648 118.595 94.512 119.077 ;
     RECT  102.336 115.621 102.36 119.077 ;
     RECT  108.24 116.197 108.696 119.077 ;
     RECT  102.096 119.077 102.36 119.173 ;
     RECT  109.728 118.403 111.432 119.221 ;
     RECT  63.984 118.741 64.008 119.411 ;
     RECT  93.648 119.077 95.448 119.461 ;
     RECT  96.528 117.971 100.008 119.461 ;
     RECT  101.328 119.173 102.36 119.507 ;
     RECT  72.144 115.955 72.912 119.605 ;
     RECT  73.968 116.483 74.088 119.605 ;
     RECT  76.704 118.595 79.272 119.605 ;
     RECT  91.536 116.245 91.56 119.605 ;
     RECT  65.904 118.213 65.928 119.653 ;
     RECT  67.2 115.955 67.512 119.653 ;
     RECT  70.032 119.125 70.056 119.653 ;
     RECT  76.704 119.605 79.704 119.653 ;
     RECT  80.688 119.029 83.928 119.653 ;
     RECT  113.952 119.029 113.976 119.699 ;
     RECT  101.952 119.507 102.36 119.701 ;
     RECT  103.344 118.933 103.56 119.701 ;
     RECT  72.144 119.605 74.088 119.845 ;
     RECT  70.032 119.653 70.296 120.085 ;
     RECT  71.76 119.845 74.088 120.085 ;
     RECT  70.032 120.085 74.088 120.179 ;
     RECT  70.272 120.179 74.088 120.275 ;
     RECT  109.68 119.221 111.432 120.467 ;
     RECT  76.704 119.653 83.928 120.517 ;
     RECT  108.144 119.077 108.696 120.661 ;
     RECT  109.68 120.467 110.952 120.661 ;
     RECT  58.656 116.725 58.68 120.709 ;
     RECT  101.952 119.701 103.56 120.755 ;
     RECT  58.656 120.709 59.4 120.805 ;
     RECT  87.744 118.981 87.768 120.805 ;
     RECT  88.8 118.357 89.4 120.805 ;
     RECT  76.128 120.517 83.928 120.853 ;
     RECT  85.2 118.837 86.088 120.853 ;
     RECT  93.648 119.461 100.008 120.899 ;
     RECT  101.952 120.755 102.12 120.899 ;
     RECT  117.936 119.269 117.96 120.899 ;
     RECT  87.744 120.805 89.4 121.045 ;
     RECT  91.104 119.605 91.56 121.045 ;
     RECT  76.128 120.853 86.088 121.091 ;
     RECT  65.904 119.653 67.512 121.093 ;
     RECT  108.144 120.661 110.952 121.141 ;
     RECT  87.744 121.045 91.56 121.187 ;
     RECT  65.712 121.093 67.512 121.333 ;
     RECT  70.272 120.275 72.912 121.333 ;
     RECT  74.064 120.275 74.088 121.333 ;
     RECT  76.128 121.091 83.928 121.333 ;
     RECT  85.2 121.091 86.088 121.333 ;
     RECT  91.104 121.187 91.56 121.333 ;
     RECT  93.648 120.899 96.312 121.333 ;
     RECT  93.504 121.333 96.312 121.379 ;
     RECT  68.88 120.805 68.904 121.381 ;
     RECT  58.656 120.805 60.312 121.427 ;
     RECT  85.2 121.333 86.376 121.427 ;
     RECT  97.44 120.899 100.008 121.429 ;
     RECT  96.288 121.379 96.312 121.475 ;
     RECT  107.664 121.141 110.952 121.571 ;
     RECT  61.8 117.779 62.856 121.669 ;
     RECT  65.52 121.333 67.512 121.669 ;
     RECT  75.792 121.333 83.928 121.669 ;
     RECT  105 118.693 106.344 121.669 ;
     RECT  107.664 121.571 110.712 121.717 ;
     RECT  97.44 121.429 100.056 121.861 ;
     RECT  70.272 121.333 74.088 121.909 ;
     RECT  75.36 121.669 83.928 121.909 ;
     RECT  91.104 121.333 91.992 121.957 ;
     RECT  93.504 121.379 95.304 121.957 ;
     RECT  119.136 120.229 119.16 121.957 ;
     RECT  65.52 121.669 67.848 122.003 ;
     RECT  119.136 121.957 119.688 122.003 ;
     RECT  67.104 122.003 67.848 122.051 ;
     RECT  70.272 121.909 83.928 122.099 ;
     RECT  87.744 121.187 90.072 122.147 ;
     RECT  61.8 121.669 63.096 122.149 ;
     RECT  88.8 122.147 90.072 122.243 ;
     RECT  61.488 122.149 63.096 122.245 ;
     RECT  56.4 2.151 56.712 122.389 ;
     RECT  85.2 121.427 85.224 122.437 ;
     RECT  86.352 121.427 86.376 122.437 ;
     RECT  61.488 122.245 63.384 122.485 ;
     RECT  104.88 121.669 106.344 122.485 ;
     RECT  107.616 121.717 110.712 122.485 ;
     RECT  111.936 121.957 111.96 122.485 ;
     RECT  102.096 120.899 102.12 122.579 ;
     RECT  119.664 122.003 119.688 122.579 ;
     RECT  56.4 122.389 57.096 122.773 ;
     RECT  82.704 122.099 83.928 122.821 ;
     RECT  85.2 122.437 86.376 122.821 ;
     RECT  70.272 122.099 80.712 123.059 ;
     RECT  58.656 121.427 59.832 123.061 ;
     RECT  60.816 122.485 63.384 123.061 ;
     RECT  82.704 122.821 86.376 123.061 ;
     RECT  113.856 120.757 113.88 123.061 ;
     RECT  115.8 118.501 116.808 123.061 ;
     RECT  65.52 122.003 65.736 123.109 ;
     RECT  91.104 121.957 95.304 123.155 ;
     RECT  118.56 122.773 118.584 123.155 ;
     RECT  96.96 121.861 100.056 123.301 ;
     RECT  82.08 123.061 86.376 123.349 ;
     RECT  87.744 122.147 87.768 123.349 ;
     RECT  82.08 123.349 87.768 123.443 ;
     RECT  96.96 123.301 100.824 123.541 ;
     RECT  103.536 120.755 103.56 123.589 ;
     RECT  104.88 122.485 110.712 123.589 ;
     RECT  56.4 122.773 57.288 123.637 ;
     RECT  58.656 123.061 63.384 123.637 ;
     RECT  96.432 123.541 100.824 123.683 ;
     RECT  111.936 122.485 112.296 123.731 ;
     RECT  113.856 123.061 114.6 123.877 ;
     RECT  115.8 123.061 117.096 123.877 ;
     RECT  93.648 123.155 95.304 123.925 ;
     RECT  113.856 123.877 117.096 123.971 ;
     RECT  68.88 121.381 69.24 124.069 ;
     RECT  70.272 123.059 76.728 124.069 ;
     RECT  111.936 123.731 112.008 124.117 ;
     RECT  65.424 123.109 65.736 124.165 ;
     RECT  77.904 123.059 80.712 124.165 ;
     RECT  56.4 123.637 63.384 124.213 ;
     RECT  68.88 124.069 76.728 124.213 ;
     RECT  77.76 124.165 80.712 124.213 ;
     RECT  67.104 122.051 67.512 124.259 ;
     RECT  114.576 123.971 117.096 124.261 ;
     RECT  91.104 123.155 92.136 124.307 ;
     RECT  56.4 124.213 63.72 124.357 ;
     RECT  65.04 124.165 65.736 124.357 ;
     RECT  82.08 123.443 87.192 124.453 ;
     RECT  88.8 122.243 89.976 124.453 ;
     RECT  82.08 124.453 89.976 124.645 ;
     RECT  96.96 123.683 100.824 124.645 ;
     RECT  103.536 123.589 110.712 124.645 ;
     RECT  82.08 124.645 90.024 124.693 ;
     RECT  103.152 124.645 110.712 124.693 ;
     RECT  91.824 124.307 92.136 124.741 ;
     RECT  96.96 124.645 101.256 124.741 ;
     RECT  91.824 124.741 92.568 124.789 ;
     RECT  93.648 123.925 95.976 124.789 ;
     RECT  96.96 124.741 101.832 124.789 ;
     RECT  102.96 124.693 110.712 124.789 ;
     RECT  111.744 124.117 112.008 124.789 ;
     RECT  114.576 124.261 118.008 124.883 ;
     RECT  82.08 124.693 90.6 125.077 ;
     RECT  67.2 124.259 67.512 125.221 ;
     RECT  68.88 124.213 80.712 125.221 ;
     RECT  81.84 125.077 90.6 125.221 ;
     RECT  102.96 124.789 112.008 125.221 ;
     RECT  56.4 124.357 65.736 125.365 ;
     RECT  115.296 124.883 118.008 125.411 ;
     RECT  91.824 124.789 101.832 125.461 ;
     RECT  55.824 125.365 65.736 125.507 ;
     RECT  91.728 125.461 101.832 125.749 ;
     RECT  102.816 125.221 112.008 125.749 ;
     RECT  67.2 125.221 90.6 125.893 ;
     RECT  117.168 125.411 118.008 125.987 ;
     RECT  117.984 125.987 118.008 126.419 ;
     RECT  55.824 125.507 64.152 126.469 ;
     RECT  65.232 125.507 65.496 126.469 ;
     RECT  66.624 125.893 90.6 126.469 ;
     RECT  118.464 126.517 118.488 126.659 ;
     RECT  91.728 125.749 112.008 126.707 ;
     RECT  91.728 126.707 111.72 126.709 ;
     RECT  55.824 126.469 90.6 126.805 ;
     RECT  55.728 126.805 90.6 127.093 ;
     RECT  91.632 126.709 111.72 127.093 ;
     RECT  55.728 127.093 111.72 127.139 ;
     RECT  115.296 125.411 116.112 127.139 ;
     RECT  55.728 127.139 111.336 127.429 ;
     RECT  2.4 2.151 2.712 127.449 ;
     RECT  7.8 2.151 8.112 127.449 ;
     RECT  13.2 2.151 13.512 127.449 ;
     RECT  18.6 2.151 18.912 127.449 ;
     RECT  24 2.151 24.312 127.449 ;
     RECT  29.4 2.151 29.712 127.449 ;
     RECT  34.8 2.151 35.112 127.449 ;
     RECT  40.2 2.151 40.512 127.449 ;
     RECT  45.6 2.151 45.912 127.449 ;
     RECT  51 2.151 51.312 127.449 ;
     RECT  115.8 127.139 116.112 127.449 ;
     RECT  121.2 2.151 121.512 127.449 ;
     RECT  126.6 2.151 126.912 127.449 ;
     RECT  132 2.151 132.312 127.449 ;
     RECT  137.4 2.151 137.712 127.449 ;
     RECT  142.8 2.151 143.112 127.449 ;
     RECT  148.2 2.151 148.512 127.449 ;
     RECT  153.6 2.151 153.912 127.449 ;
     RECT  159 2.151 159.312 127.449 ;
     RECT  164.4 2.151 164.712 127.449 ;
     RECT  169.8 73.667 170.112 127.449 ;
     RECT  2.4 127.449 2.52 127.463 ;
     RECT  7.8 127.449 7.92 127.463 ;
     RECT  13.2 127.449 13.32 127.463 ;
     RECT  18.6 127.449 18.72 127.463 ;
     RECT  24 127.449 24.12 127.463 ;
     RECT  29.4 127.449 29.52 127.463 ;
     RECT  34.8 127.449 34.92 127.463 ;
     RECT  40.2 127.449 40.32 127.463 ;
     RECT  45.6 127.449 45.72 127.463 ;
     RECT  51 127.449 51.12 127.463 ;
     RECT  115.8 127.449 115.92 127.463 ;
     RECT  121.2 127.449 121.32 127.463 ;
     RECT  126.6 127.449 126.72 127.463 ;
     RECT  132 127.449 132.12 127.463 ;
     RECT  137.4 127.449 137.52 127.463 ;
     RECT  142.8 127.449 142.92 127.463 ;
     RECT  148.2 127.449 148.32 127.463 ;
     RECT  153.6 127.449 153.72 127.463 ;
     RECT  159 127.449 159.12 127.463 ;
     RECT  164.4 127.449 164.52 127.463 ;
     RECT  169.8 127.449 169.92 127.463 ;
     RECT  55.632 127.429 111.336 127.525 ;
     RECT  55.536 127.525 111.336 127.573 ;
     RECT  55.44 127.573 111.336 127.621 ;
     RECT  55.344 127.621 111.336 129.552 ;
     RECT  84.12 100.931 85.2 111.685 ;
     RECT  106.2 110.533 107.616 110.579 ;
     RECT  83.232 111.347 83.4 111.541 ;
     RECT  82.104 111.541 83.4 112.403 ;
     RECT  108 111.587 108.576 112.837 ;
     RECT  76.728 111.637 78 112.645 ;
     RECT  84.984 111.731 85.224 111.973 ;
     RECT  84.984 111.973 86.448 114.947 ;
     RECT  81.576 112.403 83.4 112.645 ;
     RECT  103.752 112.501 105 114.323 ;
     RECT  76.728 112.645 77.904 116.821 ;
     RECT  81.576 112.645 82.992 114.517 ;
     RECT  101.016 112.837 102.288 112.931 ;
     RECT  102.312 112.837 103.728 114.323 ;
     RECT  100.008 112.883 100.992 112.931 ;
     RECT  100.008 112.931 102.288 113.989 ;
     RECT  79.272 113.077 80.352 114.035 ;
     RECT  100.008 113.989 101.472 114.611 ;
     RECT  79.272 114.035 80.688 115.717 ;
     RECT  108.24 114.035 108.576 115.093 ;
     RECT  102.312 114.323 102.36 115.187 ;
     RECT  108.6 114.611 110.4 115.957 ;
     RECT  84.984 114.947 86.328 115.381 ;
     RECT  96.888 114.997 97.872 116.339 ;
     RECT  81.576 115.187 82.992 118.885 ;
     RECT  102.336 115.187 102.36 115.621 ;
     RECT  84.984 115.381 86.304 116.053 ;
     RECT  67.512 115.525 68.976 116.483 ;
     RECT  79.464 115.717 80.688 117.251 ;
     RECT  92.736 115.859 93.648 116.245 ;
     RECT  72.912 115.955 73.968 119.605 ;
     RECT  108.6 115.957 109.728 116.197 ;
     RECT  102.36 116.005 103.536 118.933 ;
     RECT  103.56 116.005 105 116.197 ;
     RECT  85.224 116.053 86.304 116.675 ;
     RECT  84.12 116.099 85.2 116.339 ;
     RECT  103.752 116.197 105 118.547 ;
     RECT  108.696 116.197 109.728 119.221 ;
     RECT  91.56 116.245 93.648 116.821 ;
     RECT  83.712 116.339 85.2 117.397 ;
     RECT  97.344 116.339 97.872 116.725 ;
     RECT  111.48 116.675 112.992 117.011 ;
     RECT  76.92 116.821 77.904 117.349 ;
     RECT  91.56 116.821 92.88 118.595 ;
     RECT  100.824 117.109 102.336 117.971 ;
     RECT  62.856 117.251 63.432 118.741 ;
     RECT  79.272 117.251 80.688 119.605 ;
     RECT  105.312 117.253 106.32 118.693 ;
     RECT  83.712 117.397 84.912 117.971 ;
     RECT  83.712 117.971 85.2 118.165 ;
     RECT  100.008 117.971 102.336 119.077 ;
     RECT  83.928 118.165 85.2 120.853 ;
     RECT  65.928 118.213 67.2 119.653 ;
     RECT  103.56 118.547 105 121.669 ;
     RECT  62.856 118.741 63.984 119.411 ;
     RECT  81.576 118.885 82.704 119.029 ;
     RECT  102.36 118.933 103.344 119.701 ;
     RECT  87.768 118.981 88.8 120.805 ;
     RECT  95.448 119.077 96.528 119.461 ;
     RECT  100.008 119.077 102.096 119.173 ;
     RECT  100.008 119.173 101.328 119.507 ;
     RECT  108.696 119.221 109.68 120.661 ;
     RECT  116.808 119.269 117.936 120.899 ;
     RECT  79.704 119.605 80.688 119.653 ;
     RECT  70.296 119.845 71.76 120.085 ;
     RECT  70.032 120.179 70.272 120.805 ;
     RECT  117.96 120.229 119.136 120.899 ;
     RECT  72.912 120.275 74.064 121.333 ;
     RECT  110.952 120.467 111.432 121.571 ;
     RECT  102.12 120.755 103.536 122.579 ;
     RECT  60.312 120.805 61.8 121.427 ;
     RECT  67.512 120.805 68.88 121.669 ;
     RECT  68.904 120.805 70.272 121.381 ;
     RECT  96.312 120.899 97.44 121.475 ;
     RECT  83.928 121.091 85.2 122.821 ;
     RECT  106.344 121.141 107.664 121.717 ;
     RECT  90.072 121.187 91.104 122.243 ;
     RECT  86.376 121.333 87.744 123.349 ;
     RECT  91.992 121.333 93.504 121.957 ;
     RECT  95.304 121.379 96.288 121.475 ;
     RECT  69.24 121.381 70.272 124.069 ;
     RECT  59.832 121.427 61.8 122.149 ;
     RECT  85.224 121.427 86.352 122.437 ;
     RECT  96.96 121.475 97.44 121.861 ;
     RECT  110.712 121.571 111.432 121.957 ;
     RECT  67.848 121.669 68.88 122.051 ;
     RECT  74.088 121.669 75.36 121.909 ;
     RECT  103.56 121.669 104.88 123.589 ;
     RECT  106.344 121.717 107.616 122.485 ;
     RECT  110.712 121.957 111.936 124.117 ;
     RECT  119.688 121.957 121.2 122.579 ;
     RECT  65.736 122.003 67.104 124.259 ;
     RECT  67.512 122.051 68.88 125.221 ;
     RECT  80.712 122.099 82.704 123.061 ;
     RECT  87.768 122.147 88.8 123.443 ;
     RECT  59.832 122.149 61.488 122.485 ;
     RECT  89.976 122.243 91.104 124.307 ;
     RECT  59.832 122.485 60.816 123.061 ;
     RECT  57.288 122.773 58.656 123.637 ;
     RECT  76.728 123.059 77.904 124.165 ;
     RECT  80.712 123.061 82.08 125.077 ;
     RECT  114.6 123.061 115.8 123.877 ;
     RECT  117.096 123.061 118.56 123.155 ;
     RECT  92.136 123.155 93.648 124.741 ;
     RECT  117.096 123.155 118.008 124.261 ;
     RECT  87.192 123.443 88.8 124.453 ;
     RECT  95.304 123.541 96.432 123.683 ;
     RECT  95.304 123.683 96.96 123.925 ;
     RECT  95.976 123.925 96.96 124.789 ;
     RECT  110.712 124.117 111.744 124.789 ;
     RECT  76.728 124.165 77.76 124.213 ;
     RECT  63.72 124.213 65.04 124.357 ;
     RECT  65.736 124.259 67.2 125.507 ;
     RECT  89.976 124.307 91.824 124.645 ;
     RECT  90.024 124.645 91.824 124.693 ;
     RECT  90.6 124.693 91.824 125.461 ;
     RECT  92.568 124.741 93.648 124.789 ;
     RECT  101.832 124.741 102.96 125.221 ;
     RECT  80.712 125.077 81.84 125.221 ;
     RECT  101.832 125.221 102.816 125.749 ;
     RECT  116.112 125.411 117.168 125.987 ;
     RECT  90.6 125.461 91.728 126.709 ;
     RECT  64.152 125.507 65.232 126.469 ;
     RECT  65.496 125.507 67.2 125.893 ;
     RECT  65.496 125.893 66.624 126.469 ;
     RECT  90.6 126.709 91.632 127.093 ;
  END
END ot_hgi_sm_pub_vmmerge
END LIBRARY
